VERSION 5.8 ;
BUSBITCHARS "[]" ;
DIVIDERCHAR "/" ;
UNITS
    DATABASE MICRONS 1000 ;
END UNITS

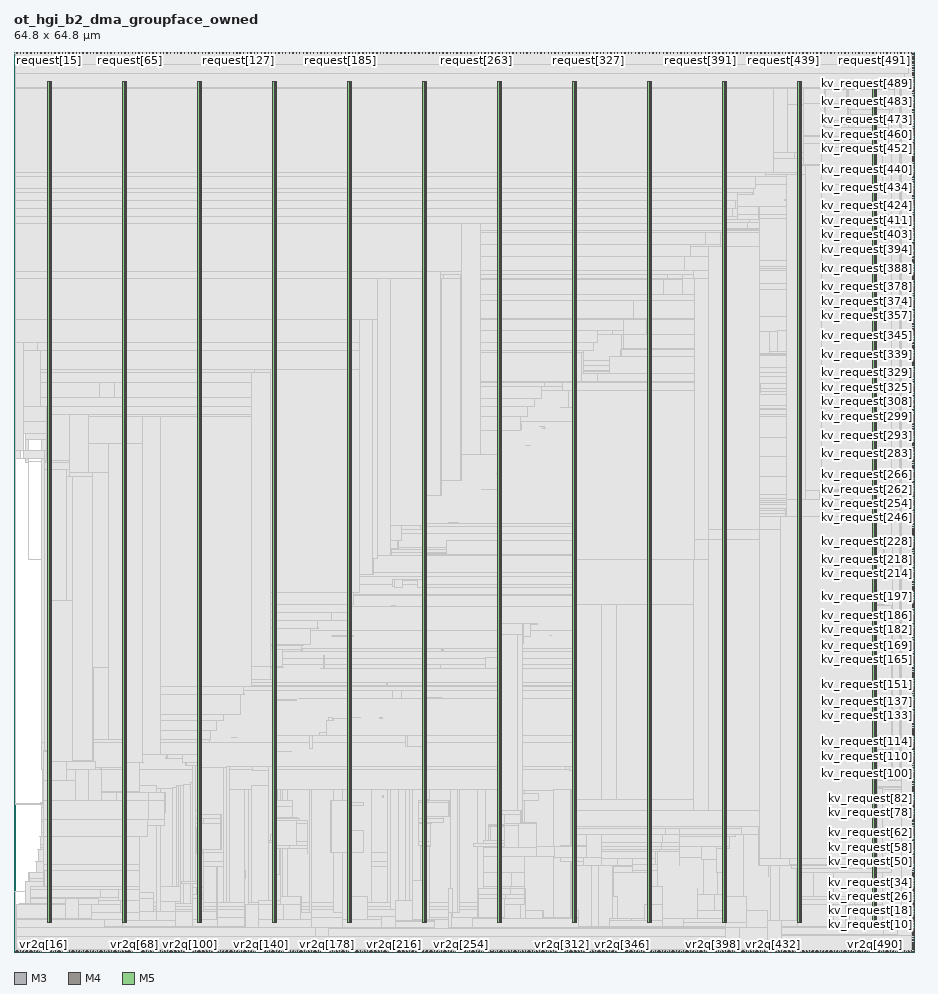
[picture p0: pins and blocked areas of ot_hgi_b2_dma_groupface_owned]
MACRO ot_hgi_b2_dma_groupface_owned
  FOREIGN ot_hgi_b2_dma_groupface_owned 0 0 ;
  CLASS BLOCK ;
  SIZE 64.8 BY 64.8 ;
  PIN clk
    DIRECTION INPUT ;
    USE SIGNAL ;
    PORT
      LAYER M3 ;
        RECT  0.072 64.762 0.09 64.8 ;
    END
  END clk
  PIN kv_owned
    DIRECTION INPUT ;
    USE SIGNAL ;
    PORT
      LAYER M4 ;
        RECT  64.716 0.048 64.8 0.072 ;
    END
  END kv_owned
  PIN kv_request[0]
    DIRECTION INPUT ;
    USE SIGNAL ;
    PORT
      LAYER M4 ;
        RECT  64.716 0.192 64.8 0.216 ;
    END
  END kv_request[0]
  PIN kv_request[100]
    DIRECTION INPUT ;
    USE SIGNAL ;
    PORT
      LAYER M4 ;
        RECT  64.716 12.816 64.8 12.84 ;
    END
  END kv_request[100]
  PIN kv_request[101]
    DIRECTION INPUT ;
    USE SIGNAL ;
    PORT
      LAYER M4 ;
        RECT  64.716 12.912 64.8 12.936 ;
    END
  END kv_request[101]
  PIN kv_request[102]
    DIRECTION INPUT ;
    USE SIGNAL ;
    PORT
      LAYER M4 ;
        RECT  64.716 13.056 64.8 13.08 ;
    END
  END kv_request[102]
  PIN kv_request[103]
    DIRECTION INPUT ;
    USE SIGNAL ;
    PORT
      LAYER M4 ;
        RECT  64.716 13.2 64.8 13.224 ;
    END
  END kv_request[103]
  PIN kv_request[104]
    DIRECTION INPUT ;
    USE SIGNAL ;
    PORT
      LAYER M4 ;
        RECT  64.716 13.296 64.8 13.32 ;
    END
  END kv_request[104]
  PIN kv_request[105]
    DIRECTION INPUT ;
    USE SIGNAL ;
    PORT
      LAYER M4 ;
        RECT  64.716 13.44 64.8 13.464 ;
    END
  END kv_request[105]
  PIN kv_request[106]
    DIRECTION INPUT ;
    USE SIGNAL ;
    PORT
      LAYER M4 ;
        RECT  64.716 13.584 64.8 13.608 ;
    END
  END kv_request[106]
  PIN kv_request[107]
    DIRECTION INPUT ;
    USE SIGNAL ;
    PORT
      LAYER M4 ;
        RECT  64.716 13.68 64.8 13.704 ;
    END
  END kv_request[107]
  PIN kv_request[108]
    DIRECTION INPUT ;
    USE SIGNAL ;
    PORT
      LAYER M4 ;
        RECT  64.716 13.824 64.8 13.848 ;
    END
  END kv_request[108]
  PIN kv_request[109]
    DIRECTION INPUT ;
    USE SIGNAL ;
    PORT
      LAYER M4 ;
        RECT  64.716 13.968 64.8 13.992 ;
    END
  END kv_request[109]
  PIN kv_request[10]
    DIRECTION INPUT ;
    USE SIGNAL ;
    PORT
      LAYER M4 ;
        RECT  64.716 1.44 64.8 1.464 ;
    END
  END kv_request[10]
  PIN kv_request[110]
    DIRECTION INPUT ;
    USE SIGNAL ;
    PORT
      LAYER M4 ;
        RECT  64.716 14.064 64.8 14.088 ;
    END
  END kv_request[110]
  PIN kv_request[111]
    DIRECTION INPUT ;
    USE SIGNAL ;
    PORT
      LAYER M4 ;
        RECT  64.716 14.208 64.8 14.232 ;
    END
  END kv_request[111]
  PIN kv_request[112]
    DIRECTION INPUT ;
    USE SIGNAL ;
    PORT
      LAYER M4 ;
        RECT  64.716 14.304 64.8 14.328 ;
    END
  END kv_request[112]
  PIN kv_request[113]
    DIRECTION INPUT ;
    USE SIGNAL ;
    PORT
      LAYER M4 ;
        RECT  64.716 14.448 64.8 14.472 ;
    END
  END kv_request[113]
  PIN kv_request[114]
    DIRECTION INPUT ;
    USE SIGNAL ;
    PORT
      LAYER M4 ;
        RECT  64.716 14.592 64.8 14.616 ;
    END
  END kv_request[114]
  PIN kv_request[115]
    DIRECTION INPUT ;
    USE SIGNAL ;
    PORT
      LAYER M4 ;
        RECT  64.716 14.688 64.8 14.712 ;
    END
  END kv_request[115]
  PIN kv_request[116]
    DIRECTION INPUT ;
    USE SIGNAL ;
    PORT
      LAYER M4 ;
        RECT  64.716 14.832 64.8 14.856 ;
    END
  END kv_request[116]
  PIN kv_request[117]
    DIRECTION INPUT ;
    USE SIGNAL ;
    PORT
      LAYER M4 ;
        RECT  64.716 14.976 64.8 15 ;
    END
  END kv_request[117]
  PIN kv_request[118]
    DIRECTION INPUT ;
    USE SIGNAL ;
    PORT
      LAYER M4 ;
        RECT  64.716 15.072 64.8 15.096 ;
    END
  END kv_request[118]
  PIN kv_request[119]
    DIRECTION INPUT ;
    USE SIGNAL ;
    PORT
      LAYER M4 ;
        RECT  64.716 15.216 64.8 15.24 ;
    END
  END kv_request[119]
  PIN kv_request[11]
    DIRECTION INPUT ;
    USE SIGNAL ;
    PORT
      LAYER M4 ;
        RECT  64.716 1.584 64.8 1.608 ;
    END
  END kv_request[11]
  PIN kv_request[120]
    DIRECTION INPUT ;
    USE SIGNAL ;
    PORT
      LAYER M4 ;
        RECT  64.716 15.312 64.8 15.336 ;
    END
  END kv_request[120]
  PIN kv_request[121]
    DIRECTION INPUT ;
    USE SIGNAL ;
    PORT
      LAYER M4 ;
        RECT  64.716 15.456 64.8 15.48 ;
    END
  END kv_request[121]
  PIN kv_request[122]
    DIRECTION INPUT ;
    USE SIGNAL ;
    PORT
      LAYER M4 ;
        RECT  64.716 15.6 64.8 15.624 ;
    END
  END kv_request[122]
  PIN kv_request[123]
    DIRECTION INPUT ;
    USE SIGNAL ;
    PORT
      LAYER M4 ;
        RECT  64.716 15.696 64.8 15.72 ;
    END
  END kv_request[123]
  PIN kv_request[124]
    DIRECTION INPUT ;
    USE SIGNAL ;
    PORT
      LAYER M4 ;
        RECT  64.716 15.84 64.8 15.864 ;
    END
  END kv_request[124]
  PIN kv_request[125]
    DIRECTION INPUT ;
    USE SIGNAL ;
    PORT
      LAYER M4 ;
        RECT  64.716 15.984 64.8 16.008 ;
    END
  END kv_request[125]
  PIN kv_request[126]
    DIRECTION INPUT ;
    USE SIGNAL ;
    PORT
      LAYER M4 ;
        RECT  64.716 16.08 64.8 16.104 ;
    END
  END kv_request[126]
  PIN kv_request[127]
    DIRECTION INPUT ;
    USE SIGNAL ;
    PORT
      LAYER M4 ;
        RECT  64.716 16.224 64.8 16.248 ;
    END
  END kv_request[127]
  PIN kv_request[128]
    DIRECTION INPUT ;
    USE SIGNAL ;
    PORT
      LAYER M4 ;
        RECT  64.716 16.368 64.8 16.392 ;
    END
  END kv_request[128]
  PIN kv_request[129]
    DIRECTION INPUT ;
    USE SIGNAL ;
    PORT
      LAYER M4 ;
        RECT  64.716 16.464 64.8 16.488 ;
    END
  END kv_request[129]
  PIN kv_request[12]
    DIRECTION INPUT ;
    USE SIGNAL ;
    PORT
      LAYER M4 ;
        RECT  64.716 1.68 64.8 1.704 ;
    END
  END kv_request[12]
  PIN kv_request[130]
    DIRECTION INPUT ;
    USE SIGNAL ;
    PORT
      LAYER M4 ;
        RECT  64.716 16.608 64.8 16.632 ;
    END
  END kv_request[130]
  PIN kv_request[131]
    DIRECTION INPUT ;
    USE SIGNAL ;
    PORT
      LAYER M4 ;
        RECT  64.716 16.704 64.8 16.728 ;
    END
  END kv_request[131]
  PIN kv_request[132]
    DIRECTION INPUT ;
    USE SIGNAL ;
    PORT
      LAYER M4 ;
        RECT  64.716 16.848 64.8 16.872 ;
    END
  END kv_request[132]
  PIN kv_request[133]
    DIRECTION INPUT ;
    USE SIGNAL ;
    PORT
      LAYER M4 ;
        RECT  64.716 16.992 64.8 17.016 ;
    END
  END kv_request[133]
  PIN kv_request[134]
    DIRECTION INPUT ;
    USE SIGNAL ;
    PORT
      LAYER M4 ;
        RECT  64.716 17.088 64.8 17.112 ;
    END
  END kv_request[134]
  PIN kv_request[135]
    DIRECTION INPUT ;
    USE SIGNAL ;
    PORT
      LAYER M4 ;
        RECT  64.716 17.232 64.8 17.256 ;
    END
  END kv_request[135]
  PIN kv_request[136]
    DIRECTION INPUT ;
    USE SIGNAL ;
    PORT
      LAYER M4 ;
        RECT  64.716 17.376 64.8 17.4 ;
    END
  END kv_request[136]
  PIN kv_request[137]
    DIRECTION INPUT ;
    USE SIGNAL ;
    PORT
      LAYER M4 ;
        RECT  64.716 17.472 64.8 17.496 ;
    END
  END kv_request[137]
  PIN kv_request[138]
    DIRECTION INPUT ;
    USE SIGNAL ;
    PORT
      LAYER M4 ;
        RECT  64.716 17.616 64.8 17.64 ;
    END
  END kv_request[138]
  PIN kv_request[139]
    DIRECTION INPUT ;
    USE SIGNAL ;
    PORT
      LAYER M4 ;
        RECT  64.716 17.712 64.8 17.736 ;
    END
  END kv_request[139]
  PIN kv_request[13]
    DIRECTION INPUT ;
    USE SIGNAL ;
    PORT
      LAYER M4 ;
        RECT  64.716 1.824 64.8 1.848 ;
    END
  END kv_request[13]
  PIN kv_request[140]
    DIRECTION INPUT ;
    USE SIGNAL ;
    PORT
      LAYER M4 ;
        RECT  64.716 17.856 64.8 17.88 ;
    END
  END kv_request[140]
  PIN kv_request[141]
    DIRECTION INPUT ;
    USE SIGNAL ;
    PORT
      LAYER M4 ;
        RECT  64.716 18 64.8 18.024 ;
    END
  END kv_request[141]
  PIN kv_request[142]
    DIRECTION INPUT ;
    USE SIGNAL ;
    PORT
      LAYER M4 ;
        RECT  64.716 18.096 64.8 18.12 ;
    END
  END kv_request[142]
  PIN kv_request[143]
    DIRECTION INPUT ;
    USE SIGNAL ;
    PORT
      LAYER M4 ;
        RECT  64.716 18.24 64.8 18.264 ;
    END
  END kv_request[143]
  PIN kv_request[144]
    DIRECTION INPUT ;
    USE SIGNAL ;
    PORT
      LAYER M4 ;
        RECT  64.716 18.384 64.8 18.408 ;
    END
  END kv_request[144]
  PIN kv_request[145]
    DIRECTION INPUT ;
    USE SIGNAL ;
    PORT
      LAYER M4 ;
        RECT  64.716 18.48 64.8 18.504 ;
    END
  END kv_request[145]
  PIN kv_request[146]
    DIRECTION INPUT ;
    USE SIGNAL ;
    PORT
      LAYER M4 ;
        RECT  64.716 18.624 64.8 18.648 ;
    END
  END kv_request[146]
  PIN kv_request[147]
    DIRECTION INPUT ;
    USE SIGNAL ;
    PORT
      LAYER M4 ;
        RECT  64.716 18.768 64.8 18.792 ;
    END
  END kv_request[147]
  PIN kv_request[148]
    DIRECTION INPUT ;
    USE SIGNAL ;
    PORT
      LAYER M4 ;
        RECT  64.716 18.864 64.8 18.888 ;
    END
  END kv_request[148]
  PIN kv_request[149]
    DIRECTION INPUT ;
    USE SIGNAL ;
    PORT
      LAYER M4 ;
        RECT  64.716 19.008 64.8 19.032 ;
    END
  END kv_request[149]
  PIN kv_request[14]
    DIRECTION INPUT ;
    USE SIGNAL ;
    PORT
      LAYER M4 ;
        RECT  64.716 1.968 64.8 1.992 ;
    END
  END kv_request[14]
  PIN kv_request[150]
    DIRECTION INPUT ;
    USE SIGNAL ;
    PORT
      LAYER M4 ;
        RECT  64.716 19.104 64.8 19.128 ;
    END
  END kv_request[150]
  PIN kv_request[151]
    DIRECTION INPUT ;
    USE SIGNAL ;
    PORT
      LAYER M4 ;
        RECT  64.716 19.248 64.8 19.272 ;
    END
  END kv_request[151]
  PIN kv_request[152]
    DIRECTION INPUT ;
    USE SIGNAL ;
    PORT
      LAYER M4 ;
        RECT  64.716 19.392 64.8 19.416 ;
    END
  END kv_request[152]
  PIN kv_request[153]
    DIRECTION INPUT ;
    USE SIGNAL ;
    PORT
      LAYER M4 ;
        RECT  64.716 19.488 64.8 19.512 ;
    END
  END kv_request[153]
  PIN kv_request[154]
    DIRECTION INPUT ;
    USE SIGNAL ;
    PORT
      LAYER M4 ;
        RECT  64.716 19.632 64.8 19.656 ;
    END
  END kv_request[154]
  PIN kv_request[155]
    DIRECTION INPUT ;
    USE SIGNAL ;
    PORT
      LAYER M4 ;
        RECT  64.716 19.776 64.8 19.8 ;
    END
  END kv_request[155]
  PIN kv_request[156]
    DIRECTION INPUT ;
    USE SIGNAL ;
    PORT
      LAYER M4 ;
        RECT  64.716 19.872 64.8 19.896 ;
    END
  END kv_request[156]
  PIN kv_request[157]
    DIRECTION INPUT ;
    USE SIGNAL ;
    PORT
      LAYER M4 ;
        RECT  64.716 20.016 64.8 20.04 ;
    END
  END kv_request[157]
  PIN kv_request[158]
    DIRECTION INPUT ;
    USE SIGNAL ;
    PORT
      LAYER M4 ;
        RECT  64.716 20.112 64.8 20.136 ;
    END
  END kv_request[158]
  PIN kv_request[159]
    DIRECTION INPUT ;
    USE SIGNAL ;
    PORT
      LAYER M4 ;
        RECT  64.716 20.256 64.8 20.28 ;
    END
  END kv_request[159]
  PIN kv_request[15]
    DIRECTION INPUT ;
    USE SIGNAL ;
    PORT
      LAYER M4 ;
        RECT  64.716 2.064 64.8 2.088 ;
    END
  END kv_request[15]
  PIN kv_request[160]
    DIRECTION INPUT ;
    USE SIGNAL ;
    PORT
      LAYER M4 ;
        RECT  64.716 20.4 64.8 20.424 ;
    END
  END kv_request[160]
  PIN kv_request[161]
    DIRECTION INPUT ;
    USE SIGNAL ;
    PORT
      LAYER M4 ;
        RECT  64.716 20.496 64.8 20.52 ;
    END
  END kv_request[161]
  PIN kv_request[162]
    DIRECTION INPUT ;
    USE SIGNAL ;
    PORT
      LAYER M4 ;
        RECT  64.716 20.64 64.8 20.664 ;
    END
  END kv_request[162]
  PIN kv_request[163]
    DIRECTION INPUT ;
    USE SIGNAL ;
    PORT
      LAYER M4 ;
        RECT  64.716 20.784 64.8 20.808 ;
    END
  END kv_request[163]
  PIN kv_request[164]
    DIRECTION INPUT ;
    USE SIGNAL ;
    PORT
      LAYER M4 ;
        RECT  64.716 20.88 64.8 20.904 ;
    END
  END kv_request[164]
  PIN kv_request[165]
    DIRECTION INPUT ;
    USE SIGNAL ;
    PORT
      LAYER M4 ;
        RECT  64.716 21.024 64.8 21.048 ;
    END
  END kv_request[165]
  PIN kv_request[166]
    DIRECTION INPUT ;
    USE SIGNAL ;
    PORT
      LAYER M4 ;
        RECT  64.716 21.168 64.8 21.192 ;
    END
  END kv_request[166]
  PIN kv_request[167]
    DIRECTION INPUT ;
    USE SIGNAL ;
    PORT
      LAYER M4 ;
        RECT  64.716 21.264 64.8 21.288 ;
    END
  END kv_request[167]
  PIN kv_request[168]
    DIRECTION INPUT ;
    USE SIGNAL ;
    PORT
      LAYER M4 ;
        RECT  64.716 21.408 64.8 21.432 ;
    END
  END kv_request[168]
  PIN kv_request[169]
    DIRECTION INPUT ;
    USE SIGNAL ;
    PORT
      LAYER M4 ;
        RECT  64.716 21.504 64.8 21.528 ;
    END
  END kv_request[169]
  PIN kv_request[16]
    DIRECTION INPUT ;
    USE SIGNAL ;
    PORT
      LAYER M4 ;
        RECT  64.716 2.208 64.8 2.232 ;
    END
  END kv_request[16]
  PIN kv_request[170]
    DIRECTION INPUT ;
    USE SIGNAL ;
    PORT
      LAYER M4 ;
        RECT  64.716 21.648 64.8 21.672 ;
    END
  END kv_request[170]
  PIN kv_request[171]
    DIRECTION INPUT ;
    USE SIGNAL ;
    PORT
      LAYER M4 ;
        RECT  64.716 21.792 64.8 21.816 ;
    END
  END kv_request[171]
  PIN kv_request[172]
    DIRECTION INPUT ;
    USE SIGNAL ;
    PORT
      LAYER M4 ;
        RECT  64.716 21.888 64.8 21.912 ;
    END
  END kv_request[172]
  PIN kv_request[173]
    DIRECTION INPUT ;
    USE SIGNAL ;
    PORT
      LAYER M4 ;
        RECT  64.716 22.032 64.8 22.056 ;
    END
  END kv_request[173]
  PIN kv_request[174]
    DIRECTION INPUT ;
    USE SIGNAL ;
    PORT
      LAYER M4 ;
        RECT  64.716 22.176 64.8 22.2 ;
    END
  END kv_request[174]
  PIN kv_request[175]
    DIRECTION INPUT ;
    USE SIGNAL ;
    PORT
      LAYER M4 ;
        RECT  64.716 22.272 64.8 22.296 ;
    END
  END kv_request[175]
  PIN kv_request[176]
    DIRECTION INPUT ;
    USE SIGNAL ;
    PORT
      LAYER M4 ;
        RECT  64.716 22.416 64.8 22.44 ;
    END
  END kv_request[176]
  PIN kv_request[177]
    DIRECTION INPUT ;
    USE SIGNAL ;
    PORT
      LAYER M4 ;
        RECT  64.716 22.512 64.8 22.536 ;
    END
  END kv_request[177]
  PIN kv_request[178]
    DIRECTION INPUT ;
    USE SIGNAL ;
    PORT
      LAYER M4 ;
        RECT  64.716 22.656 64.8 22.68 ;
    END
  END kv_request[178]
  PIN kv_request[179]
    DIRECTION INPUT ;
    USE SIGNAL ;
    PORT
      LAYER M4 ;
        RECT  64.716 22.8 64.8 22.824 ;
    END
  END kv_request[179]
  PIN kv_request[17]
    DIRECTION INPUT ;
    USE SIGNAL ;
    PORT
      LAYER M4 ;
        RECT  64.716 2.304 64.8 2.328 ;
    END
  END kv_request[17]
  PIN kv_request[180]
    DIRECTION INPUT ;
    USE SIGNAL ;
    PORT
      LAYER M4 ;
        RECT  64.716 22.896 64.8 22.92 ;
    END
  END kv_request[180]
  PIN kv_request[181]
    DIRECTION INPUT ;
    USE SIGNAL ;
    PORT
      LAYER M4 ;
        RECT  64.716 23.04 64.8 23.064 ;
    END
  END kv_request[181]
  PIN kv_request[182]
    DIRECTION INPUT ;
    USE SIGNAL ;
    PORT
      LAYER M4 ;
        RECT  64.716 23.184 64.8 23.208 ;
    END
  END kv_request[182]
  PIN kv_request[183]
    DIRECTION INPUT ;
    USE SIGNAL ;
    PORT
      LAYER M4 ;
        RECT  64.716 23.28 64.8 23.304 ;
    END
  END kv_request[183]
  PIN kv_request[184]
    DIRECTION INPUT ;
    USE SIGNAL ;
    PORT
      LAYER M4 ;
        RECT  64.716 23.424 64.8 23.448 ;
    END
  END kv_request[184]
  PIN kv_request[185]
    DIRECTION INPUT ;
    USE SIGNAL ;
    PORT
      LAYER M4 ;
        RECT  64.716 23.568 64.8 23.592 ;
    END
  END kv_request[185]
  PIN kv_request[186]
    DIRECTION INPUT ;
    USE SIGNAL ;
    PORT
      LAYER M4 ;
        RECT  64.716 23.664 64.8 23.688 ;
    END
  END kv_request[186]
  PIN kv_request[187]
    DIRECTION INPUT ;
    USE SIGNAL ;
    PORT
      LAYER M4 ;
        RECT  64.716 23.808 64.8 23.832 ;
    END
  END kv_request[187]
  PIN kv_request[188]
    DIRECTION INPUT ;
    USE SIGNAL ;
    PORT
      LAYER M4 ;
        RECT  64.716 23.904 64.8 23.928 ;
    END
  END kv_request[188]
  PIN kv_request[189]
    DIRECTION INPUT ;
    USE SIGNAL ;
    PORT
      LAYER M4 ;
        RECT  64.716 24.048 64.8 24.072 ;
    END
  END kv_request[189]
  PIN kv_request[18]
    DIRECTION INPUT ;
    USE SIGNAL ;
    PORT
      LAYER M4 ;
        RECT  64.716 2.448 64.8 2.472 ;
    END
  END kv_request[18]
  PIN kv_request[190]
    DIRECTION INPUT ;
    USE SIGNAL ;
    PORT
      LAYER M4 ;
        RECT  64.716 24.192 64.8 24.216 ;
    END
  END kv_request[190]
  PIN kv_request[191]
    DIRECTION INPUT ;
    USE SIGNAL ;
    PORT
      LAYER M4 ;
        RECT  64.716 24.288 64.8 24.312 ;
    END
  END kv_request[191]
  PIN kv_request[192]
    DIRECTION INPUT ;
    USE SIGNAL ;
    PORT
      LAYER M4 ;
        RECT  64.716 24.432 64.8 24.456 ;
    END
  END kv_request[192]
  PIN kv_request[193]
    DIRECTION INPUT ;
    USE SIGNAL ;
    PORT
      LAYER M4 ;
        RECT  64.716 24.576 64.8 24.6 ;
    END
  END kv_request[193]
  PIN kv_request[194]
    DIRECTION INPUT ;
    USE SIGNAL ;
    PORT
      LAYER M4 ;
        RECT  64.716 24.672 64.8 24.696 ;
    END
  END kv_request[194]
  PIN kv_request[195]
    DIRECTION INPUT ;
    USE SIGNAL ;
    PORT
      LAYER M4 ;
        RECT  64.716 24.816 64.8 24.84 ;
    END
  END kv_request[195]
  PIN kv_request[196]
    DIRECTION INPUT ;
    USE SIGNAL ;
    PORT
      LAYER M4 ;
        RECT  64.716 24.912 64.8 24.936 ;
    END
  END kv_request[196]
  PIN kv_request[197]
    DIRECTION INPUT ;
    USE SIGNAL ;
    PORT
      LAYER M4 ;
        RECT  64.716 25.056 64.8 25.08 ;
    END
  END kv_request[197]
  PIN kv_request[198]
    DIRECTION INPUT ;
    USE SIGNAL ;
    PORT
      LAYER M4 ;
        RECT  64.716 25.2 64.8 25.224 ;
    END
  END kv_request[198]
  PIN kv_request[199]
    DIRECTION INPUT ;
    USE SIGNAL ;
    PORT
      LAYER M4 ;
        RECT  64.716 25.296 64.8 25.32 ;
    END
  END kv_request[199]
  PIN kv_request[19]
    DIRECTION INPUT ;
    USE SIGNAL ;
    PORT
      LAYER M4 ;
        RECT  64.716 2.592 64.8 2.616 ;
    END
  END kv_request[19]
  PIN kv_request[1]
    DIRECTION INPUT ;
    USE SIGNAL ;
    PORT
      LAYER M4 ;
        RECT  64.716 0.288 64.8 0.312 ;
    END
  END kv_request[1]
  PIN kv_request[200]
    DIRECTION INPUT ;
    USE SIGNAL ;
    PORT
      LAYER M4 ;
        RECT  64.716 25.44 64.8 25.464 ;
    END
  END kv_request[200]
  PIN kv_request[201]
    DIRECTION INPUT ;
    USE SIGNAL ;
    PORT
      LAYER M4 ;
        RECT  64.716 25.584 64.8 25.608 ;
    END
  END kv_request[201]
  PIN kv_request[202]
    DIRECTION INPUT ;
    USE SIGNAL ;
    PORT
      LAYER M4 ;
        RECT  64.716 25.68 64.8 25.704 ;
    END
  END kv_request[202]
  PIN kv_request[203]
    DIRECTION INPUT ;
    USE SIGNAL ;
    PORT
      LAYER M4 ;
        RECT  64.716 25.824 64.8 25.848 ;
    END
  END kv_request[203]
  PIN kv_request[204]
    DIRECTION INPUT ;
    USE SIGNAL ;
    PORT
      LAYER M4 ;
        RECT  64.716 25.968 64.8 25.992 ;
    END
  END kv_request[204]
  PIN kv_request[205]
    DIRECTION INPUT ;
    USE SIGNAL ;
    PORT
      LAYER M4 ;
        RECT  64.716 26.064 64.8 26.088 ;
    END
  END kv_request[205]
  PIN kv_request[206]
    DIRECTION INPUT ;
    USE SIGNAL ;
    PORT
      LAYER M4 ;
        RECT  64.716 26.208 64.8 26.232 ;
    END
  END kv_request[206]
  PIN kv_request[207]
    DIRECTION INPUT ;
    USE SIGNAL ;
    PORT
      LAYER M4 ;
        RECT  64.716 26.304 64.8 26.328 ;
    END
  END kv_request[207]
  PIN kv_request[208]
    DIRECTION INPUT ;
    USE SIGNAL ;
    PORT
      LAYER M4 ;
        RECT  64.716 26.448 64.8 26.472 ;
    END
  END kv_request[208]
  PIN kv_request[209]
    DIRECTION INPUT ;
    USE SIGNAL ;
    PORT
      LAYER M4 ;
        RECT  64.716 26.592 64.8 26.616 ;
    END
  END kv_request[209]
  PIN kv_request[20]
    DIRECTION INPUT ;
    USE SIGNAL ;
    PORT
      LAYER M4 ;
        RECT  64.716 2.688 64.8 2.712 ;
    END
  END kv_request[20]
  PIN kv_request[210]
    DIRECTION INPUT ;
    USE SIGNAL ;
    PORT
      LAYER M4 ;
        RECT  64.716 26.688 64.8 26.712 ;
    END
  END kv_request[210]
  PIN kv_request[211]
    DIRECTION INPUT ;
    USE SIGNAL ;
    PORT
      LAYER M4 ;
        RECT  64.716 26.832 64.8 26.856 ;
    END
  END kv_request[211]
  PIN kv_request[212]
    DIRECTION INPUT ;
    USE SIGNAL ;
    PORT
      LAYER M4 ;
        RECT  64.716 26.976 64.8 27 ;
    END
  END kv_request[212]
  PIN kv_request[213]
    DIRECTION INPUT ;
    USE SIGNAL ;
    PORT
      LAYER M4 ;
        RECT  64.716 27.072 64.8 27.096 ;
    END
  END kv_request[213]
  PIN kv_request[214]
    DIRECTION INPUT ;
    USE SIGNAL ;
    PORT
      LAYER M4 ;
        RECT  64.716 27.216 64.8 27.24 ;
    END
  END kv_request[214]
  PIN kv_request[215]
    DIRECTION INPUT ;
    USE SIGNAL ;
    PORT
      LAYER M4 ;
        RECT  64.716 27.312 64.8 27.336 ;
    END
  END kv_request[215]
  PIN kv_request[216]
    DIRECTION INPUT ;
    USE SIGNAL ;
    PORT
      LAYER M4 ;
        RECT  64.716 27.456 64.8 27.48 ;
    END
  END kv_request[216]
  PIN kv_request[217]
    DIRECTION INPUT ;
    USE SIGNAL ;
    PORT
      LAYER M4 ;
        RECT  64.716 27.6 64.8 27.624 ;
    END
  END kv_request[217]
  PIN kv_request[218]
    DIRECTION INPUT ;
    USE SIGNAL ;
    PORT
      LAYER M4 ;
        RECT  64.716 27.696 64.8 27.72 ;
    END
  END kv_request[218]
  PIN kv_request[219]
    DIRECTION INPUT ;
    USE SIGNAL ;
    PORT
      LAYER M4 ;
        RECT  64.716 27.84 64.8 27.864 ;
    END
  END kv_request[219]
  PIN kv_request[21]
    DIRECTION INPUT ;
    USE SIGNAL ;
    PORT
      LAYER M4 ;
        RECT  64.716 2.832 64.8 2.856 ;
    END
  END kv_request[21]
  PIN kv_request[220]
    DIRECTION INPUT ;
    USE SIGNAL ;
    PORT
      LAYER M4 ;
        RECT  64.716 27.984 64.8 28.008 ;
    END
  END kv_request[220]
  PIN kv_request[221]
    DIRECTION INPUT ;
    USE SIGNAL ;
    PORT
      LAYER M4 ;
        RECT  64.716 28.08 64.8 28.104 ;
    END
  END kv_request[221]
  PIN kv_request[222]
    DIRECTION INPUT ;
    USE SIGNAL ;
    PORT
      LAYER M4 ;
        RECT  64.716 28.224 64.8 28.248 ;
    END
  END kv_request[222]
  PIN kv_request[223]
    DIRECTION INPUT ;
    USE SIGNAL ;
    PORT
      LAYER M4 ;
        RECT  64.716 28.368 64.8 28.392 ;
    END
  END kv_request[223]
  PIN kv_request[224]
    DIRECTION INPUT ;
    USE SIGNAL ;
    PORT
      LAYER M4 ;
        RECT  64.716 28.464 64.8 28.488 ;
    END
  END kv_request[224]
  PIN kv_request[225]
    DIRECTION INPUT ;
    USE SIGNAL ;
    PORT
      LAYER M4 ;
        RECT  64.716 28.608 64.8 28.632 ;
    END
  END kv_request[225]
  PIN kv_request[226]
    DIRECTION INPUT ;
    USE SIGNAL ;
    PORT
      LAYER M4 ;
        RECT  64.716 28.704 64.8 28.728 ;
    END
  END kv_request[226]
  PIN kv_request[227]
    DIRECTION INPUT ;
    USE SIGNAL ;
    PORT
      LAYER M4 ;
        RECT  64.716 28.848 64.8 28.872 ;
    END
  END kv_request[227]
  PIN kv_request[228]
    DIRECTION INPUT ;
    USE SIGNAL ;
    PORT
      LAYER M4 ;
        RECT  64.716 28.992 64.8 29.016 ;
    END
  END kv_request[228]
  PIN kv_request[229]
    DIRECTION INPUT ;
    USE SIGNAL ;
    PORT
      LAYER M4 ;
        RECT  64.716 29.088 64.8 29.112 ;
    END
  END kv_request[229]
  PIN kv_request[22]
    DIRECTION INPUT ;
    USE SIGNAL ;
    PORT
      LAYER M4 ;
        RECT  64.716 2.976 64.8 3 ;
    END
  END kv_request[22]
  PIN kv_request[230]
    DIRECTION INPUT ;
    USE SIGNAL ;
    PORT
      LAYER M4 ;
        RECT  64.716 29.232 64.8 29.256 ;
    END
  END kv_request[230]
  PIN kv_request[231]
    DIRECTION INPUT ;
    USE SIGNAL ;
    PORT
      LAYER M4 ;
        RECT  64.716 29.376 64.8 29.4 ;
    END
  END kv_request[231]
  PIN kv_request[232]
    DIRECTION INPUT ;
    USE SIGNAL ;
    PORT
      LAYER M4 ;
        RECT  64.716 29.472 64.8 29.496 ;
    END
  END kv_request[232]
  PIN kv_request[233]
    DIRECTION INPUT ;
    USE SIGNAL ;
    PORT
      LAYER M4 ;
        RECT  64.716 29.616 64.8 29.64 ;
    END
  END kv_request[233]
  PIN kv_request[234]
    DIRECTION INPUT ;
    USE SIGNAL ;
    PORT
      LAYER M4 ;
        RECT  64.716 29.712 64.8 29.736 ;
    END
  END kv_request[234]
  PIN kv_request[235]
    DIRECTION INPUT ;
    USE SIGNAL ;
    PORT
      LAYER M4 ;
        RECT  64.716 29.856 64.8 29.88 ;
    END
  END kv_request[235]
  PIN kv_request[236]
    DIRECTION INPUT ;
    USE SIGNAL ;
    PORT
      LAYER M4 ;
        RECT  64.716 30 64.8 30.024 ;
    END
  END kv_request[236]
  PIN kv_request[237]
    DIRECTION INPUT ;
    USE SIGNAL ;
    PORT
      LAYER M4 ;
        RECT  64.716 30.096 64.8 30.12 ;
    END
  END kv_request[237]
  PIN kv_request[238]
    DIRECTION INPUT ;
    USE SIGNAL ;
    PORT
      LAYER M4 ;
        RECT  64.716 30.24 64.8 30.264 ;
    END
  END kv_request[238]
  PIN kv_request[239]
    DIRECTION INPUT ;
    USE SIGNAL ;
    PORT
      LAYER M4 ;
        RECT  64.716 30.384 64.8 30.408 ;
    END
  END kv_request[239]
  PIN kv_request[23]
    DIRECTION INPUT ;
    USE SIGNAL ;
    PORT
      LAYER M4 ;
        RECT  64.716 3.072 64.8 3.096 ;
    END
  END kv_request[23]
  PIN kv_request[240]
    DIRECTION INPUT ;
    USE SIGNAL ;
    PORT
      LAYER M4 ;
        RECT  64.716 30.48 64.8 30.504 ;
    END
  END kv_request[240]
  PIN kv_request[241]
    DIRECTION INPUT ;
    USE SIGNAL ;
    PORT
      LAYER M4 ;
        RECT  64.716 30.624 64.8 30.648 ;
    END
  END kv_request[241]
  PIN kv_request[242]
    DIRECTION INPUT ;
    USE SIGNAL ;
    PORT
      LAYER M4 ;
        RECT  64.716 30.768 64.8 30.792 ;
    END
  END kv_request[242]
  PIN kv_request[243]
    DIRECTION INPUT ;
    USE SIGNAL ;
    PORT
      LAYER M4 ;
        RECT  64.716 30.864 64.8 30.888 ;
    END
  END kv_request[243]
  PIN kv_request[244]
    DIRECTION INPUT ;
    USE SIGNAL ;
    PORT
      LAYER M4 ;
        RECT  64.716 31.008 64.8 31.032 ;
    END
  END kv_request[244]
  PIN kv_request[245]
    DIRECTION INPUT ;
    USE SIGNAL ;
    PORT
      LAYER M4 ;
        RECT  64.716 31.104 64.8 31.128 ;
    END
  END kv_request[245]
  PIN kv_request[246]
    DIRECTION INPUT ;
    USE SIGNAL ;
    PORT
      LAYER M4 ;
        RECT  64.716 31.248 64.8 31.272 ;
    END
  END kv_request[246]
  PIN kv_request[247]
    DIRECTION INPUT ;
    USE SIGNAL ;
    PORT
      LAYER M4 ;
        RECT  64.716 31.392 64.8 31.416 ;
    END
  END kv_request[247]
  PIN kv_request[248]
    DIRECTION INPUT ;
    USE SIGNAL ;
    PORT
      LAYER M4 ;
        RECT  64.716 31.488 64.8 31.512 ;
    END
  END kv_request[248]
  PIN kv_request[249]
    DIRECTION INPUT ;
    USE SIGNAL ;
    PORT
      LAYER M4 ;
        RECT  64.716 31.632 64.8 31.656 ;
    END
  END kv_request[249]
  PIN kv_request[24]
    DIRECTION INPUT ;
    USE SIGNAL ;
    PORT
      LAYER M4 ;
        RECT  64.716 3.216 64.8 3.24 ;
    END
  END kv_request[24]
  PIN kv_request[250]
    DIRECTION INPUT ;
    USE SIGNAL ;
    PORT
      LAYER M4 ;
        RECT  64.716 31.776 64.8 31.8 ;
    END
  END kv_request[250]
  PIN kv_request[251]
    DIRECTION INPUT ;
    USE SIGNAL ;
    PORT
      LAYER M4 ;
        RECT  64.716 31.872 64.8 31.896 ;
    END
  END kv_request[251]
  PIN kv_request[252]
    DIRECTION INPUT ;
    USE SIGNAL ;
    PORT
      LAYER M4 ;
        RECT  64.716 32.016 64.8 32.04 ;
    END
  END kv_request[252]
  PIN kv_request[253]
    DIRECTION INPUT ;
    USE SIGNAL ;
    PORT
      LAYER M4 ;
        RECT  64.716 32.112 64.8 32.136 ;
    END
  END kv_request[253]
  PIN kv_request[254]
    DIRECTION INPUT ;
    USE SIGNAL ;
    PORT
      LAYER M4 ;
        RECT  64.716 32.256 64.8 32.28 ;
    END
  END kv_request[254]
  PIN kv_request[255]
    DIRECTION INPUT ;
    USE SIGNAL ;
    PORT
      LAYER M4 ;
        RECT  64.716 32.4 64.8 32.424 ;
    END
  END kv_request[255]
  PIN kv_request[256]
    DIRECTION INPUT ;
    USE SIGNAL ;
    PORT
      LAYER M4 ;
        RECT  64.716 32.496 64.8 32.52 ;
    END
  END kv_request[256]
  PIN kv_request[257]
    DIRECTION INPUT ;
    USE SIGNAL ;
    PORT
      LAYER M4 ;
        RECT  64.716 32.64 64.8 32.664 ;
    END
  END kv_request[257]
  PIN kv_request[258]
    DIRECTION INPUT ;
    USE SIGNAL ;
    PORT
      LAYER M4 ;
        RECT  64.716 32.784 64.8 32.808 ;
    END
  END kv_request[258]
  PIN kv_request[259]
    DIRECTION INPUT ;
    USE SIGNAL ;
    PORT
      LAYER M4 ;
        RECT  64.716 32.88 64.8 32.904 ;
    END
  END kv_request[259]
  PIN kv_request[25]
    DIRECTION INPUT ;
    USE SIGNAL ;
    PORT
      LAYER M4 ;
        RECT  64.716 3.312 64.8 3.336 ;
    END
  END kv_request[25]
  PIN kv_request[260]
    DIRECTION INPUT ;
    USE SIGNAL ;
    PORT
      LAYER M4 ;
        RECT  64.716 33.024 64.8 33.048 ;
    END
  END kv_request[260]
  PIN kv_request[261]
    DIRECTION INPUT ;
    USE SIGNAL ;
    PORT
      LAYER M4 ;
        RECT  64.716 33.168 64.8 33.192 ;
    END
  END kv_request[261]
  PIN kv_request[262]
    DIRECTION INPUT ;
    USE SIGNAL ;
    PORT
      LAYER M4 ;
        RECT  64.716 33.264 64.8 33.288 ;
    END
  END kv_request[262]
  PIN kv_request[263]
    DIRECTION INPUT ;
    USE SIGNAL ;
    PORT
      LAYER M4 ;
        RECT  64.716 33.408 64.8 33.432 ;
    END
  END kv_request[263]
  PIN kv_request[264]
    DIRECTION INPUT ;
    USE SIGNAL ;
    PORT
      LAYER M4 ;
        RECT  64.716 33.504 64.8 33.528 ;
    END
  END kv_request[264]
  PIN kv_request[265]
    DIRECTION INPUT ;
    USE SIGNAL ;
    PORT
      LAYER M4 ;
        RECT  64.716 33.648 64.8 33.672 ;
    END
  END kv_request[265]
  PIN kv_request[266]
    DIRECTION INPUT ;
    USE SIGNAL ;
    PORT
      LAYER M4 ;
        RECT  64.716 33.792 64.8 33.816 ;
    END
  END kv_request[266]
  PIN kv_request[267]
    DIRECTION INPUT ;
    USE SIGNAL ;
    PORT
      LAYER M4 ;
        RECT  64.716 33.888 64.8 33.912 ;
    END
  END kv_request[267]
  PIN kv_request[268]
    DIRECTION INPUT ;
    USE SIGNAL ;
    PORT
      LAYER M4 ;
        RECT  64.716 34.032 64.8 34.056 ;
    END
  END kv_request[268]
  PIN kv_request[269]
    DIRECTION INPUT ;
    USE SIGNAL ;
    PORT
      LAYER M4 ;
        RECT  64.716 34.176 64.8 34.2 ;
    END
  END kv_request[269]
  PIN kv_request[26]
    DIRECTION INPUT ;
    USE SIGNAL ;
    PORT
      LAYER M4 ;
        RECT  64.716 3.456 64.8 3.48 ;
    END
  END kv_request[26]
  PIN kv_request[270]
    DIRECTION INPUT ;
    USE SIGNAL ;
    PORT
      LAYER M4 ;
        RECT  64.716 34.272 64.8 34.296 ;
    END
  END kv_request[270]
  PIN kv_request[271]
    DIRECTION INPUT ;
    USE SIGNAL ;
    PORT
      LAYER M4 ;
        RECT  64.716 34.416 64.8 34.44 ;
    END
  END kv_request[271]
  PIN kv_request[272]
    DIRECTION INPUT ;
    USE SIGNAL ;
    PORT
      LAYER M4 ;
        RECT  64.716 34.512 64.8 34.536 ;
    END
  END kv_request[272]
  PIN kv_request[273]
    DIRECTION INPUT ;
    USE SIGNAL ;
    PORT
      LAYER M4 ;
        RECT  64.716 34.656 64.8 34.68 ;
    END
  END kv_request[273]
  PIN kv_request[274]
    DIRECTION INPUT ;
    USE SIGNAL ;
    PORT
      LAYER M4 ;
        RECT  64.716 34.8 64.8 34.824 ;
    END
  END kv_request[274]
  PIN kv_request[275]
    DIRECTION INPUT ;
    USE SIGNAL ;
    PORT
      LAYER M4 ;
        RECT  64.716 34.896 64.8 34.92 ;
    END
  END kv_request[275]
  PIN kv_request[276]
    DIRECTION INPUT ;
    USE SIGNAL ;
    PORT
      LAYER M4 ;
        RECT  64.716 35.04 64.8 35.064 ;
    END
  END kv_request[276]
  PIN kv_request[277]
    DIRECTION INPUT ;
    USE SIGNAL ;
    PORT
      LAYER M4 ;
        RECT  64.716 35.184 64.8 35.208 ;
    END
  END kv_request[277]
  PIN kv_request[278]
    DIRECTION INPUT ;
    USE SIGNAL ;
    PORT
      LAYER M4 ;
        RECT  64.716 35.28 64.8 35.304 ;
    END
  END kv_request[278]
  PIN kv_request[279]
    DIRECTION INPUT ;
    USE SIGNAL ;
    PORT
      LAYER M4 ;
        RECT  64.716 35.424 64.8 35.448 ;
    END
  END kv_request[279]
  PIN kv_request[27]
    DIRECTION INPUT ;
    USE SIGNAL ;
    PORT
      LAYER M4 ;
        RECT  64.716 3.6 64.8 3.624 ;
    END
  END kv_request[27]
  PIN kv_request[280]
    DIRECTION INPUT ;
    USE SIGNAL ;
    PORT
      LAYER M4 ;
        RECT  64.716 35.568 64.8 35.592 ;
    END
  END kv_request[280]
  PIN kv_request[281]
    DIRECTION INPUT ;
    USE SIGNAL ;
    PORT
      LAYER M4 ;
        RECT  64.716 35.664 64.8 35.688 ;
    END
  END kv_request[281]
  PIN kv_request[282]
    DIRECTION INPUT ;
    USE SIGNAL ;
    PORT
      LAYER M4 ;
        RECT  64.716 35.808 64.8 35.832 ;
    END
  END kv_request[282]
  PIN kv_request[283]
    DIRECTION INPUT ;
    USE SIGNAL ;
    PORT
      LAYER M4 ;
        RECT  64.716 35.904 64.8 35.928 ;
    END
  END kv_request[283]
  PIN kv_request[284]
    DIRECTION INPUT ;
    USE SIGNAL ;
    PORT
      LAYER M4 ;
        RECT  64.716 36.048 64.8 36.072 ;
    END
  END kv_request[284]
  PIN kv_request[285]
    DIRECTION INPUT ;
    USE SIGNAL ;
    PORT
      LAYER M4 ;
        RECT  64.716 36.192 64.8 36.216 ;
    END
  END kv_request[285]
  PIN kv_request[286]
    DIRECTION INPUT ;
    USE SIGNAL ;
    PORT
      LAYER M4 ;
        RECT  64.716 36.288 64.8 36.312 ;
    END
  END kv_request[286]
  PIN kv_request[287]
    DIRECTION INPUT ;
    USE SIGNAL ;
    PORT
      LAYER M4 ;
        RECT  64.716 36.432 64.8 36.456 ;
    END
  END kv_request[287]
  PIN kv_request[288]
    DIRECTION INPUT ;
    USE SIGNAL ;
    PORT
      LAYER M4 ;
        RECT  64.716 36.576 64.8 36.6 ;
    END
  END kv_request[288]
  PIN kv_request[289]
    DIRECTION INPUT ;
    USE SIGNAL ;
    PORT
      LAYER M4 ;
        RECT  64.716 36.672 64.8 36.696 ;
    END
  END kv_request[289]
  PIN kv_request[28]
    DIRECTION INPUT ;
    USE SIGNAL ;
    PORT
      LAYER M4 ;
        RECT  64.716 3.696 64.8 3.72 ;
    END
  END kv_request[28]
  PIN kv_request[290]
    DIRECTION INPUT ;
    USE SIGNAL ;
    PORT
      LAYER M4 ;
        RECT  64.716 36.816 64.8 36.84 ;
    END
  END kv_request[290]
  PIN kv_request[291]
    DIRECTION INPUT ;
    USE SIGNAL ;
    PORT
      LAYER M4 ;
        RECT  64.716 36.912 64.8 36.936 ;
    END
  END kv_request[291]
  PIN kv_request[292]
    DIRECTION INPUT ;
    USE SIGNAL ;
    PORT
      LAYER M4 ;
        RECT  64.716 37.056 64.8 37.08 ;
    END
  END kv_request[292]
  PIN kv_request[293]
    DIRECTION INPUT ;
    USE SIGNAL ;
    PORT
      LAYER M4 ;
        RECT  64.716 37.2 64.8 37.224 ;
    END
  END kv_request[293]
  PIN kv_request[294]
    DIRECTION INPUT ;
    USE SIGNAL ;
    PORT
      LAYER M4 ;
        RECT  64.716 37.296 64.8 37.32 ;
    END
  END kv_request[294]
  PIN kv_request[295]
    DIRECTION INPUT ;
    USE SIGNAL ;
    PORT
      LAYER M4 ;
        RECT  64.716 37.44 64.8 37.464 ;
    END
  END kv_request[295]
  PIN kv_request[296]
    DIRECTION INPUT ;
    USE SIGNAL ;
    PORT
      LAYER M4 ;
        RECT  64.716 37.584 64.8 37.608 ;
    END
  END kv_request[296]
  PIN kv_request[297]
    DIRECTION INPUT ;
    USE SIGNAL ;
    PORT
      LAYER M4 ;
        RECT  64.716 37.68 64.8 37.704 ;
    END
  END kv_request[297]
  PIN kv_request[298]
    DIRECTION INPUT ;
    USE SIGNAL ;
    PORT
      LAYER M4 ;
        RECT  64.716 37.824 64.8 37.848 ;
    END
  END kv_request[298]
  PIN kv_request[299]
    DIRECTION INPUT ;
    USE SIGNAL ;
    PORT
      LAYER M4 ;
        RECT  64.716 37.968 64.8 37.992 ;
    END
  END kv_request[299]
  PIN kv_request[29]
    DIRECTION INPUT ;
    USE SIGNAL ;
    PORT
      LAYER M4 ;
        RECT  64.716 3.84 64.8 3.864 ;
    END
  END kv_request[29]
  PIN kv_request[2]
    DIRECTION INPUT ;
    USE SIGNAL ;
    PORT
      LAYER M4 ;
        RECT  64.716 0.432 64.8 0.456 ;
    END
  END kv_request[2]
  PIN kv_request[300]
    DIRECTION INPUT ;
    USE SIGNAL ;
    PORT
      LAYER M4 ;
        RECT  64.716 38.064 64.8 38.088 ;
    END
  END kv_request[300]
  PIN kv_request[301]
    DIRECTION INPUT ;
    USE SIGNAL ;
    PORT
      LAYER M4 ;
        RECT  64.716 38.208 64.8 38.232 ;
    END
  END kv_request[301]
  PIN kv_request[302]
    DIRECTION INPUT ;
    USE SIGNAL ;
    PORT
      LAYER M4 ;
        RECT  64.716 38.304 64.8 38.328 ;
    END
  END kv_request[302]
  PIN kv_request[303]
    DIRECTION INPUT ;
    USE SIGNAL ;
    PORT
      LAYER M4 ;
        RECT  64.716 38.448 64.8 38.472 ;
    END
  END kv_request[303]
  PIN kv_request[304]
    DIRECTION INPUT ;
    USE SIGNAL ;
    PORT
      LAYER M4 ;
        RECT  64.716 38.592 64.8 38.616 ;
    END
  END kv_request[304]
  PIN kv_request[305]
    DIRECTION INPUT ;
    USE SIGNAL ;
    PORT
      LAYER M4 ;
        RECT  64.716 38.688 64.8 38.712 ;
    END
  END kv_request[305]
  PIN kv_request[306]
    DIRECTION INPUT ;
    USE SIGNAL ;
    PORT
      LAYER M4 ;
        RECT  64.716 38.832 64.8 38.856 ;
    END
  END kv_request[306]
  PIN kv_request[307]
    DIRECTION INPUT ;
    USE SIGNAL ;
    PORT
      LAYER M4 ;
        RECT  64.716 38.976 64.8 39 ;
    END
  END kv_request[307]
  PIN kv_request[308]
    DIRECTION INPUT ;
    USE SIGNAL ;
    PORT
      LAYER M4 ;
        RECT  64.716 39.072 64.8 39.096 ;
    END
  END kv_request[308]
  PIN kv_request[309]
    DIRECTION INPUT ;
    USE SIGNAL ;
    PORT
      LAYER M4 ;
        RECT  64.716 39.216 64.8 39.24 ;
    END
  END kv_request[309]
  PIN kv_request[30]
    DIRECTION INPUT ;
    USE SIGNAL ;
    PORT
      LAYER M4 ;
        RECT  64.716 3.984 64.8 4.008 ;
    END
  END kv_request[30]
  PIN kv_request[310]
    DIRECTION INPUT ;
    USE SIGNAL ;
    PORT
      LAYER M4 ;
        RECT  64.716 39.312 64.8 39.336 ;
    END
  END kv_request[310]
  PIN kv_request[311]
    DIRECTION INPUT ;
    USE SIGNAL ;
    PORT
      LAYER M4 ;
        RECT  64.716 39.456 64.8 39.48 ;
    END
  END kv_request[311]
  PIN kv_request[312]
    DIRECTION INPUT ;
    USE SIGNAL ;
    PORT
      LAYER M4 ;
        RECT  64.716 39.6 64.8 39.624 ;
    END
  END kv_request[312]
  PIN kv_request[313]
    DIRECTION INPUT ;
    USE SIGNAL ;
    PORT
      LAYER M4 ;
        RECT  64.716 39.696 64.8 39.72 ;
    END
  END kv_request[313]
  PIN kv_request[314]
    DIRECTION INPUT ;
    USE SIGNAL ;
    PORT
      LAYER M4 ;
        RECT  64.716 39.84 64.8 39.864 ;
    END
  END kv_request[314]
  PIN kv_request[315]
    DIRECTION INPUT ;
    USE SIGNAL ;
    PORT
      LAYER M4 ;
        RECT  64.716 39.984 64.8 40.008 ;
    END
  END kv_request[315]
  PIN kv_request[316]
    DIRECTION INPUT ;
    USE SIGNAL ;
    PORT
      LAYER M4 ;
        RECT  64.716 40.08 64.8 40.104 ;
    END
  END kv_request[316]
  PIN kv_request[317]
    DIRECTION INPUT ;
    USE SIGNAL ;
    PORT
      LAYER M4 ;
        RECT  64.716 40.224 64.8 40.248 ;
    END
  END kv_request[317]
  PIN kv_request[318]
    DIRECTION INPUT ;
    USE SIGNAL ;
    PORT
      LAYER M4 ;
        RECT  64.716 40.368 64.8 40.392 ;
    END
  END kv_request[318]
  PIN kv_request[319]
    DIRECTION INPUT ;
    USE SIGNAL ;
    PORT
      LAYER M4 ;
        RECT  64.716 40.464 64.8 40.488 ;
    END
  END kv_request[319]
  PIN kv_request[31]
    DIRECTION INPUT ;
    USE SIGNAL ;
    PORT
      LAYER M4 ;
        RECT  64.716 4.08 64.8 4.104 ;
    END
  END kv_request[31]
  PIN kv_request[320]
    DIRECTION INPUT ;
    USE SIGNAL ;
    PORT
      LAYER M4 ;
        RECT  64.716 40.608 64.8 40.632 ;
    END
  END kv_request[320]
  PIN kv_request[321]
    DIRECTION INPUT ;
    USE SIGNAL ;
    PORT
      LAYER M4 ;
        RECT  64.716 40.704 64.8 40.728 ;
    END
  END kv_request[321]
  PIN kv_request[322]
    DIRECTION INPUT ;
    USE SIGNAL ;
    PORT
      LAYER M4 ;
        RECT  64.716 40.848 64.8 40.872 ;
    END
  END kv_request[322]
  PIN kv_request[323]
    DIRECTION INPUT ;
    USE SIGNAL ;
    PORT
      LAYER M4 ;
        RECT  64.716 40.992 64.8 41.016 ;
    END
  END kv_request[323]
  PIN kv_request[324]
    DIRECTION INPUT ;
    USE SIGNAL ;
    PORT
      LAYER M4 ;
        RECT  64.716 41.088 64.8 41.112 ;
    END
  END kv_request[324]
  PIN kv_request[325]
    DIRECTION INPUT ;
    USE SIGNAL ;
    PORT
      LAYER M4 ;
        RECT  64.716 41.232 64.8 41.256 ;
    END
  END kv_request[325]
  PIN kv_request[326]
    DIRECTION INPUT ;
    USE SIGNAL ;
    PORT
      LAYER M4 ;
        RECT  64.716 41.376 64.8 41.4 ;
    END
  END kv_request[326]
  PIN kv_request[327]
    DIRECTION INPUT ;
    USE SIGNAL ;
    PORT
      LAYER M4 ;
        RECT  64.716 41.472 64.8 41.496 ;
    END
  END kv_request[327]
  PIN kv_request[328]
    DIRECTION INPUT ;
    USE SIGNAL ;
    PORT
      LAYER M4 ;
        RECT  64.716 41.616 64.8 41.64 ;
    END
  END kv_request[328]
  PIN kv_request[329]
    DIRECTION INPUT ;
    USE SIGNAL ;
    PORT
      LAYER M4 ;
        RECT  64.716 41.712 64.8 41.736 ;
    END
  END kv_request[329]
  PIN kv_request[32]
    DIRECTION INPUT ;
    USE SIGNAL ;
    PORT
      LAYER M4 ;
        RECT  64.716 4.224 64.8 4.248 ;
    END
  END kv_request[32]
  PIN kv_request[330]
    DIRECTION INPUT ;
    USE SIGNAL ;
    PORT
      LAYER M4 ;
        RECT  64.716 41.856 64.8 41.88 ;
    END
  END kv_request[330]
  PIN kv_request[331]
    DIRECTION INPUT ;
    USE SIGNAL ;
    PORT
      LAYER M4 ;
        RECT  64.716 42 64.8 42.024 ;
    END
  END kv_request[331]
  PIN kv_request[332]
    DIRECTION INPUT ;
    USE SIGNAL ;
    PORT
      LAYER M4 ;
        RECT  64.716 42.096 64.8 42.12 ;
    END
  END kv_request[332]
  PIN kv_request[333]
    DIRECTION INPUT ;
    USE SIGNAL ;
    PORT
      LAYER M4 ;
        RECT  64.716 42.24 64.8 42.264 ;
    END
  END kv_request[333]
  PIN kv_request[334]
    DIRECTION INPUT ;
    USE SIGNAL ;
    PORT
      LAYER M4 ;
        RECT  64.716 42.384 64.8 42.408 ;
    END
  END kv_request[334]
  PIN kv_request[335]
    DIRECTION INPUT ;
    USE SIGNAL ;
    PORT
      LAYER M4 ;
        RECT  64.716 42.48 64.8 42.504 ;
    END
  END kv_request[335]
  PIN kv_request[336]
    DIRECTION INPUT ;
    USE SIGNAL ;
    PORT
      LAYER M4 ;
        RECT  64.716 42.624 64.8 42.648 ;
    END
  END kv_request[336]
  PIN kv_request[337]
    DIRECTION INPUT ;
    USE SIGNAL ;
    PORT
      LAYER M4 ;
        RECT  64.716 42.768 64.8 42.792 ;
    END
  END kv_request[337]
  PIN kv_request[338]
    DIRECTION INPUT ;
    USE SIGNAL ;
    PORT
      LAYER M4 ;
        RECT  64.716 42.864 64.8 42.888 ;
    END
  END kv_request[338]
  PIN kv_request[339]
    DIRECTION INPUT ;
    USE SIGNAL ;
    PORT
      LAYER M4 ;
        RECT  64.716 43.008 64.8 43.032 ;
    END
  END kv_request[339]
  PIN kv_request[33]
    DIRECTION INPUT ;
    USE SIGNAL ;
    PORT
      LAYER M4 ;
        RECT  64.716 4.368 64.8 4.392 ;
    END
  END kv_request[33]
  PIN kv_request[340]
    DIRECTION INPUT ;
    USE SIGNAL ;
    PORT
      LAYER M4 ;
        RECT  64.716 43.104 64.8 43.128 ;
    END
  END kv_request[340]
  PIN kv_request[341]
    DIRECTION INPUT ;
    USE SIGNAL ;
    PORT
      LAYER M4 ;
        RECT  64.716 43.248 64.8 43.272 ;
    END
  END kv_request[341]
  PIN kv_request[342]
    DIRECTION INPUT ;
    USE SIGNAL ;
    PORT
      LAYER M4 ;
        RECT  64.716 43.392 64.8 43.416 ;
    END
  END kv_request[342]
  PIN kv_request[343]
    DIRECTION INPUT ;
    USE SIGNAL ;
    PORT
      LAYER M4 ;
        RECT  64.716 43.488 64.8 43.512 ;
    END
  END kv_request[343]
  PIN kv_request[344]
    DIRECTION INPUT ;
    USE SIGNAL ;
    PORT
      LAYER M4 ;
        RECT  64.716 43.632 64.8 43.656 ;
    END
  END kv_request[344]
  PIN kv_request[345]
    DIRECTION INPUT ;
    USE SIGNAL ;
    PORT
      LAYER M4 ;
        RECT  64.716 43.776 64.8 43.8 ;
    END
  END kv_request[345]
  PIN kv_request[346]
    DIRECTION INPUT ;
    USE SIGNAL ;
    PORT
      LAYER M4 ;
        RECT  64.716 43.872 64.8 43.896 ;
    END
  END kv_request[346]
  PIN kv_request[347]
    DIRECTION INPUT ;
    USE SIGNAL ;
    PORT
      LAYER M4 ;
        RECT  64.716 44.016 64.8 44.04 ;
    END
  END kv_request[347]
  PIN kv_request[348]
    DIRECTION INPUT ;
    USE SIGNAL ;
    PORT
      LAYER M4 ;
        RECT  64.716 44.112 64.8 44.136 ;
    END
  END kv_request[348]
  PIN kv_request[349]
    DIRECTION INPUT ;
    USE SIGNAL ;
    PORT
      LAYER M4 ;
        RECT  64.716 44.256 64.8 44.28 ;
    END
  END kv_request[349]
  PIN kv_request[34]
    DIRECTION INPUT ;
    USE SIGNAL ;
    PORT
      LAYER M4 ;
        RECT  64.716 4.464 64.8 4.488 ;
    END
  END kv_request[34]
  PIN kv_request[350]
    DIRECTION INPUT ;
    USE SIGNAL ;
    PORT
      LAYER M4 ;
        RECT  64.716 44.4 64.8 44.424 ;
    END
  END kv_request[350]
  PIN kv_request[351]
    DIRECTION INPUT ;
    USE SIGNAL ;
    PORT
      LAYER M4 ;
        RECT  64.716 44.496 64.8 44.52 ;
    END
  END kv_request[351]
  PIN kv_request[352]
    DIRECTION INPUT ;
    USE SIGNAL ;
    PORT
      LAYER M4 ;
        RECT  64.716 44.64 64.8 44.664 ;
    END
  END kv_request[352]
  PIN kv_request[353]
    DIRECTION INPUT ;
    USE SIGNAL ;
    PORT
      LAYER M4 ;
        RECT  64.716 44.784 64.8 44.808 ;
    END
  END kv_request[353]
  PIN kv_request[354]
    DIRECTION INPUT ;
    USE SIGNAL ;
    PORT
      LAYER M4 ;
        RECT  64.716 44.88 64.8 44.904 ;
    END
  END kv_request[354]
  PIN kv_request[355]
    DIRECTION INPUT ;
    USE SIGNAL ;
    PORT
      LAYER M4 ;
        RECT  64.716 45.024 64.8 45.048 ;
    END
  END kv_request[355]
  PIN kv_request[356]
    DIRECTION INPUT ;
    USE SIGNAL ;
    PORT
      LAYER M4 ;
        RECT  64.716 45.168 64.8 45.192 ;
    END
  END kv_request[356]
  PIN kv_request[357]
    DIRECTION INPUT ;
    USE SIGNAL ;
    PORT
      LAYER M4 ;
        RECT  64.716 45.264 64.8 45.288 ;
    END
  END kv_request[357]
  PIN kv_request[358]
    DIRECTION INPUT ;
    USE SIGNAL ;
    PORT
      LAYER M4 ;
        RECT  64.716 45.408 64.8 45.432 ;
    END
  END kv_request[358]
  PIN kv_request[359]
    DIRECTION INPUT ;
    USE SIGNAL ;
    PORT
      LAYER M4 ;
        RECT  64.716 45.504 64.8 45.528 ;
    END
  END kv_request[359]
  PIN kv_request[35]
    DIRECTION INPUT ;
    USE SIGNAL ;
    PORT
      LAYER M4 ;
        RECT  64.716 4.608 64.8 4.632 ;
    END
  END kv_request[35]
  PIN kv_request[360]
    DIRECTION INPUT ;
    USE SIGNAL ;
    PORT
      LAYER M4 ;
        RECT  64.716 45.648 64.8 45.672 ;
    END
  END kv_request[360]
  PIN kv_request[361]
    DIRECTION INPUT ;
    USE SIGNAL ;
    PORT
      LAYER M4 ;
        RECT  64.716 45.792 64.8 45.816 ;
    END
  END kv_request[361]
  PIN kv_request[362]
    DIRECTION INPUT ;
    USE SIGNAL ;
    PORT
      LAYER M4 ;
        RECT  64.716 45.888 64.8 45.912 ;
    END
  END kv_request[362]
  PIN kv_request[363]
    DIRECTION INPUT ;
    USE SIGNAL ;
    PORT
      LAYER M4 ;
        RECT  64.716 46.032 64.8 46.056 ;
    END
  END kv_request[363]
  PIN kv_request[364]
    DIRECTION INPUT ;
    USE SIGNAL ;
    PORT
      LAYER M4 ;
        RECT  64.716 46.176 64.8 46.2 ;
    END
  END kv_request[364]
  PIN kv_request[365]
    DIRECTION INPUT ;
    USE SIGNAL ;
    PORT
      LAYER M4 ;
        RECT  64.716 46.272 64.8 46.296 ;
    END
  END kv_request[365]
  PIN kv_request[366]
    DIRECTION INPUT ;
    USE SIGNAL ;
    PORT
      LAYER M4 ;
        RECT  64.716 46.416 64.8 46.44 ;
    END
  END kv_request[366]
  PIN kv_request[367]
    DIRECTION INPUT ;
    USE SIGNAL ;
    PORT
      LAYER M4 ;
        RECT  64.716 46.512 64.8 46.536 ;
    END
  END kv_request[367]
  PIN kv_request[368]
    DIRECTION INPUT ;
    USE SIGNAL ;
    PORT
      LAYER M4 ;
        RECT  64.716 46.656 64.8 46.68 ;
    END
  END kv_request[368]
  PIN kv_request[369]
    DIRECTION INPUT ;
    USE SIGNAL ;
    PORT
      LAYER M4 ;
        RECT  64.716 46.8 64.8 46.824 ;
    END
  END kv_request[369]
  PIN kv_request[36]
    DIRECTION INPUT ;
    USE SIGNAL ;
    PORT
      LAYER M4 ;
        RECT  64.716 4.704 64.8 4.728 ;
    END
  END kv_request[36]
  PIN kv_request[370]
    DIRECTION INPUT ;
    USE SIGNAL ;
    PORT
      LAYER M4 ;
        RECT  64.716 46.896 64.8 46.92 ;
    END
  END kv_request[370]
  PIN kv_request[371]
    DIRECTION INPUT ;
    USE SIGNAL ;
    PORT
      LAYER M4 ;
        RECT  64.716 47.04 64.8 47.064 ;
    END
  END kv_request[371]
  PIN kv_request[372]
    DIRECTION INPUT ;
    USE SIGNAL ;
    PORT
      LAYER M4 ;
        RECT  64.716 47.184 64.8 47.208 ;
    END
  END kv_request[372]
  PIN kv_request[373]
    DIRECTION INPUT ;
    USE SIGNAL ;
    PORT
      LAYER M4 ;
        RECT  64.716 47.28 64.8 47.304 ;
    END
  END kv_request[373]
  PIN kv_request[374]
    DIRECTION INPUT ;
    USE SIGNAL ;
    PORT
      LAYER M4 ;
        RECT  64.716 47.424 64.8 47.448 ;
    END
  END kv_request[374]
  PIN kv_request[375]
    DIRECTION INPUT ;
    USE SIGNAL ;
    PORT
      LAYER M4 ;
        RECT  64.716 47.568 64.8 47.592 ;
    END
  END kv_request[375]
  PIN kv_request[376]
    DIRECTION INPUT ;
    USE SIGNAL ;
    PORT
      LAYER M4 ;
        RECT  64.716 47.664 64.8 47.688 ;
    END
  END kv_request[376]
  PIN kv_request[377]
    DIRECTION INPUT ;
    USE SIGNAL ;
    PORT
      LAYER M4 ;
        RECT  64.716 47.808 64.8 47.832 ;
    END
  END kv_request[377]
  PIN kv_request[378]
    DIRECTION INPUT ;
    USE SIGNAL ;
    PORT
      LAYER M4 ;
        RECT  64.716 47.904 64.8 47.928 ;
    END
  END kv_request[378]
  PIN kv_request[379]
    DIRECTION INPUT ;
    USE SIGNAL ;
    PORT
      LAYER M4 ;
        RECT  64.716 48.048 64.8 48.072 ;
    END
  END kv_request[379]
  PIN kv_request[37]
    DIRECTION INPUT ;
    USE SIGNAL ;
    PORT
      LAYER M4 ;
        RECT  64.716 4.848 64.8 4.872 ;
    END
  END kv_request[37]
  PIN kv_request[380]
    DIRECTION INPUT ;
    USE SIGNAL ;
    PORT
      LAYER M4 ;
        RECT  64.716 48.192 64.8 48.216 ;
    END
  END kv_request[380]
  PIN kv_request[381]
    DIRECTION INPUT ;
    USE SIGNAL ;
    PORT
      LAYER M4 ;
        RECT  64.716 48.288 64.8 48.312 ;
    END
  END kv_request[381]
  PIN kv_request[382]
    DIRECTION INPUT ;
    USE SIGNAL ;
    PORT
      LAYER M4 ;
        RECT  64.716 48.432 64.8 48.456 ;
    END
  END kv_request[382]
  PIN kv_request[383]
    DIRECTION INPUT ;
    USE SIGNAL ;
    PORT
      LAYER M4 ;
        RECT  64.716 48.576 64.8 48.6 ;
    END
  END kv_request[383]
  PIN kv_request[384]
    DIRECTION INPUT ;
    USE SIGNAL ;
    PORT
      LAYER M4 ;
        RECT  64.716 48.672 64.8 48.696 ;
    END
  END kv_request[384]
  PIN kv_request[385]
    DIRECTION INPUT ;
    USE SIGNAL ;
    PORT
      LAYER M4 ;
        RECT  64.716 48.816 64.8 48.84 ;
    END
  END kv_request[385]
  PIN kv_request[386]
    DIRECTION INPUT ;
    USE SIGNAL ;
    PORT
      LAYER M4 ;
        RECT  64.716 48.912 64.8 48.936 ;
    END
  END kv_request[386]
  PIN kv_request[387]
    DIRECTION INPUT ;
    USE SIGNAL ;
    PORT
      LAYER M4 ;
        RECT  64.716 49.056 64.8 49.08 ;
    END
  END kv_request[387]
  PIN kv_request[388]
    DIRECTION INPUT ;
    USE SIGNAL ;
    PORT
      LAYER M4 ;
        RECT  64.716 49.2 64.8 49.224 ;
    END
  END kv_request[388]
  PIN kv_request[389]
    DIRECTION INPUT ;
    USE SIGNAL ;
    PORT
      LAYER M4 ;
        RECT  64.716 49.296 64.8 49.32 ;
    END
  END kv_request[389]
  PIN kv_request[38]
    DIRECTION INPUT ;
    USE SIGNAL ;
    PORT
      LAYER M4 ;
        RECT  64.716 4.992 64.8 5.016 ;
    END
  END kv_request[38]
  PIN kv_request[390]
    DIRECTION INPUT ;
    USE SIGNAL ;
    PORT
      LAYER M4 ;
        RECT  64.716 49.44 64.8 49.464 ;
    END
  END kv_request[390]
  PIN kv_request[391]
    DIRECTION INPUT ;
    USE SIGNAL ;
    PORT
      LAYER M4 ;
        RECT  64.716 49.584 64.8 49.608 ;
    END
  END kv_request[391]
  PIN kv_request[392]
    DIRECTION INPUT ;
    USE SIGNAL ;
    PORT
      LAYER M4 ;
        RECT  64.716 49.68 64.8 49.704 ;
    END
  END kv_request[392]
  PIN kv_request[393]
    DIRECTION INPUT ;
    USE SIGNAL ;
    PORT
      LAYER M4 ;
        RECT  64.716 49.824 64.8 49.848 ;
    END
  END kv_request[393]
  PIN kv_request[394]
    DIRECTION INPUT ;
    USE SIGNAL ;
    PORT
      LAYER M4 ;
        RECT  64.716 49.968 64.8 49.992 ;
    END
  END kv_request[394]
  PIN kv_request[395]
    DIRECTION INPUT ;
    USE SIGNAL ;
    PORT
      LAYER M4 ;
        RECT  64.716 50.064 64.8 50.088 ;
    END
  END kv_request[395]
  PIN kv_request[396]
    DIRECTION INPUT ;
    USE SIGNAL ;
    PORT
      LAYER M4 ;
        RECT  64.716 50.208 64.8 50.232 ;
    END
  END kv_request[396]
  PIN kv_request[397]
    DIRECTION INPUT ;
    USE SIGNAL ;
    PORT
      LAYER M4 ;
        RECT  64.716 50.304 64.8 50.328 ;
    END
  END kv_request[397]
  PIN kv_request[398]
    DIRECTION INPUT ;
    USE SIGNAL ;
    PORT
      LAYER M4 ;
        RECT  64.716 50.448 64.8 50.472 ;
    END
  END kv_request[398]
  PIN kv_request[399]
    DIRECTION INPUT ;
    USE SIGNAL ;
    PORT
      LAYER M4 ;
        RECT  64.716 50.592 64.8 50.616 ;
    END
  END kv_request[399]
  PIN kv_request[39]
    DIRECTION INPUT ;
    USE SIGNAL ;
    PORT
      LAYER M4 ;
        RECT  64.716 5.088 64.8 5.112 ;
    END
  END kv_request[39]
  PIN kv_request[3]
    DIRECTION INPUT ;
    USE SIGNAL ;
    PORT
      LAYER M4 ;
        RECT  64.716 0.576 64.8 0.6 ;
    END
  END kv_request[3]
  PIN kv_request[400]
    DIRECTION INPUT ;
    USE SIGNAL ;
    PORT
      LAYER M4 ;
        RECT  64.716 50.688 64.8 50.712 ;
    END
  END kv_request[400]
  PIN kv_request[401]
    DIRECTION INPUT ;
    USE SIGNAL ;
    PORT
      LAYER M4 ;
        RECT  64.716 50.832 64.8 50.856 ;
    END
  END kv_request[401]
  PIN kv_request[402]
    DIRECTION INPUT ;
    USE SIGNAL ;
    PORT
      LAYER M4 ;
        RECT  64.716 50.976 64.8 51 ;
    END
  END kv_request[402]
  PIN kv_request[403]
    DIRECTION INPUT ;
    USE SIGNAL ;
    PORT
      LAYER M4 ;
        RECT  64.716 51.072 64.8 51.096 ;
    END
  END kv_request[403]
  PIN kv_request[404]
    DIRECTION INPUT ;
    USE SIGNAL ;
    PORT
      LAYER M4 ;
        RECT  64.716 51.216 64.8 51.24 ;
    END
  END kv_request[404]
  PIN kv_request[405]
    DIRECTION INPUT ;
    USE SIGNAL ;
    PORT
      LAYER M4 ;
        RECT  64.716 51.312 64.8 51.336 ;
    END
  END kv_request[405]
  PIN kv_request[406]
    DIRECTION INPUT ;
    USE SIGNAL ;
    PORT
      LAYER M4 ;
        RECT  64.716 51.456 64.8 51.48 ;
    END
  END kv_request[406]
  PIN kv_request[407]
    DIRECTION INPUT ;
    USE SIGNAL ;
    PORT
      LAYER M4 ;
        RECT  64.716 51.6 64.8 51.624 ;
    END
  END kv_request[407]
  PIN kv_request[408]
    DIRECTION INPUT ;
    USE SIGNAL ;
    PORT
      LAYER M4 ;
        RECT  64.716 51.696 64.8 51.72 ;
    END
  END kv_request[408]
  PIN kv_request[409]
    DIRECTION INPUT ;
    USE SIGNAL ;
    PORT
      LAYER M4 ;
        RECT  64.716 51.84 64.8 51.864 ;
    END
  END kv_request[409]
  PIN kv_request[40]
    DIRECTION INPUT ;
    USE SIGNAL ;
    PORT
      LAYER M4 ;
        RECT  64.716 5.232 64.8 5.256 ;
    END
  END kv_request[40]
  PIN kv_request[410]
    DIRECTION INPUT ;
    USE SIGNAL ;
    PORT
      LAYER M4 ;
        RECT  64.716 51.984 64.8 52.008 ;
    END
  END kv_request[410]
  PIN kv_request[411]
    DIRECTION INPUT ;
    USE SIGNAL ;
    PORT
      LAYER M4 ;
        RECT  64.716 52.08 64.8 52.104 ;
    END
  END kv_request[411]
  PIN kv_request[412]
    DIRECTION INPUT ;
    USE SIGNAL ;
    PORT
      LAYER M4 ;
        RECT  64.716 52.224 64.8 52.248 ;
    END
  END kv_request[412]
  PIN kv_request[413]
    DIRECTION INPUT ;
    USE SIGNAL ;
    PORT
      LAYER M4 ;
        RECT  64.716 52.368 64.8 52.392 ;
    END
  END kv_request[413]
  PIN kv_request[414]
    DIRECTION INPUT ;
    USE SIGNAL ;
    PORT
      LAYER M4 ;
        RECT  64.716 52.464 64.8 52.488 ;
    END
  END kv_request[414]
  PIN kv_request[415]
    DIRECTION INPUT ;
    USE SIGNAL ;
    PORT
      LAYER M4 ;
        RECT  64.716 52.608 64.8 52.632 ;
    END
  END kv_request[415]
  PIN kv_request[416]
    DIRECTION INPUT ;
    USE SIGNAL ;
    PORT
      LAYER M4 ;
        RECT  64.716 52.704 64.8 52.728 ;
    END
  END kv_request[416]
  PIN kv_request[417]
    DIRECTION INPUT ;
    USE SIGNAL ;
    PORT
      LAYER M4 ;
        RECT  64.716 52.848 64.8 52.872 ;
    END
  END kv_request[417]
  PIN kv_request[418]
    DIRECTION INPUT ;
    USE SIGNAL ;
    PORT
      LAYER M4 ;
        RECT  64.716 52.992 64.8 53.016 ;
    END
  END kv_request[418]
  PIN kv_request[419]
    DIRECTION INPUT ;
    USE SIGNAL ;
    PORT
      LAYER M4 ;
        RECT  64.716 53.088 64.8 53.112 ;
    END
  END kv_request[419]
  PIN kv_request[41]
    DIRECTION INPUT ;
    USE SIGNAL ;
    PORT
      LAYER M4 ;
        RECT  64.716 5.376 64.8 5.4 ;
    END
  END kv_request[41]
  PIN kv_request[420]
    DIRECTION INPUT ;
    USE SIGNAL ;
    PORT
      LAYER M4 ;
        RECT  64.716 53.232 64.8 53.256 ;
    END
  END kv_request[420]
  PIN kv_request[421]
    DIRECTION INPUT ;
    USE SIGNAL ;
    PORT
      LAYER M4 ;
        RECT  64.716 53.376 64.8 53.4 ;
    END
  END kv_request[421]
  PIN kv_request[422]
    DIRECTION INPUT ;
    USE SIGNAL ;
    PORT
      LAYER M4 ;
        RECT  64.716 53.472 64.8 53.496 ;
    END
  END kv_request[422]
  PIN kv_request[423]
    DIRECTION INPUT ;
    USE SIGNAL ;
    PORT
      LAYER M4 ;
        RECT  64.716 53.616 64.8 53.64 ;
    END
  END kv_request[423]
  PIN kv_request[424]
    DIRECTION INPUT ;
    USE SIGNAL ;
    PORT
      LAYER M4 ;
        RECT  64.716 53.712 64.8 53.736 ;
    END
  END kv_request[424]
  PIN kv_request[425]
    DIRECTION INPUT ;
    USE SIGNAL ;
    PORT
      LAYER M4 ;
        RECT  64.716 53.856 64.8 53.88 ;
    END
  END kv_request[425]
  PIN kv_request[426]
    DIRECTION INPUT ;
    USE SIGNAL ;
    PORT
      LAYER M4 ;
        RECT  64.716 54 64.8 54.024 ;
    END
  END kv_request[426]
  PIN kv_request[427]
    DIRECTION INPUT ;
    USE SIGNAL ;
    PORT
      LAYER M4 ;
        RECT  64.716 54.096 64.8 54.12 ;
    END
  END kv_request[427]
  PIN kv_request[428]
    DIRECTION INPUT ;
    USE SIGNAL ;
    PORT
      LAYER M4 ;
        RECT  64.716 54.24 64.8 54.264 ;
    END
  END kv_request[428]
  PIN kv_request[429]
    DIRECTION INPUT ;
    USE SIGNAL ;
    PORT
      LAYER M4 ;
        RECT  64.716 54.384 64.8 54.408 ;
    END
  END kv_request[429]
  PIN kv_request[42]
    DIRECTION INPUT ;
    USE SIGNAL ;
    PORT
      LAYER M4 ;
        RECT  64.716 5.472 64.8 5.496 ;
    END
  END kv_request[42]
  PIN kv_request[430]
    DIRECTION INPUT ;
    USE SIGNAL ;
    PORT
      LAYER M4 ;
        RECT  64.716 54.48 64.8 54.504 ;
    END
  END kv_request[430]
  PIN kv_request[431]
    DIRECTION INPUT ;
    USE SIGNAL ;
    PORT
      LAYER M4 ;
        RECT  64.716 54.624 64.8 54.648 ;
    END
  END kv_request[431]
  PIN kv_request[432]
    DIRECTION INPUT ;
    USE SIGNAL ;
    PORT
      LAYER M4 ;
        RECT  64.716 54.768 64.8 54.792 ;
    END
  END kv_request[432]
  PIN kv_request[433]
    DIRECTION INPUT ;
    USE SIGNAL ;
    PORT
      LAYER M4 ;
        RECT  64.716 54.864 64.8 54.888 ;
    END
  END kv_request[433]
  PIN kv_request[434]
    DIRECTION INPUT ;
    USE SIGNAL ;
    PORT
      LAYER M4 ;
        RECT  64.716 55.008 64.8 55.032 ;
    END
  END kv_request[434]
  PIN kv_request[435]
    DIRECTION INPUT ;
    USE SIGNAL ;
    PORT
      LAYER M4 ;
        RECT  64.716 55.104 64.8 55.128 ;
    END
  END kv_request[435]
  PIN kv_request[436]
    DIRECTION INPUT ;
    USE SIGNAL ;
    PORT
      LAYER M4 ;
        RECT  64.716 55.248 64.8 55.272 ;
    END
  END kv_request[436]
  PIN kv_request[437]
    DIRECTION INPUT ;
    USE SIGNAL ;
    PORT
      LAYER M4 ;
        RECT  64.716 55.392 64.8 55.416 ;
    END
  END kv_request[437]
  PIN kv_request[438]
    DIRECTION INPUT ;
    USE SIGNAL ;
    PORT
      LAYER M4 ;
        RECT  64.716 55.488 64.8 55.512 ;
    END
  END kv_request[438]
  PIN kv_request[439]
    DIRECTION INPUT ;
    USE SIGNAL ;
    PORT
      LAYER M4 ;
        RECT  64.716 55.632 64.8 55.656 ;
    END
  END kv_request[439]
  PIN kv_request[43]
    DIRECTION INPUT ;
    USE SIGNAL ;
    PORT
      LAYER M4 ;
        RECT  64.716 5.616 64.8 5.64 ;
    END
  END kv_request[43]
  PIN kv_request[440]
    DIRECTION INPUT ;
    USE SIGNAL ;
    PORT
      LAYER M4 ;
        RECT  64.716 55.776 64.8 55.8 ;
    END
  END kv_request[440]
  PIN kv_request[441]
    DIRECTION INPUT ;
    USE SIGNAL ;
    PORT
      LAYER M4 ;
        RECT  64.716 55.872 64.8 55.896 ;
    END
  END kv_request[441]
  PIN kv_request[442]
    DIRECTION INPUT ;
    USE SIGNAL ;
    PORT
      LAYER M4 ;
        RECT  64.716 56.016 64.8 56.04 ;
    END
  END kv_request[442]
  PIN kv_request[443]
    DIRECTION INPUT ;
    USE SIGNAL ;
    PORT
      LAYER M4 ;
        RECT  64.716 56.112 64.8 56.136 ;
    END
  END kv_request[443]
  PIN kv_request[444]
    DIRECTION INPUT ;
    USE SIGNAL ;
    PORT
      LAYER M4 ;
        RECT  64.716 56.256 64.8 56.28 ;
    END
  END kv_request[444]
  PIN kv_request[445]
    DIRECTION INPUT ;
    USE SIGNAL ;
    PORT
      LAYER M4 ;
        RECT  64.716 56.4 64.8 56.424 ;
    END
  END kv_request[445]
  PIN kv_request[446]
    DIRECTION INPUT ;
    USE SIGNAL ;
    PORT
      LAYER M4 ;
        RECT  64.716 56.496 64.8 56.52 ;
    END
  END kv_request[446]
  PIN kv_request[447]
    DIRECTION INPUT ;
    USE SIGNAL ;
    PORT
      LAYER M4 ;
        RECT  64.716 56.64 64.8 56.664 ;
    END
  END kv_request[447]
  PIN kv_request[448]
    DIRECTION INPUT ;
    USE SIGNAL ;
    PORT
      LAYER M4 ;
        RECT  64.716 56.784 64.8 56.808 ;
    END
  END kv_request[448]
  PIN kv_request[449]
    DIRECTION INPUT ;
    USE SIGNAL ;
    PORT
      LAYER M4 ;
        RECT  64.716 56.88 64.8 56.904 ;
    END
  END kv_request[449]
  PIN kv_request[44]
    DIRECTION INPUT ;
    USE SIGNAL ;
    PORT
      LAYER M4 ;
        RECT  64.716 5.712 64.8 5.736 ;
    END
  END kv_request[44]
  PIN kv_request[450]
    DIRECTION INPUT ;
    USE SIGNAL ;
    PORT
      LAYER M4 ;
        RECT  64.716 57.024 64.8 57.048 ;
    END
  END kv_request[450]
  PIN kv_request[451]
    DIRECTION INPUT ;
    USE SIGNAL ;
    PORT
      LAYER M4 ;
        RECT  64.716 57.168 64.8 57.192 ;
    END
  END kv_request[451]
  PIN kv_request[452]
    DIRECTION INPUT ;
    USE SIGNAL ;
    PORT
      LAYER M4 ;
        RECT  64.716 57.264 64.8 57.288 ;
    END
  END kv_request[452]
  PIN kv_request[453]
    DIRECTION INPUT ;
    USE SIGNAL ;
    PORT
      LAYER M4 ;
        RECT  64.716 57.408 64.8 57.432 ;
    END
  END kv_request[453]
  PIN kv_request[454]
    DIRECTION INPUT ;
    USE SIGNAL ;
    PORT
      LAYER M4 ;
        RECT  64.716 57.504 64.8 57.528 ;
    END
  END kv_request[454]
  PIN kv_request[455]
    DIRECTION INPUT ;
    USE SIGNAL ;
    PORT
      LAYER M4 ;
        RECT  64.716 57.648 64.8 57.672 ;
    END
  END kv_request[455]
  PIN kv_request[456]
    DIRECTION INPUT ;
    USE SIGNAL ;
    PORT
      LAYER M4 ;
        RECT  64.716 57.792 64.8 57.816 ;
    END
  END kv_request[456]
  PIN kv_request[457]
    DIRECTION INPUT ;
    USE SIGNAL ;
    PORT
      LAYER M4 ;
        RECT  64.716 57.888 64.8 57.912 ;
    END
  END kv_request[457]
  PIN kv_request[458]
    DIRECTION INPUT ;
    USE SIGNAL ;
    PORT
      LAYER M4 ;
        RECT  64.716 58.032 64.8 58.056 ;
    END
  END kv_request[458]
  PIN kv_request[459]
    DIRECTION INPUT ;
    USE SIGNAL ;
    PORT
      LAYER M4 ;
        RECT  64.716 58.176 64.8 58.2 ;
    END
  END kv_request[459]
  PIN kv_request[45]
    DIRECTION INPUT ;
    USE SIGNAL ;
    PORT
      LAYER M4 ;
        RECT  64.716 5.856 64.8 5.88 ;
    END
  END kv_request[45]
  PIN kv_request[460]
    DIRECTION INPUT ;
    USE SIGNAL ;
    PORT
      LAYER M4 ;
        RECT  64.716 58.272 64.8 58.296 ;
    END
  END kv_request[460]
  PIN kv_request[461]
    DIRECTION INPUT ;
    USE SIGNAL ;
    PORT
      LAYER M4 ;
        RECT  64.716 58.416 64.8 58.44 ;
    END
  END kv_request[461]
  PIN kv_request[462]
    DIRECTION INPUT ;
    USE SIGNAL ;
    PORT
      LAYER M4 ;
        RECT  64.716 58.512 64.8 58.536 ;
    END
  END kv_request[462]
  PIN kv_request[463]
    DIRECTION INPUT ;
    USE SIGNAL ;
    PORT
      LAYER M4 ;
        RECT  64.716 58.656 64.8 58.68 ;
    END
  END kv_request[463]
  PIN kv_request[464]
    DIRECTION INPUT ;
    USE SIGNAL ;
    PORT
      LAYER M4 ;
        RECT  64.716 58.8 64.8 58.824 ;
    END
  END kv_request[464]
  PIN kv_request[465]
    DIRECTION INPUT ;
    USE SIGNAL ;
    PORT
      LAYER M4 ;
        RECT  64.716 58.896 64.8 58.92 ;
    END
  END kv_request[465]
  PIN kv_request[466]
    DIRECTION INPUT ;
    USE SIGNAL ;
    PORT
      LAYER M4 ;
        RECT  64.716 59.04 64.8 59.064 ;
    END
  END kv_request[466]
  PIN kv_request[467]
    DIRECTION INPUT ;
    USE SIGNAL ;
    PORT
      LAYER M4 ;
        RECT  64.716 59.184 64.8 59.208 ;
    END
  END kv_request[467]
  PIN kv_request[468]
    DIRECTION INPUT ;
    USE SIGNAL ;
    PORT
      LAYER M4 ;
        RECT  64.716 59.28 64.8 59.304 ;
    END
  END kv_request[468]
  PIN kv_request[469]
    DIRECTION INPUT ;
    USE SIGNAL ;
    PORT
      LAYER M4 ;
        RECT  64.716 59.424 64.8 59.448 ;
    END
  END kv_request[469]
  PIN kv_request[46]
    DIRECTION INPUT ;
    USE SIGNAL ;
    PORT
      LAYER M4 ;
        RECT  64.716 6 64.8 6.024 ;
    END
  END kv_request[46]
  PIN kv_request[470]
    DIRECTION INPUT ;
    USE SIGNAL ;
    PORT
      LAYER M4 ;
        RECT  64.716 59.568 64.8 59.592 ;
    END
  END kv_request[470]
  PIN kv_request[471]
    DIRECTION INPUT ;
    USE SIGNAL ;
    PORT
      LAYER M4 ;
        RECT  64.716 59.664 64.8 59.688 ;
    END
  END kv_request[471]
  PIN kv_request[472]
    DIRECTION INPUT ;
    USE SIGNAL ;
    PORT
      LAYER M4 ;
        RECT  64.716 59.808 64.8 59.832 ;
    END
  END kv_request[472]
  PIN kv_request[473]
    DIRECTION INPUT ;
    USE SIGNAL ;
    PORT
      LAYER M4 ;
        RECT  64.716 59.904 64.8 59.928 ;
    END
  END kv_request[473]
  PIN kv_request[474]
    DIRECTION INPUT ;
    USE SIGNAL ;
    PORT
      LAYER M4 ;
        RECT  64.716 60.048 64.8 60.072 ;
    END
  END kv_request[474]
  PIN kv_request[475]
    DIRECTION INPUT ;
    USE SIGNAL ;
    PORT
      LAYER M4 ;
        RECT  64.716 60.192 64.8 60.216 ;
    END
  END kv_request[475]
  PIN kv_request[476]
    DIRECTION INPUT ;
    USE SIGNAL ;
    PORT
      LAYER M4 ;
        RECT  64.716 60.288 64.8 60.312 ;
    END
  END kv_request[476]
  PIN kv_request[477]
    DIRECTION INPUT ;
    USE SIGNAL ;
    PORT
      LAYER M4 ;
        RECT  64.716 60.432 64.8 60.456 ;
    END
  END kv_request[477]
  PIN kv_request[478]
    DIRECTION INPUT ;
    USE SIGNAL ;
    PORT
      LAYER M4 ;
        RECT  64.716 60.576 64.8 60.6 ;
    END
  END kv_request[478]
  PIN kv_request[479]
    DIRECTION INPUT ;
    USE SIGNAL ;
    PORT
      LAYER M4 ;
        RECT  64.716 60.672 64.8 60.696 ;
    END
  END kv_request[479]
  PIN kv_request[47]
    DIRECTION INPUT ;
    USE SIGNAL ;
    PORT
      LAYER M4 ;
        RECT  64.716 6.096 64.8 6.12 ;
    END
  END kv_request[47]
  PIN kv_request[480]
    DIRECTION INPUT ;
    USE SIGNAL ;
    PORT
      LAYER M4 ;
        RECT  64.716 60.816 64.8 60.84 ;
    END
  END kv_request[480]
  PIN kv_request[481]
    DIRECTION INPUT ;
    USE SIGNAL ;
    PORT
      LAYER M4 ;
        RECT  64.716 60.912 64.8 60.936 ;
    END
  END kv_request[481]
  PIN kv_request[482]
    DIRECTION INPUT ;
    USE SIGNAL ;
    PORT
      LAYER M4 ;
        RECT  64.716 61.056 64.8 61.08 ;
    END
  END kv_request[482]
  PIN kv_request[483]
    DIRECTION INPUT ;
    USE SIGNAL ;
    PORT
      LAYER M4 ;
        RECT  64.716 61.2 64.8 61.224 ;
    END
  END kv_request[483]
  PIN kv_request[484]
    DIRECTION INPUT ;
    USE SIGNAL ;
    PORT
      LAYER M4 ;
        RECT  64.716 61.296 64.8 61.32 ;
    END
  END kv_request[484]
  PIN kv_request[485]
    DIRECTION INPUT ;
    USE SIGNAL ;
    PORT
      LAYER M4 ;
        RECT  64.716 61.44 64.8 61.464 ;
    END
  END kv_request[485]
  PIN kv_request[486]
    DIRECTION INPUT ;
    USE SIGNAL ;
    PORT
      LAYER M4 ;
        RECT  64.716 61.584 64.8 61.608 ;
    END
  END kv_request[486]
  PIN kv_request[487]
    DIRECTION INPUT ;
    USE SIGNAL ;
    PORT
      LAYER M4 ;
        RECT  64.716 61.68 64.8 61.704 ;
    END
  END kv_request[487]
  PIN kv_request[488]
    DIRECTION INPUT ;
    USE SIGNAL ;
    PORT
      LAYER M4 ;
        RECT  64.716 61.824 64.8 61.848 ;
    END
  END kv_request[488]
  PIN kv_request[489]
    DIRECTION INPUT ;
    USE SIGNAL ;
    PORT
      LAYER M4 ;
        RECT  64.716 61.968 64.8 61.992 ;
    END
  END kv_request[489]
  PIN kv_request[48]
    DIRECTION INPUT ;
    USE SIGNAL ;
    PORT
      LAYER M4 ;
        RECT  64.716 6.24 64.8 6.264 ;
    END
  END kv_request[48]
  PIN kv_request[490]
    DIRECTION INPUT ;
    USE SIGNAL ;
    PORT
      LAYER M4 ;
        RECT  64.716 62.064 64.8 62.088 ;
    END
  END kv_request[490]
  PIN kv_request[491]
    DIRECTION INPUT ;
    USE SIGNAL ;
    PORT
      LAYER M4 ;
        RECT  64.716 62.208 64.8 62.232 ;
    END
  END kv_request[491]
  PIN kv_request[492]
    DIRECTION INPUT ;
    USE SIGNAL ;
    PORT
      LAYER M4 ;
        RECT  64.716 62.304 64.8 62.328 ;
    END
  END kv_request[492]
  PIN kv_request[493]
    DIRECTION INPUT ;
    USE SIGNAL ;
    PORT
      LAYER M4 ;
        RECT  64.716 62.448 64.8 62.472 ;
    END
  END kv_request[493]
  PIN kv_request[494]
    DIRECTION INPUT ;
    USE SIGNAL ;
    PORT
      LAYER M4 ;
        RECT  64.716 62.592 64.8 62.616 ;
    END
  END kv_request[494]
  PIN kv_request[495]
    DIRECTION INPUT ;
    USE SIGNAL ;
    PORT
      LAYER M4 ;
        RECT  64.716 62.688 64.8 62.712 ;
    END
  END kv_request[495]
  PIN kv_request[496]
    DIRECTION INPUT ;
    USE SIGNAL ;
    PORT
      LAYER M4 ;
        RECT  64.716 62.832 64.8 62.856 ;
    END
  END kv_request[496]
  PIN kv_request[497]
    DIRECTION INPUT ;
    USE SIGNAL ;
    PORT
      LAYER M4 ;
        RECT  64.716 62.976 64.8 63 ;
    END
  END kv_request[497]
  PIN kv_request[498]
    DIRECTION INPUT ;
    USE SIGNAL ;
    PORT
      LAYER M4 ;
        RECT  64.716 63.072 64.8 63.096 ;
    END
  END kv_request[498]
  PIN kv_request[499]
    DIRECTION INPUT ;
    USE SIGNAL ;
    PORT
      LAYER M4 ;
        RECT  64.716 63.216 64.8 63.24 ;
    END
  END kv_request[499]
  PIN kv_request[49]
    DIRECTION INPUT ;
    USE SIGNAL ;
    PORT
      LAYER M4 ;
        RECT  64.716 6.384 64.8 6.408 ;
    END
  END kv_request[49]
  PIN kv_request[4]
    DIRECTION INPUT ;
    USE SIGNAL ;
    PORT
      LAYER M4 ;
        RECT  64.716 0.672 64.8 0.696 ;
    END
  END kv_request[4]
  PIN kv_request[500]
    DIRECTION INPUT ;
    USE SIGNAL ;
    PORT
      LAYER M4 ;
        RECT  64.716 63.312 64.8 63.336 ;
    END
  END kv_request[500]
  PIN kv_request[501]
    DIRECTION INPUT ;
    USE SIGNAL ;
    PORT
      LAYER M4 ;
        RECT  64.716 63.456 64.8 63.48 ;
    END
  END kv_request[501]
  PIN kv_request[502]
    DIRECTION INPUT ;
    USE SIGNAL ;
    PORT
      LAYER M4 ;
        RECT  64.716 63.6 64.8 63.624 ;
    END
  END kv_request[502]
  PIN kv_request[503]
    DIRECTION INPUT ;
    USE SIGNAL ;
    PORT
      LAYER M4 ;
        RECT  64.716 63.696 64.8 63.72 ;
    END
  END kv_request[503]
  PIN kv_request[504]
    DIRECTION INPUT ;
    USE SIGNAL ;
    PORT
      LAYER M4 ;
        RECT  64.716 63.84 64.8 63.864 ;
    END
  END kv_request[504]
  PIN kv_request[505]
    DIRECTION INPUT ;
    USE SIGNAL ;
    PORT
      LAYER M4 ;
        RECT  64.716 63.984 64.8 64.008 ;
    END
  END kv_request[505]
  PIN kv_request[506]
    DIRECTION INPUT ;
    USE SIGNAL ;
    PORT
      LAYER M4 ;
        RECT  64.716 64.08 64.8 64.104 ;
    END
  END kv_request[506]
  PIN kv_request[507]
    DIRECTION INPUT ;
    USE SIGNAL ;
    PORT
      LAYER M4 ;
        RECT  64.716 64.224 64.8 64.248 ;
    END
  END kv_request[507]
  PIN kv_request[508]
    DIRECTION INPUT ;
    USE SIGNAL ;
    PORT
      LAYER M4 ;
        RECT  64.716 64.368 64.8 64.392 ;
    END
  END kv_request[508]
  PIN kv_request[509]
    DIRECTION INPUT ;
    USE SIGNAL ;
    PORT
      LAYER M4 ;
        RECT  64.716 64.464 64.8 64.488 ;
    END
  END kv_request[509]
  PIN kv_request[50]
    DIRECTION INPUT ;
    USE SIGNAL ;
    PORT
      LAYER M4 ;
        RECT  64.716 6.48 64.8 6.504 ;
    END
  END kv_request[50]
  PIN kv_request[510]
    DIRECTION INPUT ;
    USE SIGNAL ;
    PORT
      LAYER M4 ;
        RECT  64.716 64.608 64.8 64.632 ;
    END
  END kv_request[510]
  PIN kv_request[511]
    DIRECTION INPUT ;
    USE SIGNAL ;
    PORT
      LAYER M4 ;
        RECT  64.716 64.704 64.8 64.728 ;
    END
  END kv_request[511]
  PIN kv_request[51]
    DIRECTION INPUT ;
    USE SIGNAL ;
    PORT
      LAYER M4 ;
        RECT  64.716 6.624 64.8 6.648 ;
    END
  END kv_request[51]
  PIN kv_request[52]
    DIRECTION INPUT ;
    USE SIGNAL ;
    PORT
      LAYER M4 ;
        RECT  64.716 6.768 64.8 6.792 ;
    END
  END kv_request[52]
  PIN kv_request[53]
    DIRECTION INPUT ;
    USE SIGNAL ;
    PORT
      LAYER M4 ;
        RECT  64.716 6.864 64.8 6.888 ;
    END
  END kv_request[53]
  PIN kv_request[54]
    DIRECTION INPUT ;
    USE SIGNAL ;
    PORT
      LAYER M4 ;
        RECT  64.716 7.008 64.8 7.032 ;
    END
  END kv_request[54]
  PIN kv_request[55]
    DIRECTION INPUT ;
    USE SIGNAL ;
    PORT
      LAYER M4 ;
        RECT  64.716 7.104 64.8 7.128 ;
    END
  END kv_request[55]
  PIN kv_request[56]
    DIRECTION INPUT ;
    USE SIGNAL ;
    PORT
      LAYER M4 ;
        RECT  64.716 7.248 64.8 7.272 ;
    END
  END kv_request[56]
  PIN kv_request[57]
    DIRECTION INPUT ;
    USE SIGNAL ;
    PORT
      LAYER M4 ;
        RECT  64.716 7.392 64.8 7.416 ;
    END
  END kv_request[57]
  PIN kv_request[58]
    DIRECTION INPUT ;
    USE SIGNAL ;
    PORT
      LAYER M4 ;
        RECT  64.716 7.488 64.8 7.512 ;
    END
  END kv_request[58]
  PIN kv_request[59]
    DIRECTION INPUT ;
    USE SIGNAL ;
    PORT
      LAYER M4 ;
        RECT  64.716 7.632 64.8 7.656 ;
    END
  END kv_request[59]
  PIN kv_request[5]
    DIRECTION INPUT ;
    USE SIGNAL ;
    PORT
      LAYER M4 ;
        RECT  64.716 0.816 64.8 0.84 ;
    END
  END kv_request[5]
  PIN kv_request[60]
    DIRECTION INPUT ;
    USE SIGNAL ;
    PORT
      LAYER M4 ;
        RECT  64.716 7.776 64.8 7.8 ;
    END
  END kv_request[60]
  PIN kv_request[61]
    DIRECTION INPUT ;
    USE SIGNAL ;
    PORT
      LAYER M4 ;
        RECT  64.716 7.872 64.8 7.896 ;
    END
  END kv_request[61]
  PIN kv_request[62]
    DIRECTION INPUT ;
    USE SIGNAL ;
    PORT
      LAYER M4 ;
        RECT  64.716 8.016 64.8 8.04 ;
    END
  END kv_request[62]
  PIN kv_request[63]
    DIRECTION INPUT ;
    USE SIGNAL ;
    PORT
      LAYER M4 ;
        RECT  64.716 8.112 64.8 8.136 ;
    END
  END kv_request[63]
  PIN kv_request[64]
    DIRECTION INPUT ;
    USE SIGNAL ;
    PORT
      LAYER M4 ;
        RECT  64.716 8.256 64.8 8.28 ;
    END
  END kv_request[64]
  PIN kv_request[65]
    DIRECTION INPUT ;
    USE SIGNAL ;
    PORT
      LAYER M4 ;
        RECT  64.716 8.4 64.8 8.424 ;
    END
  END kv_request[65]
  PIN kv_request[66]
    DIRECTION INPUT ;
    USE SIGNAL ;
    PORT
      LAYER M4 ;
        RECT  64.716 8.496 64.8 8.52 ;
    END
  END kv_request[66]
  PIN kv_request[67]
    DIRECTION INPUT ;
    USE SIGNAL ;
    PORT
      LAYER M4 ;
        RECT  64.716 8.64 64.8 8.664 ;
    END
  END kv_request[67]
  PIN kv_request[68]
    DIRECTION INPUT ;
    USE SIGNAL ;
    PORT
      LAYER M4 ;
        RECT  64.716 8.784 64.8 8.808 ;
    END
  END kv_request[68]
  PIN kv_request[69]
    DIRECTION INPUT ;
    USE SIGNAL ;
    PORT
      LAYER M4 ;
        RECT  64.716 8.88 64.8 8.904 ;
    END
  END kv_request[69]
  PIN kv_request[6]
    DIRECTION INPUT ;
    USE SIGNAL ;
    PORT
      LAYER M4 ;
        RECT  64.716 0.912 64.8 0.936 ;
    END
  END kv_request[6]
  PIN kv_request[70]
    DIRECTION INPUT ;
    USE SIGNAL ;
    PORT
      LAYER M4 ;
        RECT  64.716 9.024 64.8 9.048 ;
    END
  END kv_request[70]
  PIN kv_request[71]
    DIRECTION INPUT ;
    USE SIGNAL ;
    PORT
      LAYER M4 ;
        RECT  64.716 9.168 64.8 9.192 ;
    END
  END kv_request[71]
  PIN kv_request[72]
    DIRECTION INPUT ;
    USE SIGNAL ;
    PORT
      LAYER M4 ;
        RECT  64.716 9.264 64.8 9.288 ;
    END
  END kv_request[72]
  PIN kv_request[73]
    DIRECTION INPUT ;
    USE SIGNAL ;
    PORT
      LAYER M4 ;
        RECT  64.716 9.408 64.8 9.432 ;
    END
  END kv_request[73]
  PIN kv_request[74]
    DIRECTION INPUT ;
    USE SIGNAL ;
    PORT
      LAYER M4 ;
        RECT  64.716 9.504 64.8 9.528 ;
    END
  END kv_request[74]
  PIN kv_request[75]
    DIRECTION INPUT ;
    USE SIGNAL ;
    PORT
      LAYER M4 ;
        RECT  64.716 9.648 64.8 9.672 ;
    END
  END kv_request[75]
  PIN kv_request[76]
    DIRECTION INPUT ;
    USE SIGNAL ;
    PORT
      LAYER M4 ;
        RECT  64.716 9.792 64.8 9.816 ;
    END
  END kv_request[76]
  PIN kv_request[77]
    DIRECTION INPUT ;
    USE SIGNAL ;
    PORT
      LAYER M4 ;
        RECT  64.716 9.888 64.8 9.912 ;
    END
  END kv_request[77]
  PIN kv_request[78]
    DIRECTION INPUT ;
    USE SIGNAL ;
    PORT
      LAYER M4 ;
        RECT  64.716 10.032 64.8 10.056 ;
    END
  END kv_request[78]
  PIN kv_request[79]
    DIRECTION INPUT ;
    USE SIGNAL ;
    PORT
      LAYER M4 ;
        RECT  64.716 10.176 64.8 10.2 ;
    END
  END kv_request[79]
  PIN kv_request[7]
    DIRECTION INPUT ;
    USE SIGNAL ;
    PORT
      LAYER M4 ;
        RECT  64.716 1.056 64.8 1.08 ;
    END
  END kv_request[7]
  PIN kv_request[80]
    DIRECTION INPUT ;
    USE SIGNAL ;
    PORT
      LAYER M4 ;
        RECT  64.716 10.272 64.8 10.296 ;
    END
  END kv_request[80]
  PIN kv_request[81]
    DIRECTION INPUT ;
    USE SIGNAL ;
    PORT
      LAYER M4 ;
        RECT  64.716 10.416 64.8 10.44 ;
    END
  END kv_request[81]
  PIN kv_request[82]
    DIRECTION INPUT ;
    USE SIGNAL ;
    PORT
      LAYER M4 ;
        RECT  64.716 10.512 64.8 10.536 ;
    END
  END kv_request[82]
  PIN kv_request[83]
    DIRECTION INPUT ;
    USE SIGNAL ;
    PORT
      LAYER M4 ;
        RECT  64.716 10.656 64.8 10.68 ;
    END
  END kv_request[83]
  PIN kv_request[84]
    DIRECTION INPUT ;
    USE SIGNAL ;
    PORT
      LAYER M4 ;
        RECT  64.716 10.8 64.8 10.824 ;
    END
  END kv_request[84]
  PIN kv_request[85]
    DIRECTION INPUT ;
    USE SIGNAL ;
    PORT
      LAYER M4 ;
        RECT  64.716 10.896 64.8 10.92 ;
    END
  END kv_request[85]
  PIN kv_request[86]
    DIRECTION INPUT ;
    USE SIGNAL ;
    PORT
      LAYER M4 ;
        RECT  64.716 11.04 64.8 11.064 ;
    END
  END kv_request[86]
  PIN kv_request[87]
    DIRECTION INPUT ;
    USE SIGNAL ;
    PORT
      LAYER M4 ;
        RECT  64.716 11.184 64.8 11.208 ;
    END
  END kv_request[87]
  PIN kv_request[88]
    DIRECTION INPUT ;
    USE SIGNAL ;
    PORT
      LAYER M4 ;
        RECT  64.716 11.28 64.8 11.304 ;
    END
  END kv_request[88]
  PIN kv_request[89]
    DIRECTION INPUT ;
    USE SIGNAL ;
    PORT
      LAYER M4 ;
        RECT  64.716 11.424 64.8 11.448 ;
    END
  END kv_request[89]
  PIN kv_request[8]
    DIRECTION INPUT ;
    USE SIGNAL ;
    PORT
      LAYER M4 ;
        RECT  64.716 1.2 64.8 1.224 ;
    END
  END kv_request[8]
  PIN kv_request[90]
    DIRECTION INPUT ;
    USE SIGNAL ;
    PORT
      LAYER M4 ;
        RECT  64.716 11.568 64.8 11.592 ;
    END
  END kv_request[90]
  PIN kv_request[91]
    DIRECTION INPUT ;
    USE SIGNAL ;
    PORT
      LAYER M4 ;
        RECT  64.716 11.664 64.8 11.688 ;
    END
  END kv_request[91]
  PIN kv_request[92]
    DIRECTION INPUT ;
    USE SIGNAL ;
    PORT
      LAYER M4 ;
        RECT  64.716 11.808 64.8 11.832 ;
    END
  END kv_request[92]
  PIN kv_request[93]
    DIRECTION INPUT ;
    USE SIGNAL ;
    PORT
      LAYER M4 ;
        RECT  64.716 11.904 64.8 11.928 ;
    END
  END kv_request[93]
  PIN kv_request[94]
    DIRECTION INPUT ;
    USE SIGNAL ;
    PORT
      LAYER M4 ;
        RECT  64.716 12.048 64.8 12.072 ;
    END
  END kv_request[94]
  PIN kv_request[95]
    DIRECTION INPUT ;
    USE SIGNAL ;
    PORT
      LAYER M4 ;
        RECT  64.716 12.192 64.8 12.216 ;
    END
  END kv_request[95]
  PIN kv_request[96]
    DIRECTION INPUT ;
    USE SIGNAL ;
    PORT
      LAYER M4 ;
        RECT  64.716 12.288 64.8 12.312 ;
    END
  END kv_request[96]
  PIN kv_request[97]
    DIRECTION INPUT ;
    USE SIGNAL ;
    PORT
      LAYER M4 ;
        RECT  64.716 12.432 64.8 12.456 ;
    END
  END kv_request[97]
  PIN kv_request[98]
    DIRECTION INPUT ;
    USE SIGNAL ;
    PORT
      LAYER M4 ;
        RECT  64.716 12.576 64.8 12.6 ;
    END
  END kv_request[98]
  PIN kv_request[99]
    DIRECTION INPUT ;
    USE SIGNAL ;
    PORT
      LAYER M4 ;
        RECT  64.716 12.672 64.8 12.696 ;
    END
  END kv_request[99]
  PIN kv_request[9]
    DIRECTION INPUT ;
    USE SIGNAL ;
    PORT
      LAYER M4 ;
        RECT  64.716 1.296 64.8 1.32 ;
    END
  END kv_request[9]
  PIN request[0]
    DIRECTION INPUT ;
    USE SIGNAL ;
    PORT
      LAYER M5 ;
        RECT  0.192 64.716 0.216 64.8 ;
    END
  END request[0]
  PIN request[100]
    DIRECTION INPUT ;
    USE SIGNAL ;
    PORT
      LAYER M5 ;
        RECT  12.768 64.716 12.792 64.8 ;
    END
  END request[100]
  PIN request[101]
    DIRECTION INPUT ;
    USE SIGNAL ;
    PORT
      LAYER M3 ;
        RECT  12.888 64.762 12.906 64.8 ;
    END
  END request[101]
  PIN request[102]
    DIRECTION INPUT ;
    USE SIGNAL ;
    PORT
      LAYER M5 ;
        RECT  13.008 64.716 13.032 64.8 ;
    END
  END request[102]
  PIN request[103]
    DIRECTION INPUT ;
    USE SIGNAL ;
    PORT
      LAYER M3 ;
        RECT  13.14 64.762 13.158 64.8 ;
    END
  END request[103]
  PIN request[104]
    DIRECTION INPUT ;
    USE SIGNAL ;
    PORT
      LAYER M5 ;
        RECT  13.248 64.716 13.272 64.8 ;
    END
  END request[104]
  PIN request[105]
    DIRECTION INPUT ;
    USE SIGNAL ;
    PORT
      LAYER M3 ;
        RECT  13.392 64.762 13.41 64.8 ;
    END
  END request[105]
  PIN request[106]
    DIRECTION INPUT ;
    USE SIGNAL ;
    PORT
      LAYER M5 ;
        RECT  13.536 64.716 13.56 64.8 ;
    END
  END request[106]
  PIN request[107]
    DIRECTION INPUT ;
    USE SIGNAL ;
    PORT
      LAYER M3 ;
        RECT  13.644 64.762 13.662 64.8 ;
    END
  END request[107]
  PIN request[108]
    DIRECTION INPUT ;
    USE SIGNAL ;
    PORT
      LAYER M5 ;
        RECT  13.776 64.716 13.8 64.8 ;
    END
  END request[108]
  PIN request[109]
    DIRECTION INPUT ;
    USE SIGNAL ;
    PORT
      LAYER M3 ;
        RECT  13.896 64.762 13.914 64.8 ;
    END
  END request[109]
  PIN request[10]
    DIRECTION INPUT ;
    USE SIGNAL ;
    PORT
      LAYER M5 ;
        RECT  1.44 64.716 1.464 64.8 ;
    END
  END request[10]
  PIN request[110]
    DIRECTION INPUT ;
    USE SIGNAL ;
    PORT
      LAYER M5 ;
        RECT  14.016 64.716 14.04 64.8 ;
    END
  END request[110]
  PIN request[111]
    DIRECTION INPUT ;
    USE SIGNAL ;
    PORT
      LAYER M3 ;
        RECT  14.148 64.762 14.166 64.8 ;
    END
  END request[111]
  PIN request[112]
    DIRECTION INPUT ;
    USE SIGNAL ;
    PORT
      LAYER M5 ;
        RECT  14.256 64.716 14.28 64.8 ;
    END
  END request[112]
  PIN request[113]
    DIRECTION INPUT ;
    USE SIGNAL ;
    PORT
      LAYER M3 ;
        RECT  14.4 64.762 14.418 64.8 ;
    END
  END request[113]
  PIN request[114]
    DIRECTION INPUT ;
    USE SIGNAL ;
    PORT
      LAYER M5 ;
        RECT  14.544 64.716 14.568 64.8 ;
    END
  END request[114]
  PIN request[115]
    DIRECTION INPUT ;
    USE SIGNAL ;
    PORT
      LAYER M3 ;
        RECT  14.652 64.762 14.67 64.8 ;
    END
  END request[115]
  PIN request[116]
    DIRECTION INPUT ;
    USE SIGNAL ;
    PORT
      LAYER M5 ;
        RECT  14.784 64.716 14.808 64.8 ;
    END
  END request[116]
  PIN request[117]
    DIRECTION INPUT ;
    USE SIGNAL ;
    PORT
      LAYER M3 ;
        RECT  14.904 64.762 14.922 64.8 ;
    END
  END request[117]
  PIN request[118]
    DIRECTION INPUT ;
    USE SIGNAL ;
    PORT
      LAYER M5 ;
        RECT  15.024 64.716 15.048 64.8 ;
    END
  END request[118]
  PIN request[119]
    DIRECTION INPUT ;
    USE SIGNAL ;
    PORT
      LAYER M3 ;
        RECT  15.156 64.762 15.174 64.8 ;
    END
  END request[119]
  PIN request[11]
    DIRECTION INPUT ;
    USE SIGNAL ;
    PORT
      LAYER M3 ;
        RECT  1.548 64.762 1.566 64.8 ;
    END
  END request[11]
  PIN request[120]
    DIRECTION INPUT ;
    USE SIGNAL ;
    PORT
      LAYER M5 ;
        RECT  15.264 64.716 15.288 64.8 ;
    END
  END request[120]
  PIN request[121]
    DIRECTION INPUT ;
    USE SIGNAL ;
    PORT
      LAYER M3 ;
        RECT  15.408 64.762 15.426 64.8 ;
    END
  END request[121]
  PIN request[122]
    DIRECTION INPUT ;
    USE SIGNAL ;
    PORT
      LAYER M5 ;
        RECT  15.504 64.716 15.528 64.8 ;
    END
  END request[122]
  PIN request[123]
    DIRECTION INPUT ;
    USE SIGNAL ;
    PORT
      LAYER M3 ;
        RECT  15.66 64.762 15.678 64.8 ;
    END
  END request[123]
  PIN request[124]
    DIRECTION INPUT ;
    USE SIGNAL ;
    PORT
      LAYER M5 ;
        RECT  15.792 64.716 15.816 64.8 ;
    END
  END request[124]
  PIN request[125]
    DIRECTION INPUT ;
    USE SIGNAL ;
    PORT
      LAYER M3 ;
        RECT  15.912 64.762 15.93 64.8 ;
    END
  END request[125]
  PIN request[126]
    DIRECTION INPUT ;
    USE SIGNAL ;
    PORT
      LAYER M5 ;
        RECT  16.032 64.716 16.056 64.8 ;
    END
  END request[126]
  PIN request[127]
    DIRECTION INPUT ;
    USE SIGNAL ;
    PORT
      LAYER M3 ;
        RECT  16.164 64.762 16.182 64.8 ;
    END
  END request[127]
  PIN request[128]
    DIRECTION INPUT ;
    USE SIGNAL ;
    PORT
      LAYER M5 ;
        RECT  16.272 64.716 16.296 64.8 ;
    END
  END request[128]
  PIN request[129]
    DIRECTION INPUT ;
    USE SIGNAL ;
    PORT
      LAYER M3 ;
        RECT  16.416 64.762 16.434 64.8 ;
    END
  END request[129]
  PIN request[12]
    DIRECTION INPUT ;
    USE SIGNAL ;
    PORT
      LAYER M5 ;
        RECT  1.68 64.716 1.704 64.8 ;
    END
  END request[12]
  PIN request[130]
    DIRECTION INPUT ;
    USE SIGNAL ;
    PORT
      LAYER M5 ;
        RECT  16.512 64.716 16.536 64.8 ;
    END
  END request[130]
  PIN request[131]
    DIRECTION INPUT ;
    USE SIGNAL ;
    PORT
      LAYER M3 ;
        RECT  16.668 64.762 16.686 64.8 ;
    END
  END request[131]
  PIN request[132]
    DIRECTION INPUT ;
    USE SIGNAL ;
    PORT
      LAYER M5 ;
        RECT  16.8 64.716 16.824 64.8 ;
    END
  END request[132]
  PIN request[133]
    DIRECTION INPUT ;
    USE SIGNAL ;
    PORT
      LAYER M3 ;
        RECT  16.92 64.762 16.938 64.8 ;
    END
  END request[133]
  PIN request[134]
    DIRECTION INPUT ;
    USE SIGNAL ;
    PORT
      LAYER M5 ;
        RECT  17.04 64.716 17.064 64.8 ;
    END
  END request[134]
  PIN request[135]
    DIRECTION INPUT ;
    USE SIGNAL ;
    PORT
      LAYER M3 ;
        RECT  17.172 64.762 17.19 64.8 ;
    END
  END request[135]
  PIN request[136]
    DIRECTION INPUT ;
    USE SIGNAL ;
    PORT
      LAYER M5 ;
        RECT  17.28 64.716 17.304 64.8 ;
    END
  END request[136]
  PIN request[137]
    DIRECTION INPUT ;
    USE SIGNAL ;
    PORT
      LAYER M3 ;
        RECT  17.424 64.762 17.442 64.8 ;
    END
  END request[137]
  PIN request[138]
    DIRECTION INPUT ;
    USE SIGNAL ;
    PORT
      LAYER M5 ;
        RECT  17.52 64.716 17.544 64.8 ;
    END
  END request[138]
  PIN request[139]
    DIRECTION INPUT ;
    USE SIGNAL ;
    PORT
      LAYER M3 ;
        RECT  17.676 64.762 17.694 64.8 ;
    END
  END request[139]
  PIN request[13]
    DIRECTION INPUT ;
    USE SIGNAL ;
    PORT
      LAYER M3 ;
        RECT  1.8 64.762 1.818 64.8 ;
    END
  END request[13]
  PIN request[140]
    DIRECTION INPUT ;
    USE SIGNAL ;
    PORT
      LAYER M5 ;
        RECT  17.808 64.716 17.832 64.8 ;
    END
  END request[140]
  PIN request[141]
    DIRECTION INPUT ;
    USE SIGNAL ;
    PORT
      LAYER M3 ;
        RECT  17.928 64.762 17.946 64.8 ;
    END
  END request[141]
  PIN request[142]
    DIRECTION INPUT ;
    USE SIGNAL ;
    PORT
      LAYER M5 ;
        RECT  18.048 64.716 18.072 64.8 ;
    END
  END request[142]
  PIN request[143]
    DIRECTION INPUT ;
    USE SIGNAL ;
    PORT
      LAYER M3 ;
        RECT  18.18 64.762 18.198 64.8 ;
    END
  END request[143]
  PIN request[144]
    DIRECTION INPUT ;
    USE SIGNAL ;
    PORT
      LAYER M5 ;
        RECT  18.288 64.716 18.312 64.8 ;
    END
  END request[144]
  PIN request[145]
    DIRECTION INPUT ;
    USE SIGNAL ;
    PORT
      LAYER M3 ;
        RECT  18.432 64.762 18.45 64.8 ;
    END
  END request[145]
  PIN request[146]
    DIRECTION INPUT ;
    USE SIGNAL ;
    PORT
      LAYER M5 ;
        RECT  18.528 64.716 18.552 64.8 ;
    END
  END request[146]
  PIN request[147]
    DIRECTION INPUT ;
    USE SIGNAL ;
    PORT
      LAYER M3 ;
        RECT  18.684 64.762 18.702 64.8 ;
    END
  END request[147]
  PIN request[148]
    DIRECTION INPUT ;
    USE SIGNAL ;
    PORT
      LAYER M5 ;
        RECT  18.816 64.716 18.84 64.8 ;
    END
  END request[148]
  PIN request[149]
    DIRECTION INPUT ;
    USE SIGNAL ;
    PORT
      LAYER M3 ;
        RECT  18.936 64.762 18.954 64.8 ;
    END
  END request[149]
  PIN request[14]
    DIRECTION INPUT ;
    USE SIGNAL ;
    PORT
      LAYER M5 ;
        RECT  1.92 64.716 1.944 64.8 ;
    END
  END request[14]
  PIN request[150]
    DIRECTION INPUT ;
    USE SIGNAL ;
    PORT
      LAYER M5 ;
        RECT  19.056 64.716 19.08 64.8 ;
    END
  END request[150]
  PIN request[151]
    DIRECTION INPUT ;
    USE SIGNAL ;
    PORT
      LAYER M3 ;
        RECT  19.188 64.762 19.206 64.8 ;
    END
  END request[151]
  PIN request[152]
    DIRECTION INPUT ;
    USE SIGNAL ;
    PORT
      LAYER M5 ;
        RECT  19.296 64.716 19.32 64.8 ;
    END
  END request[152]
  PIN request[153]
    DIRECTION INPUT ;
    USE SIGNAL ;
    PORT
      LAYER M3 ;
        RECT  19.44 64.762 19.458 64.8 ;
    END
  END request[153]
  PIN request[154]
    DIRECTION INPUT ;
    USE SIGNAL ;
    PORT
      LAYER M5 ;
        RECT  19.536 64.716 19.56 64.8 ;
    END
  END request[154]
  PIN request[155]
    DIRECTION INPUT ;
    USE SIGNAL ;
    PORT
      LAYER M3 ;
        RECT  19.692 64.762 19.71 64.8 ;
    END
  END request[155]
  PIN request[156]
    DIRECTION INPUT ;
    USE SIGNAL ;
    PORT
      LAYER M5 ;
        RECT  19.824 64.716 19.848 64.8 ;
    END
  END request[156]
  PIN request[157]
    DIRECTION INPUT ;
    USE SIGNAL ;
    PORT
      LAYER M3 ;
        RECT  19.944 64.762 19.962 64.8 ;
    END
  END request[157]
  PIN request[158]
    DIRECTION INPUT ;
    USE SIGNAL ;
    PORT
      LAYER M5 ;
        RECT  20.064 64.716 20.088 64.8 ;
    END
  END request[158]
  PIN request[159]
    DIRECTION INPUT ;
    USE SIGNAL ;
    PORT
      LAYER M3 ;
        RECT  20.196 64.762 20.214 64.8 ;
    END
  END request[159]
  PIN request[15]
    DIRECTION INPUT ;
    USE SIGNAL ;
    PORT
      LAYER M3 ;
        RECT  2.052 64.762 2.07 64.8 ;
    END
  END request[15]
  PIN request[160]
    DIRECTION INPUT ;
    USE SIGNAL ;
    PORT
      LAYER M5 ;
        RECT  20.304 64.716 20.328 64.8 ;
    END
  END request[160]
  PIN request[161]
    DIRECTION INPUT ;
    USE SIGNAL ;
    PORT
      LAYER M3 ;
        RECT  20.448 64.762 20.466 64.8 ;
    END
  END request[161]
  PIN request[162]
    DIRECTION INPUT ;
    USE SIGNAL ;
    PORT
      LAYER M5 ;
        RECT  20.544 64.716 20.568 64.8 ;
    END
  END request[162]
  PIN request[163]
    DIRECTION INPUT ;
    USE SIGNAL ;
    PORT
      LAYER M3 ;
        RECT  20.7 64.762 20.718 64.8 ;
    END
  END request[163]
  PIN request[164]
    DIRECTION INPUT ;
    USE SIGNAL ;
    PORT
      LAYER M5 ;
        RECT  20.832 64.716 20.856 64.8 ;
    END
  END request[164]
  PIN request[165]
    DIRECTION INPUT ;
    USE SIGNAL ;
    PORT
      LAYER M3 ;
        RECT  20.952 64.762 20.97 64.8 ;
    END
  END request[165]
  PIN request[166]
    DIRECTION INPUT ;
    USE SIGNAL ;
    PORT
      LAYER M5 ;
        RECT  21.072 64.716 21.096 64.8 ;
    END
  END request[166]
  PIN request[167]
    DIRECTION INPUT ;
    USE SIGNAL ;
    PORT
      LAYER M3 ;
        RECT  21.204 64.762 21.222 64.8 ;
    END
  END request[167]
  PIN request[168]
    DIRECTION INPUT ;
    USE SIGNAL ;
    PORT
      LAYER M5 ;
        RECT  21.312 64.716 21.336 64.8 ;
    END
  END request[168]
  PIN request[169]
    DIRECTION INPUT ;
    USE SIGNAL ;
    PORT
      LAYER M3 ;
        RECT  21.456 64.762 21.474 64.8 ;
    END
  END request[169]
  PIN request[16]
    DIRECTION INPUT ;
    USE SIGNAL ;
    PORT
      LAYER M5 ;
        RECT  2.208 64.716 2.232 64.8 ;
    END
  END request[16]
  PIN request[170]
    DIRECTION INPUT ;
    USE SIGNAL ;
    PORT
      LAYER M5 ;
        RECT  21.552 64.716 21.576 64.8 ;
    END
  END request[170]
  PIN request[171]
    DIRECTION INPUT ;
    USE SIGNAL ;
    PORT
      LAYER M3 ;
        RECT  21.708 64.762 21.726 64.8 ;
    END
  END request[171]
  PIN request[172]
    DIRECTION INPUT ;
    USE SIGNAL ;
    PORT
      LAYER M5 ;
        RECT  21.84 64.716 21.864 64.8 ;
    END
  END request[172]
  PIN request[173]
    DIRECTION INPUT ;
    USE SIGNAL ;
    PORT
      LAYER M3 ;
        RECT  21.96 64.762 21.978 64.8 ;
    END
  END request[173]
  PIN request[174]
    DIRECTION INPUT ;
    USE SIGNAL ;
    PORT
      LAYER M5 ;
        RECT  22.08 64.716 22.104 64.8 ;
    END
  END request[174]
  PIN request[175]
    DIRECTION INPUT ;
    USE SIGNAL ;
    PORT
      LAYER M3 ;
        RECT  22.212 64.762 22.23 64.8 ;
    END
  END request[175]
  PIN request[176]
    DIRECTION INPUT ;
    USE SIGNAL ;
    PORT
      LAYER M5 ;
        RECT  22.32 64.716 22.344 64.8 ;
    END
  END request[176]
  PIN request[177]
    DIRECTION INPUT ;
    USE SIGNAL ;
    PORT
      LAYER M3 ;
        RECT  22.464 64.762 22.482 64.8 ;
    END
  END request[177]
  PIN request[178]
    DIRECTION INPUT ;
    USE SIGNAL ;
    PORT
      LAYER M5 ;
        RECT  22.56 64.716 22.584 64.8 ;
    END
  END request[178]
  PIN request[179]
    DIRECTION INPUT ;
    USE SIGNAL ;
    PORT
      LAYER M3 ;
        RECT  22.716 64.762 22.734 64.8 ;
    END
  END request[179]
  PIN request[17]
    DIRECTION INPUT ;
    USE SIGNAL ;
    PORT
      LAYER M3 ;
        RECT  2.304 64.762 2.322 64.8 ;
    END
  END request[17]
  PIN request[180]
    DIRECTION INPUT ;
    USE SIGNAL ;
    PORT
      LAYER M5 ;
        RECT  22.848 64.716 22.872 64.8 ;
    END
  END request[180]
  PIN request[181]
    DIRECTION INPUT ;
    USE SIGNAL ;
    PORT
      LAYER M3 ;
        RECT  22.968 64.762 22.986 64.8 ;
    END
  END request[181]
  PIN request[182]
    DIRECTION INPUT ;
    USE SIGNAL ;
    PORT
      LAYER M5 ;
        RECT  23.088 64.716 23.112 64.8 ;
    END
  END request[182]
  PIN request[183]
    DIRECTION INPUT ;
    USE SIGNAL ;
    PORT
      LAYER M3 ;
        RECT  23.22 64.762 23.238 64.8 ;
    END
  END request[183]
  PIN request[184]
    DIRECTION INPUT ;
    USE SIGNAL ;
    PORT
      LAYER M5 ;
        RECT  23.328 64.716 23.352 64.8 ;
    END
  END request[184]
  PIN request[185]
    DIRECTION INPUT ;
    USE SIGNAL ;
    PORT
      LAYER M3 ;
        RECT  23.472 64.762 23.49 64.8 ;
    END
  END request[185]
  PIN request[186]
    DIRECTION INPUT ;
    USE SIGNAL ;
    PORT
      LAYER M5 ;
        RECT  23.568 64.716 23.592 64.8 ;
    END
  END request[186]
  PIN request[187]
    DIRECTION INPUT ;
    USE SIGNAL ;
    PORT
      LAYER M3 ;
        RECT  23.724 64.762 23.742 64.8 ;
    END
  END request[187]
  PIN request[188]
    DIRECTION INPUT ;
    USE SIGNAL ;
    PORT
      LAYER M5 ;
        RECT  23.856 64.716 23.88 64.8 ;
    END
  END request[188]
  PIN request[189]
    DIRECTION INPUT ;
    USE SIGNAL ;
    PORT
      LAYER M3 ;
        RECT  23.976 64.762 23.994 64.8 ;
    END
  END request[189]
  PIN request[18]
    DIRECTION INPUT ;
    USE SIGNAL ;
    PORT
      LAYER M5 ;
        RECT  2.448 64.716 2.472 64.8 ;
    END
  END request[18]
  PIN request[190]
    DIRECTION INPUT ;
    USE SIGNAL ;
    PORT
      LAYER M5 ;
        RECT  24.096 64.716 24.12 64.8 ;
    END
  END request[190]
  PIN request[191]
    DIRECTION INPUT ;
    USE SIGNAL ;
    PORT
      LAYER M3 ;
        RECT  24.228 64.762 24.246 64.8 ;
    END
  END request[191]
  PIN request[192]
    DIRECTION INPUT ;
    USE SIGNAL ;
    PORT
      LAYER M5 ;
        RECT  24.336 64.716 24.36 64.8 ;
    END
  END request[192]
  PIN request[193]
    DIRECTION INPUT ;
    USE SIGNAL ;
    PORT
      LAYER M3 ;
        RECT  24.48 64.762 24.498 64.8 ;
    END
  END request[193]
  PIN request[194]
    DIRECTION INPUT ;
    USE SIGNAL ;
    PORT
      LAYER M5 ;
        RECT  24.576 64.716 24.6 64.8 ;
    END
  END request[194]
  PIN request[195]
    DIRECTION INPUT ;
    USE SIGNAL ;
    PORT
      LAYER M3 ;
        RECT  24.732 64.762 24.75 64.8 ;
    END
  END request[195]
  PIN request[196]
    DIRECTION INPUT ;
    USE SIGNAL ;
    PORT
      LAYER M5 ;
        RECT  24.816 64.716 24.84 64.8 ;
    END
  END request[196]
  PIN request[197]
    DIRECTION INPUT ;
    USE SIGNAL ;
    PORT
      LAYER M3 ;
        RECT  24.984 64.762 25.002 64.8 ;
    END
  END request[197]
  PIN request[198]
    DIRECTION INPUT ;
    USE SIGNAL ;
    PORT
      LAYER M5 ;
        RECT  25.104 64.716 25.128 64.8 ;
    END
  END request[198]
  PIN request[199]
    DIRECTION INPUT ;
    USE SIGNAL ;
    PORT
      LAYER M3 ;
        RECT  25.236 64.762 25.254 64.8 ;
    END
  END request[199]
  PIN request[19]
    DIRECTION INPUT ;
    USE SIGNAL ;
    PORT
      LAYER M3 ;
        RECT  2.556 64.762 2.574 64.8 ;
    END
  END request[19]
  PIN request[1]
    DIRECTION INPUT ;
    USE SIGNAL ;
    PORT
      LAYER M3 ;
        RECT  0.324 64.762 0.342 64.8 ;
    END
  END request[1]
  PIN request[200]
    DIRECTION INPUT ;
    USE SIGNAL ;
    PORT
      LAYER M5 ;
        RECT  25.344 64.716 25.368 64.8 ;
    END
  END request[200]
  PIN request[201]
    DIRECTION INPUT ;
    USE SIGNAL ;
    PORT
      LAYER M3 ;
        RECT  25.488 64.762 25.506 64.8 ;
    END
  END request[201]
  PIN request[202]
    DIRECTION INPUT ;
    USE SIGNAL ;
    PORT
      LAYER M5 ;
        RECT  25.584 64.716 25.608 64.8 ;
    END
  END request[202]
  PIN request[203]
    DIRECTION INPUT ;
    USE SIGNAL ;
    PORT
      LAYER M3 ;
        RECT  25.74 64.762 25.758 64.8 ;
    END
  END request[203]
  PIN request[204]
    DIRECTION INPUT ;
    USE SIGNAL ;
    PORT
      LAYER M5 ;
        RECT  25.824 64.716 25.848 64.8 ;
    END
  END request[204]
  PIN request[205]
    DIRECTION INPUT ;
    USE SIGNAL ;
    PORT
      LAYER M3 ;
        RECT  25.992 64.762 26.01 64.8 ;
    END
  END request[205]
  PIN request[206]
    DIRECTION INPUT ;
    USE SIGNAL ;
    PORT
      LAYER M5 ;
        RECT  26.112 64.716 26.136 64.8 ;
    END
  END request[206]
  PIN request[207]
    DIRECTION INPUT ;
    USE SIGNAL ;
    PORT
      LAYER M3 ;
        RECT  26.244 64.762 26.262 64.8 ;
    END
  END request[207]
  PIN request[208]
    DIRECTION INPUT ;
    USE SIGNAL ;
    PORT
      LAYER M5 ;
        RECT  26.352 64.716 26.376 64.8 ;
    END
  END request[208]
  PIN request[209]
    DIRECTION INPUT ;
    USE SIGNAL ;
    PORT
      LAYER M3 ;
        RECT  26.46 64.762 26.478 64.8 ;
    END
  END request[209]
  PIN request[20]
    DIRECTION INPUT ;
    USE SIGNAL ;
    PORT
      LAYER M5 ;
        RECT  2.688 64.716 2.712 64.8 ;
    END
  END request[20]
  PIN request[210]
    DIRECTION INPUT ;
    USE SIGNAL ;
    PORT
      LAYER M5 ;
        RECT  26.592 64.716 26.616 64.8 ;
    END
  END request[210]
  PIN request[211]
    DIRECTION INPUT ;
    USE SIGNAL ;
    PORT
      LAYER M3 ;
        RECT  26.712 64.762 26.73 64.8 ;
    END
  END request[211]
  PIN request[212]
    DIRECTION INPUT ;
    USE SIGNAL ;
    PORT
      LAYER M5 ;
        RECT  26.832 64.716 26.856 64.8 ;
    END
  END request[212]
  PIN request[213]
    DIRECTION INPUT ;
    USE SIGNAL ;
    PORT
      LAYER M3 ;
        RECT  26.964 64.762 26.982 64.8 ;
    END
  END request[213]
  PIN request[214]
    DIRECTION INPUT ;
    USE SIGNAL ;
    PORT
      LAYER M5 ;
        RECT  27.12 64.716 27.144 64.8 ;
    END
  END request[214]
  PIN request[215]
    DIRECTION INPUT ;
    USE SIGNAL ;
    PORT
      LAYER M3 ;
        RECT  27.216 64.762 27.234 64.8 ;
    END
  END request[215]
  PIN request[216]
    DIRECTION INPUT ;
    USE SIGNAL ;
    PORT
      LAYER M5 ;
        RECT  27.36 64.716 27.384 64.8 ;
    END
  END request[216]
  PIN request[217]
    DIRECTION INPUT ;
    USE SIGNAL ;
    PORT
      LAYER M3 ;
        RECT  27.468 64.762 27.486 64.8 ;
    END
  END request[217]
  PIN request[218]
    DIRECTION INPUT ;
    USE SIGNAL ;
    PORT
      LAYER M5 ;
        RECT  27.6 64.716 27.624 64.8 ;
    END
  END request[218]
  PIN request[219]
    DIRECTION INPUT ;
    USE SIGNAL ;
    PORT
      LAYER M3 ;
        RECT  27.72 64.762 27.738 64.8 ;
    END
  END request[219]
  PIN request[21]
    DIRECTION INPUT ;
    USE SIGNAL ;
    PORT
      LAYER M3 ;
        RECT  2.808 64.762 2.826 64.8 ;
    END
  END request[21]
  PIN request[220]
    DIRECTION INPUT ;
    USE SIGNAL ;
    PORT
      LAYER M5 ;
        RECT  27.84 64.716 27.864 64.8 ;
    END
  END request[220]
  PIN request[221]
    DIRECTION INPUT ;
    USE SIGNAL ;
    PORT
      LAYER M3 ;
        RECT  27.972 64.762 27.99 64.8 ;
    END
  END request[221]
  PIN request[222]
    DIRECTION INPUT ;
    USE SIGNAL ;
    PORT
      LAYER M5 ;
        RECT  28.128 64.716 28.152 64.8 ;
    END
  END request[222]
  PIN request[223]
    DIRECTION INPUT ;
    USE SIGNAL ;
    PORT
      LAYER M3 ;
        RECT  28.224 64.762 28.242 64.8 ;
    END
  END request[223]
  PIN request[224]
    DIRECTION INPUT ;
    USE SIGNAL ;
    PORT
      LAYER M5 ;
        RECT  28.368 64.716 28.392 64.8 ;
    END
  END request[224]
  PIN request[225]
    DIRECTION INPUT ;
    USE SIGNAL ;
    PORT
      LAYER M3 ;
        RECT  28.476 64.762 28.494 64.8 ;
    END
  END request[225]
  PIN request[226]
    DIRECTION INPUT ;
    USE SIGNAL ;
    PORT
      LAYER M5 ;
        RECT  28.608 64.716 28.632 64.8 ;
    END
  END request[226]
  PIN request[227]
    DIRECTION INPUT ;
    USE SIGNAL ;
    PORT
      LAYER M3 ;
        RECT  28.728 64.762 28.746 64.8 ;
    END
  END request[227]
  PIN request[228]
    DIRECTION INPUT ;
    USE SIGNAL ;
    PORT
      LAYER M5 ;
        RECT  28.848 64.716 28.872 64.8 ;
    END
  END request[228]
  PIN request[229]
    DIRECTION INPUT ;
    USE SIGNAL ;
    PORT
      LAYER M3 ;
        RECT  28.98 64.762 28.998 64.8 ;
    END
  END request[229]
  PIN request[22]
    DIRECTION INPUT ;
    USE SIGNAL ;
    PORT
      LAYER M5 ;
        RECT  2.928 64.716 2.952 64.8 ;
    END
  END request[22]
  PIN request[230]
    DIRECTION INPUT ;
    USE SIGNAL ;
    PORT
      LAYER M5 ;
        RECT  29.136 64.716 29.16 64.8 ;
    END
  END request[230]
  PIN request[231]
    DIRECTION INPUT ;
    USE SIGNAL ;
    PORT
      LAYER M3 ;
        RECT  29.232 64.762 29.25 64.8 ;
    END
  END request[231]
  PIN request[232]
    DIRECTION INPUT ;
    USE SIGNAL ;
    PORT
      LAYER M5 ;
        RECT  29.376 64.716 29.4 64.8 ;
    END
  END request[232]
  PIN request[233]
    DIRECTION INPUT ;
    USE SIGNAL ;
    PORT
      LAYER M3 ;
        RECT  29.484 64.762 29.502 64.8 ;
    END
  END request[233]
  PIN request[234]
    DIRECTION INPUT ;
    USE SIGNAL ;
    PORT
      LAYER M5 ;
        RECT  29.616 64.716 29.64 64.8 ;
    END
  END request[234]
  PIN request[235]
    DIRECTION INPUT ;
    USE SIGNAL ;
    PORT
      LAYER M3 ;
        RECT  29.736 64.762 29.754 64.8 ;
    END
  END request[235]
  PIN request[236]
    DIRECTION INPUT ;
    USE SIGNAL ;
    PORT
      LAYER M5 ;
        RECT  29.856 64.716 29.88 64.8 ;
    END
  END request[236]
  PIN request[237]
    DIRECTION INPUT ;
    USE SIGNAL ;
    PORT
      LAYER M3 ;
        RECT  29.988 64.762 30.006 64.8 ;
    END
  END request[237]
  PIN request[238]
    DIRECTION INPUT ;
    USE SIGNAL ;
    PORT
      LAYER M5 ;
        RECT  30.144 64.716 30.168 64.8 ;
    END
  END request[238]
  PIN request[239]
    DIRECTION INPUT ;
    USE SIGNAL ;
    PORT
      LAYER M3 ;
        RECT  30.24 64.762 30.258 64.8 ;
    END
  END request[239]
  PIN request[23]
    DIRECTION INPUT ;
    USE SIGNAL ;
    PORT
      LAYER M3 ;
        RECT  3.06 64.762 3.078 64.8 ;
    END
  END request[23]
  PIN request[240]
    DIRECTION INPUT ;
    USE SIGNAL ;
    PORT
      LAYER M5 ;
        RECT  30.384 64.716 30.408 64.8 ;
    END
  END request[240]
  PIN request[241]
    DIRECTION INPUT ;
    USE SIGNAL ;
    PORT
      LAYER M3 ;
        RECT  30.492 64.762 30.51 64.8 ;
    END
  END request[241]
  PIN request[242]
    DIRECTION INPUT ;
    USE SIGNAL ;
    PORT
      LAYER M5 ;
        RECT  30.624 64.716 30.648 64.8 ;
    END
  END request[242]
  PIN request[243]
    DIRECTION INPUT ;
    USE SIGNAL ;
    PORT
      LAYER M3 ;
        RECT  30.744 64.762 30.762 64.8 ;
    END
  END request[243]
  PIN request[244]
    DIRECTION INPUT ;
    USE SIGNAL ;
    PORT
      LAYER M5 ;
        RECT  30.864 64.716 30.888 64.8 ;
    END
  END request[244]
  PIN request[245]
    DIRECTION INPUT ;
    USE SIGNAL ;
    PORT
      LAYER M3 ;
        RECT  30.996 64.762 31.014 64.8 ;
    END
  END request[245]
  PIN request[246]
    DIRECTION INPUT ;
    USE SIGNAL ;
    PORT
      LAYER M5 ;
        RECT  31.152 64.716 31.176 64.8 ;
    END
  END request[246]
  PIN request[247]
    DIRECTION INPUT ;
    USE SIGNAL ;
    PORT
      LAYER M3 ;
        RECT  31.248 64.762 31.266 64.8 ;
    END
  END request[247]
  PIN request[248]
    DIRECTION INPUT ;
    USE SIGNAL ;
    PORT
      LAYER M5 ;
        RECT  31.392 64.716 31.416 64.8 ;
    END
  END request[248]
  PIN request[249]
    DIRECTION INPUT ;
    USE SIGNAL ;
    PORT
      LAYER M3 ;
        RECT  31.5 64.762 31.518 64.8 ;
    END
  END request[249]
  PIN request[24]
    DIRECTION INPUT ;
    USE SIGNAL ;
    PORT
      LAYER M5 ;
        RECT  3.216 64.716 3.24 64.8 ;
    END
  END request[24]
  PIN request[250]
    DIRECTION INPUT ;
    USE SIGNAL ;
    PORT
      LAYER M5 ;
        RECT  31.632 64.716 31.656 64.8 ;
    END
  END request[250]
  PIN request[251]
    DIRECTION INPUT ;
    USE SIGNAL ;
    PORT
      LAYER M3 ;
        RECT  31.752 64.762 31.77 64.8 ;
    END
  END request[251]
  PIN request[252]
    DIRECTION INPUT ;
    USE SIGNAL ;
    PORT
      LAYER M5 ;
        RECT  31.872 64.716 31.896 64.8 ;
    END
  END request[252]
  PIN request[253]
    DIRECTION INPUT ;
    USE SIGNAL ;
    PORT
      LAYER M3 ;
        RECT  32.004 64.762 32.022 64.8 ;
    END
  END request[253]
  PIN request[254]
    DIRECTION INPUT ;
    USE SIGNAL ;
    PORT
      LAYER M5 ;
        RECT  32.16 64.716 32.184 64.8 ;
    END
  END request[254]
  PIN request[255]
    DIRECTION INPUT ;
    USE SIGNAL ;
    PORT
      LAYER M3 ;
        RECT  32.256 64.762 32.274 64.8 ;
    END
  END request[255]
  PIN request[256]
    DIRECTION INPUT ;
    USE SIGNAL ;
    PORT
      LAYER M5 ;
        RECT  32.4 64.716 32.424 64.8 ;
    END
  END request[256]
  PIN request[257]
    DIRECTION INPUT ;
    USE SIGNAL ;
    PORT
      LAYER M3 ;
        RECT  32.508 64.762 32.526 64.8 ;
    END
  END request[257]
  PIN request[258]
    DIRECTION INPUT ;
    USE SIGNAL ;
    PORT
      LAYER M5 ;
        RECT  32.64 64.716 32.664 64.8 ;
    END
  END request[258]
  PIN request[259]
    DIRECTION INPUT ;
    USE SIGNAL ;
    PORT
      LAYER M3 ;
        RECT  32.76 64.762 32.778 64.8 ;
    END
  END request[259]
  PIN request[25]
    DIRECTION INPUT ;
    USE SIGNAL ;
    PORT
      LAYER M3 ;
        RECT  3.312 64.762 3.33 64.8 ;
    END
  END request[25]
  PIN request[260]
    DIRECTION INPUT ;
    USE SIGNAL ;
    PORT
      LAYER M5 ;
        RECT  32.88 64.716 32.904 64.8 ;
    END
  END request[260]
  PIN request[261]
    DIRECTION INPUT ;
    USE SIGNAL ;
    PORT
      LAYER M3 ;
        RECT  33.012 64.762 33.03 64.8 ;
    END
  END request[261]
  PIN request[262]
    DIRECTION INPUT ;
    USE SIGNAL ;
    PORT
      LAYER M5 ;
        RECT  33.12 64.716 33.144 64.8 ;
    END
  END request[262]
  PIN request[263]
    DIRECTION INPUT ;
    USE SIGNAL ;
    PORT
      LAYER M3 ;
        RECT  33.264 64.762 33.282 64.8 ;
    END
  END request[263]
  PIN request[264]
    DIRECTION INPUT ;
    USE SIGNAL ;
    PORT
      LAYER M5 ;
        RECT  33.408 64.716 33.432 64.8 ;
    END
  END request[264]
  PIN request[265]
    DIRECTION INPUT ;
    USE SIGNAL ;
    PORT
      LAYER M3 ;
        RECT  33.516 64.762 33.534 64.8 ;
    END
  END request[265]
  PIN request[266]
    DIRECTION INPUT ;
    USE SIGNAL ;
    PORT
      LAYER M5 ;
        RECT  33.648 64.716 33.672 64.8 ;
    END
  END request[266]
  PIN request[267]
    DIRECTION INPUT ;
    USE SIGNAL ;
    PORT
      LAYER M3 ;
        RECT  33.768 64.762 33.786 64.8 ;
    END
  END request[267]
  PIN request[268]
    DIRECTION INPUT ;
    USE SIGNAL ;
    PORT
      LAYER M5 ;
        RECT  33.888 64.716 33.912 64.8 ;
    END
  END request[268]
  PIN request[269]
    DIRECTION INPUT ;
    USE SIGNAL ;
    PORT
      LAYER M3 ;
        RECT  34.02 64.762 34.038 64.8 ;
    END
  END request[269]
  PIN request[26]
    DIRECTION INPUT ;
    USE SIGNAL ;
    PORT
      LAYER M5 ;
        RECT  3.456 64.716 3.48 64.8 ;
    END
  END request[26]
  PIN request[270]
    DIRECTION INPUT ;
    USE SIGNAL ;
    PORT
      LAYER M5 ;
        RECT  34.128 64.716 34.152 64.8 ;
    END
  END request[270]
  PIN request[271]
    DIRECTION INPUT ;
    USE SIGNAL ;
    PORT
      LAYER M3 ;
        RECT  34.272 64.762 34.29 64.8 ;
    END
  END request[271]
  PIN request[272]
    DIRECTION INPUT ;
    USE SIGNAL ;
    PORT
      LAYER M5 ;
        RECT  34.416 64.716 34.44 64.8 ;
    END
  END request[272]
  PIN request[273]
    DIRECTION INPUT ;
    USE SIGNAL ;
    PORT
      LAYER M3 ;
        RECT  34.524 64.762 34.542 64.8 ;
    END
  END request[273]
  PIN request[274]
    DIRECTION INPUT ;
    USE SIGNAL ;
    PORT
      LAYER M5 ;
        RECT  34.656 64.716 34.68 64.8 ;
    END
  END request[274]
  PIN request[275]
    DIRECTION INPUT ;
    USE SIGNAL ;
    PORT
      LAYER M3 ;
        RECT  34.776 64.762 34.794 64.8 ;
    END
  END request[275]
  PIN request[276]
    DIRECTION INPUT ;
    USE SIGNAL ;
    PORT
      LAYER M5 ;
        RECT  34.896 64.716 34.92 64.8 ;
    END
  END request[276]
  PIN request[277]
    DIRECTION INPUT ;
    USE SIGNAL ;
    PORT
      LAYER M3 ;
        RECT  35.028 64.762 35.046 64.8 ;
    END
  END request[277]
  PIN request[278]
    DIRECTION INPUT ;
    USE SIGNAL ;
    PORT
      LAYER M5 ;
        RECT  35.136 64.716 35.16 64.8 ;
    END
  END request[278]
  PIN request[279]
    DIRECTION INPUT ;
    USE SIGNAL ;
    PORT
      LAYER M3 ;
        RECT  35.28 64.762 35.298 64.8 ;
    END
  END request[279]
  PIN request[27]
    DIRECTION INPUT ;
    USE SIGNAL ;
    PORT
      LAYER M3 ;
        RECT  3.564 64.762 3.582 64.8 ;
    END
  END request[27]
  PIN request[280]
    DIRECTION INPUT ;
    USE SIGNAL ;
    PORT
      LAYER M5 ;
        RECT  35.424 64.716 35.448 64.8 ;
    END
  END request[280]
  PIN request[281]
    DIRECTION INPUT ;
    USE SIGNAL ;
    PORT
      LAYER M3 ;
        RECT  35.532 64.762 35.55 64.8 ;
    END
  END request[281]
  PIN request[282]
    DIRECTION INPUT ;
    USE SIGNAL ;
    PORT
      LAYER M5 ;
        RECT  35.664 64.716 35.688 64.8 ;
    END
  END request[282]
  PIN request[283]
    DIRECTION INPUT ;
    USE SIGNAL ;
    PORT
      LAYER M3 ;
        RECT  35.784 64.762 35.802 64.8 ;
    END
  END request[283]
  PIN request[284]
    DIRECTION INPUT ;
    USE SIGNAL ;
    PORT
      LAYER M5 ;
        RECT  35.904 64.716 35.928 64.8 ;
    END
  END request[284]
  PIN request[285]
    DIRECTION INPUT ;
    USE SIGNAL ;
    PORT
      LAYER M3 ;
        RECT  36.036 64.762 36.054 64.8 ;
    END
  END request[285]
  PIN request[286]
    DIRECTION INPUT ;
    USE SIGNAL ;
    PORT
      LAYER M5 ;
        RECT  36.144 64.716 36.168 64.8 ;
    END
  END request[286]
  PIN request[287]
    DIRECTION INPUT ;
    USE SIGNAL ;
    PORT
      LAYER M3 ;
        RECT  36.288 64.762 36.306 64.8 ;
    END
  END request[287]
  PIN request[288]
    DIRECTION INPUT ;
    USE SIGNAL ;
    PORT
      LAYER M5 ;
        RECT  36.432 64.716 36.456 64.8 ;
    END
  END request[288]
  PIN request[289]
    DIRECTION INPUT ;
    USE SIGNAL ;
    PORT
      LAYER M3 ;
        RECT  36.54 64.762 36.558 64.8 ;
    END
  END request[289]
  PIN request[28]
    DIRECTION INPUT ;
    USE SIGNAL ;
    PORT
      LAYER M5 ;
        RECT  3.696 64.716 3.72 64.8 ;
    END
  END request[28]
  PIN request[290]
    DIRECTION INPUT ;
    USE SIGNAL ;
    PORT
      LAYER M5 ;
        RECT  36.672 64.716 36.696 64.8 ;
    END
  END request[290]
  PIN request[291]
    DIRECTION INPUT ;
    USE SIGNAL ;
    PORT
      LAYER M3 ;
        RECT  36.792 64.762 36.81 64.8 ;
    END
  END request[291]
  PIN request[292]
    DIRECTION INPUT ;
    USE SIGNAL ;
    PORT
      LAYER M5 ;
        RECT  36.912 64.716 36.936 64.8 ;
    END
  END request[292]
  PIN request[293]
    DIRECTION INPUT ;
    USE SIGNAL ;
    PORT
      LAYER M3 ;
        RECT  37.044 64.762 37.062 64.8 ;
    END
  END request[293]
  PIN request[294]
    DIRECTION INPUT ;
    USE SIGNAL ;
    PORT
      LAYER M5 ;
        RECT  37.152 64.716 37.176 64.8 ;
    END
  END request[294]
  PIN request[295]
    DIRECTION INPUT ;
    USE SIGNAL ;
    PORT
      LAYER M3 ;
        RECT  37.296 64.762 37.314 64.8 ;
    END
  END request[295]
  PIN request[296]
    DIRECTION INPUT ;
    USE SIGNAL ;
    PORT
      LAYER M5 ;
        RECT  37.44 64.716 37.464 64.8 ;
    END
  END request[296]
  PIN request[297]
    DIRECTION INPUT ;
    USE SIGNAL ;
    PORT
      LAYER M3 ;
        RECT  37.548 64.762 37.566 64.8 ;
    END
  END request[297]
  PIN request[298]
    DIRECTION INPUT ;
    USE SIGNAL ;
    PORT
      LAYER M5 ;
        RECT  37.68 64.716 37.704 64.8 ;
    END
  END request[298]
  PIN request[299]
    DIRECTION INPUT ;
    USE SIGNAL ;
    PORT
      LAYER M3 ;
        RECT  37.8 64.762 37.818 64.8 ;
    END
  END request[299]
  PIN request[29]
    DIRECTION INPUT ;
    USE SIGNAL ;
    PORT
      LAYER M3 ;
        RECT  3.816 64.762 3.834 64.8 ;
    END
  END request[29]
  PIN request[2]
    DIRECTION INPUT ;
    USE SIGNAL ;
    PORT
      LAYER M5 ;
        RECT  0.432 64.716 0.456 64.8 ;
    END
  END request[2]
  PIN request[300]
    DIRECTION INPUT ;
    USE SIGNAL ;
    PORT
      LAYER M5 ;
        RECT  37.92 64.716 37.944 64.8 ;
    END
  END request[300]
  PIN request[301]
    DIRECTION INPUT ;
    USE SIGNAL ;
    PORT
      LAYER M3 ;
        RECT  38.052 64.762 38.07 64.8 ;
    END
  END request[301]
  PIN request[302]
    DIRECTION INPUT ;
    USE SIGNAL ;
    PORT
      LAYER M5 ;
        RECT  38.16 64.716 38.184 64.8 ;
    END
  END request[302]
  PIN request[303]
    DIRECTION INPUT ;
    USE SIGNAL ;
    PORT
      LAYER M3 ;
        RECT  38.304 64.762 38.322 64.8 ;
    END
  END request[303]
  PIN request[304]
    DIRECTION INPUT ;
    USE SIGNAL ;
    PORT
      LAYER M5 ;
        RECT  38.448 64.716 38.472 64.8 ;
    END
  END request[304]
  PIN request[305]
    DIRECTION INPUT ;
    USE SIGNAL ;
    PORT
      LAYER M3 ;
        RECT  38.556 64.762 38.574 64.8 ;
    END
  END request[305]
  PIN request[306]
    DIRECTION INPUT ;
    USE SIGNAL ;
    PORT
      LAYER M5 ;
        RECT  38.688 64.716 38.712 64.8 ;
    END
  END request[306]
  PIN request[307]
    DIRECTION INPUT ;
    USE SIGNAL ;
    PORT
      LAYER M3 ;
        RECT  38.808 64.762 38.826 64.8 ;
    END
  END request[307]
  PIN request[308]
    DIRECTION INPUT ;
    USE SIGNAL ;
    PORT
      LAYER M5 ;
        RECT  38.928 64.716 38.952 64.8 ;
    END
  END request[308]
  PIN request[309]
    DIRECTION INPUT ;
    USE SIGNAL ;
    PORT
      LAYER M3 ;
        RECT  39.06 64.762 39.078 64.8 ;
    END
  END request[309]
  PIN request[30]
    DIRECTION INPUT ;
    USE SIGNAL ;
    PORT
      LAYER M5 ;
        RECT  3.936 64.716 3.96 64.8 ;
    END
  END request[30]
  PIN request[310]
    DIRECTION INPUT ;
    USE SIGNAL ;
    PORT
      LAYER M5 ;
        RECT  39.168 64.716 39.192 64.8 ;
    END
  END request[310]
  PIN request[311]
    DIRECTION INPUT ;
    USE SIGNAL ;
    PORT
      LAYER M3 ;
        RECT  39.312 64.762 39.33 64.8 ;
    END
  END request[311]
  PIN request[312]
    DIRECTION INPUT ;
    USE SIGNAL ;
    PORT
      LAYER M5 ;
        RECT  39.456 64.716 39.48 64.8 ;
    END
  END request[312]
  PIN request[313]
    DIRECTION INPUT ;
    USE SIGNAL ;
    PORT
      LAYER M3 ;
        RECT  39.564 64.762 39.582 64.8 ;
    END
  END request[313]
  PIN request[314]
    DIRECTION INPUT ;
    USE SIGNAL ;
    PORT
      LAYER M5 ;
        RECT  39.696 64.716 39.72 64.8 ;
    END
  END request[314]
  PIN request[315]
    DIRECTION INPUT ;
    USE SIGNAL ;
    PORT
      LAYER M3 ;
        RECT  39.816 64.762 39.834 64.8 ;
    END
  END request[315]
  PIN request[316]
    DIRECTION INPUT ;
    USE SIGNAL ;
    PORT
      LAYER M5 ;
        RECT  39.936 64.716 39.96 64.8 ;
    END
  END request[316]
  PIN request[317]
    DIRECTION INPUT ;
    USE SIGNAL ;
    PORT
      LAYER M3 ;
        RECT  40.068 64.762 40.086 64.8 ;
    END
  END request[317]
  PIN request[318]
    DIRECTION INPUT ;
    USE SIGNAL ;
    PORT
      LAYER M5 ;
        RECT  40.176 64.716 40.2 64.8 ;
    END
  END request[318]
  PIN request[319]
    DIRECTION INPUT ;
    USE SIGNAL ;
    PORT
      LAYER M3 ;
        RECT  40.32 64.762 40.338 64.8 ;
    END
  END request[319]
  PIN request[31]
    DIRECTION INPUT ;
    USE SIGNAL ;
    PORT
      LAYER M3 ;
        RECT  4.068 64.762 4.086 64.8 ;
    END
  END request[31]
  PIN request[320]
    DIRECTION INPUT ;
    USE SIGNAL ;
    PORT
      LAYER M5 ;
        RECT  40.464 64.716 40.488 64.8 ;
    END
  END request[320]
  PIN request[321]
    DIRECTION INPUT ;
    USE SIGNAL ;
    PORT
      LAYER M3 ;
        RECT  40.572 64.762 40.59 64.8 ;
    END
  END request[321]
  PIN request[322]
    DIRECTION INPUT ;
    USE SIGNAL ;
    PORT
      LAYER M5 ;
        RECT  40.704 64.716 40.728 64.8 ;
    END
  END request[322]
  PIN request[323]
    DIRECTION INPUT ;
    USE SIGNAL ;
    PORT
      LAYER M3 ;
        RECT  40.824 64.762 40.842 64.8 ;
    END
  END request[323]
  PIN request[324]
    DIRECTION INPUT ;
    USE SIGNAL ;
    PORT
      LAYER M5 ;
        RECT  40.944 64.716 40.968 64.8 ;
    END
  END request[324]
  PIN request[325]
    DIRECTION INPUT ;
    USE SIGNAL ;
    PORT
      LAYER M3 ;
        RECT  41.076 64.762 41.094 64.8 ;
    END
  END request[325]
  PIN request[326]
    DIRECTION INPUT ;
    USE SIGNAL ;
    PORT
      LAYER M5 ;
        RECT  41.184 64.716 41.208 64.8 ;
    END
  END request[326]
  PIN request[327]
    DIRECTION INPUT ;
    USE SIGNAL ;
    PORT
      LAYER M3 ;
        RECT  41.328 64.762 41.346 64.8 ;
    END
  END request[327]
  PIN request[328]
    DIRECTION INPUT ;
    USE SIGNAL ;
    PORT
      LAYER M5 ;
        RECT  41.424 64.716 41.448 64.8 ;
    END
  END request[328]
  PIN request[329]
    DIRECTION INPUT ;
    USE SIGNAL ;
    PORT
      LAYER M3 ;
        RECT  41.58 64.762 41.598 64.8 ;
    END
  END request[329]
  PIN request[32]
    DIRECTION INPUT ;
    USE SIGNAL ;
    PORT
      LAYER M5 ;
        RECT  4.224 64.716 4.248 64.8 ;
    END
  END request[32]
  PIN request[330]
    DIRECTION INPUT ;
    USE SIGNAL ;
    PORT
      LAYER M5 ;
        RECT  41.712 64.716 41.736 64.8 ;
    END
  END request[330]
  PIN request[331]
    DIRECTION INPUT ;
    USE SIGNAL ;
    PORT
      LAYER M3 ;
        RECT  41.832 64.762 41.85 64.8 ;
    END
  END request[331]
  PIN request[332]
    DIRECTION INPUT ;
    USE SIGNAL ;
    PORT
      LAYER M5 ;
        RECT  41.952 64.716 41.976 64.8 ;
    END
  END request[332]
  PIN request[333]
    DIRECTION INPUT ;
    USE SIGNAL ;
    PORT
      LAYER M3 ;
        RECT  42.084 64.762 42.102 64.8 ;
    END
  END request[333]
  PIN request[334]
    DIRECTION INPUT ;
    USE SIGNAL ;
    PORT
      LAYER M5 ;
        RECT  42.192 64.716 42.216 64.8 ;
    END
  END request[334]
  PIN request[335]
    DIRECTION INPUT ;
    USE SIGNAL ;
    PORT
      LAYER M3 ;
        RECT  42.336 64.762 42.354 64.8 ;
    END
  END request[335]
  PIN request[336]
    DIRECTION INPUT ;
    USE SIGNAL ;
    PORT
      LAYER M5 ;
        RECT  42.432 64.716 42.456 64.8 ;
    END
  END request[336]
  PIN request[337]
    DIRECTION INPUT ;
    USE SIGNAL ;
    PORT
      LAYER M3 ;
        RECT  42.588 64.762 42.606 64.8 ;
    END
  END request[337]
  PIN request[338]
    DIRECTION INPUT ;
    USE SIGNAL ;
    PORT
      LAYER M5 ;
        RECT  42.72 64.716 42.744 64.8 ;
    END
  END request[338]
  PIN request[339]
    DIRECTION INPUT ;
    USE SIGNAL ;
    PORT
      LAYER M3 ;
        RECT  42.84 64.762 42.858 64.8 ;
    END
  END request[339]
  PIN request[33]
    DIRECTION INPUT ;
    USE SIGNAL ;
    PORT
      LAYER M3 ;
        RECT  4.32 64.762 4.338 64.8 ;
    END
  END request[33]
  PIN request[340]
    DIRECTION INPUT ;
    USE SIGNAL ;
    PORT
      LAYER M5 ;
        RECT  42.96 64.716 42.984 64.8 ;
    END
  END request[340]
  PIN request[341]
    DIRECTION INPUT ;
    USE SIGNAL ;
    PORT
      LAYER M3 ;
        RECT  43.092 64.762 43.11 64.8 ;
    END
  END request[341]
  PIN request[342]
    DIRECTION INPUT ;
    USE SIGNAL ;
    PORT
      LAYER M5 ;
        RECT  43.2 64.716 43.224 64.8 ;
    END
  END request[342]
  PIN request[343]
    DIRECTION INPUT ;
    USE SIGNAL ;
    PORT
      LAYER M3 ;
        RECT  43.344 64.762 43.362 64.8 ;
    END
  END request[343]
  PIN request[344]
    DIRECTION INPUT ;
    USE SIGNAL ;
    PORT
      LAYER M5 ;
        RECT  43.44 64.716 43.464 64.8 ;
    END
  END request[344]
  PIN request[345]
    DIRECTION INPUT ;
    USE SIGNAL ;
    PORT
      LAYER M3 ;
        RECT  43.596 64.762 43.614 64.8 ;
    END
  END request[345]
  PIN request[346]
    DIRECTION INPUT ;
    USE SIGNAL ;
    PORT
      LAYER M5 ;
        RECT  43.728 64.716 43.752 64.8 ;
    END
  END request[346]
  PIN request[347]
    DIRECTION INPUT ;
    USE SIGNAL ;
    PORT
      LAYER M3 ;
        RECT  43.848 64.762 43.866 64.8 ;
    END
  END request[347]
  PIN request[348]
    DIRECTION INPUT ;
    USE SIGNAL ;
    PORT
      LAYER M5 ;
        RECT  43.968 64.716 43.992 64.8 ;
    END
  END request[348]
  PIN request[349]
    DIRECTION INPUT ;
    USE SIGNAL ;
    PORT
      LAYER M3 ;
        RECT  44.1 64.762 44.118 64.8 ;
    END
  END request[349]
  PIN request[34]
    DIRECTION INPUT ;
    USE SIGNAL ;
    PORT
      LAYER M5 ;
        RECT  4.464 64.716 4.488 64.8 ;
    END
  END request[34]
  PIN request[350]
    DIRECTION INPUT ;
    USE SIGNAL ;
    PORT
      LAYER M5 ;
        RECT  44.208 64.716 44.232 64.8 ;
    END
  END request[350]
  PIN request[351]
    DIRECTION INPUT ;
    USE SIGNAL ;
    PORT
      LAYER M3 ;
        RECT  44.352 64.762 44.37 64.8 ;
    END
  END request[351]
  PIN request[352]
    DIRECTION INPUT ;
    USE SIGNAL ;
    PORT
      LAYER M5 ;
        RECT  44.448 64.716 44.472 64.8 ;
    END
  END request[352]
  PIN request[353]
    DIRECTION INPUT ;
    USE SIGNAL ;
    PORT
      LAYER M3 ;
        RECT  44.604 64.762 44.622 64.8 ;
    END
  END request[353]
  PIN request[354]
    DIRECTION INPUT ;
    USE SIGNAL ;
    PORT
      LAYER M5 ;
        RECT  44.736 64.716 44.76 64.8 ;
    END
  END request[354]
  PIN request[355]
    DIRECTION INPUT ;
    USE SIGNAL ;
    PORT
      LAYER M3 ;
        RECT  44.856 64.762 44.874 64.8 ;
    END
  END request[355]
  PIN request[356]
    DIRECTION INPUT ;
    USE SIGNAL ;
    PORT
      LAYER M5 ;
        RECT  44.976 64.716 45 64.8 ;
    END
  END request[356]
  PIN request[357]
    DIRECTION INPUT ;
    USE SIGNAL ;
    PORT
      LAYER M3 ;
        RECT  45.108 64.762 45.126 64.8 ;
    END
  END request[357]
  PIN request[358]
    DIRECTION INPUT ;
    USE SIGNAL ;
    PORT
      LAYER M5 ;
        RECT  45.216 64.716 45.24 64.8 ;
    END
  END request[358]
  PIN request[359]
    DIRECTION INPUT ;
    USE SIGNAL ;
    PORT
      LAYER M3 ;
        RECT  45.36 64.762 45.378 64.8 ;
    END
  END request[359]
  PIN request[35]
    DIRECTION INPUT ;
    USE SIGNAL ;
    PORT
      LAYER M3 ;
        RECT  4.572 64.762 4.59 64.8 ;
    END
  END request[35]
  PIN request[360]
    DIRECTION INPUT ;
    USE SIGNAL ;
    PORT
      LAYER M5 ;
        RECT  45.456 64.716 45.48 64.8 ;
    END
  END request[360]
  PIN request[361]
    DIRECTION INPUT ;
    USE SIGNAL ;
    PORT
      LAYER M3 ;
        RECT  45.612 64.762 45.63 64.8 ;
    END
  END request[361]
  PIN request[362]
    DIRECTION INPUT ;
    USE SIGNAL ;
    PORT
      LAYER M5 ;
        RECT  45.744 64.716 45.768 64.8 ;
    END
  END request[362]
  PIN request[363]
    DIRECTION INPUT ;
    USE SIGNAL ;
    PORT
      LAYER M3 ;
        RECT  45.864 64.762 45.882 64.8 ;
    END
  END request[363]
  PIN request[364]
    DIRECTION INPUT ;
    USE SIGNAL ;
    PORT
      LAYER M5 ;
        RECT  45.984 64.716 46.008 64.8 ;
    END
  END request[364]
  PIN request[365]
    DIRECTION INPUT ;
    USE SIGNAL ;
    PORT
      LAYER M3 ;
        RECT  46.116 64.762 46.134 64.8 ;
    END
  END request[365]
  PIN request[366]
    DIRECTION INPUT ;
    USE SIGNAL ;
    PORT
      LAYER M5 ;
        RECT  46.224 64.716 46.248 64.8 ;
    END
  END request[366]
  PIN request[367]
    DIRECTION INPUT ;
    USE SIGNAL ;
    PORT
      LAYER M3 ;
        RECT  46.368 64.762 46.386 64.8 ;
    END
  END request[367]
  PIN request[368]
    DIRECTION INPUT ;
    USE SIGNAL ;
    PORT
      LAYER M5 ;
        RECT  46.464 64.716 46.488 64.8 ;
    END
  END request[368]
  PIN request[369]
    DIRECTION INPUT ;
    USE SIGNAL ;
    PORT
      LAYER M3 ;
        RECT  46.62 64.762 46.638 64.8 ;
    END
  END request[369]
  PIN request[36]
    DIRECTION INPUT ;
    USE SIGNAL ;
    PORT
      LAYER M5 ;
        RECT  4.704 64.716 4.728 64.8 ;
    END
  END request[36]
  PIN request[370]
    DIRECTION INPUT ;
    USE SIGNAL ;
    PORT
      LAYER M5 ;
        RECT  46.752 64.716 46.776 64.8 ;
    END
  END request[370]
  PIN request[371]
    DIRECTION INPUT ;
    USE SIGNAL ;
    PORT
      LAYER M3 ;
        RECT  46.872 64.762 46.89 64.8 ;
    END
  END request[371]
  PIN request[372]
    DIRECTION INPUT ;
    USE SIGNAL ;
    PORT
      LAYER M5 ;
        RECT  46.992 64.716 47.016 64.8 ;
    END
  END request[372]
  PIN request[373]
    DIRECTION INPUT ;
    USE SIGNAL ;
    PORT
      LAYER M3 ;
        RECT  47.124 64.762 47.142 64.8 ;
    END
  END request[373]
  PIN request[374]
    DIRECTION INPUT ;
    USE SIGNAL ;
    PORT
      LAYER M5 ;
        RECT  47.232 64.716 47.256 64.8 ;
    END
  END request[374]
  PIN request[375]
    DIRECTION INPUT ;
    USE SIGNAL ;
    PORT
      LAYER M3 ;
        RECT  47.376 64.762 47.394 64.8 ;
    END
  END request[375]
  PIN request[376]
    DIRECTION INPUT ;
    USE SIGNAL ;
    PORT
      LAYER M5 ;
        RECT  47.472 64.716 47.496 64.8 ;
    END
  END request[376]
  PIN request[377]
    DIRECTION INPUT ;
    USE SIGNAL ;
    PORT
      LAYER M3 ;
        RECT  47.628 64.762 47.646 64.8 ;
    END
  END request[377]
  PIN request[378]
    DIRECTION INPUT ;
    USE SIGNAL ;
    PORT
      LAYER M5 ;
        RECT  47.76 64.716 47.784 64.8 ;
    END
  END request[378]
  PIN request[379]
    DIRECTION INPUT ;
    USE SIGNAL ;
    PORT
      LAYER M3 ;
        RECT  47.88 64.762 47.898 64.8 ;
    END
  END request[379]
  PIN request[37]
    DIRECTION INPUT ;
    USE SIGNAL ;
    PORT
      LAYER M3 ;
        RECT  4.824 64.762 4.842 64.8 ;
    END
  END request[37]
  PIN request[380]
    DIRECTION INPUT ;
    USE SIGNAL ;
    PORT
      LAYER M5 ;
        RECT  48 64.716 48.024 64.8 ;
    END
  END request[380]
  PIN request[381]
    DIRECTION INPUT ;
    USE SIGNAL ;
    PORT
      LAYER M3 ;
        RECT  48.132 64.762 48.15 64.8 ;
    END
  END request[381]
  PIN request[382]
    DIRECTION INPUT ;
    USE SIGNAL ;
    PORT
      LAYER M5 ;
        RECT  48.24 64.716 48.264 64.8 ;
    END
  END request[382]
  PIN request[383]
    DIRECTION INPUT ;
    USE SIGNAL ;
    PORT
      LAYER M3 ;
        RECT  48.384 64.762 48.402 64.8 ;
    END
  END request[383]
  PIN request[384]
    DIRECTION INPUT ;
    USE SIGNAL ;
    PORT
      LAYER M5 ;
        RECT  48.48 64.716 48.504 64.8 ;
    END
  END request[384]
  PIN request[385]
    DIRECTION INPUT ;
    USE SIGNAL ;
    PORT
      LAYER M3 ;
        RECT  48.636 64.762 48.654 64.8 ;
    END
  END request[385]
  PIN request[386]
    DIRECTION INPUT ;
    USE SIGNAL ;
    PORT
      LAYER M5 ;
        RECT  48.768 64.716 48.792 64.8 ;
    END
  END request[386]
  PIN request[387]
    DIRECTION INPUT ;
    USE SIGNAL ;
    PORT
      LAYER M3 ;
        RECT  48.888 64.762 48.906 64.8 ;
    END
  END request[387]
  PIN request[388]
    DIRECTION INPUT ;
    USE SIGNAL ;
    PORT
      LAYER M5 ;
        RECT  49.008 64.716 49.032 64.8 ;
    END
  END request[388]
  PIN request[389]
    DIRECTION INPUT ;
    USE SIGNAL ;
    PORT
      LAYER M3 ;
        RECT  49.14 64.762 49.158 64.8 ;
    END
  END request[389]
  PIN request[38]
    DIRECTION INPUT ;
    USE SIGNAL ;
    PORT
      LAYER M5 ;
        RECT  4.944 64.716 4.968 64.8 ;
    END
  END request[38]
  PIN request[390]
    DIRECTION INPUT ;
    USE SIGNAL ;
    PORT
      LAYER M5 ;
        RECT  49.248 64.716 49.272 64.8 ;
    END
  END request[390]
  PIN request[391]
    DIRECTION INPUT ;
    USE SIGNAL ;
    PORT
      LAYER M3 ;
        RECT  49.392 64.762 49.41 64.8 ;
    END
  END request[391]
  PIN request[392]
    DIRECTION INPUT ;
    USE SIGNAL ;
    PORT
      LAYER M5 ;
        RECT  49.488 64.716 49.512 64.8 ;
    END
  END request[392]
  PIN request[393]
    DIRECTION INPUT ;
    USE SIGNAL ;
    PORT
      LAYER M3 ;
        RECT  49.644 64.762 49.662 64.8 ;
    END
  END request[393]
  PIN request[394]
    DIRECTION INPUT ;
    USE SIGNAL ;
    PORT
      LAYER M5 ;
        RECT  49.776 64.716 49.8 64.8 ;
    END
  END request[394]
  PIN request[395]
    DIRECTION INPUT ;
    USE SIGNAL ;
    PORT
      LAYER M3 ;
        RECT  49.896 64.762 49.914 64.8 ;
    END
  END request[395]
  PIN request[396]
    DIRECTION INPUT ;
    USE SIGNAL ;
    PORT
      LAYER M5 ;
        RECT  50.016 64.716 50.04 64.8 ;
    END
  END request[396]
  PIN request[397]
    DIRECTION INPUT ;
    USE SIGNAL ;
    PORT
      LAYER M3 ;
        RECT  50.148 64.762 50.166 64.8 ;
    END
  END request[397]
  PIN request[398]
    DIRECTION INPUT ;
    USE SIGNAL ;
    PORT
      LAYER M5 ;
        RECT  50.256 64.716 50.28 64.8 ;
    END
  END request[398]
  PIN request[399]
    DIRECTION INPUT ;
    USE SIGNAL ;
    PORT
      LAYER M3 ;
        RECT  50.4 64.762 50.418 64.8 ;
    END
  END request[399]
  PIN request[39]
    DIRECTION INPUT ;
    USE SIGNAL ;
    PORT
      LAYER M3 ;
        RECT  5.076 64.762 5.094 64.8 ;
    END
  END request[39]
  PIN request[3]
    DIRECTION INPUT ;
    USE SIGNAL ;
    PORT
      LAYER M3 ;
        RECT  0.54 64.762 0.558 64.8 ;
    END
  END request[3]
  PIN request[400]
    DIRECTION INPUT ;
    USE SIGNAL ;
    PORT
      LAYER M5 ;
        RECT  50.496 64.716 50.52 64.8 ;
    END
  END request[400]
  PIN request[401]
    DIRECTION INPUT ;
    USE SIGNAL ;
    PORT
      LAYER M3 ;
        RECT  50.652 64.762 50.67 64.8 ;
    END
  END request[401]
  PIN request[402]
    DIRECTION INPUT ;
    USE SIGNAL ;
    PORT
      LAYER M5 ;
        RECT  50.736 64.716 50.76 64.8 ;
    END
  END request[402]
  PIN request[403]
    DIRECTION INPUT ;
    USE SIGNAL ;
    PORT
      LAYER M3 ;
        RECT  50.904 64.762 50.922 64.8 ;
    END
  END request[403]
  PIN request[404]
    DIRECTION INPUT ;
    USE SIGNAL ;
    PORT
      LAYER M5 ;
        RECT  51.024 64.716 51.048 64.8 ;
    END
  END request[404]
  PIN request[405]
    DIRECTION INPUT ;
    USE SIGNAL ;
    PORT
      LAYER M3 ;
        RECT  51.156 64.762 51.174 64.8 ;
    END
  END request[405]
  PIN request[406]
    DIRECTION INPUT ;
    USE SIGNAL ;
    PORT
      LAYER M5 ;
        RECT  51.264 64.716 51.288 64.8 ;
    END
  END request[406]
  PIN request[407]
    DIRECTION INPUT ;
    USE SIGNAL ;
    PORT
      LAYER M3 ;
        RECT  51.408 64.762 51.426 64.8 ;
    END
  END request[407]
  PIN request[408]
    DIRECTION INPUT ;
    USE SIGNAL ;
    PORT
      LAYER M5 ;
        RECT  51.504 64.716 51.528 64.8 ;
    END
  END request[408]
  PIN request[409]
    DIRECTION INPUT ;
    USE SIGNAL ;
    PORT
      LAYER M3 ;
        RECT  51.66 64.762 51.678 64.8 ;
    END
  END request[409]
  PIN request[40]
    DIRECTION INPUT ;
    USE SIGNAL ;
    PORT
      LAYER M5 ;
        RECT  5.232 64.716 5.256 64.8 ;
    END
  END request[40]
  PIN request[410]
    DIRECTION INPUT ;
    USE SIGNAL ;
    PORT
      LAYER M5 ;
        RECT  51.744 64.716 51.768 64.8 ;
    END
  END request[410]
  PIN request[411]
    DIRECTION INPUT ;
    USE SIGNAL ;
    PORT
      LAYER M3 ;
        RECT  51.912 64.762 51.93 64.8 ;
    END
  END request[411]
  PIN request[412]
    DIRECTION INPUT ;
    USE SIGNAL ;
    PORT
      LAYER M5 ;
        RECT  52.032 64.716 52.056 64.8 ;
    END
  END request[412]
  PIN request[413]
    DIRECTION INPUT ;
    USE SIGNAL ;
    PORT
      LAYER M3 ;
        RECT  52.164 64.762 52.182 64.8 ;
    END
  END request[413]
  PIN request[414]
    DIRECTION INPUT ;
    USE SIGNAL ;
    PORT
      LAYER M5 ;
        RECT  52.272 64.716 52.296 64.8 ;
    END
  END request[414]
  PIN request[415]
    DIRECTION INPUT ;
    USE SIGNAL ;
    PORT
      LAYER M3 ;
        RECT  52.38 64.762 52.398 64.8 ;
    END
  END request[415]
  PIN request[416]
    DIRECTION INPUT ;
    USE SIGNAL ;
    PORT
      LAYER M5 ;
        RECT  52.512 64.716 52.536 64.8 ;
    END
  END request[416]
  PIN request[417]
    DIRECTION INPUT ;
    USE SIGNAL ;
    PORT
      LAYER M3 ;
        RECT  52.632 64.762 52.65 64.8 ;
    END
  END request[417]
  PIN request[418]
    DIRECTION INPUT ;
    USE SIGNAL ;
    PORT
      LAYER M5 ;
        RECT  52.752 64.716 52.776 64.8 ;
    END
  END request[418]
  PIN request[419]
    DIRECTION INPUT ;
    USE SIGNAL ;
    PORT
      LAYER M3 ;
        RECT  52.884 64.762 52.902 64.8 ;
    END
  END request[419]
  PIN request[41]
    DIRECTION INPUT ;
    USE SIGNAL ;
    PORT
      LAYER M3 ;
        RECT  5.328 64.762 5.346 64.8 ;
    END
  END request[41]
  PIN request[420]
    DIRECTION INPUT ;
    USE SIGNAL ;
    PORT
      LAYER M5 ;
        RECT  53.04 64.716 53.064 64.8 ;
    END
  END request[420]
  PIN request[421]
    DIRECTION INPUT ;
    USE SIGNAL ;
    PORT
      LAYER M3 ;
        RECT  53.136 64.762 53.154 64.8 ;
    END
  END request[421]
  PIN request[422]
    DIRECTION INPUT ;
    USE SIGNAL ;
    PORT
      LAYER M5 ;
        RECT  53.28 64.716 53.304 64.8 ;
    END
  END request[422]
  PIN request[423]
    DIRECTION INPUT ;
    USE SIGNAL ;
    PORT
      LAYER M3 ;
        RECT  53.388 64.762 53.406 64.8 ;
    END
  END request[423]
  PIN request[424]
    DIRECTION INPUT ;
    USE SIGNAL ;
    PORT
      LAYER M5 ;
        RECT  53.52 64.716 53.544 64.8 ;
    END
  END request[424]
  PIN request[425]
    DIRECTION INPUT ;
    USE SIGNAL ;
    PORT
      LAYER M3 ;
        RECT  53.64 64.762 53.658 64.8 ;
    END
  END request[425]
  PIN request[426]
    DIRECTION INPUT ;
    USE SIGNAL ;
    PORT
      LAYER M5 ;
        RECT  53.76 64.716 53.784 64.8 ;
    END
  END request[426]
  PIN request[427]
    DIRECTION INPUT ;
    USE SIGNAL ;
    PORT
      LAYER M3 ;
        RECT  53.892 64.762 53.91 64.8 ;
    END
  END request[427]
  PIN request[428]
    DIRECTION INPUT ;
    USE SIGNAL ;
    PORT
      LAYER M5 ;
        RECT  54.048 64.716 54.072 64.8 ;
    END
  END request[428]
  PIN request[429]
    DIRECTION INPUT ;
    USE SIGNAL ;
    PORT
      LAYER M3 ;
        RECT  54.144 64.762 54.162 64.8 ;
    END
  END request[429]
  PIN request[42]
    DIRECTION INPUT ;
    USE SIGNAL ;
    PORT
      LAYER M5 ;
        RECT  5.472 64.716 5.496 64.8 ;
    END
  END request[42]
  PIN request[430]
    DIRECTION INPUT ;
    USE SIGNAL ;
    PORT
      LAYER M5 ;
        RECT  54.288 64.716 54.312 64.8 ;
    END
  END request[430]
  PIN request[431]
    DIRECTION INPUT ;
    USE SIGNAL ;
    PORT
      LAYER M3 ;
        RECT  54.396 64.762 54.414 64.8 ;
    END
  END request[431]
  PIN request[432]
    DIRECTION INPUT ;
    USE SIGNAL ;
    PORT
      LAYER M5 ;
        RECT  54.528 64.716 54.552 64.8 ;
    END
  END request[432]
  PIN request[433]
    DIRECTION INPUT ;
    USE SIGNAL ;
    PORT
      LAYER M3 ;
        RECT  54.648 64.762 54.666 64.8 ;
    END
  END request[433]
  PIN request[434]
    DIRECTION INPUT ;
    USE SIGNAL ;
    PORT
      LAYER M5 ;
        RECT  54.768 64.716 54.792 64.8 ;
    END
  END request[434]
  PIN request[435]
    DIRECTION INPUT ;
    USE SIGNAL ;
    PORT
      LAYER M3 ;
        RECT  54.9 64.762 54.918 64.8 ;
    END
  END request[435]
  PIN request[436]
    DIRECTION INPUT ;
    USE SIGNAL ;
    PORT
      LAYER M5 ;
        RECT  55.056 64.716 55.08 64.8 ;
    END
  END request[436]
  PIN request[437]
    DIRECTION INPUT ;
    USE SIGNAL ;
    PORT
      LAYER M3 ;
        RECT  55.152 64.762 55.17 64.8 ;
    END
  END request[437]
  PIN request[438]
    DIRECTION INPUT ;
    USE SIGNAL ;
    PORT
      LAYER M5 ;
        RECT  55.296 64.716 55.32 64.8 ;
    END
  END request[438]
  PIN request[439]
    DIRECTION INPUT ;
    USE SIGNAL ;
    PORT
      LAYER M3 ;
        RECT  55.404 64.762 55.422 64.8 ;
    END
  END request[439]
  PIN request[43]
    DIRECTION INPUT ;
    USE SIGNAL ;
    PORT
      LAYER M3 ;
        RECT  5.58 64.762 5.598 64.8 ;
    END
  END request[43]
  PIN request[440]
    DIRECTION INPUT ;
    USE SIGNAL ;
    PORT
      LAYER M5 ;
        RECT  55.536 64.716 55.56 64.8 ;
    END
  END request[440]
  PIN request[441]
    DIRECTION INPUT ;
    USE SIGNAL ;
    PORT
      LAYER M3 ;
        RECT  55.656 64.762 55.674 64.8 ;
    END
  END request[441]
  PIN request[442]
    DIRECTION INPUT ;
    USE SIGNAL ;
    PORT
      LAYER M5 ;
        RECT  55.776 64.716 55.8 64.8 ;
    END
  END request[442]
  PIN request[443]
    DIRECTION INPUT ;
    USE SIGNAL ;
    PORT
      LAYER M3 ;
        RECT  55.908 64.762 55.926 64.8 ;
    END
  END request[443]
  PIN request[444]
    DIRECTION INPUT ;
    USE SIGNAL ;
    PORT
      LAYER M5 ;
        RECT  56.064 64.716 56.088 64.8 ;
    END
  END request[444]
  PIN request[445]
    DIRECTION INPUT ;
    USE SIGNAL ;
    PORT
      LAYER M3 ;
        RECT  56.16 64.762 56.178 64.8 ;
    END
  END request[445]
  PIN request[446]
    DIRECTION INPUT ;
    USE SIGNAL ;
    PORT
      LAYER M5 ;
        RECT  56.304 64.716 56.328 64.8 ;
    END
  END request[446]
  PIN request[447]
    DIRECTION INPUT ;
    USE SIGNAL ;
    PORT
      LAYER M3 ;
        RECT  56.412 64.762 56.43 64.8 ;
    END
  END request[447]
  PIN request[448]
    DIRECTION INPUT ;
    USE SIGNAL ;
    PORT
      LAYER M5 ;
        RECT  56.544 64.716 56.568 64.8 ;
    END
  END request[448]
  PIN request[449]
    DIRECTION INPUT ;
    USE SIGNAL ;
    PORT
      LAYER M3 ;
        RECT  56.664 64.762 56.682 64.8 ;
    END
  END request[449]
  PIN request[44]
    DIRECTION INPUT ;
    USE SIGNAL ;
    PORT
      LAYER M5 ;
        RECT  5.712 64.716 5.736 64.8 ;
    END
  END request[44]
  PIN request[450]
    DIRECTION INPUT ;
    USE SIGNAL ;
    PORT
      LAYER M5 ;
        RECT  56.784 64.716 56.808 64.8 ;
    END
  END request[450]
  PIN request[451]
    DIRECTION INPUT ;
    USE SIGNAL ;
    PORT
      LAYER M3 ;
        RECT  56.916 64.762 56.934 64.8 ;
    END
  END request[451]
  PIN request[452]
    DIRECTION INPUT ;
    USE SIGNAL ;
    PORT
      LAYER M5 ;
        RECT  57.072 64.716 57.096 64.8 ;
    END
  END request[452]
  PIN request[453]
    DIRECTION INPUT ;
    USE SIGNAL ;
    PORT
      LAYER M3 ;
        RECT  57.168 64.762 57.186 64.8 ;
    END
  END request[453]
  PIN request[454]
    DIRECTION INPUT ;
    USE SIGNAL ;
    PORT
      LAYER M5 ;
        RECT  57.312 64.716 57.336 64.8 ;
    END
  END request[454]
  PIN request[455]
    DIRECTION INPUT ;
    USE SIGNAL ;
    PORT
      LAYER M3 ;
        RECT  57.42 64.762 57.438 64.8 ;
    END
  END request[455]
  PIN request[456]
    DIRECTION INPUT ;
    USE SIGNAL ;
    PORT
      LAYER M5 ;
        RECT  57.552 64.716 57.576 64.8 ;
    END
  END request[456]
  PIN request[457]
    DIRECTION INPUT ;
    USE SIGNAL ;
    PORT
      LAYER M3 ;
        RECT  57.672 64.762 57.69 64.8 ;
    END
  END request[457]
  PIN request[458]
    DIRECTION INPUT ;
    USE SIGNAL ;
    PORT
      LAYER M5 ;
        RECT  57.792 64.716 57.816 64.8 ;
    END
  END request[458]
  PIN request[459]
    DIRECTION INPUT ;
    USE SIGNAL ;
    PORT
      LAYER M3 ;
        RECT  57.924 64.762 57.942 64.8 ;
    END
  END request[459]
  PIN request[45]
    DIRECTION INPUT ;
    USE SIGNAL ;
    PORT
      LAYER M3 ;
        RECT  5.832 64.762 5.85 64.8 ;
    END
  END request[45]
  PIN request[460]
    DIRECTION INPUT ;
    USE SIGNAL ;
    PORT
      LAYER M5 ;
        RECT  58.08 64.716 58.104 64.8 ;
    END
  END request[460]
  PIN request[461]
    DIRECTION INPUT ;
    USE SIGNAL ;
    PORT
      LAYER M3 ;
        RECT  58.176 64.762 58.194 64.8 ;
    END
  END request[461]
  PIN request[462]
    DIRECTION INPUT ;
    USE SIGNAL ;
    PORT
      LAYER M5 ;
        RECT  58.32 64.716 58.344 64.8 ;
    END
  END request[462]
  PIN request[463]
    DIRECTION INPUT ;
    USE SIGNAL ;
    PORT
      LAYER M3 ;
        RECT  58.428 64.762 58.446 64.8 ;
    END
  END request[463]
  PIN request[464]
    DIRECTION INPUT ;
    USE SIGNAL ;
    PORT
      LAYER M5 ;
        RECT  58.56 64.716 58.584 64.8 ;
    END
  END request[464]
  PIN request[465]
    DIRECTION INPUT ;
    USE SIGNAL ;
    PORT
      LAYER M3 ;
        RECT  58.68 64.762 58.698 64.8 ;
    END
  END request[465]
  PIN request[466]
    DIRECTION INPUT ;
    USE SIGNAL ;
    PORT
      LAYER M5 ;
        RECT  58.8 64.716 58.824 64.8 ;
    END
  END request[466]
  PIN request[467]
    DIRECTION INPUT ;
    USE SIGNAL ;
    PORT
      LAYER M3 ;
        RECT  58.932 64.762 58.95 64.8 ;
    END
  END request[467]
  PIN request[468]
    DIRECTION INPUT ;
    USE SIGNAL ;
    PORT
      LAYER M5 ;
        RECT  59.04 64.716 59.064 64.8 ;
    END
  END request[468]
  PIN request[469]
    DIRECTION INPUT ;
    USE SIGNAL ;
    PORT
      LAYER M3 ;
        RECT  59.184 64.762 59.202 64.8 ;
    END
  END request[469]
  PIN request[46]
    DIRECTION INPUT ;
    USE SIGNAL ;
    PORT
      LAYER M5 ;
        RECT  5.952 64.716 5.976 64.8 ;
    END
  END request[46]
  PIN request[470]
    DIRECTION INPUT ;
    USE SIGNAL ;
    PORT
      LAYER M5 ;
        RECT  59.328 64.716 59.352 64.8 ;
    END
  END request[470]
  PIN request[471]
    DIRECTION INPUT ;
    USE SIGNAL ;
    PORT
      LAYER M3 ;
        RECT  59.436 64.762 59.454 64.8 ;
    END
  END request[471]
  PIN request[472]
    DIRECTION INPUT ;
    USE SIGNAL ;
    PORT
      LAYER M5 ;
        RECT  59.568 64.716 59.592 64.8 ;
    END
  END request[472]
  PIN request[473]
    DIRECTION INPUT ;
    USE SIGNAL ;
    PORT
      LAYER M3 ;
        RECT  59.688 64.762 59.706 64.8 ;
    END
  END request[473]
  PIN request[474]
    DIRECTION INPUT ;
    USE SIGNAL ;
    PORT
      LAYER M5 ;
        RECT  59.808 64.716 59.832 64.8 ;
    END
  END request[474]
  PIN request[475]
    DIRECTION INPUT ;
    USE SIGNAL ;
    PORT
      LAYER M3 ;
        RECT  59.94 64.762 59.958 64.8 ;
    END
  END request[475]
  PIN request[476]
    DIRECTION INPUT ;
    USE SIGNAL ;
    PORT
      LAYER M5 ;
        RECT  60.048 64.716 60.072 64.8 ;
    END
  END request[476]
  PIN request[477]
    DIRECTION INPUT ;
    USE SIGNAL ;
    PORT
      LAYER M3 ;
        RECT  60.192 64.762 60.21 64.8 ;
    END
  END request[477]
  PIN request[478]
    DIRECTION INPUT ;
    USE SIGNAL ;
    PORT
      LAYER M5 ;
        RECT  60.336 64.716 60.36 64.8 ;
    END
  END request[478]
  PIN request[479]
    DIRECTION INPUT ;
    USE SIGNAL ;
    PORT
      LAYER M3 ;
        RECT  60.444 64.762 60.462 64.8 ;
    END
  END request[479]
  PIN request[47]
    DIRECTION INPUT ;
    USE SIGNAL ;
    PORT
      LAYER M3 ;
        RECT  6.084 64.762 6.102 64.8 ;
    END
  END request[47]
  PIN request[480]
    DIRECTION INPUT ;
    USE SIGNAL ;
    PORT
      LAYER M5 ;
        RECT  60.576 64.716 60.6 64.8 ;
    END
  END request[480]
  PIN request[481]
    DIRECTION INPUT ;
    USE SIGNAL ;
    PORT
      LAYER M3 ;
        RECT  60.696 64.762 60.714 64.8 ;
    END
  END request[481]
  PIN request[482]
    DIRECTION INPUT ;
    USE SIGNAL ;
    PORT
      LAYER M5 ;
        RECT  60.816 64.716 60.84 64.8 ;
    END
  END request[482]
  PIN request[483]
    DIRECTION INPUT ;
    USE SIGNAL ;
    PORT
      LAYER M3 ;
        RECT  60.948 64.762 60.966 64.8 ;
    END
  END request[483]
  PIN request[484]
    DIRECTION INPUT ;
    USE SIGNAL ;
    PORT
      LAYER M5 ;
        RECT  61.056 64.716 61.08 64.8 ;
    END
  END request[484]
  PIN request[485]
    DIRECTION INPUT ;
    USE SIGNAL ;
    PORT
      LAYER M3 ;
        RECT  61.2 64.762 61.218 64.8 ;
    END
  END request[485]
  PIN request[486]
    DIRECTION INPUT ;
    USE SIGNAL ;
    PORT
      LAYER M5 ;
        RECT  61.344 64.716 61.368 64.8 ;
    END
  END request[486]
  PIN request[487]
    DIRECTION INPUT ;
    USE SIGNAL ;
    PORT
      LAYER M3 ;
        RECT  61.452 64.762 61.47 64.8 ;
    END
  END request[487]
  PIN request[488]
    DIRECTION INPUT ;
    USE SIGNAL ;
    PORT
      LAYER M5 ;
        RECT  61.584 64.716 61.608 64.8 ;
    END
  END request[488]
  PIN request[489]
    DIRECTION INPUT ;
    USE SIGNAL ;
    PORT
      LAYER M3 ;
        RECT  61.704 64.762 61.722 64.8 ;
    END
  END request[489]
  PIN request[48]
    DIRECTION INPUT ;
    USE SIGNAL ;
    PORT
      LAYER M5 ;
        RECT  6.24 64.716 6.264 64.8 ;
    END
  END request[48]
  PIN request[490]
    DIRECTION INPUT ;
    USE SIGNAL ;
    PORT
      LAYER M5 ;
        RECT  61.824 64.716 61.848 64.8 ;
    END
  END request[490]
  PIN request[491]
    DIRECTION INPUT ;
    USE SIGNAL ;
    PORT
      LAYER M3 ;
        RECT  61.956 64.762 61.974 64.8 ;
    END
  END request[491]
  PIN request[492]
    DIRECTION INPUT ;
    USE SIGNAL ;
    PORT
      LAYER M5 ;
        RECT  62.064 64.716 62.088 64.8 ;
    END
  END request[492]
  PIN request[493]
    DIRECTION INPUT ;
    USE SIGNAL ;
    PORT
      LAYER M3 ;
        RECT  62.208 64.762 62.226 64.8 ;
    END
  END request[493]
  PIN request[494]
    DIRECTION INPUT ;
    USE SIGNAL ;
    PORT
      LAYER M5 ;
        RECT  62.352 64.716 62.376 64.8 ;
    END
  END request[494]
  PIN request[495]
    DIRECTION INPUT ;
    USE SIGNAL ;
    PORT
      LAYER M3 ;
        RECT  62.46 64.762 62.478 64.8 ;
    END
  END request[495]
  PIN request[496]
    DIRECTION INPUT ;
    USE SIGNAL ;
    PORT
      LAYER M5 ;
        RECT  62.592 64.716 62.616 64.8 ;
    END
  END request[496]
  PIN request[497]
    DIRECTION INPUT ;
    USE SIGNAL ;
    PORT
      LAYER M3 ;
        RECT  62.712 64.762 62.73 64.8 ;
    END
  END request[497]
  PIN request[498]
    DIRECTION INPUT ;
    USE SIGNAL ;
    PORT
      LAYER M5 ;
        RECT  62.832 64.716 62.856 64.8 ;
    END
  END request[498]
  PIN request[499]
    DIRECTION INPUT ;
    USE SIGNAL ;
    PORT
      LAYER M3 ;
        RECT  62.964 64.762 62.982 64.8 ;
    END
  END request[499]
  PIN request[49]
    DIRECTION INPUT ;
    USE SIGNAL ;
    PORT
      LAYER M3 ;
        RECT  6.336 64.762 6.354 64.8 ;
    END
  END request[49]
  PIN request[4]
    DIRECTION INPUT ;
    USE SIGNAL ;
    PORT
      LAYER M5 ;
        RECT  0.672 64.716 0.696 64.8 ;
    END
  END request[4]
  PIN request[500]
    DIRECTION INPUT ;
    USE SIGNAL ;
    PORT
      LAYER M5 ;
        RECT  63.072 64.716 63.096 64.8 ;
    END
  END request[500]
  PIN request[501]
    DIRECTION INPUT ;
    USE SIGNAL ;
    PORT
      LAYER M3 ;
        RECT  63.216 64.762 63.234 64.8 ;
    END
  END request[501]
  PIN request[502]
    DIRECTION INPUT ;
    USE SIGNAL ;
    PORT
      LAYER M5 ;
        RECT  63.36 64.716 63.384 64.8 ;
    END
  END request[502]
  PIN request[503]
    DIRECTION INPUT ;
    USE SIGNAL ;
    PORT
      LAYER M3 ;
        RECT  63.468 64.762 63.486 64.8 ;
    END
  END request[503]
  PIN request[504]
    DIRECTION INPUT ;
    USE SIGNAL ;
    PORT
      LAYER M5 ;
        RECT  63.6 64.716 63.624 64.8 ;
    END
  END request[504]
  PIN request[505]
    DIRECTION INPUT ;
    USE SIGNAL ;
    PORT
      LAYER M3 ;
        RECT  63.72 64.762 63.738 64.8 ;
    END
  END request[505]
  PIN request[506]
    DIRECTION INPUT ;
    USE SIGNAL ;
    PORT
      LAYER M5 ;
        RECT  63.84 64.716 63.864 64.8 ;
    END
  END request[506]
  PIN request[507]
    DIRECTION INPUT ;
    USE SIGNAL ;
    PORT
      LAYER M3 ;
        RECT  63.972 64.762 63.99 64.8 ;
    END
  END request[507]
  PIN request[508]
    DIRECTION INPUT ;
    USE SIGNAL ;
    PORT
      LAYER M5 ;
        RECT  64.08 64.716 64.104 64.8 ;
    END
  END request[508]
  PIN request[509]
    DIRECTION INPUT ;
    USE SIGNAL ;
    PORT
      LAYER M3 ;
        RECT  64.224 64.762 64.242 64.8 ;
    END
  END request[509]
  PIN request[50]
    DIRECTION INPUT ;
    USE SIGNAL ;
    PORT
      LAYER M5 ;
        RECT  6.48 64.716 6.504 64.8 ;
    END
  END request[50]
  PIN request[510]
    DIRECTION INPUT ;
    USE SIGNAL ;
    PORT
      LAYER M5 ;
        RECT  64.368 64.716 64.392 64.8 ;
    END
  END request[510]
  PIN request[511]
    DIRECTION INPUT ;
    USE SIGNAL ;
    PORT
      LAYER M3 ;
        RECT  64.476 64.762 64.494 64.8 ;
    END
  END request[511]
  PIN request[512]
    DIRECTION INPUT ;
    USE SIGNAL ;
    PORT
      LAYER M5 ;
        RECT  64.608 64.716 64.632 64.8 ;
    END
  END request[512]
  PIN request[51]
    DIRECTION INPUT ;
    USE SIGNAL ;
    PORT
      LAYER M3 ;
        RECT  6.588 64.762 6.606 64.8 ;
    END
  END request[51]
  PIN request[52]
    DIRECTION INPUT ;
    USE SIGNAL ;
    PORT
      LAYER M5 ;
        RECT  6.72 64.716 6.744 64.8 ;
    END
  END request[52]
  PIN request[53]
    DIRECTION INPUT ;
    USE SIGNAL ;
    PORT
      LAYER M3 ;
        RECT  6.84 64.762 6.858 64.8 ;
    END
  END request[53]
  PIN request[54]
    DIRECTION INPUT ;
    USE SIGNAL ;
    PORT
      LAYER M5 ;
        RECT  6.96 64.716 6.984 64.8 ;
    END
  END request[54]
  PIN request[55]
    DIRECTION INPUT ;
    USE SIGNAL ;
    PORT
      LAYER M3 ;
        RECT  7.092 64.762 7.11 64.8 ;
    END
  END request[55]
  PIN request[56]
    DIRECTION INPUT ;
    USE SIGNAL ;
    PORT
      LAYER M5 ;
        RECT  7.2 64.716 7.224 64.8 ;
    END
  END request[56]
  PIN request[57]
    DIRECTION INPUT ;
    USE SIGNAL ;
    PORT
      LAYER M3 ;
        RECT  7.344 64.762 7.362 64.8 ;
    END
  END request[57]
  PIN request[58]
    DIRECTION INPUT ;
    USE SIGNAL ;
    PORT
      LAYER M5 ;
        RECT  7.488 64.716 7.512 64.8 ;
    END
  END request[58]
  PIN request[59]
    DIRECTION INPUT ;
    USE SIGNAL ;
    PORT
      LAYER M3 ;
        RECT  7.596 64.762 7.614 64.8 ;
    END
  END request[59]
  PIN request[5]
    DIRECTION INPUT ;
    USE SIGNAL ;
    PORT
      LAYER M3 ;
        RECT  0.792 64.762 0.81 64.8 ;
    END
  END request[5]
  PIN request[60]
    DIRECTION INPUT ;
    USE SIGNAL ;
    PORT
      LAYER M5 ;
        RECT  7.728 64.716 7.752 64.8 ;
    END
  END request[60]
  PIN request[61]
    DIRECTION INPUT ;
    USE SIGNAL ;
    PORT
      LAYER M3 ;
        RECT  7.848 64.762 7.866 64.8 ;
    END
  END request[61]
  PIN request[62]
    DIRECTION INPUT ;
    USE SIGNAL ;
    PORT
      LAYER M5 ;
        RECT  7.968 64.716 7.992 64.8 ;
    END
  END request[62]
  PIN request[63]
    DIRECTION INPUT ;
    USE SIGNAL ;
    PORT
      LAYER M3 ;
        RECT  8.1 64.762 8.118 64.8 ;
    END
  END request[63]
  PIN request[64]
    DIRECTION INPUT ;
    USE SIGNAL ;
    PORT
      LAYER M5 ;
        RECT  8.208 64.716 8.232 64.8 ;
    END
  END request[64]
  PIN request[65]
    DIRECTION INPUT ;
    USE SIGNAL ;
    PORT
      LAYER M3 ;
        RECT  8.352 64.762 8.37 64.8 ;
    END
  END request[65]
  PIN request[66]
    DIRECTION INPUT ;
    USE SIGNAL ;
    PORT
      LAYER M5 ;
        RECT  8.496 64.716 8.52 64.8 ;
    END
  END request[66]
  PIN request[67]
    DIRECTION INPUT ;
    USE SIGNAL ;
    PORT
      LAYER M3 ;
        RECT  8.604 64.762 8.622 64.8 ;
    END
  END request[67]
  PIN request[68]
    DIRECTION INPUT ;
    USE SIGNAL ;
    PORT
      LAYER M5 ;
        RECT  8.736 64.716 8.76 64.8 ;
    END
  END request[68]
  PIN request[69]
    DIRECTION INPUT ;
    USE SIGNAL ;
    PORT
      LAYER M3 ;
        RECT  8.856 64.762 8.874 64.8 ;
    END
  END request[69]
  PIN request[6]
    DIRECTION INPUT ;
    USE SIGNAL ;
    PORT
      LAYER M5 ;
        RECT  0.912 64.716 0.936 64.8 ;
    END
  END request[6]
  PIN request[70]
    DIRECTION INPUT ;
    USE SIGNAL ;
    PORT
      LAYER M5 ;
        RECT  8.976 64.716 9 64.8 ;
    END
  END request[70]
  PIN request[71]
    DIRECTION INPUT ;
    USE SIGNAL ;
    PORT
      LAYER M3 ;
        RECT  9.108 64.762 9.126 64.8 ;
    END
  END request[71]
  PIN request[72]
    DIRECTION INPUT ;
    USE SIGNAL ;
    PORT
      LAYER M5 ;
        RECT  9.216 64.716 9.24 64.8 ;
    END
  END request[72]
  PIN request[73]
    DIRECTION INPUT ;
    USE SIGNAL ;
    PORT
      LAYER M3 ;
        RECT  9.36 64.762 9.378 64.8 ;
    END
  END request[73]
  PIN request[74]
    DIRECTION INPUT ;
    USE SIGNAL ;
    PORT
      LAYER M5 ;
        RECT  9.504 64.716 9.528 64.8 ;
    END
  END request[74]
  PIN request[75]
    DIRECTION INPUT ;
    USE SIGNAL ;
    PORT
      LAYER M3 ;
        RECT  9.612 64.762 9.63 64.8 ;
    END
  END request[75]
  PIN request[76]
    DIRECTION INPUT ;
    USE SIGNAL ;
    PORT
      LAYER M5 ;
        RECT  9.744 64.716 9.768 64.8 ;
    END
  END request[76]
  PIN request[77]
    DIRECTION INPUT ;
    USE SIGNAL ;
    PORT
      LAYER M3 ;
        RECT  9.864 64.762 9.882 64.8 ;
    END
  END request[77]
  PIN request[78]
    DIRECTION INPUT ;
    USE SIGNAL ;
    PORT
      LAYER M5 ;
        RECT  9.984 64.716 10.008 64.8 ;
    END
  END request[78]
  PIN request[79]
    DIRECTION INPUT ;
    USE SIGNAL ;
    PORT
      LAYER M3 ;
        RECT  10.116 64.762 10.134 64.8 ;
    END
  END request[79]
  PIN request[7]
    DIRECTION INPUT ;
    USE SIGNAL ;
    PORT
      LAYER M3 ;
        RECT  1.044 64.762 1.062 64.8 ;
    END
  END request[7]
  PIN request[80]
    DIRECTION INPUT ;
    USE SIGNAL ;
    PORT
      LAYER M5 ;
        RECT  10.224 64.716 10.248 64.8 ;
    END
  END request[80]
  PIN request[81]
    DIRECTION INPUT ;
    USE SIGNAL ;
    PORT
      LAYER M3 ;
        RECT  10.368 64.762 10.386 64.8 ;
    END
  END request[81]
  PIN request[82]
    DIRECTION INPUT ;
    USE SIGNAL ;
    PORT
      LAYER M5 ;
        RECT  10.512 64.716 10.536 64.8 ;
    END
  END request[82]
  PIN request[83]
    DIRECTION INPUT ;
    USE SIGNAL ;
    PORT
      LAYER M3 ;
        RECT  10.62 64.762 10.638 64.8 ;
    END
  END request[83]
  PIN request[84]
    DIRECTION INPUT ;
    USE SIGNAL ;
    PORT
      LAYER M5 ;
        RECT  10.752 64.716 10.776 64.8 ;
    END
  END request[84]
  PIN request[85]
    DIRECTION INPUT ;
    USE SIGNAL ;
    PORT
      LAYER M3 ;
        RECT  10.872 64.762 10.89 64.8 ;
    END
  END request[85]
  PIN request[86]
    DIRECTION INPUT ;
    USE SIGNAL ;
    PORT
      LAYER M5 ;
        RECT  10.992 64.716 11.016 64.8 ;
    END
  END request[86]
  PIN request[87]
    DIRECTION INPUT ;
    USE SIGNAL ;
    PORT
      LAYER M3 ;
        RECT  11.124 64.762 11.142 64.8 ;
    END
  END request[87]
  PIN request[88]
    DIRECTION INPUT ;
    USE SIGNAL ;
    PORT
      LAYER M5 ;
        RECT  11.232 64.716 11.256 64.8 ;
    END
  END request[88]
  PIN request[89]
    DIRECTION INPUT ;
    USE SIGNAL ;
    PORT
      LAYER M3 ;
        RECT  11.376 64.762 11.394 64.8 ;
    END
  END request[89]
  PIN request[8]
    DIRECTION INPUT ;
    USE SIGNAL ;
    PORT
      LAYER M5 ;
        RECT  1.2 64.716 1.224 64.8 ;
    END
  END request[8]
  PIN request[90]
    DIRECTION INPUT ;
    USE SIGNAL ;
    PORT
      LAYER M5 ;
        RECT  11.52 64.716 11.544 64.8 ;
    END
  END request[90]
  PIN request[91]
    DIRECTION INPUT ;
    USE SIGNAL ;
    PORT
      LAYER M3 ;
        RECT  11.628 64.762 11.646 64.8 ;
    END
  END request[91]
  PIN request[92]
    DIRECTION INPUT ;
    USE SIGNAL ;
    PORT
      LAYER M5 ;
        RECT  11.76 64.716 11.784 64.8 ;
    END
  END request[92]
  PIN request[93]
    DIRECTION INPUT ;
    USE SIGNAL ;
    PORT
      LAYER M3 ;
        RECT  11.88 64.762 11.898 64.8 ;
    END
  END request[93]
  PIN request[94]
    DIRECTION INPUT ;
    USE SIGNAL ;
    PORT
      LAYER M5 ;
        RECT  12 64.716 12.024 64.8 ;
    END
  END request[94]
  PIN request[95]
    DIRECTION INPUT ;
    USE SIGNAL ;
    PORT
      LAYER M3 ;
        RECT  12.132 64.762 12.15 64.8 ;
    END
  END request[95]
  PIN request[96]
    DIRECTION INPUT ;
    USE SIGNAL ;
    PORT
      LAYER M5 ;
        RECT  12.24 64.716 12.264 64.8 ;
    END
  END request[96]
  PIN request[97]
    DIRECTION INPUT ;
    USE SIGNAL ;
    PORT
      LAYER M3 ;
        RECT  12.384 64.762 12.402 64.8 ;
    END
  END request[97]
  PIN request[98]
    DIRECTION INPUT ;
    USE SIGNAL ;
    PORT
      LAYER M5 ;
        RECT  12.528 64.716 12.552 64.8 ;
    END
  END request[98]
  PIN request[99]
    DIRECTION INPUT ;
    USE SIGNAL ;
    PORT
      LAYER M3 ;
        RECT  12.636 64.762 12.654 64.8 ;
    END
  END request[99]
  PIN request[9]
    DIRECTION INPUT ;
    USE SIGNAL ;
    PORT
      LAYER M3 ;
        RECT  1.296 64.762 1.314 64.8 ;
    END
  END request[9]
  PIN rst_n
    DIRECTION INPUT ;
    USE SIGNAL ;
    PORT
      LAYER M3 ;
        RECT  64.728 64.762 64.746 64.8 ;
    END
  END rst_n
  PIN vr2q[0]
    DIRECTION OUTPUT ;
    USE SIGNAL ;
    PORT
      LAYER M3 ;
        RECT  0.072 0 0.09 0.038 ;
    END
  END vr2q[0]
  PIN vr2q[100]
    DIRECTION OUTPUT ;
    USE SIGNAL ;
    PORT
      LAYER M3 ;
        RECT  12.672 0 12.69 0.038 ;
    END
  END vr2q[100]
  PIN vr2q[101]
    DIRECTION OUTPUT ;
    USE SIGNAL ;
    PORT
      LAYER M5 ;
        RECT  12.816 0 12.84 0.084 ;
    END
  END vr2q[101]
  PIN vr2q[102]
    DIRECTION OUTPUT ;
    USE SIGNAL ;
    PORT
      LAYER M3 ;
        RECT  12.924 0 12.942 0.038 ;
    END
  END vr2q[102]
  PIN vr2q[103]
    DIRECTION OUTPUT ;
    USE SIGNAL ;
    PORT
      LAYER M5 ;
        RECT  13.056 0 13.08 0.084 ;
    END
  END vr2q[103]
  PIN vr2q[104]
    DIRECTION OUTPUT ;
    USE SIGNAL ;
    PORT
      LAYER M3 ;
        RECT  13.176 0 13.194 0.038 ;
    END
  END vr2q[104]
  PIN vr2q[105]
    DIRECTION OUTPUT ;
    USE SIGNAL ;
    PORT
      LAYER M5 ;
        RECT  13.296 0 13.32 0.084 ;
    END
  END vr2q[105]
  PIN vr2q[106]
    DIRECTION OUTPUT ;
    USE SIGNAL ;
    PORT
      LAYER M3 ;
        RECT  13.428 0 13.446 0.038 ;
    END
  END vr2q[106]
  PIN vr2q[107]
    DIRECTION OUTPUT ;
    USE SIGNAL ;
    PORT
      LAYER M5 ;
        RECT  13.584 0 13.608 0.084 ;
    END
  END vr2q[107]
  PIN vr2q[108]
    DIRECTION OUTPUT ;
    USE SIGNAL ;
    PORT
      LAYER M3 ;
        RECT  13.68 0 13.698 0.038 ;
    END
  END vr2q[108]
  PIN vr2q[109]
    DIRECTION OUTPUT ;
    USE SIGNAL ;
    PORT
      LAYER M5 ;
        RECT  13.824 0 13.848 0.084 ;
    END
  END vr2q[109]
  PIN vr2q[10]
    DIRECTION OUTPUT ;
    USE SIGNAL ;
    PORT
      LAYER M3 ;
        RECT  1.332 0 1.35 0.038 ;
    END
  END vr2q[10]
  PIN vr2q[110]
    DIRECTION OUTPUT ;
    USE SIGNAL ;
    PORT
      LAYER M3 ;
        RECT  13.932 0 13.95 0.038 ;
    END
  END vr2q[110]
  PIN vr2q[111]
    DIRECTION OUTPUT ;
    USE SIGNAL ;
    PORT
      LAYER M5 ;
        RECT  14.064 0 14.088 0.084 ;
    END
  END vr2q[111]
  PIN vr2q[112]
    DIRECTION OUTPUT ;
    USE SIGNAL ;
    PORT
      LAYER M3 ;
        RECT  14.22 0 14.238 0.038 ;
    END
  END vr2q[112]
  PIN vr2q[113]
    DIRECTION OUTPUT ;
    USE SIGNAL ;
    PORT
      LAYER M5 ;
        RECT  14.304 0 14.328 0.084 ;
    END
  END vr2q[113]
  PIN vr2q[114]
    DIRECTION OUTPUT ;
    USE SIGNAL ;
    PORT
      LAYER M3 ;
        RECT  14.472 0 14.49 0.038 ;
    END
  END vr2q[114]
  PIN vr2q[115]
    DIRECTION OUTPUT ;
    USE SIGNAL ;
    PORT
      LAYER M5 ;
        RECT  14.592 0 14.616 0.084 ;
    END
  END vr2q[115]
  PIN vr2q[116]
    DIRECTION OUTPUT ;
    USE SIGNAL ;
    PORT
      LAYER M3 ;
        RECT  14.724 0 14.742 0.038 ;
    END
  END vr2q[116]
  PIN vr2q[117]
    DIRECTION OUTPUT ;
    USE SIGNAL ;
    PORT
      LAYER M5 ;
        RECT  14.832 0 14.856 0.084 ;
    END
  END vr2q[117]
  PIN vr2q[118]
    DIRECTION OUTPUT ;
    USE SIGNAL ;
    PORT
      LAYER M3 ;
        RECT  14.976 0 14.994 0.038 ;
    END
  END vr2q[118]
  PIN vr2q[119]
    DIRECTION OUTPUT ;
    USE SIGNAL ;
    PORT
      LAYER M5 ;
        RECT  15.072 0 15.096 0.084 ;
    END
  END vr2q[119]
  PIN vr2q[11]
    DIRECTION OUTPUT ;
    USE SIGNAL ;
    PORT
      LAYER M5 ;
        RECT  1.44 0 1.464 0.084 ;
    END
  END vr2q[11]
  PIN vr2q[120]
    DIRECTION OUTPUT ;
    USE SIGNAL ;
    PORT
      LAYER M3 ;
        RECT  15.228 0 15.246 0.038 ;
    END
  END vr2q[120]
  PIN vr2q[121]
    DIRECTION OUTPUT ;
    USE SIGNAL ;
    PORT
      LAYER M5 ;
        RECT  15.312 0 15.336 0.084 ;
    END
  END vr2q[121]
  PIN vr2q[122]
    DIRECTION OUTPUT ;
    USE SIGNAL ;
    PORT
      LAYER M3 ;
        RECT  15.48 0 15.498 0.038 ;
    END
  END vr2q[122]
  PIN vr2q[123]
    DIRECTION OUTPUT ;
    USE SIGNAL ;
    PORT
      LAYER M5 ;
        RECT  15.6 0 15.624 0.084 ;
    END
  END vr2q[123]
  PIN vr2q[124]
    DIRECTION OUTPUT ;
    USE SIGNAL ;
    PORT
      LAYER M3 ;
        RECT  15.732 0 15.75 0.038 ;
    END
  END vr2q[124]
  PIN vr2q[125]
    DIRECTION OUTPUT ;
    USE SIGNAL ;
    PORT
      LAYER M5 ;
        RECT  15.84 0 15.864 0.084 ;
    END
  END vr2q[125]
  PIN vr2q[126]
    DIRECTION OUTPUT ;
    USE SIGNAL ;
    PORT
      LAYER M3 ;
        RECT  15.984 0 16.002 0.038 ;
    END
  END vr2q[126]
  PIN vr2q[127]
    DIRECTION OUTPUT ;
    USE SIGNAL ;
    PORT
      LAYER M5 ;
        RECT  16.08 0 16.104 0.084 ;
    END
  END vr2q[127]
  PIN vr2q[128]
    DIRECTION OUTPUT ;
    USE SIGNAL ;
    PORT
      LAYER M3 ;
        RECT  16.236 0 16.254 0.038 ;
    END
  END vr2q[128]
  PIN vr2q[129]
    DIRECTION OUTPUT ;
    USE SIGNAL ;
    PORT
      LAYER M5 ;
        RECT  16.368 0 16.392 0.084 ;
    END
  END vr2q[129]
  PIN vr2q[12]
    DIRECTION OUTPUT ;
    USE SIGNAL ;
    PORT
      LAYER M3 ;
        RECT  1.584 0 1.602 0.038 ;
    END
  END vr2q[12]
  PIN vr2q[130]
    DIRECTION OUTPUT ;
    USE SIGNAL ;
    PORT
      LAYER M3 ;
        RECT  16.488 0 16.506 0.038 ;
    END
  END vr2q[130]
  PIN vr2q[131]
    DIRECTION OUTPUT ;
    USE SIGNAL ;
    PORT
      LAYER M5 ;
        RECT  16.608 0 16.632 0.084 ;
    END
  END vr2q[131]
  PIN vr2q[132]
    DIRECTION OUTPUT ;
    USE SIGNAL ;
    PORT
      LAYER M3 ;
        RECT  16.74 0 16.758 0.038 ;
    END
  END vr2q[132]
  PIN vr2q[133]
    DIRECTION OUTPUT ;
    USE SIGNAL ;
    PORT
      LAYER M5 ;
        RECT  16.848 0 16.872 0.084 ;
    END
  END vr2q[133]
  PIN vr2q[134]
    DIRECTION OUTPUT ;
    USE SIGNAL ;
    PORT
      LAYER M3 ;
        RECT  16.992 0 17.01 0.038 ;
    END
  END vr2q[134]
  PIN vr2q[135]
    DIRECTION OUTPUT ;
    USE SIGNAL ;
    PORT
      LAYER M5 ;
        RECT  17.088 0 17.112 0.084 ;
    END
  END vr2q[135]
  PIN vr2q[136]
    DIRECTION OUTPUT ;
    USE SIGNAL ;
    PORT
      LAYER M3 ;
        RECT  17.244 0 17.262 0.038 ;
    END
  END vr2q[136]
  PIN vr2q[137]
    DIRECTION OUTPUT ;
    USE SIGNAL ;
    PORT
      LAYER M5 ;
        RECT  17.376 0 17.4 0.084 ;
    END
  END vr2q[137]
  PIN vr2q[138]
    DIRECTION OUTPUT ;
    USE SIGNAL ;
    PORT
      LAYER M3 ;
        RECT  17.496 0 17.514 0.038 ;
    END
  END vr2q[138]
  PIN vr2q[139]
    DIRECTION OUTPUT ;
    USE SIGNAL ;
    PORT
      LAYER M5 ;
        RECT  17.616 0 17.64 0.084 ;
    END
  END vr2q[139]
  PIN vr2q[13]
    DIRECTION OUTPUT ;
    USE SIGNAL ;
    PORT
      LAYER M5 ;
        RECT  1.68 0 1.704 0.084 ;
    END
  END vr2q[13]
  PIN vr2q[140]
    DIRECTION OUTPUT ;
    USE SIGNAL ;
    PORT
      LAYER M3 ;
        RECT  17.748 0 17.766 0.038 ;
    END
  END vr2q[140]
  PIN vr2q[141]
    DIRECTION OUTPUT ;
    USE SIGNAL ;
    PORT
      LAYER M5 ;
        RECT  17.856 0 17.88 0.084 ;
    END
  END vr2q[141]
  PIN vr2q[142]
    DIRECTION OUTPUT ;
    USE SIGNAL ;
    PORT
      LAYER M3 ;
        RECT  18 0 18.018 0.038 ;
    END
  END vr2q[142]
  PIN vr2q[143]
    DIRECTION OUTPUT ;
    USE SIGNAL ;
    PORT
      LAYER M5 ;
        RECT  18.096 0 18.12 0.084 ;
    END
  END vr2q[143]
  PIN vr2q[144]
    DIRECTION OUTPUT ;
    USE SIGNAL ;
    PORT
      LAYER M3 ;
        RECT  18.252 0 18.27 0.038 ;
    END
  END vr2q[144]
  PIN vr2q[145]
    DIRECTION OUTPUT ;
    USE SIGNAL ;
    PORT
      LAYER M5 ;
        RECT  18.384 0 18.408 0.084 ;
    END
  END vr2q[145]
  PIN vr2q[146]
    DIRECTION OUTPUT ;
    USE SIGNAL ;
    PORT
      LAYER M3 ;
        RECT  18.504 0 18.522 0.038 ;
    END
  END vr2q[146]
  PIN vr2q[147]
    DIRECTION OUTPUT ;
    USE SIGNAL ;
    PORT
      LAYER M5 ;
        RECT  18.624 0 18.648 0.084 ;
    END
  END vr2q[147]
  PIN vr2q[148]
    DIRECTION OUTPUT ;
    USE SIGNAL ;
    PORT
      LAYER M3 ;
        RECT  18.756 0 18.774 0.038 ;
    END
  END vr2q[148]
  PIN vr2q[149]
    DIRECTION OUTPUT ;
    USE SIGNAL ;
    PORT
      LAYER M5 ;
        RECT  18.864 0 18.888 0.084 ;
    END
  END vr2q[149]
  PIN vr2q[14]
    DIRECTION OUTPUT ;
    USE SIGNAL ;
    PORT
      LAYER M3 ;
        RECT  1.836 0 1.854 0.038 ;
    END
  END vr2q[14]
  PIN vr2q[150]
    DIRECTION OUTPUT ;
    USE SIGNAL ;
    PORT
      LAYER M3 ;
        RECT  19.008 0 19.026 0.038 ;
    END
  END vr2q[150]
  PIN vr2q[151]
    DIRECTION OUTPUT ;
    USE SIGNAL ;
    PORT
      LAYER M5 ;
        RECT  19.104 0 19.128 0.084 ;
    END
  END vr2q[151]
  PIN vr2q[152]
    DIRECTION OUTPUT ;
    USE SIGNAL ;
    PORT
      LAYER M3 ;
        RECT  19.26 0 19.278 0.038 ;
    END
  END vr2q[152]
  PIN vr2q[153]
    DIRECTION OUTPUT ;
    USE SIGNAL ;
    PORT
      LAYER M5 ;
        RECT  19.392 0 19.416 0.084 ;
    END
  END vr2q[153]
  PIN vr2q[154]
    DIRECTION OUTPUT ;
    USE SIGNAL ;
    PORT
      LAYER M3 ;
        RECT  19.512 0 19.53 0.038 ;
    END
  END vr2q[154]
  PIN vr2q[155]
    DIRECTION OUTPUT ;
    USE SIGNAL ;
    PORT
      LAYER M5 ;
        RECT  19.632 0 19.656 0.084 ;
    END
  END vr2q[155]
  PIN vr2q[156]
    DIRECTION OUTPUT ;
    USE SIGNAL ;
    PORT
      LAYER M3 ;
        RECT  19.764 0 19.782 0.038 ;
    END
  END vr2q[156]
  PIN vr2q[157]
    DIRECTION OUTPUT ;
    USE SIGNAL ;
    PORT
      LAYER M5 ;
        RECT  19.872 0 19.896 0.084 ;
    END
  END vr2q[157]
  PIN vr2q[158]
    DIRECTION OUTPUT ;
    USE SIGNAL ;
    PORT
      LAYER M3 ;
        RECT  20.016 0 20.034 0.038 ;
    END
  END vr2q[158]
  PIN vr2q[159]
    DIRECTION OUTPUT ;
    USE SIGNAL ;
    PORT
      LAYER M5 ;
        RECT  20.112 0 20.136 0.084 ;
    END
  END vr2q[159]
  PIN vr2q[15]
    DIRECTION OUTPUT ;
    USE SIGNAL ;
    PORT
      LAYER M5 ;
        RECT  1.968 0 1.992 0.084 ;
    END
  END vr2q[15]
  PIN vr2q[160]
    DIRECTION OUTPUT ;
    USE SIGNAL ;
    PORT
      LAYER M3 ;
        RECT  20.268 0 20.286 0.038 ;
    END
  END vr2q[160]
  PIN vr2q[161]
    DIRECTION OUTPUT ;
    USE SIGNAL ;
    PORT
      LAYER M5 ;
        RECT  20.4 0 20.424 0.084 ;
    END
  END vr2q[161]
  PIN vr2q[162]
    DIRECTION OUTPUT ;
    USE SIGNAL ;
    PORT
      LAYER M3 ;
        RECT  20.52 0 20.538 0.038 ;
    END
  END vr2q[162]
  PIN vr2q[163]
    DIRECTION OUTPUT ;
    USE SIGNAL ;
    PORT
      LAYER M5 ;
        RECT  20.64 0 20.664 0.084 ;
    END
  END vr2q[163]
  PIN vr2q[164]
    DIRECTION OUTPUT ;
    USE SIGNAL ;
    PORT
      LAYER M3 ;
        RECT  20.772 0 20.79 0.038 ;
    END
  END vr2q[164]
  PIN vr2q[165]
    DIRECTION OUTPUT ;
    USE SIGNAL ;
    PORT
      LAYER M5 ;
        RECT  20.88 0 20.904 0.084 ;
    END
  END vr2q[165]
  PIN vr2q[166]
    DIRECTION OUTPUT ;
    USE SIGNAL ;
    PORT
      LAYER M3 ;
        RECT  21.024 0 21.042 0.038 ;
    END
  END vr2q[166]
  PIN vr2q[167]
    DIRECTION OUTPUT ;
    USE SIGNAL ;
    PORT
      LAYER M5 ;
        RECT  21.168 0 21.192 0.084 ;
    END
  END vr2q[167]
  PIN vr2q[168]
    DIRECTION OUTPUT ;
    USE SIGNAL ;
    PORT
      LAYER M3 ;
        RECT  21.276 0 21.294 0.038 ;
    END
  END vr2q[168]
  PIN vr2q[169]
    DIRECTION OUTPUT ;
    USE SIGNAL ;
    PORT
      LAYER M5 ;
        RECT  21.408 0 21.432 0.084 ;
    END
  END vr2q[169]
  PIN vr2q[16]
    DIRECTION OUTPUT ;
    USE SIGNAL ;
    PORT
      LAYER M3 ;
        RECT  2.088 0 2.106 0.038 ;
    END
  END vr2q[16]
  PIN vr2q[170]
    DIRECTION OUTPUT ;
    USE SIGNAL ;
    PORT
      LAYER M3 ;
        RECT  21.528 0 21.546 0.038 ;
    END
  END vr2q[170]
  PIN vr2q[171]
    DIRECTION OUTPUT ;
    USE SIGNAL ;
    PORT
      LAYER M5 ;
        RECT  21.648 0 21.672 0.084 ;
    END
  END vr2q[171]
  PIN vr2q[172]
    DIRECTION OUTPUT ;
    USE SIGNAL ;
    PORT
      LAYER M3 ;
        RECT  21.78 0 21.798 0.038 ;
    END
  END vr2q[172]
  PIN vr2q[173]
    DIRECTION OUTPUT ;
    USE SIGNAL ;
    PORT
      LAYER M5 ;
        RECT  21.888 0 21.912 0.084 ;
    END
  END vr2q[173]
  PIN vr2q[174]
    DIRECTION OUTPUT ;
    USE SIGNAL ;
    PORT
      LAYER M3 ;
        RECT  22.032 0 22.05 0.038 ;
    END
  END vr2q[174]
  PIN vr2q[175]
    DIRECTION OUTPUT ;
    USE SIGNAL ;
    PORT
      LAYER M5 ;
        RECT  22.176 0 22.2 0.084 ;
    END
  END vr2q[175]
  PIN vr2q[176]
    DIRECTION OUTPUT ;
    USE SIGNAL ;
    PORT
      LAYER M3 ;
        RECT  22.284 0 22.302 0.038 ;
    END
  END vr2q[176]
  PIN vr2q[177]
    DIRECTION OUTPUT ;
    USE SIGNAL ;
    PORT
      LAYER M5 ;
        RECT  22.416 0 22.44 0.084 ;
    END
  END vr2q[177]
  PIN vr2q[178]
    DIRECTION OUTPUT ;
    USE SIGNAL ;
    PORT
      LAYER M3 ;
        RECT  22.536 0 22.554 0.038 ;
    END
  END vr2q[178]
  PIN vr2q[179]
    DIRECTION OUTPUT ;
    USE SIGNAL ;
    PORT
      LAYER M5 ;
        RECT  22.656 0 22.68 0.084 ;
    END
  END vr2q[179]
  PIN vr2q[17]
    DIRECTION OUTPUT ;
    USE SIGNAL ;
    PORT
      LAYER M5 ;
        RECT  2.208 0 2.232 0.084 ;
    END
  END vr2q[17]
  PIN vr2q[180]
    DIRECTION OUTPUT ;
    USE SIGNAL ;
    PORT
      LAYER M3 ;
        RECT  22.788 0 22.806 0.038 ;
    END
  END vr2q[180]
  PIN vr2q[181]
    DIRECTION OUTPUT ;
    USE SIGNAL ;
    PORT
      LAYER M5 ;
        RECT  22.896 0 22.92 0.084 ;
    END
  END vr2q[181]
  PIN vr2q[182]
    DIRECTION OUTPUT ;
    USE SIGNAL ;
    PORT
      LAYER M3 ;
        RECT  23.04 0 23.058 0.038 ;
    END
  END vr2q[182]
  PIN vr2q[183]
    DIRECTION OUTPUT ;
    USE SIGNAL ;
    PORT
      LAYER M5 ;
        RECT  23.184 0 23.208 0.084 ;
    END
  END vr2q[183]
  PIN vr2q[184]
    DIRECTION OUTPUT ;
    USE SIGNAL ;
    PORT
      LAYER M3 ;
        RECT  23.292 0 23.31 0.038 ;
    END
  END vr2q[184]
  PIN vr2q[185]
    DIRECTION OUTPUT ;
    USE SIGNAL ;
    PORT
      LAYER M5 ;
        RECT  23.424 0 23.448 0.084 ;
    END
  END vr2q[185]
  PIN vr2q[186]
    DIRECTION OUTPUT ;
    USE SIGNAL ;
    PORT
      LAYER M3 ;
        RECT  23.544 0 23.562 0.038 ;
    END
  END vr2q[186]
  PIN vr2q[187]
    DIRECTION OUTPUT ;
    USE SIGNAL ;
    PORT
      LAYER M5 ;
        RECT  23.664 0 23.688 0.084 ;
    END
  END vr2q[187]
  PIN vr2q[188]
    DIRECTION OUTPUT ;
    USE SIGNAL ;
    PORT
      LAYER M3 ;
        RECT  23.796 0 23.814 0.038 ;
    END
  END vr2q[188]
  PIN vr2q[189]
    DIRECTION OUTPUT ;
    USE SIGNAL ;
    PORT
      LAYER M5 ;
        RECT  23.904 0 23.928 0.084 ;
    END
  END vr2q[189]
  PIN vr2q[18]
    DIRECTION OUTPUT ;
    USE SIGNAL ;
    PORT
      LAYER M3 ;
        RECT  2.34 0 2.358 0.038 ;
    END
  END vr2q[18]
  PIN vr2q[190]
    DIRECTION OUTPUT ;
    USE SIGNAL ;
    PORT
      LAYER M3 ;
        RECT  24.048 0 24.066 0.038 ;
    END
  END vr2q[190]
  PIN vr2q[191]
    DIRECTION OUTPUT ;
    USE SIGNAL ;
    PORT
      LAYER M5 ;
        RECT  24.192 0 24.216 0.084 ;
    END
  END vr2q[191]
  PIN vr2q[192]
    DIRECTION OUTPUT ;
    USE SIGNAL ;
    PORT
      LAYER M3 ;
        RECT  24.3 0 24.318 0.038 ;
    END
  END vr2q[192]
  PIN vr2q[193]
    DIRECTION OUTPUT ;
    USE SIGNAL ;
    PORT
      LAYER M5 ;
        RECT  24.432 0 24.456 0.084 ;
    END
  END vr2q[193]
  PIN vr2q[194]
    DIRECTION OUTPUT ;
    USE SIGNAL ;
    PORT
      LAYER M3 ;
        RECT  24.552 0 24.57 0.038 ;
    END
  END vr2q[194]
  PIN vr2q[195]
    DIRECTION OUTPUT ;
    USE SIGNAL ;
    PORT
      LAYER M5 ;
        RECT  24.672 0 24.696 0.084 ;
    END
  END vr2q[195]
  PIN vr2q[196]
    DIRECTION OUTPUT ;
    USE SIGNAL ;
    PORT
      LAYER M3 ;
        RECT  24.804 0 24.822 0.038 ;
    END
  END vr2q[196]
  PIN vr2q[197]
    DIRECTION OUTPUT ;
    USE SIGNAL ;
    PORT
      LAYER M5 ;
        RECT  24.912 0 24.936 0.084 ;
    END
  END vr2q[197]
  PIN vr2q[198]
    DIRECTION OUTPUT ;
    USE SIGNAL ;
    PORT
      LAYER M3 ;
        RECT  25.056 0 25.074 0.038 ;
    END
  END vr2q[198]
  PIN vr2q[199]
    DIRECTION OUTPUT ;
    USE SIGNAL ;
    PORT
      LAYER M5 ;
        RECT  25.2 0 25.224 0.084 ;
    END
  END vr2q[199]
  PIN vr2q[19]
    DIRECTION OUTPUT ;
    USE SIGNAL ;
    PORT
      LAYER M5 ;
        RECT  2.448 0 2.472 0.084 ;
    END
  END vr2q[19]
  PIN vr2q[1]
    DIRECTION OUTPUT ;
    USE SIGNAL ;
    PORT
      LAYER M5 ;
        RECT  0.192 0 0.216 0.084 ;
    END
  END vr2q[1]
  PIN vr2q[200]
    DIRECTION OUTPUT ;
    USE SIGNAL ;
    PORT
      LAYER M3 ;
        RECT  25.308 0 25.326 0.038 ;
    END
  END vr2q[200]
  PIN vr2q[201]
    DIRECTION OUTPUT ;
    USE SIGNAL ;
    PORT
      LAYER M5 ;
        RECT  25.44 0 25.464 0.084 ;
    END
  END vr2q[201]
  PIN vr2q[202]
    DIRECTION OUTPUT ;
    USE SIGNAL ;
    PORT
      LAYER M3 ;
        RECT  25.56 0 25.578 0.038 ;
    END
  END vr2q[202]
  PIN vr2q[203]
    DIRECTION OUTPUT ;
    USE SIGNAL ;
    PORT
      LAYER M5 ;
        RECT  25.68 0 25.704 0.084 ;
    END
  END vr2q[203]
  PIN vr2q[204]
    DIRECTION OUTPUT ;
    USE SIGNAL ;
    PORT
      LAYER M3 ;
        RECT  25.812 0 25.83 0.038 ;
    END
  END vr2q[204]
  PIN vr2q[205]
    DIRECTION OUTPUT ;
    USE SIGNAL ;
    PORT
      LAYER M5 ;
        RECT  25.968 0 25.992 0.084 ;
    END
  END vr2q[205]
  PIN vr2q[206]
    DIRECTION OUTPUT ;
    USE SIGNAL ;
    PORT
      LAYER M3 ;
        RECT  26.064 0 26.082 0.038 ;
    END
  END vr2q[206]
  PIN vr2q[207]
    DIRECTION OUTPUT ;
    USE SIGNAL ;
    PORT
      LAYER M5 ;
        RECT  26.208 0 26.232 0.084 ;
    END
  END vr2q[207]
  PIN vr2q[208]
    DIRECTION OUTPUT ;
    USE SIGNAL ;
    PORT
      LAYER M3 ;
        RECT  26.316 0 26.334 0.038 ;
    END
  END vr2q[208]
  PIN vr2q[209]
    DIRECTION OUTPUT ;
    USE SIGNAL ;
    PORT
      LAYER M5 ;
        RECT  26.448 0 26.472 0.084 ;
    END
  END vr2q[209]
  PIN vr2q[20]
    DIRECTION OUTPUT ;
    USE SIGNAL ;
    PORT
      LAYER M3 ;
        RECT  2.592 0 2.61 0.038 ;
    END
  END vr2q[20]
  PIN vr2q[210]
    DIRECTION OUTPUT ;
    USE SIGNAL ;
    PORT
      LAYER M3 ;
        RECT  26.568 0 26.586 0.038 ;
    END
  END vr2q[210]
  PIN vr2q[211]
    DIRECTION OUTPUT ;
    USE SIGNAL ;
    PORT
      LAYER M5 ;
        RECT  26.688 0 26.712 0.084 ;
    END
  END vr2q[211]
  PIN vr2q[212]
    DIRECTION OUTPUT ;
    USE SIGNAL ;
    PORT
      LAYER M3 ;
        RECT  26.82 0 26.838 0.038 ;
    END
  END vr2q[212]
  PIN vr2q[213]
    DIRECTION OUTPUT ;
    USE SIGNAL ;
    PORT
      LAYER M5 ;
        RECT  26.976 0 27 0.084 ;
    END
  END vr2q[213]
  PIN vr2q[214]
    DIRECTION OUTPUT ;
    USE SIGNAL ;
    PORT
      LAYER M3 ;
        RECT  27.072 0 27.09 0.038 ;
    END
  END vr2q[214]
  PIN vr2q[215]
    DIRECTION OUTPUT ;
    USE SIGNAL ;
    PORT
      LAYER M5 ;
        RECT  27.216 0 27.24 0.084 ;
    END
  END vr2q[215]
  PIN vr2q[216]
    DIRECTION OUTPUT ;
    USE SIGNAL ;
    PORT
      LAYER M3 ;
        RECT  27.324 0 27.342 0.038 ;
    END
  END vr2q[216]
  PIN vr2q[217]
    DIRECTION OUTPUT ;
    USE SIGNAL ;
    PORT
      LAYER M5 ;
        RECT  27.456 0 27.48 0.084 ;
    END
  END vr2q[217]
  PIN vr2q[218]
    DIRECTION OUTPUT ;
    USE SIGNAL ;
    PORT
      LAYER M3 ;
        RECT  27.576 0 27.594 0.038 ;
    END
  END vr2q[218]
  PIN vr2q[219]
    DIRECTION OUTPUT ;
    USE SIGNAL ;
    PORT
      LAYER M5 ;
        RECT  27.696 0 27.72 0.084 ;
    END
  END vr2q[219]
  PIN vr2q[21]
    DIRECTION OUTPUT ;
    USE SIGNAL ;
    PORT
      LAYER M5 ;
        RECT  2.688 0 2.712 0.084 ;
    END
  END vr2q[21]
  PIN vr2q[220]
    DIRECTION OUTPUT ;
    USE SIGNAL ;
    PORT
      LAYER M3 ;
        RECT  27.828 0 27.846 0.038 ;
    END
  END vr2q[220]
  PIN vr2q[221]
    DIRECTION OUTPUT ;
    USE SIGNAL ;
    PORT
      LAYER M5 ;
        RECT  27.984 0 28.008 0.084 ;
    END
  END vr2q[221]
  PIN vr2q[222]
    DIRECTION OUTPUT ;
    USE SIGNAL ;
    PORT
      LAYER M3 ;
        RECT  28.08 0 28.098 0.038 ;
    END
  END vr2q[222]
  PIN vr2q[223]
    DIRECTION OUTPUT ;
    USE SIGNAL ;
    PORT
      LAYER M5 ;
        RECT  28.224 0 28.248 0.084 ;
    END
  END vr2q[223]
  PIN vr2q[224]
    DIRECTION OUTPUT ;
    USE SIGNAL ;
    PORT
      LAYER M3 ;
        RECT  28.332 0 28.35 0.038 ;
    END
  END vr2q[224]
  PIN vr2q[225]
    DIRECTION OUTPUT ;
    USE SIGNAL ;
    PORT
      LAYER M5 ;
        RECT  28.464 0 28.488 0.084 ;
    END
  END vr2q[225]
  PIN vr2q[226]
    DIRECTION OUTPUT ;
    USE SIGNAL ;
    PORT
      LAYER M3 ;
        RECT  28.62 0 28.638 0.038 ;
    END
  END vr2q[226]
  PIN vr2q[227]
    DIRECTION OUTPUT ;
    USE SIGNAL ;
    PORT
      LAYER M5 ;
        RECT  28.704 0 28.728 0.084 ;
    END
  END vr2q[227]
  PIN vr2q[228]
    DIRECTION OUTPUT ;
    USE SIGNAL ;
    PORT
      LAYER M3 ;
        RECT  28.872 0 28.89 0.038 ;
    END
  END vr2q[228]
  PIN vr2q[229]
    DIRECTION OUTPUT ;
    USE SIGNAL ;
    PORT
      LAYER M5 ;
        RECT  28.992 0 29.016 0.084 ;
    END
  END vr2q[229]
  PIN vr2q[22]
    DIRECTION OUTPUT ;
    USE SIGNAL ;
    PORT
      LAYER M3 ;
        RECT  2.844 0 2.862 0.038 ;
    END
  END vr2q[22]
  PIN vr2q[230]
    DIRECTION OUTPUT ;
    USE SIGNAL ;
    PORT
      LAYER M3 ;
        RECT  29.124 0 29.142 0.038 ;
    END
  END vr2q[230]
  PIN vr2q[231]
    DIRECTION OUTPUT ;
    USE SIGNAL ;
    PORT
      LAYER M5 ;
        RECT  29.232 0 29.256 0.084 ;
    END
  END vr2q[231]
  PIN vr2q[232]
    DIRECTION OUTPUT ;
    USE SIGNAL ;
    PORT
      LAYER M3 ;
        RECT  29.376 0 29.394 0.038 ;
    END
  END vr2q[232]
  PIN vr2q[233]
    DIRECTION OUTPUT ;
    USE SIGNAL ;
    PORT
      LAYER M5 ;
        RECT  29.472 0 29.496 0.084 ;
    END
  END vr2q[233]
  PIN vr2q[234]
    DIRECTION OUTPUT ;
    USE SIGNAL ;
    PORT
      LAYER M3 ;
        RECT  29.628 0 29.646 0.038 ;
    END
  END vr2q[234]
  PIN vr2q[235]
    DIRECTION OUTPUT ;
    USE SIGNAL ;
    PORT
      LAYER M5 ;
        RECT  29.712 0 29.736 0.084 ;
    END
  END vr2q[235]
  PIN vr2q[236]
    DIRECTION OUTPUT ;
    USE SIGNAL ;
    PORT
      LAYER M3 ;
        RECT  29.88 0 29.898 0.038 ;
    END
  END vr2q[236]
  PIN vr2q[237]
    DIRECTION OUTPUT ;
    USE SIGNAL ;
    PORT
      LAYER M5 ;
        RECT  30 0 30.024 0.084 ;
    END
  END vr2q[237]
  PIN vr2q[238]
    DIRECTION OUTPUT ;
    USE SIGNAL ;
    PORT
      LAYER M3 ;
        RECT  30.132 0 30.15 0.038 ;
    END
  END vr2q[238]
  PIN vr2q[239]
    DIRECTION OUTPUT ;
    USE SIGNAL ;
    PORT
      LAYER M5 ;
        RECT  30.24 0 30.264 0.084 ;
    END
  END vr2q[239]
  PIN vr2q[23]
    DIRECTION OUTPUT ;
    USE SIGNAL ;
    PORT
      LAYER M5 ;
        RECT  2.976 0 3 0.084 ;
    END
  END vr2q[23]
  PIN vr2q[240]
    DIRECTION OUTPUT ;
    USE SIGNAL ;
    PORT
      LAYER M3 ;
        RECT  30.384 0 30.402 0.038 ;
    END
  END vr2q[240]
  PIN vr2q[241]
    DIRECTION OUTPUT ;
    USE SIGNAL ;
    PORT
      LAYER M5 ;
        RECT  30.48 0 30.504 0.084 ;
    END
  END vr2q[241]
  PIN vr2q[242]
    DIRECTION OUTPUT ;
    USE SIGNAL ;
    PORT
      LAYER M3 ;
        RECT  30.636 0 30.654 0.038 ;
    END
  END vr2q[242]
  PIN vr2q[243]
    DIRECTION OUTPUT ;
    USE SIGNAL ;
    PORT
      LAYER M5 ;
        RECT  30.768 0 30.792 0.084 ;
    END
  END vr2q[243]
  PIN vr2q[244]
    DIRECTION OUTPUT ;
    USE SIGNAL ;
    PORT
      LAYER M3 ;
        RECT  30.888 0 30.906 0.038 ;
    END
  END vr2q[244]
  PIN vr2q[245]
    DIRECTION OUTPUT ;
    USE SIGNAL ;
    PORT
      LAYER M5 ;
        RECT  31.008 0 31.032 0.084 ;
    END
  END vr2q[245]
  PIN vr2q[246]
    DIRECTION OUTPUT ;
    USE SIGNAL ;
    PORT
      LAYER M3 ;
        RECT  31.14 0 31.158 0.038 ;
    END
  END vr2q[246]
  PIN vr2q[247]
    DIRECTION OUTPUT ;
    USE SIGNAL ;
    PORT
      LAYER M5 ;
        RECT  31.248 0 31.272 0.084 ;
    END
  END vr2q[247]
  PIN vr2q[248]
    DIRECTION OUTPUT ;
    USE SIGNAL ;
    PORT
      LAYER M3 ;
        RECT  31.392 0 31.41 0.038 ;
    END
  END vr2q[248]
  PIN vr2q[249]
    DIRECTION OUTPUT ;
    USE SIGNAL ;
    PORT
      LAYER M5 ;
        RECT  31.488 0 31.512 0.084 ;
    END
  END vr2q[249]
  PIN vr2q[24]
    DIRECTION OUTPUT ;
    USE SIGNAL ;
    PORT
      LAYER M3 ;
        RECT  3.096 0 3.114 0.038 ;
    END
  END vr2q[24]
  PIN vr2q[250]
    DIRECTION OUTPUT ;
    USE SIGNAL ;
    PORT
      LAYER M3 ;
        RECT  31.644 0 31.662 0.038 ;
    END
  END vr2q[250]
  PIN vr2q[251]
    DIRECTION OUTPUT ;
    USE SIGNAL ;
    PORT
      LAYER M5 ;
        RECT  31.776 0 31.8 0.084 ;
    END
  END vr2q[251]
  PIN vr2q[252]
    DIRECTION OUTPUT ;
    USE SIGNAL ;
    PORT
      LAYER M3 ;
        RECT  31.896 0 31.914 0.038 ;
    END
  END vr2q[252]
  PIN vr2q[253]
    DIRECTION OUTPUT ;
    USE SIGNAL ;
    PORT
      LAYER M5 ;
        RECT  32.016 0 32.04 0.084 ;
    END
  END vr2q[253]
  PIN vr2q[254]
    DIRECTION OUTPUT ;
    USE SIGNAL ;
    PORT
      LAYER M3 ;
        RECT  32.148 0 32.166 0.038 ;
    END
  END vr2q[254]
  PIN vr2q[255]
    DIRECTION OUTPUT ;
    USE SIGNAL ;
    PORT
      LAYER M5 ;
        RECT  32.256 0 32.28 0.084 ;
    END
  END vr2q[255]
  PIN vr2q[256]
    DIRECTION OUTPUT ;
    USE SIGNAL ;
    PORT
      LAYER M3 ;
        RECT  32.4 0 32.418 0.038 ;
    END
  END vr2q[256]
  PIN vr2q[257]
    DIRECTION OUTPUT ;
    USE SIGNAL ;
    PORT
      LAYER M5 ;
        RECT  32.496 0 32.52 0.084 ;
    END
  END vr2q[257]
  PIN vr2q[258]
    DIRECTION OUTPUT ;
    USE SIGNAL ;
    PORT
      LAYER M3 ;
        RECT  32.652 0 32.67 0.038 ;
    END
  END vr2q[258]
  PIN vr2q[259]
    DIRECTION OUTPUT ;
    USE SIGNAL ;
    PORT
      LAYER M5 ;
        RECT  32.784 0 32.808 0.084 ;
    END
  END vr2q[259]
  PIN vr2q[25]
    DIRECTION OUTPUT ;
    USE SIGNAL ;
    PORT
      LAYER M5 ;
        RECT  3.216 0 3.24 0.084 ;
    END
  END vr2q[25]
  PIN vr2q[260]
    DIRECTION OUTPUT ;
    USE SIGNAL ;
    PORT
      LAYER M3 ;
        RECT  32.904 0 32.922 0.038 ;
    END
  END vr2q[260]
  PIN vr2q[261]
    DIRECTION OUTPUT ;
    USE SIGNAL ;
    PORT
      LAYER M5 ;
        RECT  33.024 0 33.048 0.084 ;
    END
  END vr2q[261]
  PIN vr2q[262]
    DIRECTION OUTPUT ;
    USE SIGNAL ;
    PORT
      LAYER M3 ;
        RECT  33.156 0 33.174 0.038 ;
    END
  END vr2q[262]
  PIN vr2q[263]
    DIRECTION OUTPUT ;
    USE SIGNAL ;
    PORT
      LAYER M5 ;
        RECT  33.264 0 33.288 0.084 ;
    END
  END vr2q[263]
  PIN vr2q[264]
    DIRECTION OUTPUT ;
    USE SIGNAL ;
    PORT
      LAYER M3 ;
        RECT  33.408 0 33.426 0.038 ;
    END
  END vr2q[264]
  PIN vr2q[265]
    DIRECTION OUTPUT ;
    USE SIGNAL ;
    PORT
      LAYER M5 ;
        RECT  33.504 0 33.528 0.084 ;
    END
  END vr2q[265]
  PIN vr2q[266]
    DIRECTION OUTPUT ;
    USE SIGNAL ;
    PORT
      LAYER M3 ;
        RECT  33.66 0 33.678 0.038 ;
    END
  END vr2q[266]
  PIN vr2q[267]
    DIRECTION OUTPUT ;
    USE SIGNAL ;
    PORT
      LAYER M5 ;
        RECT  33.792 0 33.816 0.084 ;
    END
  END vr2q[267]
  PIN vr2q[268]
    DIRECTION OUTPUT ;
    USE SIGNAL ;
    PORT
      LAYER M3 ;
        RECT  33.912 0 33.93 0.038 ;
    END
  END vr2q[268]
  PIN vr2q[269]
    DIRECTION OUTPUT ;
    USE SIGNAL ;
    PORT
      LAYER M5 ;
        RECT  34.032 0 34.056 0.084 ;
    END
  END vr2q[269]
  PIN vr2q[26]
    DIRECTION OUTPUT ;
    USE SIGNAL ;
    PORT
      LAYER M3 ;
        RECT  3.348 0 3.366 0.038 ;
    END
  END vr2q[26]
  PIN vr2q[270]
    DIRECTION OUTPUT ;
    USE SIGNAL ;
    PORT
      LAYER M3 ;
        RECT  34.164 0 34.182 0.038 ;
    END
  END vr2q[270]
  PIN vr2q[271]
    DIRECTION OUTPUT ;
    USE SIGNAL ;
    PORT
      LAYER M5 ;
        RECT  34.272 0 34.296 0.084 ;
    END
  END vr2q[271]
  PIN vr2q[272]
    DIRECTION OUTPUT ;
    USE SIGNAL ;
    PORT
      LAYER M3 ;
        RECT  34.416 0 34.434 0.038 ;
    END
  END vr2q[272]
  PIN vr2q[273]
    DIRECTION OUTPUT ;
    USE SIGNAL ;
    PORT
      LAYER M5 ;
        RECT  34.512 0 34.536 0.084 ;
    END
  END vr2q[273]
  PIN vr2q[274]
    DIRECTION OUTPUT ;
    USE SIGNAL ;
    PORT
      LAYER M3 ;
        RECT  34.668 0 34.686 0.038 ;
    END
  END vr2q[274]
  PIN vr2q[275]
    DIRECTION OUTPUT ;
    USE SIGNAL ;
    PORT
      LAYER M5 ;
        RECT  34.8 0 34.824 0.084 ;
    END
  END vr2q[275]
  PIN vr2q[276]
    DIRECTION OUTPUT ;
    USE SIGNAL ;
    PORT
      LAYER M3 ;
        RECT  34.92 0 34.938 0.038 ;
    END
  END vr2q[276]
  PIN vr2q[277]
    DIRECTION OUTPUT ;
    USE SIGNAL ;
    PORT
      LAYER M5 ;
        RECT  35.04 0 35.064 0.084 ;
    END
  END vr2q[277]
  PIN vr2q[278]
    DIRECTION OUTPUT ;
    USE SIGNAL ;
    PORT
      LAYER M3 ;
        RECT  35.172 0 35.19 0.038 ;
    END
  END vr2q[278]
  PIN vr2q[279]
    DIRECTION OUTPUT ;
    USE SIGNAL ;
    PORT
      LAYER M5 ;
        RECT  35.28 0 35.304 0.084 ;
    END
  END vr2q[279]
  PIN vr2q[27]
    DIRECTION OUTPUT ;
    USE SIGNAL ;
    PORT
      LAYER M5 ;
        RECT  3.456 0 3.48 0.084 ;
    END
  END vr2q[27]
  PIN vr2q[280]
    DIRECTION OUTPUT ;
    USE SIGNAL ;
    PORT
      LAYER M3 ;
        RECT  35.424 0 35.442 0.038 ;
    END
  END vr2q[280]
  PIN vr2q[281]
    DIRECTION OUTPUT ;
    USE SIGNAL ;
    PORT
      LAYER M5 ;
        RECT  35.568 0 35.592 0.084 ;
    END
  END vr2q[281]
  PIN vr2q[282]
    DIRECTION OUTPUT ;
    USE SIGNAL ;
    PORT
      LAYER M3 ;
        RECT  35.676 0 35.694 0.038 ;
    END
  END vr2q[282]
  PIN vr2q[283]
    DIRECTION OUTPUT ;
    USE SIGNAL ;
    PORT
      LAYER M5 ;
        RECT  35.808 0 35.832 0.084 ;
    END
  END vr2q[283]
  PIN vr2q[284]
    DIRECTION OUTPUT ;
    USE SIGNAL ;
    PORT
      LAYER M3 ;
        RECT  35.928 0 35.946 0.038 ;
    END
  END vr2q[284]
  PIN vr2q[285]
    DIRECTION OUTPUT ;
    USE SIGNAL ;
    PORT
      LAYER M5 ;
        RECT  36.048 0 36.072 0.084 ;
    END
  END vr2q[285]
  PIN vr2q[286]
    DIRECTION OUTPUT ;
    USE SIGNAL ;
    PORT
      LAYER M3 ;
        RECT  36.18 0 36.198 0.038 ;
    END
  END vr2q[286]
  PIN vr2q[287]
    DIRECTION OUTPUT ;
    USE SIGNAL ;
    PORT
      LAYER M5 ;
        RECT  36.288 0 36.312 0.084 ;
    END
  END vr2q[287]
  PIN vr2q[288]
    DIRECTION OUTPUT ;
    USE SIGNAL ;
    PORT
      LAYER M3 ;
        RECT  36.432 0 36.45 0.038 ;
    END
  END vr2q[288]
  PIN vr2q[289]
    DIRECTION OUTPUT ;
    USE SIGNAL ;
    PORT
      LAYER M5 ;
        RECT  36.576 0 36.6 0.084 ;
    END
  END vr2q[289]
  PIN vr2q[28]
    DIRECTION OUTPUT ;
    USE SIGNAL ;
    PORT
      LAYER M3 ;
        RECT  3.6 0 3.618 0.038 ;
    END
  END vr2q[28]
  PIN vr2q[290]
    DIRECTION OUTPUT ;
    USE SIGNAL ;
    PORT
      LAYER M3 ;
        RECT  36.684 0 36.702 0.038 ;
    END
  END vr2q[290]
  PIN vr2q[291]
    DIRECTION OUTPUT ;
    USE SIGNAL ;
    PORT
      LAYER M5 ;
        RECT  36.816 0 36.84 0.084 ;
    END
  END vr2q[291]
  PIN vr2q[292]
    DIRECTION OUTPUT ;
    USE SIGNAL ;
    PORT
      LAYER M3 ;
        RECT  36.936 0 36.954 0.038 ;
    END
  END vr2q[292]
  PIN vr2q[293]
    DIRECTION OUTPUT ;
    USE SIGNAL ;
    PORT
      LAYER M5 ;
        RECT  37.056 0 37.08 0.084 ;
    END
  END vr2q[293]
  PIN vr2q[294]
    DIRECTION OUTPUT ;
    USE SIGNAL ;
    PORT
      LAYER M3 ;
        RECT  37.188 0 37.206 0.038 ;
    END
  END vr2q[294]
  PIN vr2q[295]
    DIRECTION OUTPUT ;
    USE SIGNAL ;
    PORT
      LAYER M5 ;
        RECT  37.296 0 37.32 0.084 ;
    END
  END vr2q[295]
  PIN vr2q[296]
    DIRECTION OUTPUT ;
    USE SIGNAL ;
    PORT
      LAYER M3 ;
        RECT  37.44 0 37.458 0.038 ;
    END
  END vr2q[296]
  PIN vr2q[297]
    DIRECTION OUTPUT ;
    USE SIGNAL ;
    PORT
      LAYER M5 ;
        RECT  37.584 0 37.608 0.084 ;
    END
  END vr2q[297]
  PIN vr2q[298]
    DIRECTION OUTPUT ;
    USE SIGNAL ;
    PORT
      LAYER M3 ;
        RECT  37.692 0 37.71 0.038 ;
    END
  END vr2q[298]
  PIN vr2q[299]
    DIRECTION OUTPUT ;
    USE SIGNAL ;
    PORT
      LAYER M5 ;
        RECT  37.824 0 37.848 0.084 ;
    END
  END vr2q[299]
  PIN vr2q[29]
    DIRECTION OUTPUT ;
    USE SIGNAL ;
    PORT
      LAYER M5 ;
        RECT  3.696 0 3.72 0.084 ;
    END
  END vr2q[29]
  PIN vr2q[2]
    DIRECTION OUTPUT ;
    USE SIGNAL ;
    PORT
      LAYER M3 ;
        RECT  0.324 0 0.342 0.038 ;
    END
  END vr2q[2]
  PIN vr2q[300]
    DIRECTION OUTPUT ;
    USE SIGNAL ;
    PORT
      LAYER M3 ;
        RECT  37.944 0 37.962 0.038 ;
    END
  END vr2q[300]
  PIN vr2q[301]
    DIRECTION OUTPUT ;
    USE SIGNAL ;
    PORT
      LAYER M5 ;
        RECT  38.064 0 38.088 0.084 ;
    END
  END vr2q[301]
  PIN vr2q[302]
    DIRECTION OUTPUT ;
    USE SIGNAL ;
    PORT
      LAYER M3 ;
        RECT  38.196 0 38.214 0.038 ;
    END
  END vr2q[302]
  PIN vr2q[303]
    DIRECTION OUTPUT ;
    USE SIGNAL ;
    PORT
      LAYER M5 ;
        RECT  38.304 0 38.328 0.084 ;
    END
  END vr2q[303]
  PIN vr2q[304]
    DIRECTION OUTPUT ;
    USE SIGNAL ;
    PORT
      LAYER M3 ;
        RECT  38.448 0 38.466 0.038 ;
    END
  END vr2q[304]
  PIN vr2q[305]
    DIRECTION OUTPUT ;
    USE SIGNAL ;
    PORT
      LAYER M5 ;
        RECT  38.592 0 38.616 0.084 ;
    END
  END vr2q[305]
  PIN vr2q[306]
    DIRECTION OUTPUT ;
    USE SIGNAL ;
    PORT
      LAYER M3 ;
        RECT  38.7 0 38.718 0.038 ;
    END
  END vr2q[306]
  PIN vr2q[307]
    DIRECTION OUTPUT ;
    USE SIGNAL ;
    PORT
      LAYER M5 ;
        RECT  38.832 0 38.856 0.084 ;
    END
  END vr2q[307]
  PIN vr2q[308]
    DIRECTION OUTPUT ;
    USE SIGNAL ;
    PORT
      LAYER M3 ;
        RECT  38.952 0 38.97 0.038 ;
    END
  END vr2q[308]
  PIN vr2q[309]
    DIRECTION OUTPUT ;
    USE SIGNAL ;
    PORT
      LAYER M5 ;
        RECT  39.072 0 39.096 0.084 ;
    END
  END vr2q[309]
  PIN vr2q[30]
    DIRECTION OUTPUT ;
    USE SIGNAL ;
    PORT
      LAYER M3 ;
        RECT  3.852 0 3.87 0.038 ;
    END
  END vr2q[30]
  PIN vr2q[310]
    DIRECTION OUTPUT ;
    USE SIGNAL ;
    PORT
      LAYER M3 ;
        RECT  39.204 0 39.222 0.038 ;
    END
  END vr2q[310]
  PIN vr2q[311]
    DIRECTION OUTPUT ;
    USE SIGNAL ;
    PORT
      LAYER M5 ;
        RECT  39.312 0 39.336 0.084 ;
    END
  END vr2q[311]
  PIN vr2q[312]
    DIRECTION OUTPUT ;
    USE SIGNAL ;
    PORT
      LAYER M3 ;
        RECT  39.456 0 39.474 0.038 ;
    END
  END vr2q[312]
  PIN vr2q[313]
    DIRECTION OUTPUT ;
    USE SIGNAL ;
    PORT
      LAYER M5 ;
        RECT  39.6 0 39.624 0.084 ;
    END
  END vr2q[313]
  PIN vr2q[314]
    DIRECTION OUTPUT ;
    USE SIGNAL ;
    PORT
      LAYER M3 ;
        RECT  39.708 0 39.726 0.038 ;
    END
  END vr2q[314]
  PIN vr2q[315]
    DIRECTION OUTPUT ;
    USE SIGNAL ;
    PORT
      LAYER M5 ;
        RECT  39.84 0 39.864 0.084 ;
    END
  END vr2q[315]
  PIN vr2q[316]
    DIRECTION OUTPUT ;
    USE SIGNAL ;
    PORT
      LAYER M3 ;
        RECT  39.96 0 39.978 0.038 ;
    END
  END vr2q[316]
  PIN vr2q[317]
    DIRECTION OUTPUT ;
    USE SIGNAL ;
    PORT
      LAYER M5 ;
        RECT  40.08 0 40.104 0.084 ;
    END
  END vr2q[317]
  PIN vr2q[318]
    DIRECTION OUTPUT ;
    USE SIGNAL ;
    PORT
      LAYER M3 ;
        RECT  40.212 0 40.23 0.038 ;
    END
  END vr2q[318]
  PIN vr2q[319]
    DIRECTION OUTPUT ;
    USE SIGNAL ;
    PORT
      LAYER M5 ;
        RECT  40.368 0 40.392 0.084 ;
    END
  END vr2q[319]
  PIN vr2q[31]
    DIRECTION OUTPUT ;
    USE SIGNAL ;
    PORT
      LAYER M5 ;
        RECT  3.984 0 4.008 0.084 ;
    END
  END vr2q[31]
  PIN vr2q[320]
    DIRECTION OUTPUT ;
    USE SIGNAL ;
    PORT
      LAYER M3 ;
        RECT  40.464 0 40.482 0.038 ;
    END
  END vr2q[320]
  PIN vr2q[321]
    DIRECTION OUTPUT ;
    USE SIGNAL ;
    PORT
      LAYER M5 ;
        RECT  40.608 0 40.632 0.084 ;
    END
  END vr2q[321]
  PIN vr2q[322]
    DIRECTION OUTPUT ;
    USE SIGNAL ;
    PORT
      LAYER M3 ;
        RECT  40.716 0 40.734 0.038 ;
    END
  END vr2q[322]
  PIN vr2q[323]
    DIRECTION OUTPUT ;
    USE SIGNAL ;
    PORT
      LAYER M5 ;
        RECT  40.848 0 40.872 0.084 ;
    END
  END vr2q[323]
  PIN vr2q[324]
    DIRECTION OUTPUT ;
    USE SIGNAL ;
    PORT
      LAYER M3 ;
        RECT  40.968 0 40.986 0.038 ;
    END
  END vr2q[324]
  PIN vr2q[325]
    DIRECTION OUTPUT ;
    USE SIGNAL ;
    PORT
      LAYER M5 ;
        RECT  41.088 0 41.112 0.084 ;
    END
  END vr2q[325]
  PIN vr2q[326]
    DIRECTION OUTPUT ;
    USE SIGNAL ;
    PORT
      LAYER M3 ;
        RECT  41.22 0 41.238 0.038 ;
    END
  END vr2q[326]
  PIN vr2q[327]
    DIRECTION OUTPUT ;
    USE SIGNAL ;
    PORT
      LAYER M5 ;
        RECT  41.376 0 41.4 0.084 ;
    END
  END vr2q[327]
  PIN vr2q[328]
    DIRECTION OUTPUT ;
    USE SIGNAL ;
    PORT
      LAYER M3 ;
        RECT  41.472 0 41.49 0.038 ;
    END
  END vr2q[328]
  PIN vr2q[329]
    DIRECTION OUTPUT ;
    USE SIGNAL ;
    PORT
      LAYER M5 ;
        RECT  41.616 0 41.64 0.084 ;
    END
  END vr2q[329]
  PIN vr2q[32]
    DIRECTION OUTPUT ;
    USE SIGNAL ;
    PORT
      LAYER M3 ;
        RECT  4.104 0 4.122 0.038 ;
    END
  END vr2q[32]
  PIN vr2q[330]
    DIRECTION OUTPUT ;
    USE SIGNAL ;
    PORT
      LAYER M3 ;
        RECT  41.724 0 41.742 0.038 ;
    END
  END vr2q[330]
  PIN vr2q[331]
    DIRECTION OUTPUT ;
    USE SIGNAL ;
    PORT
      LAYER M5 ;
        RECT  41.856 0 41.88 0.084 ;
    END
  END vr2q[331]
  PIN vr2q[332]
    DIRECTION OUTPUT ;
    USE SIGNAL ;
    PORT
      LAYER M3 ;
        RECT  41.976 0 41.994 0.038 ;
    END
  END vr2q[332]
  PIN vr2q[333]
    DIRECTION OUTPUT ;
    USE SIGNAL ;
    PORT
      LAYER M5 ;
        RECT  42.096 0 42.12 0.084 ;
    END
  END vr2q[333]
  PIN vr2q[334]
    DIRECTION OUTPUT ;
    USE SIGNAL ;
    PORT
      LAYER M3 ;
        RECT  42.228 0 42.246 0.038 ;
    END
  END vr2q[334]
  PIN vr2q[335]
    DIRECTION OUTPUT ;
    USE SIGNAL ;
    PORT
      LAYER M5 ;
        RECT  42.384 0 42.408 0.084 ;
    END
  END vr2q[335]
  PIN vr2q[336]
    DIRECTION OUTPUT ;
    USE SIGNAL ;
    PORT
      LAYER M3 ;
        RECT  42.48 0 42.498 0.038 ;
    END
  END vr2q[336]
  PIN vr2q[337]
    DIRECTION OUTPUT ;
    USE SIGNAL ;
    PORT
      LAYER M5 ;
        RECT  42.624 0 42.648 0.084 ;
    END
  END vr2q[337]
  PIN vr2q[338]
    DIRECTION OUTPUT ;
    USE SIGNAL ;
    PORT
      LAYER M3 ;
        RECT  42.732 0 42.75 0.038 ;
    END
  END vr2q[338]
  PIN vr2q[339]
    DIRECTION OUTPUT ;
    USE SIGNAL ;
    PORT
      LAYER M5 ;
        RECT  42.864 0 42.888 0.084 ;
    END
  END vr2q[339]
  PIN vr2q[33]
    DIRECTION OUTPUT ;
    USE SIGNAL ;
    PORT
      LAYER M5 ;
        RECT  4.224 0 4.248 0.084 ;
    END
  END vr2q[33]
  PIN vr2q[340]
    DIRECTION OUTPUT ;
    USE SIGNAL ;
    PORT
      LAYER M3 ;
        RECT  43.02 0 43.038 0.038 ;
    END
  END vr2q[340]
  PIN vr2q[341]
    DIRECTION OUTPUT ;
    USE SIGNAL ;
    PORT
      LAYER M5 ;
        RECT  43.104 0 43.128 0.084 ;
    END
  END vr2q[341]
  PIN vr2q[342]
    DIRECTION OUTPUT ;
    USE SIGNAL ;
    PORT
      LAYER M3 ;
        RECT  43.272 0 43.29 0.038 ;
    END
  END vr2q[342]
  PIN vr2q[343]
    DIRECTION OUTPUT ;
    USE SIGNAL ;
    PORT
      LAYER M5 ;
        RECT  43.392 0 43.416 0.084 ;
    END
  END vr2q[343]
  PIN vr2q[344]
    DIRECTION OUTPUT ;
    USE SIGNAL ;
    PORT
      LAYER M3 ;
        RECT  43.524 0 43.542 0.038 ;
    END
  END vr2q[344]
  PIN vr2q[345]
    DIRECTION OUTPUT ;
    USE SIGNAL ;
    PORT
      LAYER M5 ;
        RECT  43.632 0 43.656 0.084 ;
    END
  END vr2q[345]
  PIN vr2q[346]
    DIRECTION OUTPUT ;
    USE SIGNAL ;
    PORT
      LAYER M3 ;
        RECT  43.776 0 43.794 0.038 ;
    END
  END vr2q[346]
  PIN vr2q[347]
    DIRECTION OUTPUT ;
    USE SIGNAL ;
    PORT
      LAYER M5 ;
        RECT  43.872 0 43.896 0.084 ;
    END
  END vr2q[347]
  PIN vr2q[348]
    DIRECTION OUTPUT ;
    USE SIGNAL ;
    PORT
      LAYER M3 ;
        RECT  44.028 0 44.046 0.038 ;
    END
  END vr2q[348]
  PIN vr2q[349]
    DIRECTION OUTPUT ;
    USE SIGNAL ;
    PORT
      LAYER M5 ;
        RECT  44.112 0 44.136 0.084 ;
    END
  END vr2q[349]
  PIN vr2q[34]
    DIRECTION OUTPUT ;
    USE SIGNAL ;
    PORT
      LAYER M3 ;
        RECT  4.356 0 4.374 0.038 ;
    END
  END vr2q[34]
  PIN vr2q[350]
    DIRECTION OUTPUT ;
    USE SIGNAL ;
    PORT
      LAYER M3 ;
        RECT  44.28 0 44.298 0.038 ;
    END
  END vr2q[350]
  PIN vr2q[351]
    DIRECTION OUTPUT ;
    USE SIGNAL ;
    PORT
      LAYER M5 ;
        RECT  44.4 0 44.424 0.084 ;
    END
  END vr2q[351]
  PIN vr2q[352]
    DIRECTION OUTPUT ;
    USE SIGNAL ;
    PORT
      LAYER M3 ;
        RECT  44.532 0 44.55 0.038 ;
    END
  END vr2q[352]
  PIN vr2q[353]
    DIRECTION OUTPUT ;
    USE SIGNAL ;
    PORT
      LAYER M5 ;
        RECT  44.64 0 44.664 0.084 ;
    END
  END vr2q[353]
  PIN vr2q[354]
    DIRECTION OUTPUT ;
    USE SIGNAL ;
    PORT
      LAYER M3 ;
        RECT  44.784 0 44.802 0.038 ;
    END
  END vr2q[354]
  PIN vr2q[355]
    DIRECTION OUTPUT ;
    USE SIGNAL ;
    PORT
      LAYER M5 ;
        RECT  44.88 0 44.904 0.084 ;
    END
  END vr2q[355]
  PIN vr2q[356]
    DIRECTION OUTPUT ;
    USE SIGNAL ;
    PORT
      LAYER M3 ;
        RECT  45.036 0 45.054 0.038 ;
    END
  END vr2q[356]
  PIN vr2q[357]
    DIRECTION OUTPUT ;
    USE SIGNAL ;
    PORT
      LAYER M5 ;
        RECT  45.168 0 45.192 0.084 ;
    END
  END vr2q[357]
  PIN vr2q[358]
    DIRECTION OUTPUT ;
    USE SIGNAL ;
    PORT
      LAYER M3 ;
        RECT  45.288 0 45.306 0.038 ;
    END
  END vr2q[358]
  PIN vr2q[359]
    DIRECTION OUTPUT ;
    USE SIGNAL ;
    PORT
      LAYER M5 ;
        RECT  45.408 0 45.432 0.084 ;
    END
  END vr2q[359]
  PIN vr2q[35]
    DIRECTION OUTPUT ;
    USE SIGNAL ;
    PORT
      LAYER M5 ;
        RECT  4.464 0 4.488 0.084 ;
    END
  END vr2q[35]
  PIN vr2q[360]
    DIRECTION OUTPUT ;
    USE SIGNAL ;
    PORT
      LAYER M3 ;
        RECT  45.54 0 45.558 0.038 ;
    END
  END vr2q[360]
  PIN vr2q[361]
    DIRECTION OUTPUT ;
    USE SIGNAL ;
    PORT
      LAYER M5 ;
        RECT  45.648 0 45.672 0.084 ;
    END
  END vr2q[361]
  PIN vr2q[362]
    DIRECTION OUTPUT ;
    USE SIGNAL ;
    PORT
      LAYER M3 ;
        RECT  45.792 0 45.81 0.038 ;
    END
  END vr2q[362]
  PIN vr2q[363]
    DIRECTION OUTPUT ;
    USE SIGNAL ;
    PORT
      LAYER M5 ;
        RECT  45.888 0 45.912 0.084 ;
    END
  END vr2q[363]
  PIN vr2q[364]
    DIRECTION OUTPUT ;
    USE SIGNAL ;
    PORT
      LAYER M3 ;
        RECT  46.044 0 46.062 0.038 ;
    END
  END vr2q[364]
  PIN vr2q[365]
    DIRECTION OUTPUT ;
    USE SIGNAL ;
    PORT
      LAYER M5 ;
        RECT  46.176 0 46.2 0.084 ;
    END
  END vr2q[365]
  PIN vr2q[366]
    DIRECTION OUTPUT ;
    USE SIGNAL ;
    PORT
      LAYER M3 ;
        RECT  46.296 0 46.314 0.038 ;
    END
  END vr2q[366]
  PIN vr2q[367]
    DIRECTION OUTPUT ;
    USE SIGNAL ;
    PORT
      LAYER M5 ;
        RECT  46.416 0 46.44 0.084 ;
    END
  END vr2q[367]
  PIN vr2q[368]
    DIRECTION OUTPUT ;
    USE SIGNAL ;
    PORT
      LAYER M3 ;
        RECT  46.548 0 46.566 0.038 ;
    END
  END vr2q[368]
  PIN vr2q[369]
    DIRECTION OUTPUT ;
    USE SIGNAL ;
    PORT
      LAYER M5 ;
        RECT  46.656 0 46.68 0.084 ;
    END
  END vr2q[369]
  PIN vr2q[36]
    DIRECTION OUTPUT ;
    USE SIGNAL ;
    PORT
      LAYER M3 ;
        RECT  4.608 0 4.626 0.038 ;
    END
  END vr2q[36]
  PIN vr2q[370]
    DIRECTION OUTPUT ;
    USE SIGNAL ;
    PORT
      LAYER M3 ;
        RECT  46.8 0 46.818 0.038 ;
    END
  END vr2q[370]
  PIN vr2q[371]
    DIRECTION OUTPUT ;
    USE SIGNAL ;
    PORT
      LAYER M5 ;
        RECT  46.896 0 46.92 0.084 ;
    END
  END vr2q[371]
  PIN vr2q[372]
    DIRECTION OUTPUT ;
    USE SIGNAL ;
    PORT
      LAYER M3 ;
        RECT  47.052 0 47.07 0.038 ;
    END
  END vr2q[372]
  PIN vr2q[373]
    DIRECTION OUTPUT ;
    USE SIGNAL ;
    PORT
      LAYER M5 ;
        RECT  47.184 0 47.208 0.084 ;
    END
  END vr2q[373]
  PIN vr2q[374]
    DIRECTION OUTPUT ;
    USE SIGNAL ;
    PORT
      LAYER M3 ;
        RECT  47.304 0 47.322 0.038 ;
    END
  END vr2q[374]
  PIN vr2q[375]
    DIRECTION OUTPUT ;
    USE SIGNAL ;
    PORT
      LAYER M5 ;
        RECT  47.424 0 47.448 0.084 ;
    END
  END vr2q[375]
  PIN vr2q[376]
    DIRECTION OUTPUT ;
    USE SIGNAL ;
    PORT
      LAYER M3 ;
        RECT  47.556 0 47.574 0.038 ;
    END
  END vr2q[376]
  PIN vr2q[377]
    DIRECTION OUTPUT ;
    USE SIGNAL ;
    PORT
      LAYER M5 ;
        RECT  47.664 0 47.688 0.084 ;
    END
  END vr2q[377]
  PIN vr2q[378]
    DIRECTION OUTPUT ;
    USE SIGNAL ;
    PORT
      LAYER M3 ;
        RECT  47.808 0 47.826 0.038 ;
    END
  END vr2q[378]
  PIN vr2q[379]
    DIRECTION OUTPUT ;
    USE SIGNAL ;
    PORT
      LAYER M5 ;
        RECT  47.904 0 47.928 0.084 ;
    END
  END vr2q[379]
  PIN vr2q[37]
    DIRECTION OUTPUT ;
    USE SIGNAL ;
    PORT
      LAYER M5 ;
        RECT  4.704 0 4.728 0.084 ;
    END
  END vr2q[37]
  PIN vr2q[380]
    DIRECTION OUTPUT ;
    USE SIGNAL ;
    PORT
      LAYER M3 ;
        RECT  48.06 0 48.078 0.038 ;
    END
  END vr2q[380]
  PIN vr2q[381]
    DIRECTION OUTPUT ;
    USE SIGNAL ;
    PORT
      LAYER M5 ;
        RECT  48.192 0 48.216 0.084 ;
    END
  END vr2q[381]
  PIN vr2q[382]
    DIRECTION OUTPUT ;
    USE SIGNAL ;
    PORT
      LAYER M3 ;
        RECT  48.312 0 48.33 0.038 ;
    END
  END vr2q[382]
  PIN vr2q[383]
    DIRECTION OUTPUT ;
    USE SIGNAL ;
    PORT
      LAYER M5 ;
        RECT  48.432 0 48.456 0.084 ;
    END
  END vr2q[383]
  PIN vr2q[384]
    DIRECTION OUTPUT ;
    USE SIGNAL ;
    PORT
      LAYER M3 ;
        RECT  48.564 0 48.582 0.038 ;
    END
  END vr2q[384]
  PIN vr2q[385]
    DIRECTION OUTPUT ;
    USE SIGNAL ;
    PORT
      LAYER M5 ;
        RECT  48.672 0 48.696 0.084 ;
    END
  END vr2q[385]
  PIN vr2q[386]
    DIRECTION OUTPUT ;
    USE SIGNAL ;
    PORT
      LAYER M3 ;
        RECT  48.816 0 48.834 0.038 ;
    END
  END vr2q[386]
  PIN vr2q[387]
    DIRECTION OUTPUT ;
    USE SIGNAL ;
    PORT
      LAYER M5 ;
        RECT  48.912 0 48.936 0.084 ;
    END
  END vr2q[387]
  PIN vr2q[388]
    DIRECTION OUTPUT ;
    USE SIGNAL ;
    PORT
      LAYER M3 ;
        RECT  49.068 0 49.086 0.038 ;
    END
  END vr2q[388]
  PIN vr2q[389]
    DIRECTION OUTPUT ;
    USE SIGNAL ;
    PORT
      LAYER M5 ;
        RECT  49.2 0 49.224 0.084 ;
    END
  END vr2q[389]
  PIN vr2q[38]
    DIRECTION OUTPUT ;
    USE SIGNAL ;
    PORT
      LAYER M3 ;
        RECT  4.86 0 4.878 0.038 ;
    END
  END vr2q[38]
  PIN vr2q[390]
    DIRECTION OUTPUT ;
    USE SIGNAL ;
    PORT
      LAYER M3 ;
        RECT  49.32 0 49.338 0.038 ;
    END
  END vr2q[390]
  PIN vr2q[391]
    DIRECTION OUTPUT ;
    USE SIGNAL ;
    PORT
      LAYER M5 ;
        RECT  49.44 0 49.464 0.084 ;
    END
  END vr2q[391]
  PIN vr2q[392]
    DIRECTION OUTPUT ;
    USE SIGNAL ;
    PORT
      LAYER M3 ;
        RECT  49.572 0 49.59 0.038 ;
    END
  END vr2q[392]
  PIN vr2q[393]
    DIRECTION OUTPUT ;
    USE SIGNAL ;
    PORT
      LAYER M5 ;
        RECT  49.68 0 49.704 0.084 ;
    END
  END vr2q[393]
  PIN vr2q[394]
    DIRECTION OUTPUT ;
    USE SIGNAL ;
    PORT
      LAYER M3 ;
        RECT  49.824 0 49.842 0.038 ;
    END
  END vr2q[394]
  PIN vr2q[395]
    DIRECTION OUTPUT ;
    USE SIGNAL ;
    PORT
      LAYER M5 ;
        RECT  49.968 0 49.992 0.084 ;
    END
  END vr2q[395]
  PIN vr2q[396]
    DIRECTION OUTPUT ;
    USE SIGNAL ;
    PORT
      LAYER M3 ;
        RECT  50.076 0 50.094 0.038 ;
    END
  END vr2q[396]
  PIN vr2q[397]
    DIRECTION OUTPUT ;
    USE SIGNAL ;
    PORT
      LAYER M5 ;
        RECT  50.208 0 50.232 0.084 ;
    END
  END vr2q[397]
  PIN vr2q[398]
    DIRECTION OUTPUT ;
    USE SIGNAL ;
    PORT
      LAYER M3 ;
        RECT  50.328 0 50.346 0.038 ;
    END
  END vr2q[398]
  PIN vr2q[399]
    DIRECTION OUTPUT ;
    USE SIGNAL ;
    PORT
      LAYER M5 ;
        RECT  50.448 0 50.472 0.084 ;
    END
  END vr2q[399]
  PIN vr2q[39]
    DIRECTION OUTPUT ;
    USE SIGNAL ;
    PORT
      LAYER M5 ;
        RECT  4.992 0 5.016 0.084 ;
    END
  END vr2q[39]
  PIN vr2q[3]
    DIRECTION OUTPUT ;
    USE SIGNAL ;
    PORT
      LAYER M5 ;
        RECT  0.432 0 0.456 0.084 ;
    END
  END vr2q[3]
  PIN vr2q[400]
    DIRECTION OUTPUT ;
    USE SIGNAL ;
    PORT
      LAYER M3 ;
        RECT  50.58 0 50.598 0.038 ;
    END
  END vr2q[400]
  PIN vr2q[401]
    DIRECTION OUTPUT ;
    USE SIGNAL ;
    PORT
      LAYER M5 ;
        RECT  50.688 0 50.712 0.084 ;
    END
  END vr2q[401]
  PIN vr2q[402]
    DIRECTION OUTPUT ;
    USE SIGNAL ;
    PORT
      LAYER M3 ;
        RECT  50.832 0 50.85 0.038 ;
    END
  END vr2q[402]
  PIN vr2q[403]
    DIRECTION OUTPUT ;
    USE SIGNAL ;
    PORT
      LAYER M5 ;
        RECT  50.976 0 51 0.084 ;
    END
  END vr2q[403]
  PIN vr2q[404]
    DIRECTION OUTPUT ;
    USE SIGNAL ;
    PORT
      LAYER M3 ;
        RECT  51.084 0 51.102 0.038 ;
    END
  END vr2q[404]
  PIN vr2q[405]
    DIRECTION OUTPUT ;
    USE SIGNAL ;
    PORT
      LAYER M5 ;
        RECT  51.216 0 51.24 0.084 ;
    END
  END vr2q[405]
  PIN vr2q[406]
    DIRECTION OUTPUT ;
    USE SIGNAL ;
    PORT
      LAYER M3 ;
        RECT  51.336 0 51.354 0.038 ;
    END
  END vr2q[406]
  PIN vr2q[407]
    DIRECTION OUTPUT ;
    USE SIGNAL ;
    PORT
      LAYER M5 ;
        RECT  51.456 0 51.48 0.084 ;
    END
  END vr2q[407]
  PIN vr2q[408]
    DIRECTION OUTPUT ;
    USE SIGNAL ;
    PORT
      LAYER M3 ;
        RECT  51.588 0 51.606 0.038 ;
    END
  END vr2q[408]
  PIN vr2q[409]
    DIRECTION OUTPUT ;
    USE SIGNAL ;
    PORT
      LAYER M5 ;
        RECT  51.696 0 51.72 0.084 ;
    END
  END vr2q[409]
  PIN vr2q[40]
    DIRECTION OUTPUT ;
    USE SIGNAL ;
    PORT
      LAYER M3 ;
        RECT  5.112 0 5.13 0.038 ;
    END
  END vr2q[40]
  PIN vr2q[410]
    DIRECTION OUTPUT ;
    USE SIGNAL ;
    PORT
      LAYER M3 ;
        RECT  51.84 0 51.858 0.038 ;
    END
  END vr2q[410]
  PIN vr2q[411]
    DIRECTION OUTPUT ;
    USE SIGNAL ;
    PORT
      LAYER M5 ;
        RECT  51.984 0 52.008 0.084 ;
    END
  END vr2q[411]
  PIN vr2q[412]
    DIRECTION OUTPUT ;
    USE SIGNAL ;
    PORT
      LAYER M3 ;
        RECT  52.092 0 52.11 0.038 ;
    END
  END vr2q[412]
  PIN vr2q[413]
    DIRECTION OUTPUT ;
    USE SIGNAL ;
    PORT
      LAYER M5 ;
        RECT  52.224 0 52.248 0.084 ;
    END
  END vr2q[413]
  PIN vr2q[414]
    DIRECTION OUTPUT ;
    USE SIGNAL ;
    PORT
      LAYER M3 ;
        RECT  52.344 0 52.362 0.038 ;
    END
  END vr2q[414]
  PIN vr2q[415]
    DIRECTION OUTPUT ;
    USE SIGNAL ;
    PORT
      LAYER M5 ;
        RECT  52.464 0 52.488 0.084 ;
    END
  END vr2q[415]
  PIN vr2q[416]
    DIRECTION OUTPUT ;
    USE SIGNAL ;
    PORT
      LAYER M3 ;
        RECT  52.596 0 52.614 0.038 ;
    END
  END vr2q[416]
  PIN vr2q[417]
    DIRECTION OUTPUT ;
    USE SIGNAL ;
    PORT
      LAYER M5 ;
        RECT  52.704 0 52.728 0.084 ;
    END
  END vr2q[417]
  PIN vr2q[418]
    DIRECTION OUTPUT ;
    USE SIGNAL ;
    PORT
      LAYER M3 ;
        RECT  52.848 0 52.866 0.038 ;
    END
  END vr2q[418]
  PIN vr2q[419]
    DIRECTION OUTPUT ;
    USE SIGNAL ;
    PORT
      LAYER M5 ;
        RECT  52.992 0 53.016 0.084 ;
    END
  END vr2q[419]
  PIN vr2q[41]
    DIRECTION OUTPUT ;
    USE SIGNAL ;
    PORT
      LAYER M5 ;
        RECT  5.232 0 5.256 0.084 ;
    END
  END vr2q[41]
  PIN vr2q[420]
    DIRECTION OUTPUT ;
    USE SIGNAL ;
    PORT
      LAYER M3 ;
        RECT  53.1 0 53.118 0.038 ;
    END
  END vr2q[420]
  PIN vr2q[421]
    DIRECTION OUTPUT ;
    USE SIGNAL ;
    PORT
      LAYER M5 ;
        RECT  53.232 0 53.256 0.084 ;
    END
  END vr2q[421]
  PIN vr2q[422]
    DIRECTION OUTPUT ;
    USE SIGNAL ;
    PORT
      LAYER M3 ;
        RECT  53.352 0 53.37 0.038 ;
    END
  END vr2q[422]
  PIN vr2q[423]
    DIRECTION OUTPUT ;
    USE SIGNAL ;
    PORT
      LAYER M5 ;
        RECT  53.472 0 53.496 0.084 ;
    END
  END vr2q[423]
  PIN vr2q[424]
    DIRECTION OUTPUT ;
    USE SIGNAL ;
    PORT
      LAYER M3 ;
        RECT  53.604 0 53.622 0.038 ;
    END
  END vr2q[424]
  PIN vr2q[425]
    DIRECTION OUTPUT ;
    USE SIGNAL ;
    PORT
      LAYER M5 ;
        RECT  53.712 0 53.736 0.084 ;
    END
  END vr2q[425]
  PIN vr2q[426]
    DIRECTION OUTPUT ;
    USE SIGNAL ;
    PORT
      LAYER M3 ;
        RECT  53.856 0 53.874 0.038 ;
    END
  END vr2q[426]
  PIN vr2q[427]
    DIRECTION OUTPUT ;
    USE SIGNAL ;
    PORT
      LAYER M5 ;
        RECT  54 0 54.024 0.084 ;
    END
  END vr2q[427]
  PIN vr2q[428]
    DIRECTION OUTPUT ;
    USE SIGNAL ;
    PORT
      LAYER M3 ;
        RECT  54.108 0 54.126 0.038 ;
    END
  END vr2q[428]
  PIN vr2q[429]
    DIRECTION OUTPUT ;
    USE SIGNAL ;
    PORT
      LAYER M5 ;
        RECT  54.24 0 54.264 0.084 ;
    END
  END vr2q[429]
  PIN vr2q[42]
    DIRECTION OUTPUT ;
    USE SIGNAL ;
    PORT
      LAYER M3 ;
        RECT  5.364 0 5.382 0.038 ;
    END
  END vr2q[42]
  PIN vr2q[430]
    DIRECTION OUTPUT ;
    USE SIGNAL ;
    PORT
      LAYER M3 ;
        RECT  54.36 0 54.378 0.038 ;
    END
  END vr2q[430]
  PIN vr2q[431]
    DIRECTION OUTPUT ;
    USE SIGNAL ;
    PORT
      LAYER M5 ;
        RECT  54.48 0 54.504 0.084 ;
    END
  END vr2q[431]
  PIN vr2q[432]
    DIRECTION OUTPUT ;
    USE SIGNAL ;
    PORT
      LAYER M3 ;
        RECT  54.612 0 54.63 0.038 ;
    END
  END vr2q[432]
  PIN vr2q[433]
    DIRECTION OUTPUT ;
    USE SIGNAL ;
    PORT
      LAYER M5 ;
        RECT  54.768 0 54.792 0.084 ;
    END
  END vr2q[433]
  PIN vr2q[434]
    DIRECTION OUTPUT ;
    USE SIGNAL ;
    PORT
      LAYER M3 ;
        RECT  54.864 0 54.882 0.038 ;
    END
  END vr2q[434]
  PIN vr2q[435]
    DIRECTION OUTPUT ;
    USE SIGNAL ;
    PORT
      LAYER M5 ;
        RECT  55.008 0 55.032 0.084 ;
    END
  END vr2q[435]
  PIN vr2q[436]
    DIRECTION OUTPUT ;
    USE SIGNAL ;
    PORT
      LAYER M3 ;
        RECT  55.116 0 55.134 0.038 ;
    END
  END vr2q[436]
  PIN vr2q[437]
    DIRECTION OUTPUT ;
    USE SIGNAL ;
    PORT
      LAYER M5 ;
        RECT  55.248 0 55.272 0.084 ;
    END
  END vr2q[437]
  PIN vr2q[438]
    DIRECTION OUTPUT ;
    USE SIGNAL ;
    PORT
      LAYER M3 ;
        RECT  55.368 0 55.386 0.038 ;
    END
  END vr2q[438]
  PIN vr2q[439]
    DIRECTION OUTPUT ;
    USE SIGNAL ;
    PORT
      LAYER M5 ;
        RECT  55.488 0 55.512 0.084 ;
    END
  END vr2q[439]
  PIN vr2q[43]
    DIRECTION OUTPUT ;
    USE SIGNAL ;
    PORT
      LAYER M5 ;
        RECT  5.472 0 5.496 0.084 ;
    END
  END vr2q[43]
  PIN vr2q[440]
    DIRECTION OUTPUT ;
    USE SIGNAL ;
    PORT
      LAYER M3 ;
        RECT  55.62 0 55.638 0.038 ;
    END
  END vr2q[440]
  PIN vr2q[441]
    DIRECTION OUTPUT ;
    USE SIGNAL ;
    PORT
      LAYER M5 ;
        RECT  55.776 0 55.8 0.084 ;
    END
  END vr2q[441]
  PIN vr2q[442]
    DIRECTION OUTPUT ;
    USE SIGNAL ;
    PORT
      LAYER M3 ;
        RECT  55.872 0 55.89 0.038 ;
    END
  END vr2q[442]
  PIN vr2q[443]
    DIRECTION OUTPUT ;
    USE SIGNAL ;
    PORT
      LAYER M5 ;
        RECT  56.016 0 56.04 0.084 ;
    END
  END vr2q[443]
  PIN vr2q[444]
    DIRECTION OUTPUT ;
    USE SIGNAL ;
    PORT
      LAYER M3 ;
        RECT  56.124 0 56.142 0.038 ;
    END
  END vr2q[444]
  PIN vr2q[445]
    DIRECTION OUTPUT ;
    USE SIGNAL ;
    PORT
      LAYER M5 ;
        RECT  56.256 0 56.28 0.084 ;
    END
  END vr2q[445]
  PIN vr2q[446]
    DIRECTION OUTPUT ;
    USE SIGNAL ;
    PORT
      LAYER M3 ;
        RECT  56.376 0 56.394 0.038 ;
    END
  END vr2q[446]
  PIN vr2q[447]
    DIRECTION OUTPUT ;
    USE SIGNAL ;
    PORT
      LAYER M5 ;
        RECT  56.496 0 56.52 0.084 ;
    END
  END vr2q[447]
  PIN vr2q[448]
    DIRECTION OUTPUT ;
    USE SIGNAL ;
    PORT
      LAYER M3 ;
        RECT  56.628 0 56.646 0.038 ;
    END
  END vr2q[448]
  PIN vr2q[449]
    DIRECTION OUTPUT ;
    USE SIGNAL ;
    PORT
      LAYER M5 ;
        RECT  56.784 0 56.808 0.084 ;
    END
  END vr2q[449]
  PIN vr2q[44]
    DIRECTION OUTPUT ;
    USE SIGNAL ;
    PORT
      LAYER M3 ;
        RECT  5.616 0 5.634 0.038 ;
    END
  END vr2q[44]
  PIN vr2q[450]
    DIRECTION OUTPUT ;
    USE SIGNAL ;
    PORT
      LAYER M3 ;
        RECT  56.88 0 56.898 0.038 ;
    END
  END vr2q[450]
  PIN vr2q[451]
    DIRECTION OUTPUT ;
    USE SIGNAL ;
    PORT
      LAYER M5 ;
        RECT  57.024 0 57.048 0.084 ;
    END
  END vr2q[451]
  PIN vr2q[452]
    DIRECTION OUTPUT ;
    USE SIGNAL ;
    PORT
      LAYER M3 ;
        RECT  57.132 0 57.15 0.038 ;
    END
  END vr2q[452]
  PIN vr2q[453]
    DIRECTION OUTPUT ;
    USE SIGNAL ;
    PORT
      LAYER M5 ;
        RECT  57.264 0 57.288 0.084 ;
    END
  END vr2q[453]
  PIN vr2q[454]
    DIRECTION OUTPUT ;
    USE SIGNAL ;
    PORT
      LAYER M3 ;
        RECT  57.42 0 57.438 0.038 ;
    END
  END vr2q[454]
  PIN vr2q[455]
    DIRECTION OUTPUT ;
    USE SIGNAL ;
    PORT
      LAYER M5 ;
        RECT  57.504 0 57.528 0.084 ;
    END
  END vr2q[455]
  PIN vr2q[456]
    DIRECTION OUTPUT ;
    USE SIGNAL ;
    PORT
      LAYER M3 ;
        RECT  57.672 0 57.69 0.038 ;
    END
  END vr2q[456]
  PIN vr2q[457]
    DIRECTION OUTPUT ;
    USE SIGNAL ;
    PORT
      LAYER M5 ;
        RECT  57.792 0 57.816 0.084 ;
    END
  END vr2q[457]
  PIN vr2q[458]
    DIRECTION OUTPUT ;
    USE SIGNAL ;
    PORT
      LAYER M3 ;
        RECT  57.924 0 57.942 0.038 ;
    END
  END vr2q[458]
  PIN vr2q[459]
    DIRECTION OUTPUT ;
    USE SIGNAL ;
    PORT
      LAYER M5 ;
        RECT  58.032 0 58.056 0.084 ;
    END
  END vr2q[459]
  PIN vr2q[45]
    DIRECTION OUTPUT ;
    USE SIGNAL ;
    PORT
      LAYER M5 ;
        RECT  5.712 0 5.736 0.084 ;
    END
  END vr2q[45]
  PIN vr2q[460]
    DIRECTION OUTPUT ;
    USE SIGNAL ;
    PORT
      LAYER M3 ;
        RECT  58.176 0 58.194 0.038 ;
    END
  END vr2q[460]
  PIN vr2q[461]
    DIRECTION OUTPUT ;
    USE SIGNAL ;
    PORT
      LAYER M5 ;
        RECT  58.272 0 58.296 0.084 ;
    END
  END vr2q[461]
  PIN vr2q[462]
    DIRECTION OUTPUT ;
    USE SIGNAL ;
    PORT
      LAYER M3 ;
        RECT  58.428 0 58.446 0.038 ;
    END
  END vr2q[462]
  PIN vr2q[463]
    DIRECTION OUTPUT ;
    USE SIGNAL ;
    PORT
      LAYER M5 ;
        RECT  58.512 0 58.536 0.084 ;
    END
  END vr2q[463]
  PIN vr2q[464]
    DIRECTION OUTPUT ;
    USE SIGNAL ;
    PORT
      LAYER M3 ;
        RECT  58.68 0 58.698 0.038 ;
    END
  END vr2q[464]
  PIN vr2q[465]
    DIRECTION OUTPUT ;
    USE SIGNAL ;
    PORT
      LAYER M5 ;
        RECT  58.8 0 58.824 0.084 ;
    END
  END vr2q[465]
  PIN vr2q[466]
    DIRECTION OUTPUT ;
    USE SIGNAL ;
    PORT
      LAYER M3 ;
        RECT  58.932 0 58.95 0.038 ;
    END
  END vr2q[466]
  PIN vr2q[467]
    DIRECTION OUTPUT ;
    USE SIGNAL ;
    PORT
      LAYER M5 ;
        RECT  59.04 0 59.064 0.084 ;
    END
  END vr2q[467]
  PIN vr2q[468]
    DIRECTION OUTPUT ;
    USE SIGNAL ;
    PORT
      LAYER M3 ;
        RECT  59.184 0 59.202 0.038 ;
    END
  END vr2q[468]
  PIN vr2q[469]
    DIRECTION OUTPUT ;
    USE SIGNAL ;
    PORT
      LAYER M5 ;
        RECT  59.28 0 59.304 0.084 ;
    END
  END vr2q[469]
  PIN vr2q[46]
    DIRECTION OUTPUT ;
    USE SIGNAL ;
    PORT
      LAYER M3 ;
        RECT  5.868 0 5.886 0.038 ;
    END
  END vr2q[46]
  PIN vr2q[470]
    DIRECTION OUTPUT ;
    USE SIGNAL ;
    PORT
      LAYER M3 ;
        RECT  59.436 0 59.454 0.038 ;
    END
  END vr2q[470]
  PIN vr2q[471]
    DIRECTION OUTPUT ;
    USE SIGNAL ;
    PORT
      LAYER M5 ;
        RECT  59.568 0 59.592 0.084 ;
    END
  END vr2q[471]
  PIN vr2q[472]
    DIRECTION OUTPUT ;
    USE SIGNAL ;
    PORT
      LAYER M3 ;
        RECT  59.688 0 59.706 0.038 ;
    END
  END vr2q[472]
  PIN vr2q[473]
    DIRECTION OUTPUT ;
    USE SIGNAL ;
    PORT
      LAYER M5 ;
        RECT  59.808 0 59.832 0.084 ;
    END
  END vr2q[473]
  PIN vr2q[474]
    DIRECTION OUTPUT ;
    USE SIGNAL ;
    PORT
      LAYER M3 ;
        RECT  59.94 0 59.958 0.038 ;
    END
  END vr2q[474]
  PIN vr2q[475]
    DIRECTION OUTPUT ;
    USE SIGNAL ;
    PORT
      LAYER M5 ;
        RECT  60.048 0 60.072 0.084 ;
    END
  END vr2q[475]
  PIN vr2q[476]
    DIRECTION OUTPUT ;
    USE SIGNAL ;
    PORT
      LAYER M3 ;
        RECT  60.192 0 60.21 0.038 ;
    END
  END vr2q[476]
  PIN vr2q[477]
    DIRECTION OUTPUT ;
    USE SIGNAL ;
    PORT
      LAYER M5 ;
        RECT  60.288 0 60.312 0.084 ;
    END
  END vr2q[477]
  PIN vr2q[478]
    DIRECTION OUTPUT ;
    USE SIGNAL ;
    PORT
      LAYER M3 ;
        RECT  60.444 0 60.462 0.038 ;
    END
  END vr2q[478]
  PIN vr2q[479]
    DIRECTION OUTPUT ;
    USE SIGNAL ;
    PORT
      LAYER M5 ;
        RECT  60.576 0 60.6 0.084 ;
    END
  END vr2q[479]
  PIN vr2q[47]
    DIRECTION OUTPUT ;
    USE SIGNAL ;
    PORT
      LAYER M5 ;
        RECT  6 0 6.024 0.084 ;
    END
  END vr2q[47]
  PIN vr2q[480]
    DIRECTION OUTPUT ;
    USE SIGNAL ;
    PORT
      LAYER M3 ;
        RECT  60.696 0 60.714 0.038 ;
    END
  END vr2q[480]
  PIN vr2q[481]
    DIRECTION OUTPUT ;
    USE SIGNAL ;
    PORT
      LAYER M5 ;
        RECT  60.816 0 60.84 0.084 ;
    END
  END vr2q[481]
  PIN vr2q[482]
    DIRECTION OUTPUT ;
    USE SIGNAL ;
    PORT
      LAYER M3 ;
        RECT  60.948 0 60.966 0.038 ;
    END
  END vr2q[482]
  PIN vr2q[483]
    DIRECTION OUTPUT ;
    USE SIGNAL ;
    PORT
      LAYER M5 ;
        RECT  61.056 0 61.08 0.084 ;
    END
  END vr2q[483]
  PIN vr2q[484]
    DIRECTION OUTPUT ;
    USE SIGNAL ;
    PORT
      LAYER M3 ;
        RECT  61.2 0 61.218 0.038 ;
    END
  END vr2q[484]
  PIN vr2q[485]
    DIRECTION OUTPUT ;
    USE SIGNAL ;
    PORT
      LAYER M5 ;
        RECT  61.296 0 61.32 0.084 ;
    END
  END vr2q[485]
  PIN vr2q[486]
    DIRECTION OUTPUT ;
    USE SIGNAL ;
    PORT
      LAYER M3 ;
        RECT  61.452 0 61.47 0.038 ;
    END
  END vr2q[486]
  PIN vr2q[487]
    DIRECTION OUTPUT ;
    USE SIGNAL ;
    PORT
      LAYER M5 ;
        RECT  61.584 0 61.608 0.084 ;
    END
  END vr2q[487]
  PIN vr2q[488]
    DIRECTION OUTPUT ;
    USE SIGNAL ;
    PORT
      LAYER M3 ;
        RECT  61.704 0 61.722 0.038 ;
    END
  END vr2q[488]
  PIN vr2q[489]
    DIRECTION OUTPUT ;
    USE SIGNAL ;
    PORT
      LAYER M5 ;
        RECT  61.824 0 61.848 0.084 ;
    END
  END vr2q[489]
  PIN vr2q[48]
    DIRECTION OUTPUT ;
    USE SIGNAL ;
    PORT
      LAYER M3 ;
        RECT  6.12 0 6.138 0.038 ;
    END
  END vr2q[48]
  PIN vr2q[490]
    DIRECTION OUTPUT ;
    USE SIGNAL ;
    PORT
      LAYER M3 ;
        RECT  61.956 0 61.974 0.038 ;
    END
  END vr2q[490]
  PIN vr2q[491]
    DIRECTION OUTPUT ;
    USE SIGNAL ;
    PORT
      LAYER M5 ;
        RECT  62.064 0 62.088 0.084 ;
    END
  END vr2q[491]
  PIN vr2q[492]
    DIRECTION OUTPUT ;
    USE SIGNAL ;
    PORT
      LAYER M3 ;
        RECT  62.208 0 62.226 0.038 ;
    END
  END vr2q[492]
  PIN vr2q[493]
    DIRECTION OUTPUT ;
    USE SIGNAL ;
    PORT
      LAYER M5 ;
        RECT  62.304 0 62.328 0.084 ;
    END
  END vr2q[493]
  PIN vr2q[494]
    DIRECTION OUTPUT ;
    USE SIGNAL ;
    PORT
      LAYER M3 ;
        RECT  62.46 0 62.478 0.038 ;
    END
  END vr2q[494]
  PIN vr2q[495]
    DIRECTION OUTPUT ;
    USE SIGNAL ;
    PORT
      LAYER M5 ;
        RECT  62.592 0 62.616 0.084 ;
    END
  END vr2q[495]
  PIN vr2q[496]
    DIRECTION OUTPUT ;
    USE SIGNAL ;
    PORT
      LAYER M3 ;
        RECT  62.712 0 62.73 0.038 ;
    END
  END vr2q[496]
  PIN vr2q[497]
    DIRECTION OUTPUT ;
    USE SIGNAL ;
    PORT
      LAYER M5 ;
        RECT  62.832 0 62.856 0.084 ;
    END
  END vr2q[497]
  PIN vr2q[498]
    DIRECTION OUTPUT ;
    USE SIGNAL ;
    PORT
      LAYER M3 ;
        RECT  62.964 0 62.982 0.038 ;
    END
  END vr2q[498]
  PIN vr2q[499]
    DIRECTION OUTPUT ;
    USE SIGNAL ;
    PORT
      LAYER M5 ;
        RECT  63.072 0 63.096 0.084 ;
    END
  END vr2q[499]
  PIN vr2q[49]
    DIRECTION OUTPUT ;
    USE SIGNAL ;
    PORT
      LAYER M5 ;
        RECT  6.24 0 6.264 0.084 ;
    END
  END vr2q[49]
  PIN vr2q[4]
    DIRECTION OUTPUT ;
    USE SIGNAL ;
    PORT
      LAYER M3 ;
        RECT  0.576 0 0.594 0.038 ;
    END
  END vr2q[4]
  PIN vr2q[500]
    DIRECTION OUTPUT ;
    USE SIGNAL ;
    PORT
      LAYER M3 ;
        RECT  63.216 0 63.234 0.038 ;
    END
  END vr2q[500]
  PIN vr2q[501]
    DIRECTION OUTPUT ;
    USE SIGNAL ;
    PORT
      LAYER M5 ;
        RECT  63.312 0 63.336 0.084 ;
    END
  END vr2q[501]
  PIN vr2q[502]
    DIRECTION OUTPUT ;
    USE SIGNAL ;
    PORT
      LAYER M3 ;
        RECT  63.468 0 63.486 0.038 ;
    END
  END vr2q[502]
  PIN vr2q[503]
    DIRECTION OUTPUT ;
    USE SIGNAL ;
    PORT
      LAYER M5 ;
        RECT  63.6 0 63.624 0.084 ;
    END
  END vr2q[503]
  PIN vr2q[504]
    DIRECTION OUTPUT ;
    USE SIGNAL ;
    PORT
      LAYER M3 ;
        RECT  63.72 0 63.738 0.038 ;
    END
  END vr2q[504]
  PIN vr2q[505]
    DIRECTION OUTPUT ;
    USE SIGNAL ;
    PORT
      LAYER M5 ;
        RECT  63.84 0 63.864 0.084 ;
    END
  END vr2q[505]
  PIN vr2q[506]
    DIRECTION OUTPUT ;
    USE SIGNAL ;
    PORT
      LAYER M3 ;
        RECT  63.972 0 63.99 0.038 ;
    END
  END vr2q[506]
  PIN vr2q[507]
    DIRECTION OUTPUT ;
    USE SIGNAL ;
    PORT
      LAYER M5 ;
        RECT  64.08 0 64.104 0.084 ;
    END
  END vr2q[507]
  PIN vr2q[508]
    DIRECTION OUTPUT ;
    USE SIGNAL ;
    PORT
      LAYER M3 ;
        RECT  64.224 0 64.242 0.038 ;
    END
  END vr2q[508]
  PIN vr2q[509]
    DIRECTION OUTPUT ;
    USE SIGNAL ;
    PORT
      LAYER M5 ;
        RECT  64.368 0 64.392 0.084 ;
    END
  END vr2q[509]
  PIN vr2q[50]
    DIRECTION OUTPUT ;
    USE SIGNAL ;
    PORT
      LAYER M3 ;
        RECT  6.372 0 6.39 0.038 ;
    END
  END vr2q[50]
  PIN vr2q[510]
    DIRECTION OUTPUT ;
    USE SIGNAL ;
    PORT
      LAYER M3 ;
        RECT  64.476 0 64.494 0.038 ;
    END
  END vr2q[510]
  PIN vr2q[511]
    DIRECTION OUTPUT ;
    USE SIGNAL ;
    PORT
      LAYER M5 ;
        RECT  64.608 0 64.632 0.084 ;
    END
  END vr2q[511]
  PIN vr2q[512]
    DIRECTION OUTPUT ;
    USE SIGNAL ;
    PORT
      LAYER M3 ;
        RECT  64.728 0 64.746 0.038 ;
    END
  END vr2q[512]
  PIN vr2q[51]
    DIRECTION OUTPUT ;
    USE SIGNAL ;
    PORT
      LAYER M5 ;
        RECT  6.48 0 6.504 0.084 ;
    END
  END vr2q[51]
  PIN vr2q[52]
    DIRECTION OUTPUT ;
    USE SIGNAL ;
    PORT
      LAYER M3 ;
        RECT  6.624 0 6.642 0.038 ;
    END
  END vr2q[52]
  PIN vr2q[53]
    DIRECTION OUTPUT ;
    USE SIGNAL ;
    PORT
      LAYER M5 ;
        RECT  6.768 0 6.792 0.084 ;
    END
  END vr2q[53]
  PIN vr2q[54]
    DIRECTION OUTPUT ;
    USE SIGNAL ;
    PORT
      LAYER M3 ;
        RECT  6.876 0 6.894 0.038 ;
    END
  END vr2q[54]
  PIN vr2q[55]
    DIRECTION OUTPUT ;
    USE SIGNAL ;
    PORT
      LAYER M5 ;
        RECT  7.008 0 7.032 0.084 ;
    END
  END vr2q[55]
  PIN vr2q[56]
    DIRECTION OUTPUT ;
    USE SIGNAL ;
    PORT
      LAYER M3 ;
        RECT  7.128 0 7.146 0.038 ;
    END
  END vr2q[56]
  PIN vr2q[57]
    DIRECTION OUTPUT ;
    USE SIGNAL ;
    PORT
      LAYER M5 ;
        RECT  7.248 0 7.272 0.084 ;
    END
  END vr2q[57]
  PIN vr2q[58]
    DIRECTION OUTPUT ;
    USE SIGNAL ;
    PORT
      LAYER M3 ;
        RECT  7.38 0 7.398 0.038 ;
    END
  END vr2q[58]
  PIN vr2q[59]
    DIRECTION OUTPUT ;
    USE SIGNAL ;
    PORT
      LAYER M5 ;
        RECT  7.488 0 7.512 0.084 ;
    END
  END vr2q[59]
  PIN vr2q[5]
    DIRECTION OUTPUT ;
    USE SIGNAL ;
    PORT
      LAYER M5 ;
        RECT  0.672 0 0.696 0.084 ;
    END
  END vr2q[5]
  PIN vr2q[60]
    DIRECTION OUTPUT ;
    USE SIGNAL ;
    PORT
      LAYER M3 ;
        RECT  7.632 0 7.65 0.038 ;
    END
  END vr2q[60]
  PIN vr2q[61]
    DIRECTION OUTPUT ;
    USE SIGNAL ;
    PORT
      LAYER M5 ;
        RECT  7.776 0 7.8 0.084 ;
    END
  END vr2q[61]
  PIN vr2q[62]
    DIRECTION OUTPUT ;
    USE SIGNAL ;
    PORT
      LAYER M3 ;
        RECT  7.884 0 7.902 0.038 ;
    END
  END vr2q[62]
  PIN vr2q[63]
    DIRECTION OUTPUT ;
    USE SIGNAL ;
    PORT
      LAYER M5 ;
        RECT  8.016 0 8.04 0.084 ;
    END
  END vr2q[63]
  PIN vr2q[64]
    DIRECTION OUTPUT ;
    USE SIGNAL ;
    PORT
      LAYER M3 ;
        RECT  8.136 0 8.154 0.038 ;
    END
  END vr2q[64]
  PIN vr2q[65]
    DIRECTION OUTPUT ;
    USE SIGNAL ;
    PORT
      LAYER M5 ;
        RECT  8.256 0 8.28 0.084 ;
    END
  END vr2q[65]
  PIN vr2q[66]
    DIRECTION OUTPUT ;
    USE SIGNAL ;
    PORT
      LAYER M3 ;
        RECT  8.388 0 8.406 0.038 ;
    END
  END vr2q[66]
  PIN vr2q[67]
    DIRECTION OUTPUT ;
    USE SIGNAL ;
    PORT
      LAYER M5 ;
        RECT  8.496 0 8.52 0.084 ;
    END
  END vr2q[67]
  PIN vr2q[68]
    DIRECTION OUTPUT ;
    USE SIGNAL ;
    PORT
      LAYER M3 ;
        RECT  8.64 0 8.658 0.038 ;
    END
  END vr2q[68]
  PIN vr2q[69]
    DIRECTION OUTPUT ;
    USE SIGNAL ;
    PORT
      LAYER M5 ;
        RECT  8.784 0 8.808 0.084 ;
    END
  END vr2q[69]
  PIN vr2q[6]
    DIRECTION OUTPUT ;
    USE SIGNAL ;
    PORT
      LAYER M3 ;
        RECT  0.828 0 0.846 0.038 ;
    END
  END vr2q[6]
  PIN vr2q[70]
    DIRECTION OUTPUT ;
    USE SIGNAL ;
    PORT
      LAYER M3 ;
        RECT  8.892 0 8.91 0.038 ;
    END
  END vr2q[70]
  PIN vr2q[71]
    DIRECTION OUTPUT ;
    USE SIGNAL ;
    PORT
      LAYER M5 ;
        RECT  9.024 0 9.048 0.084 ;
    END
  END vr2q[71]
  PIN vr2q[72]
    DIRECTION OUTPUT ;
    USE SIGNAL ;
    PORT
      LAYER M3 ;
        RECT  9.144 0 9.162 0.038 ;
    END
  END vr2q[72]
  PIN vr2q[73]
    DIRECTION OUTPUT ;
    USE SIGNAL ;
    PORT
      LAYER M5 ;
        RECT  9.264 0 9.288 0.084 ;
    END
  END vr2q[73]
  PIN vr2q[74]
    DIRECTION OUTPUT ;
    USE SIGNAL ;
    PORT
      LAYER M3 ;
        RECT  9.396 0 9.414 0.038 ;
    END
  END vr2q[74]
  PIN vr2q[75]
    DIRECTION OUTPUT ;
    USE SIGNAL ;
    PORT
      LAYER M5 ;
        RECT  9.504 0 9.528 0.084 ;
    END
  END vr2q[75]
  PIN vr2q[76]
    DIRECTION OUTPUT ;
    USE SIGNAL ;
    PORT
      LAYER M3 ;
        RECT  9.648 0 9.666 0.038 ;
    END
  END vr2q[76]
  PIN vr2q[77]
    DIRECTION OUTPUT ;
    USE SIGNAL ;
    PORT
      LAYER M5 ;
        RECT  9.792 0 9.816 0.084 ;
    END
  END vr2q[77]
  PIN vr2q[78]
    DIRECTION OUTPUT ;
    USE SIGNAL ;
    PORT
      LAYER M3 ;
        RECT  9.9 0 9.918 0.038 ;
    END
  END vr2q[78]
  PIN vr2q[79]
    DIRECTION OUTPUT ;
    USE SIGNAL ;
    PORT
      LAYER M5 ;
        RECT  10.032 0 10.056 0.084 ;
    END
  END vr2q[79]
  PIN vr2q[7]
    DIRECTION OUTPUT ;
    USE SIGNAL ;
    PORT
      LAYER M5 ;
        RECT  0.912 0 0.936 0.084 ;
    END
  END vr2q[7]
  PIN vr2q[80]
    DIRECTION OUTPUT ;
    USE SIGNAL ;
    PORT
      LAYER M3 ;
        RECT  10.152 0 10.17 0.038 ;
    END
  END vr2q[80]
  PIN vr2q[81]
    DIRECTION OUTPUT ;
    USE SIGNAL ;
    PORT
      LAYER M5 ;
        RECT  10.272 0 10.296 0.084 ;
    END
  END vr2q[81]
  PIN vr2q[82]
    DIRECTION OUTPUT ;
    USE SIGNAL ;
    PORT
      LAYER M3 ;
        RECT  10.404 0 10.422 0.038 ;
    END
  END vr2q[82]
  PIN vr2q[83]
    DIRECTION OUTPUT ;
    USE SIGNAL ;
    PORT
      LAYER M5 ;
        RECT  10.512 0 10.536 0.084 ;
    END
  END vr2q[83]
  PIN vr2q[84]
    DIRECTION OUTPUT ;
    USE SIGNAL ;
    PORT
      LAYER M3 ;
        RECT  10.656 0 10.674 0.038 ;
    END
  END vr2q[84]
  PIN vr2q[85]
    DIRECTION OUTPUT ;
    USE SIGNAL ;
    PORT
      LAYER M5 ;
        RECT  10.8 0 10.824 0.084 ;
    END
  END vr2q[85]
  PIN vr2q[86]
    DIRECTION OUTPUT ;
    USE SIGNAL ;
    PORT
      LAYER M3 ;
        RECT  10.908 0 10.926 0.038 ;
    END
  END vr2q[86]
  PIN vr2q[87]
    DIRECTION OUTPUT ;
    USE SIGNAL ;
    PORT
      LAYER M5 ;
        RECT  11.04 0 11.064 0.084 ;
    END
  END vr2q[87]
  PIN vr2q[88]
    DIRECTION OUTPUT ;
    USE SIGNAL ;
    PORT
      LAYER M3 ;
        RECT  11.16 0 11.178 0.038 ;
    END
  END vr2q[88]
  PIN vr2q[89]
    DIRECTION OUTPUT ;
    USE SIGNAL ;
    PORT
      LAYER M5 ;
        RECT  11.28 0 11.304 0.084 ;
    END
  END vr2q[89]
  PIN vr2q[8]
    DIRECTION OUTPUT ;
    USE SIGNAL ;
    PORT
      LAYER M3 ;
        RECT  1.08 0 1.098 0.038 ;
    END
  END vr2q[8]
  PIN vr2q[90]
    DIRECTION OUTPUT ;
    USE SIGNAL ;
    PORT
      LAYER M3 ;
        RECT  11.412 0 11.43 0.038 ;
    END
  END vr2q[90]
  PIN vr2q[91]
    DIRECTION OUTPUT ;
    USE SIGNAL ;
    PORT
      LAYER M5 ;
        RECT  11.568 0 11.592 0.084 ;
    END
  END vr2q[91]
  PIN vr2q[92]
    DIRECTION OUTPUT ;
    USE SIGNAL ;
    PORT
      LAYER M3 ;
        RECT  11.664 0 11.682 0.038 ;
    END
  END vr2q[92]
  PIN vr2q[93]
    DIRECTION OUTPUT ;
    USE SIGNAL ;
    PORT
      LAYER M5 ;
        RECT  11.808 0 11.832 0.084 ;
    END
  END vr2q[93]
  PIN vr2q[94]
    DIRECTION OUTPUT ;
    USE SIGNAL ;
    PORT
      LAYER M3 ;
        RECT  11.916 0 11.934 0.038 ;
    END
  END vr2q[94]
  PIN vr2q[95]
    DIRECTION OUTPUT ;
    USE SIGNAL ;
    PORT
      LAYER M5 ;
        RECT  12.048 0 12.072 0.084 ;
    END
  END vr2q[95]
  PIN vr2q[96]
    DIRECTION OUTPUT ;
    USE SIGNAL ;
    PORT
      LAYER M3 ;
        RECT  12.168 0 12.186 0.038 ;
    END
  END vr2q[96]
  PIN vr2q[97]
    DIRECTION OUTPUT ;
    USE SIGNAL ;
    PORT
      LAYER M5 ;
        RECT  12.288 0 12.312 0.084 ;
    END
  END vr2q[97]
  PIN vr2q[98]
    DIRECTION OUTPUT ;
    USE SIGNAL ;
    PORT
      LAYER M3 ;
        RECT  12.42 0 12.438 0.038 ;
    END
  END vr2q[98]
  PIN vr2q[99]
    DIRECTION OUTPUT ;
    USE SIGNAL ;
    PORT
      LAYER M5 ;
        RECT  12.576 0 12.6 0.084 ;
    END
  END vr2q[99]
  PIN vr2q[9]
    DIRECTION OUTPUT ;
    USE SIGNAL ;
    PORT
      LAYER M5 ;
        RECT  1.2 0 1.224 0.084 ;
    END
  END vr2q[9]
  PIN VDD
    DIRECTION INOUT ;
    USE POWER ;
    PORT
      LAYER M5 ;
        RECT  61.992 2.151 62.112 62.649 ;
        RECT  56.592 2.151 56.712 62.649 ;
        RECT  51.192 2.151 51.312 62.649 ;
        RECT  45.792 2.151 45.912 62.649 ;
        RECT  40.392 2.151 40.512 62.649 ;
        RECT  34.992 2.151 35.112 62.649 ;
        RECT  29.592 2.151 29.712 62.649 ;
        RECT  24.192 2.151 24.312 62.649 ;
        RECT  18.792 2.151 18.912 62.649 ;
        RECT  13.392 2.151 13.512 62.649 ;
        RECT  7.992 2.151 8.112 62.649 ;
        RECT  2.592 2.151 2.712 62.649 ;
    END
  END VDD
  PIN VSS
    DIRECTION INOUT ;
    USE GROUND ;
    PORT
      LAYER M5 ;
        RECT  61.8 2.137 61.92 62.663 ;
        RECT  56.4 2.137 56.52 62.663 ;
        RECT  51 2.137 51.12 62.663 ;
        RECT  45.6 2.137 45.72 62.663 ;
        RECT  40.2 2.137 40.32 62.663 ;
        RECT  34.8 2.137 34.92 62.663 ;
        RECT  29.4 2.137 29.52 62.663 ;
        RECT  24 2.137 24.12 62.663 ;
        RECT  18.6 2.137 18.72 62.663 ;
        RECT  13.2 2.137 13.32 62.663 ;
        RECT  7.8 2.137 7.92 62.663 ;
        RECT  2.4 2.137 2.52 62.663 ;
    END
  END VSS
  # OT_OBS_CLOSED layer=M5 d_um=1.536 added=186
  OBS
    LAYER RVTN ;
     RECT  2.16 2.16 62.64 2.295 ;
     RECT  2.16 2.565 62.64 2.835 ;
     RECT  2.16 3.105 62.64 3.375 ;
     RECT  2.16 3.645 62.64 3.915 ;
     RECT  2.16 4.185 62.64 4.455 ;
     RECT  2.16 4.725 62.64 4.995 ;
     RECT  2.16 5.265 62.64 5.535 ;
     RECT  2.16 5.805 62.64 6.075 ;
     RECT  2.16 6.345 62.64 6.615 ;
     RECT  2.16 6.885 62.64 7.155 ;
     RECT  2.16 7.425 62.64 7.695 ;
     RECT  2.16 7.965 62.64 8.235 ;
     RECT  2.16 8.505 62.64 8.775 ;
     RECT  2.16 9.045 62.64 9.315 ;
     RECT  2.16 9.585 62.64 9.855 ;
     RECT  2.16 10.125 62.64 10.395 ;
     RECT  2.16 10.665 62.64 10.935 ;
     RECT  2.16 11.205 62.64 11.475 ;
     RECT  2.16 11.745 62.64 12.015 ;
     RECT  2.16 12.285 62.64 12.555 ;
     RECT  2.16 12.825 62.64 13.095 ;
     RECT  2.16 13.365 62.64 13.635 ;
     RECT  2.16 13.905 62.64 14.175 ;
     RECT  2.16 14.445 62.64 14.715 ;
     RECT  2.16 14.985 62.64 15.255 ;
     RECT  2.16 15.525 62.64 15.795 ;
     RECT  2.16 16.065 62.64 16.335 ;
     RECT  2.16 16.605 62.64 16.875 ;
     RECT  2.16 17.145 62.64 17.415 ;
     RECT  2.16 17.685 62.64 17.955 ;
     RECT  2.16 18.225 62.64 18.495 ;
     RECT  2.16 18.765 62.64 19.035 ;
     RECT  2.16 19.305 62.64 19.575 ;
     RECT  2.16 19.845 62.64 20.115 ;
     RECT  2.16 20.385 62.64 20.655 ;
     RECT  2.16 20.925 62.64 21.195 ;
     RECT  2.16 21.465 62.64 21.735 ;
     RECT  2.16 22.005 62.64 22.275 ;
     RECT  2.16 22.545 62.64 22.815 ;
     RECT  2.16 23.085 62.64 23.355 ;
     RECT  2.16 23.625 62.64 23.895 ;
     RECT  2.16 24.165 62.64 24.435 ;
     RECT  2.16 24.705 62.64 24.975 ;
     RECT  2.16 25.245 62.64 25.515 ;
     RECT  2.16 25.785 62.64 26.055 ;
     RECT  2.16 26.325 62.64 26.595 ;
     RECT  2.16 26.865 62.64 27.135 ;
     RECT  2.16 27.405 62.64 27.675 ;
     RECT  2.16 27.945 62.64 28.215 ;
     RECT  2.16 28.485 62.64 28.755 ;
     RECT  2.16 29.025 62.64 29.295 ;
     RECT  2.16 29.565 62.64 29.835 ;
     RECT  2.16 30.105 62.64 30.375 ;
     RECT  2.16 30.645 62.64 30.915 ;
     RECT  2.16 31.185 62.64 31.455 ;
     RECT  2.16 31.725 62.64 31.995 ;
     RECT  2.16 32.265 62.64 32.535 ;
     RECT  2.16 32.805 62.64 33.075 ;
     RECT  2.16 33.345 62.64 33.615 ;
     RECT  2.16 33.885 62.64 34.155 ;
     RECT  2.16 34.425 62.64 34.695 ;
     RECT  2.16 34.965 62.64 35.235 ;
     RECT  2.16 35.505 62.64 35.775 ;
     RECT  2.16 36.045 62.64 36.315 ;
     RECT  2.16 36.585 62.64 36.855 ;
     RECT  2.16 37.125 62.64 37.395 ;
     RECT  2.16 37.665 62.64 37.935 ;
     RECT  2.16 38.205 62.64 38.475 ;
     RECT  2.16 38.745 62.64 39.015 ;
     RECT  2.16 39.285 62.64 39.555 ;
     RECT  2.16 39.825 62.64 40.095 ;
     RECT  2.16 40.365 62.64 40.635 ;
     RECT  2.16 40.905 62.64 41.175 ;
     RECT  2.16 41.445 62.64 41.715 ;
     RECT  2.16 41.985 62.64 42.255 ;
     RECT  2.16 42.525 62.64 42.795 ;
     RECT  2.16 43.065 62.64 43.335 ;
     RECT  2.16 43.605 62.64 43.875 ;
     RECT  2.16 44.145 62.64 44.415 ;
     RECT  2.16 44.685 62.64 44.955 ;
     RECT  2.16 45.225 62.64 45.495 ;
     RECT  2.16 45.765 62.64 46.035 ;
     RECT  2.16 46.305 62.64 46.575 ;
     RECT  2.16 46.845 62.64 47.115 ;
     RECT  2.16 47.385 62.64 47.655 ;
     RECT  2.16 47.925 62.64 48.195 ;
     RECT  2.16 48.465 62.64 48.735 ;
     RECT  2.16 49.005 62.64 49.275 ;
     RECT  2.16 49.545 62.64 49.815 ;
     RECT  2.16 50.085 62.64 50.355 ;
     RECT  2.16 50.625 62.64 50.895 ;
     RECT  2.16 51.165 62.64 51.435 ;
     RECT  2.16 51.705 62.64 51.975 ;
     RECT  2.16 52.245 62.64 52.515 ;
     RECT  2.16 52.785 62.64 53.055 ;
     RECT  2.16 53.325 62.64 53.595 ;
     RECT  2.16 53.865 62.64 54.135 ;
     RECT  2.16 54.405 62.64 54.675 ;
     RECT  2.16 54.945 62.64 55.215 ;
     RECT  2.16 55.485 62.64 55.755 ;
     RECT  2.16 56.025 62.64 56.295 ;
     RECT  2.16 56.565 62.64 56.835 ;
     RECT  2.16 57.105 62.64 57.375 ;
     RECT  2.16 57.645 62.64 57.915 ;
     RECT  2.16 58.185 62.64 58.455 ;
     RECT  2.16 58.725 62.64 58.995 ;
     RECT  2.16 59.265 62.64 59.535 ;
     RECT  2.16 59.805 62.64 60.075 ;
     RECT  2.16 60.345 62.64 60.615 ;
     RECT  2.16 60.885 62.64 61.155 ;
     RECT  2.16 61.425 62.64 61.695 ;
     RECT  2.16 61.965 62.64 62.235 ;
     RECT  2.16 62.505 62.64 62.64 ;
    LAYER RVTP ;
     RECT  2.16 2.295 62.64 2.565 ;
     RECT  2.16 2.835 62.64 3.105 ;
     RECT  2.16 3.375 62.64 3.645 ;
     RECT  2.16 3.915 62.64 4.185 ;
     RECT  2.16 4.455 62.64 4.725 ;
     RECT  2.16 4.995 62.64 5.265 ;
     RECT  2.16 5.535 62.64 5.805 ;
     RECT  2.16 6.075 62.64 6.345 ;
     RECT  2.16 6.615 62.64 6.885 ;
     RECT  2.16 7.155 62.64 7.425 ;
     RECT  2.16 7.695 62.64 7.965 ;
     RECT  2.16 8.235 62.64 8.505 ;
     RECT  2.16 8.775 62.64 9.045 ;
     RECT  2.16 9.315 62.64 9.585 ;
     RECT  2.16 9.855 62.64 10.125 ;
     RECT  2.16 10.395 62.64 10.665 ;
     RECT  2.16 10.935 62.64 11.205 ;
     RECT  2.16 11.475 62.64 11.745 ;
     RECT  2.16 12.015 62.64 12.285 ;
     RECT  2.16 12.555 62.64 12.825 ;
     RECT  2.16 13.095 62.64 13.365 ;
     RECT  2.16 13.635 62.64 13.905 ;
     RECT  2.16 14.175 62.64 14.445 ;
     RECT  2.16 14.715 62.64 14.985 ;
     RECT  2.16 15.255 62.64 15.525 ;
     RECT  2.16 15.795 62.64 16.065 ;
     RECT  2.16 16.335 62.64 16.605 ;
     RECT  2.16 16.875 62.64 17.145 ;
     RECT  2.16 17.415 62.64 17.685 ;
     RECT  2.16 17.955 62.64 18.225 ;
     RECT  2.16 18.495 62.64 18.765 ;
     RECT  2.16 19.035 62.64 19.305 ;
     RECT  2.16 19.575 62.64 19.845 ;
     RECT  2.16 20.115 62.64 20.385 ;
     RECT  2.16 20.655 62.64 20.925 ;
     RECT  2.16 21.195 62.64 21.465 ;
     RECT  2.16 21.735 62.64 22.005 ;
     RECT  2.16 22.275 62.64 22.545 ;
     RECT  2.16 22.815 62.64 23.085 ;
     RECT  2.16 23.355 62.64 23.625 ;
     RECT  2.16 23.895 62.64 24.165 ;
     RECT  2.16 24.435 62.64 24.705 ;
     RECT  2.16 24.975 62.64 25.245 ;
     RECT  2.16 25.515 62.64 25.785 ;
     RECT  2.16 26.055 62.64 26.325 ;
     RECT  2.16 26.595 62.64 26.865 ;
     RECT  2.16 27.135 62.64 27.405 ;
     RECT  2.16 27.675 62.64 27.945 ;
     RECT  2.16 28.215 62.64 28.485 ;
     RECT  2.16 28.755 62.64 29.025 ;
     RECT  2.16 29.295 62.64 29.565 ;
     RECT  2.16 29.835 62.64 30.105 ;
     RECT  2.16 30.375 62.64 30.645 ;
     RECT  2.16 30.915 62.64 31.185 ;
     RECT  2.16 31.455 62.64 31.725 ;
     RECT  2.16 31.995 62.64 32.265 ;
     RECT  2.16 32.535 62.64 32.805 ;
     RECT  2.16 33.075 62.64 33.345 ;
     RECT  2.16 33.615 62.64 33.885 ;
     RECT  2.16 34.155 62.64 34.425 ;
     RECT  2.16 34.695 62.64 34.965 ;
     RECT  2.16 35.235 62.64 35.505 ;
     RECT  2.16 35.775 62.64 36.045 ;
     RECT  2.16 36.315 62.64 36.585 ;
     RECT  2.16 36.855 62.64 37.125 ;
     RECT  2.16 37.395 62.64 37.665 ;
     RECT  2.16 37.935 62.64 38.205 ;
     RECT  2.16 38.475 62.64 38.745 ;
     RECT  2.16 39.015 62.64 39.285 ;
     RECT  2.16 39.555 62.64 39.825 ;
     RECT  2.16 40.095 62.64 40.365 ;
     RECT  2.16 40.635 62.64 40.905 ;
     RECT  2.16 41.175 62.64 41.445 ;
     RECT  2.16 41.715 62.64 41.985 ;
     RECT  2.16 42.255 62.64 42.525 ;
     RECT  2.16 42.795 62.64 43.065 ;
     RECT  2.16 43.335 62.64 43.605 ;
     RECT  2.16 43.875 62.64 44.145 ;
     RECT  2.16 44.415 62.64 44.685 ;
     RECT  2.16 44.955 62.64 45.225 ;
     RECT  2.16 45.495 62.64 45.765 ;
     RECT  2.16 46.035 62.64 46.305 ;
     RECT  2.16 46.575 62.64 46.845 ;
     RECT  2.16 47.115 62.64 47.385 ;
     RECT  2.16 47.655 62.64 47.925 ;
     RECT  2.16 48.195 62.64 48.465 ;
     RECT  2.16 48.735 62.64 49.005 ;
     RECT  2.16 49.275 62.64 49.545 ;
     RECT  2.16 49.815 62.64 50.085 ;
     RECT  2.16 50.355 62.64 50.625 ;
     RECT  2.16 50.895 62.64 51.165 ;
     RECT  2.16 51.435 62.64 51.705 ;
     RECT  2.16 51.975 62.64 52.245 ;
     RECT  2.16 52.515 62.64 52.785 ;
     RECT  2.16 53.055 62.64 53.325 ;
     RECT  2.16 53.595 62.64 53.865 ;
     RECT  2.16 54.135 62.64 54.405 ;
     RECT  2.16 54.675 62.64 54.945 ;
     RECT  2.16 55.215 62.64 55.485 ;
     RECT  2.16 55.755 62.64 56.025 ;
     RECT  2.16 56.295 62.64 56.565 ;
     RECT  2.16 56.835 62.64 57.105 ;
     RECT  2.16 57.375 62.64 57.645 ;
     RECT  2.16 57.915 62.64 58.185 ;
     RECT  2.16 58.455 62.64 58.725 ;
     RECT  2.16 58.995 62.64 59.265 ;
     RECT  2.16 59.535 62.64 59.805 ;
     RECT  2.16 60.075 62.64 60.345 ;
     RECT  2.16 60.615 62.64 60.885 ;
     RECT  2.16 61.155 62.64 61.425 ;
     RECT  2.16 61.695 62.64 61.965 ;
     RECT  2.16 62.235 62.64 62.505 ;
    LAYER M1 ;
     RECT  2.16 2.151 62.64 62.649 ;
    LAYER M2 ;
     RECT  0.319 2.736 0.571 2.754 ;
     RECT  0.535 37.332 0.787 37.35 ;
     RECT  0.067 4.356 0.823 4.374 ;
     RECT  0.319 63.864 0.851 63.882 ;
     RECT  0.823 4.356 1.075 5.094 ;
     RECT  1.075 4.356 1.327 5.724 ;
     RECT  0.787 37.332 1.399 37.998 ;
     RECT  1.579 6.516 1.759 6.534 ;
     RECT  1.723 7.362 1.759 7.38 ;
     RECT  0.571 2.736 1.795 3.024 ;
     RECT  1.327 3.816 1.795 5.724 ;
     RECT  1.759 6.516 1.795 7.38 ;
     RECT  1.543 42.3 1.795 42.318 ;
     RECT  1.795 2.106 1.939 3.024 ;
     RECT  1.795 3.816 1.939 7.38 ;
     RECT  1.975 39.024 2.011 39.042 ;
     RECT  2.011 9.396 2.047 9.414 ;
     RECT  1.939 10.746 2.047 10.764 ;
     RECT  2.011 39.024 2.047 39.654 ;
     RECT  1.867 8.316 2.083 8.334 ;
     RECT  2.011 13.95 2.083 13.968 ;
     RECT  2.047 9.396 2.155 10.764 ;
     RECT  1.975 13.14 2.155 13.158 ;
     RECT  2.083 13.914 2.155 13.968 ;
     RECT  1.939 2.106 2.16 7.38 ;
     RECT  2.083 8.136 2.16 8.334 ;
     RECT  2.155 9.36 2.16 10.764 ;
     RECT  2.155 13.14 2.16 13.968 ;
     RECT  2.047 24.714 2.16 24.732 ;
     RECT  1.039 28.26 2.16 28.278 ;
     RECT  0.823 35.28 2.16 35.298 ;
     RECT  1.399 36.9 2.16 37.998 ;
     RECT  2.047 38.952 2.16 39.654 ;
     RECT  1.795 42.3 2.16 42.48 ;
     RECT  1.291 45.27 2.16 45.288 ;
     RECT  2.16 2.106 2.371 62.649 ;
     RECT  2.371 2.034 2.759 62.649 ;
     RECT  3.091 0.036 3.271 0.054 ;
     RECT  2.759 2.151 3.811 62.649 ;
     RECT  3.271 0.036 3.875 0.126 ;
     RECT  4.063 64.746 4.163 64.764 ;
     RECT  3.875 0.036 4.739 0.054 ;
     RECT  3.811 2.106 5.351 62.649 ;
     RECT  5.351 2.151 7.771 62.649 ;
     RECT  7.771 2.151 7.871 62.73 ;
     RECT  7.871 2.151 7.879 62.649 ;
     RECT  5.539 0.036 8.131 0.054 ;
     RECT  7.879 1.728 8.159 62.649 ;
     RECT  8.131 0.036 8.411 0.126 ;
     RECT  8.347 63.864 8.851 63.882 ;
     RECT  8.851 63.864 8.951 63.954 ;
     RECT  8.411 0.036 9.239 0.054 ;
     RECT  9.211 1.152 9.311 1.17 ;
     RECT  8.159 2.151 9.319 62.649 ;
     RECT  8.951 63.936 9.355 63.954 ;
     RECT  9.355 63.936 9.383 64.044 ;
     RECT  9.383 64.026 9.491 64.044 ;
     RECT  9.319 2.106 10.283 62.649 ;
     RECT  10.075 1.152 10.499 1.17 ;
     RECT  11.155 0.036 11.507 0.054 ;
     RECT  10.283 2.151 11.911 62.649 ;
     RECT  12.163 1.152 12.263 1.17 ;
     RECT  11.911 2.106 12.335 62.649 ;
     RECT  12.415 0.036 12.515 0.054 ;
     RECT  13.675 0.036 14.611 0.054 ;
     RECT  14.611 0.036 14.647 1.278 ;
     RECT  14.647 0.036 14.783 1.359 ;
     RECT  14.783 0.036 15.251 0.054 ;
     RECT  15.907 64.638 16.043 64.656 ;
     RECT  15.655 1.152 16.079 1.17 ;
     RECT  12.335 2.151 17.239 62.649 ;
     RECT  17.239 2.106 18.383 62.649 ;
     RECT  17.239 0.036 18.599 0.054 ;
     RECT  18.383 2.151 18.679 62.649 ;
     RECT  18.679 2.151 18.779 62.73 ;
     RECT  20.011 0.036 20.363 0.054 ;
     RECT  18.779 2.151 21.667 62.649 ;
     RECT  21.667 2.106 21.703 62.649 ;
     RECT  21.703 1.692 21.839 62.649 ;
     RECT  21.839 2.106 23.171 62.649 ;
     RECT  21.523 0.036 24.503 0.054 ;
     RECT  24.727 64.674 24.863 64.692 ;
     RECT  23.171 2.151 25.663 62.649 ;
     RECT  25.447 0.036 26.015 0.054 ;
     RECT  25.663 2.106 26.195 62.649 ;
     RECT  26.707 64.674 26.843 64.692 ;
     RECT  27.067 0.036 27.167 0.054 ;
     RECT  28.075 0.036 28.175 0.054 ;
     RECT  26.195 2.151 28.327 62.649 ;
     RECT  28.327 2.106 29.003 62.649 ;
     RECT  29.299 0.036 29.371 0.054 ;
     RECT  29.003 2.151 29.371 62.649 ;
     RECT  29.371 0.036 29.399 0.198 ;
     RECT  29.371 2.151 29.507 62.73 ;
     RECT  29.399 0.18 29.651 0.198 ;
     RECT  29.731 63.864 29.831 63.882 ;
     RECT  30.739 64.521 30.875 64.539 ;
     RECT  31.135 0.036 31.487 0.054 ;
     RECT  29.507 2.151 31.891 62.649 ;
     RECT  32.503 64.674 32.639 64.692 ;
     RECT  31.891 1.728 33.971 62.649 ;
     RECT  33.979 1.152 34.115 1.17 ;
     RECT  33.403 0.036 34.187 0.054 ;
     RECT  34.915 1.152 35.267 1.17 ;
     RECT  35.275 63.864 35.375 63.882 ;
     RECT  35.167 0.036 36.715 0.054 ;
     RECT  33.971 2.151 36.751 62.649 ;
     RECT  36.715 0.036 36.959 0.126 ;
     RECT  36.751 2.106 37.183 62.649 ;
     RECT  36.959 0.036 37.463 0.054 ;
     RECT  37.183 1.728 37.607 62.649 ;
     RECT  37.795 64.674 37.931 64.692 ;
     RECT  37.607 2.151 39.379 62.649 ;
     RECT  39.379 2.106 39.911 62.649 ;
     RECT  39.911 2.151 40.315 62.649 ;
     RECT  40.315 2.151 40.451 62.73 ;
     RECT  40.451 2.151 40.927 62.649 ;
     RECT  40.927 2.106 40.963 62.649 ;
     RECT  40.963 1.728 41.063 62.649 ;
     RECT  40.063 0.036 41.243 0.054 ;
     RECT  41.827 64.674 41.963 64.692 ;
     RECT  42.475 0.036 42.575 0.054 ;
     RECT  41.063 2.106 42.863 62.649 ;
     RECT  42.863 2.151 44.275 62.649 ;
     RECT  44.275 1.728 44.519 62.649 ;
     RECT  44.023 0.036 44.879 0.054 ;
     RECT  44.519 2.151 45.607 62.649 ;
     RECT  45.607 2.151 45.779 62.73 ;
     RECT  45.779 2.151 46.039 62.649 ;
     RECT  46.111 64.638 46.247 64.656 ;
     RECT  46.255 0.108 46.291 0.126 ;
     RECT  46.291 0.036 46.499 0.126 ;
     RECT  46.499 0.108 46.571 0.126 ;
     RECT  46.039 2.106 46.795 62.649 ;
     RECT  47.299 0.108 47.551 0.126 ;
     RECT  47.551 0.036 47.579 0.126 ;
     RECT  46.795 1.728 48.119 62.649 ;
     RECT  47.579 0.036 48.443 0.054 ;
     RECT  48.119 2.106 48.551 62.649 ;
     RECT  49.459 0.036 49.595 0.054 ;
     RECT  50.791 0.108 50.827 0.126 ;
     RECT  50.827 0.036 51.107 0.126 ;
     RECT  51.107 0.036 52.367 0.054 ;
     RECT  53.095 0.036 53.195 0.054 ;
     RECT  48.551 2.151 53.959 62.649 ;
     RECT  53.959 2.106 54.103 62.649 ;
     RECT  54.103 1.728 54.455 62.649 ;
     RECT  54.455 1.8 54.491 62.649 ;
     RECT  54.491 2.106 55.067 62.649 ;
     RECT  55.067 2.151 55.399 62.649 ;
     RECT  55.399 2.151 55.535 62.73 ;
     RECT  55.535 2.151 56.119 62.649 ;
     RECT  56.119 1.728 56.255 62.649 ;
     RECT  55.867 0.036 56.867 0.054 ;
     RECT  56.255 2.151 57.127 62.649 ;
     RECT  57.127 2.106 57.919 62.649 ;
     RECT  57.919 1.728 58.055 62.649 ;
     RECT  59.935 64.746 60.971 64.764 ;
     RECT  58.055 2.151 61.159 62.649 ;
     RECT  61.159 2.151 61.555 62.694 ;
     RECT  57.667 0.036 61.979 0.054 ;
     RECT  61.663 1.152 62.519 1.17 ;
     RECT  61.555 2.106 62.64 62.694 ;
     RECT  62.64 2.106 62.699 21.69 ;
     RECT  62.64 46.314 62.699 62.694 ;
     RECT  62.699 21.402 62.735 21.42 ;
     RECT  62.707 0.036 62.843 0.054 ;
     RECT  62.64 38.718 62.987 39.51 ;
     RECT  62.699 2.106 63.095 20.106 ;
     RECT  63.095 2.196 63.275 20.106 ;
     RECT  62.64 22.59 63.275 37.926 ;
     RECT  62.64 40.716 63.275 43.056 ;
     RECT  62.64 43.956 63.275 45.45 ;
     RECT  62.699 46.314 63.275 48.15 ;
     RECT  63.275 16.002 63.311 20.106 ;
     RECT  63.275 22.59 63.311 22.77 ;
     RECT  63.275 42.966 63.311 42.984 ;
     RECT  62.699 49.212 63.347 62.694 ;
     RECT  63.275 2.376 63.491 15.21 ;
     RECT  63.491 2.376 63.527 5.634 ;
     RECT  63.499 1.152 63.599 1.17 ;
     RECT  63.527 5.238 63.743 5.634 ;
     RECT  63.311 16.002 63.851 17.982 ;
     RECT  63.275 23.706 63.851 37.926 ;
     RECT  63.275 40.716 63.851 41.814 ;
     RECT  63.347 49.212 63.851 61.524 ;
     RECT  63.491 6.39 63.887 15.21 ;
     RECT  63.851 16.92 63.887 17.982 ;
     RECT  63.851 23.706 63.887 23.724 ;
     RECT  63.851 24.75 63.887 29.016 ;
     RECT  63.851 29.808 63.887 29.934 ;
     RECT  63.851 30.96 63.887 36.612 ;
     RECT  63.851 37.476 63.887 37.926 ;
     RECT  63.275 44.622 63.887 45.45 ;
     RECT  63.851 52.956 63.887 55.818 ;
     RECT  63.851 56.61 63.887 57.906 ;
     RECT  63.887 30.96 63.923 32.526 ;
     RECT  63.887 16.92 63.959 17.208 ;
     RECT  63.851 59.121 63.959 59.139 ;
     RECT  63.851 61.011 63.959 61.524 ;
     RECT  63.527 2.376 63.995 4.248 ;
     RECT  63.347 62.676 63.995 62.694 ;
     RECT  63.959 61.011 64.031 61.218 ;
     RECT  63.995 3.276 64.247 4.248 ;
     RECT  63.275 46.314 64.399 46.332 ;
     RECT  63.887 45.162 64.471 45.45 ;
     RECT  64.399 46.242 64.471 46.332 ;
     RECT  63.995 2.376 64.499 2.484 ;
     RECT  63.887 6.39 64.535 8.064 ;
     RECT  63.743 5.508 64.543 5.634 ;
     RECT  64.471 45.162 64.543 46.332 ;
     RECT  63.275 47.088 64.543 47.106 ;
     RECT  64.247 3.456 64.571 4.248 ;
     RECT  64.543 45.162 64.571 47.106 ;
     RECT  64.571 46.242 64.607 47.106 ;
     RECT  63.887 9.09 64.615 15.012 ;
     RECT  64.607 46.548 64.615 47.106 ;
     RECT  63.851 50.436 64.615 52.038 ;
     RECT  64.543 5.508 64.643 5.679 ;
     RECT  64.535 6.426 64.643 8.064 ;
     RECT  63.311 18.846 64.643 20.106 ;
     RECT  64.615 50.058 64.643 52.038 ;
     RECT  64.643 5.508 64.651 5.634 ;
     RECT  64.571 3.69 64.679 4.014 ;
     RECT  64.643 6.624 64.679 8.064 ;
     RECT  64.615 8.856 64.679 15.012 ;
     RECT  63.887 24.786 64.679 27.936 ;
     RECT  63.923 30.96 64.679 32.292 ;
     RECT  63.887 34.938 64.679 36.612 ;
     RECT  64.543 44.388 64.679 44.406 ;
     RECT  64.615 46.548 64.679 47.844 ;
     RECT  64.031 61.092 64.679 61.218 ;
     RECT  64.651 5.166 64.715 5.634 ;
     RECT  64.679 7.128 64.715 7.794 ;
     RECT  64.679 8.856 64.715 13.464 ;
     RECT  64.679 14.22 64.715 14.94 ;
     RECT  63.959 16.92 64.715 17.1 ;
     RECT  63.887 17.964 64.715 17.982 ;
     RECT  64.643 19.242 64.715 20.106 ;
     RECT  63.311 22.59 64.715 22.608 ;
     RECT  64.679 24.786 64.715 27.774 ;
     RECT  63.887 28.764 64.715 29.016 ;
     RECT  63.887 29.808 64.715 29.826 ;
     RECT  64.679 30.96 64.715 30.978 ;
     RECT  64.679 31.734 64.715 32.292 ;
     RECT  64.679 34.938 64.715 34.956 ;
     RECT  64.679 35.748 64.715 36.612 ;
     RECT  63.887 37.908 64.715 37.926 ;
     RECT  62.987 38.952 64.715 39.51 ;
     RECT  63.851 40.716 64.715 41.4 ;
     RECT  64.571 45.162 64.715 45.45 ;
     RECT  64.679 47.088 64.715 47.844 ;
     RECT  64.643 50.058 64.715 50.076 ;
     RECT  64.643 51.138 64.715 52.038 ;
     RECT  63.887 53.676 64.715 55.818 ;
     RECT  63.887 56.61 64.715 57.789 ;
     RECT  64.679 61.092 64.715 61.11 ;
     RECT  64.679 3.996 64.751 4.014 ;
     RECT  64.715 5.166 64.751 5.184 ;
     RECT  64.715 11.79 64.751 11.808 ;
     RECT  64.615 64.332 64.751 64.35 ;
     RECT  64.499 2.466 64.787 2.484 ;
     RECT  64.715 9.171 64.787 9.189 ;
     RECT  64.715 57.771 64.787 57.789 ;
     RECT  64.687 62.28 64.787 62.298 ;
    LAYER M3 ;
     RECT  0.072 0.012 64.746 2.461 ;
     RECT  0.072 2.461 64.782 3.029 ;
     RECT  0.828 3.029 64.782 3.299 ;
     RECT  64.548 3.299 64.782 4.219 ;
     RECT  0.072 3.029 0.09 4.379 ;
     RECT  64.512 4.219 64.782 4.843 ;
     RECT  64.476 4.843 64.782 5.021 ;
     RECT  0.828 3.299 63.738 5.099 ;
     RECT  1.08 5.099 63.738 5.261 ;
     RECT  1.08 5.261 63.558 5.729 ;
     RECT  1.584 5.729 63.558 6.539 ;
     RECT  64.512 5.021 64.782 6.859 ;
     RECT  1.728 6.539 63.558 7.385 ;
     RECT  1.872 7.385 63.558 7.501 ;
     RECT  64.476 6.859 64.782 7.501 ;
     RECT  1.872 7.501 64.782 7.709 ;
     RECT  64.62 7.709 64.782 7.799 ;
     RECT  64.656 7.799 64.782 8.069 ;
     RECT  1.872 7.709 63.882 8.339 ;
     RECT  1.944 8.339 63.882 8.609 ;
     RECT  64.728 8.069 64.782 8.827 ;
     RECT  44.46 8.609 63.882 9.077 ;
     RECT  46.98 9.077 63.882 9.113 ;
     RECT  47.088 9.113 63.882 9.194 ;
     RECT  64.62 8.827 64.782 9.194 ;
     RECT  1.944 8.609 43.542 9.391 ;
     RECT  44.46 9.077 46.17 9.391 ;
     RECT  1.944 9.391 46.17 9.509 ;
     RECT  44.532 9.509 46.17 9.617 ;
     RECT  44.604 9.617 46.17 9.653 ;
     RECT  64.62 9.194 64.746 9.787 ;
     RECT  44.928 9.653 46.17 9.931 ;
     RECT  64.44 9.787 64.746 10.027 ;
     RECT  47.088 9.194 63.558 10.049 ;
     RECT  64.404 10.027 64.746 10.205 ;
     RECT  1.944 9.509 43.758 10.411 ;
     RECT  44.928 9.931 46.314 10.589 ;
     RECT  1.944 10.411 43.866 10.633 ;
     RECT  44.928 10.589 46.026 10.633 ;
     RECT  64.476 10.205 64.746 10.685 ;
     RECT  1.944 10.633 46.026 10.769 ;
     RECT  52.812 10.049 63.558 10.769 ;
     RECT  64.512 10.685 64.746 10.829 ;
     RECT  47.088 10.049 51.822 10.859 ;
     RECT  47.088 10.859 51.75 10.967 ;
     RECT  2.052 10.769 46.026 11.399 ;
     RECT  44.424 11.399 46.026 11.471 ;
     RECT  53.028 10.769 63.558 11.551 ;
     RECT  64.548 10.829 64.746 11.551 ;
     RECT  53.028 11.551 64.746 11.813 ;
     RECT  53.028 11.813 64.71 11.933 ;
     RECT  50.688 10.967 51.75 11.995 ;
     RECT  53.028 11.933 63.882 12.317 ;
     RECT  63.864 12.317 63.882 12.667 ;
     RECT  64.62 11.933 64.71 12.667 ;
     RECT  47.088 10.967 49.806 13.063 ;
     RECT  2.052 11.399 43.434 13.135 ;
     RECT  63.864 12.667 64.71 13.163 ;
     RECT  64.62 13.163 64.71 13.325 ;
     RECT  53.028 12.317 63.126 13.435 ;
     RECT  63.864 13.163 63.882 13.435 ;
     RECT  53.028 13.435 63.882 13.559 ;
     RECT  63.252 13.559 63.882 13.613 ;
     RECT  63.252 13.613 63.846 13.865 ;
     RECT  64.692 13.325 64.71 14.059 ;
     RECT  64.656 14.059 64.71 14.171 ;
     RECT  63.828 13.865 63.846 14.405 ;
     RECT  64.692 14.171 64.71 14.945 ;
     RECT  64.656 14.971 64.674 15.017 ;
     RECT  63.288 14.647 63.306 15.067 ;
     RECT  1.98 13.135 43.434 15.101 ;
     RECT  63.252 15.067 63.306 15.187 ;
     RECT  63.252 15.187 63.882 15.245 ;
     RECT  53.028 13.559 62.514 15.448 ;
     RECT  63.252 15.245 63.27 15.448 ;
     RECT  53.028 15.448 63.27 15.755 ;
     RECT  50.652 11.995 51.75 15.965 ;
     RECT  63.252 15.755 63.27 15.979 ;
     RECT  63.252 15.979 63.846 16.259 ;
     RECT  63.252 16.259 63.81 16.295 ;
     RECT  53.028 15.755 62.514 16.603 ;
     RECT  63.252 16.295 63.27 16.603 ;
     RECT  53.028 16.603 63.27 17.069 ;
     RECT  64.692 16.843 64.71 17.128 ;
     RECT  63.828 17.077 63.846 17.149 ;
     RECT  63.828 17.149 63.882 17.185 ;
     RECT  53.028 17.069 62.694 17.411 ;
     RECT  63.828 17.185 63.954 17.645 ;
     RECT  64.692 17.851 64.71 17.987 ;
     RECT  63.828 17.645 63.882 18.193 ;
     RECT  63.288 18.193 63.882 18.413 ;
     RECT  63.864 18.413 63.882 18.619 ;
     RECT  63.864 18.619 64.494 18.763 ;
     RECT  12.6 15.101 43.434 18.805 ;
     RECT  50.724 15.965 51.75 18.833 ;
     RECT  63.864 18.763 64.71 19.037 ;
     RECT  12.6 18.805 43.506 19.111 ;
     RECT  12.6 19.111 43.542 19.201 ;
     RECT  64.512 19.037 64.71 19.277 ;
     RECT  12.6 19.201 43.758 19.373 ;
     RECT  44.928 11.471 46.026 19.507 ;
     RECT  46.98 13.063 49.806 19.507 ;
     RECT  64.548 19.277 64.71 19.613 ;
     RECT  64.692 19.613 64.71 20.111 ;
     RECT  53.028 17.411 62.514 20.395 ;
     RECT  12.6 19.373 43.506 20.695 ;
     RECT  64.62 20.779 64.638 20.957 ;
     RECT  12.6 20.695 43.902 21.127 ;
     RECT  53.028 20.395 62.694 21.397 ;
     RECT  64.512 21.259 64.53 21.437 ;
     RECT  12.6 21.127 44.046 21.631 ;
     RECT  44.928 19.507 49.806 21.631 ;
     RECT  53.028 21.397 62.73 21.695 ;
     RECT  12.6 21.631 49.806 21.839 ;
     RECT  44.316 21.839 49.806 22.073 ;
     RECT  64.62 21.979 64.638 22.205 ;
     RECT  46.764 22.073 49.806 22.613 ;
     RECT  64.692 22.507 64.71 22.613 ;
     RECT  63.252 22.267 63.27 22.747 ;
     RECT  63.252 22.747 63.306 22.829 ;
     RECT  63.252 22.829 63.27 23.045 ;
     RECT  12.6 21.839 43.434 23.161 ;
     RECT  44.316 22.073 46.026 23.161 ;
     RECT  46.8 22.613 49.806 23.791 ;
     RECT  63.864 23.701 63.882 23.837 ;
     RECT  46.764 23.791 49.806 23.891 ;
     RECT  63.828 23.899 63.846 24.125 ;
     RECT  53.028 21.695 62.514 24.283 ;
     RECT  64.692 24.427 64.71 24.667 ;
     RECT  63.864 24.745 63.882 24.845 ;
     RECT  12.6 23.161 46.026 24.899 ;
     RECT  53.028 24.283 62.694 25.007 ;
     RECT  46.8 23.891 49.806 25.249 ;
     RECT  63.828 25.051 63.846 25.291 ;
     RECT  63.252 25.291 63.846 25.439 ;
     RECT  44.928 24.899 46.026 25.672 ;
     RECT  46.764 25.249 49.806 25.672 ;
     RECT  12.6 24.899 43.974 25.675 ;
     RECT  12.6 25.675 44.19 25.723 ;
     RECT  44.928 25.672 49.806 25.723 ;
     RECT  64.656 24.667 64.71 25.781 ;
     RECT  53.028 25.007 62.514 26.023 ;
     RECT  53.028 26.023 62.73 26.093 ;
     RECT  63.828 25.439 63.846 26.203 ;
     RECT  63.252 26.203 63.846 26.293 ;
     RECT  12.6 25.723 49.806 26.429 ;
     RECT  63.252 26.293 63.882 26.477 ;
     RECT  44.46 26.429 49.806 26.519 ;
     RECT  64.692 25.781 64.71 26.587 ;
     RECT  64.548 26.587 64.71 26.699 ;
     RECT  50.796 18.833 51.75 26.761 ;
     RECT  44.532 26.519 49.806 26.765 ;
     RECT  64.62 26.699 64.71 26.789 ;
     RECT  44.748 26.765 49.806 26.797 ;
     RECT  63.252 26.477 63.306 26.897 ;
     RECT  12.6 26.429 43.434 27.059 ;
     RECT  63.288 26.897 63.306 27.211 ;
     RECT  63.288 27.211 63.342 27.245 ;
     RECT  12.6 27.059 43.362 27.329 ;
     RECT  44.748 26.797 49.95 27.341 ;
     RECT  44.856 27.341 49.95 27.365 ;
     RECT  63.324 27.245 63.342 27.595 ;
     RECT  64.692 26.789 64.71 27.691 ;
     RECT  63.324 27.595 63.846 27.715 ;
     RECT  64.656 27.691 64.71 27.779 ;
     RECT  63.324 27.715 63.882 27.979 ;
     RECT  50.724 26.761 51.75 28.267 ;
     RECT  64.656 27.779 64.674 28.267 ;
     RECT  63.252 27.979 63.882 28.283 ;
     RECT  46.764 27.365 49.95 28.319 ;
     RECT  50.688 28.267 51.75 28.397 ;
     RECT  64.62 28.267 64.674 28.397 ;
     RECT  53.028 26.093 62.514 28.453 ;
     RECT  53.028 28.453 62.766 28.493 ;
     RECT  12.6 27.329 43.29 28.525 ;
     RECT  64.656 28.397 64.674 28.603 ;
     RECT  50.724 28.397 51.75 28.679 ;
     RECT  12.6 28.525 43.506 28.751 ;
     RECT  64.656 28.603 64.71 28.823 ;
     RECT  44.856 27.365 46.026 28.859 ;
     RECT  12.6 28.751 43.434 28.949 ;
     RECT  63.864 28.283 63.882 29.021 ;
     RECT  47.052 28.319 49.95 29.065 ;
     RECT  12.6 28.949 43.362 29.093 ;
     RECT  46.8 29.065 49.95 29.101 ;
     RECT  63.828 29.083 63.846 29.227 ;
     RECT  63.792 29.227 63.846 29.327 ;
     RECT  46.764 29.101 49.95 29.641 ;
     RECT  50.832 28.679 51.75 29.641 ;
     RECT  64.692 28.823 64.71 29.831 ;
     RECT  46.764 29.641 51.75 29.875 ;
     RECT  63.828 29.327 63.846 29.911 ;
     RECT  63.828 29.911 63.882 30.029 ;
     RECT  12.6 29.093 43.29 30.109 ;
     RECT  46.764 29.875 51.966 30.235 ;
     RECT  53.028 28.493 62.586 30.235 ;
     RECT  44.856 28.859 45.954 30.343 ;
     RECT  63.828 30.029 63.846 30.379 ;
     RECT  12.6 30.109 43.362 30.613 ;
     RECT  44.46 30.343 45.954 30.613 ;
     RECT  46.764 30.235 62.586 30.613 ;
     RECT  46.764 30.613 62.73 30.749 ;
     RECT  63.792 30.379 63.846 30.763 ;
     RECT  12.6 30.613 45.954 30.839 ;
     RECT  50.616 30.749 62.73 30.893 ;
     RECT  63.756 30.763 63.846 30.911 ;
     RECT  50.616 30.893 62.586 30.941 ;
     RECT  63.792 30.911 63.846 30.947 ;
     RECT  64.692 30.619 64.71 31.003 ;
     RECT  44.46 30.839 45.954 31.019 ;
     RECT  64.656 31.003 64.71 31.217 ;
     RECT  50.724 30.941 62.586 31.277 ;
     RECT  52.74 31.277 62.586 31.325 ;
     RECT  63.828 30.947 63.846 31.559 ;
     RECT  52.776 31.325 62.586 31.565 ;
     RECT  52.884 31.565 62.586 31.771 ;
     RECT  52.884 31.771 63.27 31.805 ;
     RECT  53.028 31.805 63.27 31.919 ;
     RECT  46.8 30.749 49.842 31.927 ;
     RECT  64.692 31.217 64.71 32.107 ;
     RECT  53.136 31.919 63.27 32.189 ;
     RECT  64.62 32.107 64.71 32.297 ;
     RECT  53.172 32.189 63.27 32.341 ;
     RECT  46.764 31.927 49.842 32.459 ;
     RECT  53.172 32.341 63.882 32.503 ;
     RECT  64.62 32.297 64.638 32.503 ;
     RECT  53.172 32.503 64.638 32.669 ;
     RECT  46.8 32.459 49.842 32.809 ;
     RECT  50.724 31.277 51.966 32.809 ;
     RECT  63.864 32.669 64.638 32.813 ;
     RECT  46.8 32.809 51.966 32.873 ;
     RECT  46.836 32.873 51.966 32.909 ;
     RECT  53.172 32.669 62.766 32.909 ;
     RECT  47.124 32.909 51.966 33.035 ;
     RECT  47.124 33.035 50.166 33.853 ;
     RECT  46.8 33.853 50.166 34.079 ;
     RECT  63.864 32.813 63.882 34.171 ;
     RECT  63.828 34.171 63.882 34.223 ;
     RECT  47.124 34.079 50.166 34.231 ;
     RECT  51.015 33.035 51.966 34.231 ;
     RECT  53.172 32.909 62.586 34.231 ;
     RECT  64.62 32.813 64.638 34.411 ;
     RECT  47.124 34.231 51.966 34.997 ;
     RECT  47.124 34.997 49.878 35.069 ;
     RECT  1.044 28.255 1.062 35.275 ;
     RECT  63.864 34.223 63.882 35.303 ;
     RECT  53.172 34.231 62.73 35.693 ;
     RECT  47.124 35.069 49.842 35.707 ;
     RECT  46.764 35.707 49.842 35.879 ;
     RECT  64.62 34.411 64.71 35.899 ;
     RECT  64.512 35.899 64.71 36.077 ;
     RECT  46.8 35.879 49.842 36.085 ;
     RECT  50.688 34.997 51.966 36.085 ;
     RECT  63.864 36.121 63.882 36.221 ;
     RECT  46.8 36.085 51.966 36.275 ;
     RECT  64.692 36.077 64.71 36.617 ;
     RECT  0.828 35.275 1.062 36.895 ;
     RECT  1.98 15.101 11.682 36.895 ;
     RECT  63.828 36.667 63.846 36.907 ;
     RECT  53.172 35.693 62.586 37.049 ;
     RECT  51.015 36.275 51.966 37.129 ;
     RECT  46.8 36.275 50.202 37.319 ;
     RECT  63.792 36.907 63.846 37.319 ;
     RECT  0.828 36.895 11.682 37.327 ;
     RECT  51.015 37.129 52.326 37.363 ;
     RECT  46.8 37.319 49.842 37.426 ;
     RECT  50.796 37.363 52.326 37.561 ;
     RECT  63.864 37.471 63.882 37.613 ;
     RECT  46.764 37.426 49.842 38.129 ;
     RECT  0.54 37.327 11.682 38.209 ;
     RECT  12.6 30.839 43.29 38.209 ;
     RECT  50.796 37.561 52.398 38.551 ;
     RECT  53.172 37.049 62.55 38.551 ;
     RECT  50.796 38.551 62.55 38.713 ;
     RECT  64.692 37.819 64.71 38.827 ;
     RECT  50.796 38.713 62.982 39.055 ;
     RECT  50.724 39.055 62.982 39.119 ;
     RECT  52.956 39.119 62.982 39.317 ;
     RECT  53.1 39.317 62.982 39.353 ;
     RECT  64.656 38.827 64.71 39.451 ;
     RECT  64.62 39.451 64.71 39.515 ;
     RECT  50.724 39.119 51.966 39.901 ;
     RECT  50.724 39.901 52.362 40.171 ;
     RECT  53.172 39.353 62.982 40.171 ;
     RECT  50.724 40.171 62.982 40.325 ;
     RECT  64.62 39.515 64.638 40.363 ;
     RECT  64.62 40.363 64.71 40.925 ;
     RECT  0.54 38.209 43.29 41.071 ;
     RECT  47.124 38.129 49.842 41.251 ;
     RECT  44.856 31.019 45.954 41.377 ;
     RECT  46.692 41.251 49.842 41.377 ;
     RECT  64.692 40.925 64.71 41.405 ;
     RECT  50.724 40.325 51.966 41.413 ;
     RECT  53.172 40.325 62.982 41.413 ;
     RECT  50.724 41.413 62.982 41.711 ;
     RECT  0.54 41.071 43.542 41.791 ;
     RECT  63.828 41.707 63.846 41.819 ;
     RECT  0.54 41.791 43.578 41.881 ;
     RECT  64.62 41.851 64.638 41.981 ;
     RECT  53.172 41.711 62.982 42.091 ;
     RECT  0.54 41.881 43.758 42.223 ;
     RECT  44.856 41.377 49.842 42.223 ;
     RECT  64.512 42.379 64.53 42.509 ;
     RECT  0.54 42.223 49.842 42.557 ;
     RECT  53.172 42.091 63.27 42.961 ;
     RECT  50.724 41.711 51.966 43.025 ;
     RECT  53.172 42.961 63.306 43.037 ;
     RECT  53.172 43.037 63.27 43.061 ;
     RECT  46.764 42.557 49.842 43.097 ;
     RECT  50.796 43.025 51.966 43.097 ;
     RECT  46.836 43.097 49.842 43.169 ;
     RECT  64.62 43.387 64.638 43.483 ;
     RECT  53.172 43.061 62.982 43.867 ;
     RECT  53.172 43.867 63.27 43.979 ;
     RECT  47.124 43.169 49.842 44.113 ;
     RECT  64.548 43.483 64.638 44.251 ;
     RECT  64.476 44.251 64.638 44.383 ;
     RECT  64.476 44.383 64.674 44.429 ;
     RECT  46.764 44.113 49.842 44.447 ;
     RECT  63.864 44.617 63.882 44.669 ;
     RECT  63.828 44.779 63.846 44.875 ;
     RECT  51.015 43.097 51.966 44.887 ;
     RECT  63.792 44.875 63.846 44.951 ;
     RECT  64.692 45.019 64.71 45.455 ;
     RECT  0.54 42.557 45.954 45.571 ;
     RECT  46.8 44.447 49.842 45.571 ;
     RECT  63.828 44.951 63.846 45.643 ;
     RECT  50.796 44.887 51.966 45.661 ;
     RECT  50.724 45.661 51.966 45.761 ;
     RECT  63.828 45.643 64.638 46.337 ;
     RECT  64.476 46.337 64.638 46.507 ;
     RECT  64.476 46.507 64.674 46.541 ;
     RECT  64.548 46.541 64.674 46.589 ;
     RECT  53.172 43.979 62.982 46.651 ;
     RECT  53.172 46.651 63.27 46.841 ;
     RECT  51.015 45.761 51.966 47.047 ;
     RECT  50.724 47.047 51.966 47.551 ;
     RECT  64.692 46.795 64.71 47.563 ;
     RECT  64.512 47.563 64.71 47.693 ;
     RECT  50.688 47.551 51.966 47.707 ;
     RECT  53.172 46.841 62.982 47.731 ;
     RECT  64.62 47.693 64.71 47.849 ;
     RECT  50.58 47.707 51.966 47.885 ;
     RECT  64.62 47.849 64.638 47.885 ;
     RECT  53.172 47.731 63.27 48.155 ;
     RECT  0.54 45.571 49.842 49.009 ;
     RECT  50.724 47.885 51.966 49.009 ;
     RECT  53.172 48.155 62.982 49.051 ;
     RECT  53.172 49.051 63.27 49.195 ;
     RECT  53.172 49.195 63.846 49.379 ;
     RECT  63.828 49.379 63.846 49.675 ;
     RECT  0.54 49.009 51.966 49.747 ;
     RECT  0.54 49.747 52.002 49.805 ;
     RECT  63.828 49.675 64.53 49.819 ;
     RECT  63.828 49.819 64.638 50.053 ;
     RECT  63.828 50.053 64.71 50.093 ;
     RECT  0.54 49.805 51.966 50.153 ;
     RECT  53.172 49.379 62.982 50.431 ;
     RECT  63.828 50.093 64.638 50.459 ;
     RECT  63.828 50.459 63.846 50.855 ;
     RECT  64.62 50.459 64.638 50.971 ;
     RECT  47.664 50.153 51.966 51.061 ;
     RECT  47.664 51.061 52.182 51.115 ;
     RECT  47.664 51.115 52.254 51.169 ;
     RECT  53.064 50.431 62.982 51.169 ;
     RECT  64.62 50.971 64.71 51.592 ;
     RECT  64.548 51.592 64.71 51.601 ;
     RECT  64.476 51.601 64.71 52.043 ;
     RECT  64.476 52.043 64.638 52.219 ;
     RECT  63.828 52.219 64.638 52.637 ;
     RECT  64.62 52.637 64.638 52.781 ;
     RECT  63.828 52.637 63.882 53.021 ;
     RECT  47.664 51.169 62.982 53.083 ;
     RECT  47.664 53.083 63.306 53.663 ;
     RECT  64.692 53.467 64.71 53.707 ;
     RECT  64.62 53.707 64.71 54.139 ;
     RECT  64.584 54.139 64.71 54.269 ;
     RECT  63.828 53.851 63.846 54.472 ;
     RECT  63.792 54.472 63.846 55.183 ;
     RECT  64.656 54.269 64.71 55.183 ;
     RECT  47.664 53.663 62.982 55.243 ;
     RECT  63.792 55.183 64.71 55.243 ;
     RECT  0.54 50.153 46.71 55.867 ;
     RECT  47.664 55.243 64.71 56.093 ;
     RECT  0.54 55.867 46.782 56.443 ;
     RECT  47.664 56.093 63.306 56.443 ;
     RECT  64.476 56.093 64.71 56.911 ;
     RECT  0.54 56.443 63.306 57.293 ;
     RECT  64.224 56.911 64.71 57.643 ;
     RECT  0.54 57.293 62.982 57.725 ;
     RECT  63.792 57.643 64.71 57.766 ;
     RECT  47.628 57.725 62.982 58.801 ;
     RECT  63.792 57.766 64.782 58.801 ;
     RECT  47.628 58.801 64.782 61.079 ;
     RECT  52.164 61.079 64.782 62.303 ;
     RECT  52.164 62.303 64.71 62.333 ;
     RECT  52.164 62.333 64.638 62.621 ;
     RECT  52.164 62.621 64.494 62.717 ;
     RECT  52.164 62.717 55.926 63.835 ;
     RECT  56.664 62.717 61.974 63.835 ;
     RECT  0.54 57.725 46.818 63.859 ;
     RECT  52.164 63.835 62.226 63.883 ;
     RECT  62.964 62.717 64.494 63.883 ;
     RECT  52.164 63.883 64.494 64.315 ;
     RECT  52.164 64.315 64.638 64.327 ;
     RECT  0.324 63.859 46.818 64.603 ;
     RECT  47.628 61.079 51.426 64.603 ;
     RECT  52.164 64.327 64.746 64.603 ;
     RECT  0.324 64.603 64.746 64.699 ;
     RECT  0.072 64.699 64.746 64.781 ;
    LAYER M4 ;
     RECT  0.044 64.704 0.131 64.728 ;
     RECT  0.181 3.408 0.421 3.432 ;
     RECT  0.421 3.408 0.661 3.48 ;
     RECT  0.421 35.52 0.661 35.544 ;
     RECT  0.661 3.36 0.901 3.48 ;
     RECT  0.901 45.648 1.189 45.672 ;
     RECT  1.189 4.656 1.429 4.68 ;
     RECT  0.181 64.656 1.433 64.68 ;
     RECT  1.429 43.872 1.669 43.896 ;
     RECT  2.101 5.856 2.149 5.88 ;
     RECT  2.101 14.4 2.149 14.424 ;
     RECT  1.429 4.656 2.197 4.728 ;
     RECT  2.149 5.856 2.197 6.12 ;
     RECT  0.661 35.52 2.197 36.12 ;
     RECT  1.909 39.264 2.197 39.288 ;
     RECT  1.925 1.728 2.26 1.752 ;
     RECT  0.901 2.88 2.293 3.48 ;
     RECT  2.197 4.656 2.293 6.12 ;
     RECT  1.189 45.648 2.293 45.864 ;
     RECT  0.085 10.656 2.329 10.68 ;
     RECT  2.149 14.4 2.329 14.52 ;
     RECT  2.185 12.336 2.365 12.36 ;
     RECT  2.26 1.728 2.408 1.8 ;
     RECT  2.293 2.88 2.408 3.624 ;
     RECT  2.293 4.656 2.408 6.888 ;
     RECT  2.365 9.264 2.408 9.288 ;
     RECT  2.329 10.416 2.408 10.68 ;
     RECT  2.365 11.952 2.408 12.36 ;
     RECT  2.329 13.68 2.408 14.52 ;
     RECT  2.293 26.544 2.408 26.568 ;
     RECT  2.197 35.184 2.408 36.12 ;
     RECT  2.197 39.264 2.408 39.624 ;
     RECT  1.669 43.344 2.408 43.896 ;
     RECT  2.293 45.6 2.408 45.864 ;
     RECT  2.408 1.728 2.512 62.652 ;
     RECT  1.669 0.576 2.677 0.6 ;
     RECT  2.437 64.656 2.677 64.68 ;
     RECT  2.512 1.728 2.704 62.382 ;
     RECT  2.677 64.608 2.78 64.68 ;
     RECT  2.677 0.096 2.819 0.6 ;
     RECT  2.704 39.072 2.819 39.096 ;
     RECT  2.819 0.576 2.837 0.6 ;
     RECT  2.704 26.544 2.981 26.568 ;
     RECT  2.704 1.728 3.089 14.808 ;
     RECT  2.78 64.56 3.205 64.68 ;
     RECT  3.089 1.728 3.305 14.52 ;
     RECT  2.704 35.856 3.349 35.88 ;
     RECT  3.305 1.728 3.413 14.424 ;
     RECT  3.692 25.296 3.779 25.32 ;
     RECT  3.413 1.728 3.781 13.704 ;
     RECT  3.205 64.464 3.877 64.68 ;
     RECT  3.877 42.336 3.964 42.36 ;
     RECT  2.704 34.752 3.989 34.776 ;
     RECT  3.925 26.64 4.012 26.664 ;
     RECT  3.877 64.416 4.097 64.68 ;
     RECT  4.165 34.224 4.249 34.248 ;
     RECT  4.097 64.464 4.307 64.68 ;
     RECT  4.237 42.144 4.321 42.168 ;
     RECT  4.307 64.56 4.499 64.68 ;
     RECT  3.781 1.728 4.844 13.32 ;
     RECT  4.844 1.728 4.931 13.8 ;
     RECT  4.268 38.736 5.077 38.76 ;
     RECT  4.931 1.728 5.219 13.704 ;
     RECT  5.219 2.736 5.357 13.704 ;
     RECT  5.324 34.512 5.411 34.536 ;
     RECT  5.557 35.568 5.644 35.592 ;
     RECT  5.357 2.736 5.645 4.488 ;
     RECT  5.653 35.328 5.753 35.352 ;
     RECT  5.701 0.096 5.789 0.12 ;
     RECT  5.357 5.472 5.869 13.704 ;
     RECT  5.852 25.056 5.939 25.08 ;
     RECT  5.645 3.408 6.083 4.488 ;
     RECT  5.893 44.448 6.113 44.472 ;
     RECT  6.073 20.496 6.157 20.52 ;
     RECT  5.219 1.728 6.188 1.752 ;
     RECT  5.869 5.472 6.22 13.32 ;
     RECT  5.701 40.176 6.289 40.2 ;
     RECT  6.22 13.104 6.323 13.32 ;
     RECT  6.085 42.192 6.329 42.216 ;
     RECT  6.188 1.728 6.545 2.328 ;
     RECT  6.289 40.176 6.653 41.016 ;
     RECT  6.545 1.728 6.685 1.752 ;
     RECT  6.083 3.936 6.721 4.488 ;
     RECT  6.22 5.472 6.721 11.928 ;
     RECT  6.653 40.992 6.761 41.016 ;
     RECT  6.685 1.68 6.803 1.752 ;
     RECT  6.716 39.888 6.803 39.912 ;
     RECT  6.829 2.832 7.153 2.952 ;
     RECT  6.721 3.936 7.153 11.928 ;
     RECT  6.803 1.728 7.657 1.752 ;
     RECT  4.499 64.656 7.669 64.68 ;
     RECT  7.669 64.56 7.769 64.68 ;
     RECT  7.657 1.728 7.808 1.8 ;
     RECT  7.153 2.832 7.808 11.928 ;
     RECT  6.323 13.296 7.808 13.32 ;
     RECT  6.757 15.312 7.808 15.336 ;
     RECT  7.669 36.624 7.808 36.648 ;
     RECT  7.148 38.976 7.808 39.336 ;
     RECT  7.808 1.728 7.912 62.652 ;
     RECT  7.912 1.728 8.104 62.382 ;
     RECT  8.005 0.576 8.309 0.6 ;
     RECT  8.104 37.056 8.353 37.08 ;
     RECT  8.104 41.616 8.531 41.784 ;
     RECT  8.104 18.768 8.561 18.792 ;
     RECT  8.104 16.512 8.641 16.536 ;
     RECT  8.531 41.616 8.669 41.64 ;
     RECT  8.104 39.888 8.813 40.488 ;
     RECT  8.104 1.728 8.857 11.976 ;
     RECT  7.769 64.608 8.945 64.68 ;
     RECT  8.104 15.072 8.963 15.096 ;
     RECT  8.945 63.888 8.972 64.68 ;
     RECT  8.857 1.776 9.029 11.976 ;
     RECT  8.972 63.744 9.059 64.68 ;
     RECT  8.813 39.888 9.073 40.44 ;
     RECT  9.073 39.888 9.137 39.912 ;
     RECT  9.059 63.84 9.137 64.68 ;
     RECT  8.104 38.208 9.205 38.568 ;
     RECT  9.205 38.208 9.245 38.808 ;
     RECT  9.137 64.656 9.281 64.68 ;
     RECT  9.205 13.632 9.289 13.656 ;
     RECT  9.245 38.544 9.452 38.808 ;
     RECT  9.452 38.544 9.779 39.096 ;
     RECT  9.029 1.776 10.001 2.28 ;
     RECT  9.779 38.736 10.045 39.096 ;
     RECT  9.029 3.552 10.253 11.976 ;
     RECT  10.253 3.552 10.261 11.784 ;
     RECT  10.045 39.072 10.549 39.096 ;
     RECT  9.493 0.096 10.577 0.12 ;
     RECT  10.261 2.88 10.577 11.784 ;
     RECT  10.508 14.208 10.595 14.232 ;
     RECT  10.94 13.968 11.027 13.992 ;
     RECT  10.549 39.072 11.041 39.384 ;
     RECT  10.577 4.752 11.437 11.784 ;
     RECT  10.493 64.656 11.617 64.68 ;
     RECT  10.577 2.88 11.621 3.624 ;
     RECT  11.617 64.608 11.651 64.68 ;
     RECT  11.437 4.752 11.689 11.88 ;
     RECT  11.041 39.072 11.708 39.912 ;
     RECT  11.708 38.736 11.795 39.912 ;
     RECT  11.689 4.752 11.869 11.976 ;
     RECT  11.797 0.096 11.881 0.12 ;
     RECT  11.689 14.208 11.9 14.232 ;
     RECT  11.621 3.504 11.977 3.624 ;
     RECT  11.869 4.752 11.977 12.024 ;
     RECT  11.651 64.608 11.989 64.632 ;
     RECT  11.9 14.208 12.044 14.52 ;
     RECT  12.044 14.208 12.121 15.096 ;
     RECT  12.121 13.632 12.131 15.096 ;
     RECT  11.977 3.504 12.229 12.024 ;
     RECT  10.021 1.728 12.277 1.752 ;
     RECT  11.989 64.512 12.305 64.632 ;
     RECT  12.131 13.632 12.332 14.232 ;
     RECT  12.305 64.608 12.515 64.632 ;
     RECT  12.229 3.504 12.697 12.072 ;
     RECT  12.565 0.576 12.737 0.6 ;
     RECT  12.697 3.504 12.841 12.216 ;
     RECT  12.332 13.44 12.841 14.232 ;
     RECT  11.795 38.784 12.985 39.912 ;
     RECT  12.841 3.504 13.093 14.232 ;
     RECT  12.277 1.728 13.208 1.8 ;
     RECT  13.093 3.408 13.208 14.232 ;
     RECT  12.985 38.784 13.208 40.44 ;
     RECT  13.208 1.728 13.312 62.652 ;
     RECT  13.093 0.144 13.331 0.168 ;
     RECT  13.312 1.728 13.504 62.382 ;
     RECT  13.504 1.728 13.709 2.328 ;
     RECT  13.805 0.096 13.889 0.12 ;
     RECT  13.504 15.072 14.051 16.44 ;
     RECT  12.725 64.656 14.098 64.68 ;
     RECT  14.051 15.312 14.147 16.44 ;
     RECT  13.504 39.36 14.213 40.488 ;
     RECT  14.098 64.608 14.245 64.68 ;
     RECT  14.213 39.888 14.321 40.488 ;
     RECT  14.245 64.512 14.357 64.68 ;
     RECT  13.709 2.304 14.429 2.328 ;
     RECT  13.504 3.552 14.561 6.168 ;
     RECT  14.147 15.936 14.581 16.44 ;
     RECT  14.561 2.88 14.645 6.168 ;
     RECT  14.605 0.576 14.908 0.6 ;
     RECT  14.965 16.656 15.059 16.68 ;
     RECT  14.645 3.552 15.073 6.168 ;
     RECT  13.504 7.152 15.073 13.272 ;
     RECT  15.029 0.096 15.113 0.12 ;
     RECT  15.073 3.552 15.289 13.272 ;
     RECT  14.321 40.464 15.437 40.488 ;
     RECT  15.289 3.552 15.545 13.368 ;
     RECT  15.577 40.992 15.661 41.016 ;
     RECT  15.301 1.728 15.829 1.752 ;
     RECT  14.357 64.656 15.829 64.68 ;
     RECT  15.829 64.56 15.971 64.68 ;
     RECT  15.829 1.728 15.977 1.8 ;
     RECT  15.649 15.456 16.085 15.48 ;
     RECT  16.009 18.192 16.093 18.216 ;
     RECT  15.253 17.088 16.309 17.112 ;
     RECT  16.501 18.576 16.589 18.6 ;
     RECT  15.545 3.552 16.597 11.736 ;
     RECT  16.405 0.672 16.829 0.696 ;
     RECT  15.971 64.608 16.841 64.632 ;
     RECT  16.597 3.408 16.877 11.736 ;
     RECT  16.829 0.096 16.913 0.696 ;
     RECT  16.913 0.528 17.053 0.696 ;
     RECT  15.977 1.728 17.053 1.752 ;
     RECT  16.988 19.104 17.075 19.128 ;
     RECT  16.877 3.552 17.089 11.736 ;
     RECT  15.545 13.344 17.161 13.368 ;
     RECT  17.228 41.76 17.315 41.784 ;
     RECT  17.053 0.528 17.891 1.752 ;
     RECT  17.891 0.672 18.025 1.752 ;
     RECT  17.089 3.552 18.313 12.024 ;
     RECT  17.161 13.056 18.313 13.368 ;
     RECT  18.38 20.592 18.469 20.616 ;
     RECT  17.477 64.656 18.469 64.68 ;
     RECT  18.469 64.56 18.604 64.68 ;
     RECT  18.025 0.672 18.608 2.28 ;
     RECT  18.313 3.552 18.608 13.368 ;
     RECT  18.469 19.632 18.608 20.616 ;
     RECT  17.756 41.952 18.608 41.976 ;
     RECT  18.017 45.552 18.608 45.576 ;
     RECT  18.608 0.672 18.712 62.652 ;
     RECT  18.712 0.672 18.821 62.382 ;
     RECT  18.821 2.016 18.904 62.382 ;
     RECT  18.904 2.016 18.965 11.736 ;
     RECT  18.604 64.56 19.025 64.632 ;
     RECT  18.904 20.496 19.043 21.096 ;
     RECT  18.821 0.672 19.061 0.936 ;
     RECT  19.025 64.512 19.109 64.632 ;
     RECT  18.965 2.88 19.187 11.736 ;
     RECT  19.187 3.36 19.361 11.736 ;
     RECT  19.043 20.496 19.369 20.52 ;
     RECT  19.061 0.096 19.501 0.936 ;
     RECT  18.904 45.024 19.613 45.048 ;
     RECT  19.361 3.408 19.685 11.736 ;
     RECT  19.501 0.048 19.853 0.936 ;
     RECT  19.853 0.048 19.973 1.752 ;
     RECT  18.904 14.448 20.009 14.472 ;
     RECT  19.973 0.672 20.101 1.752 ;
     RECT  20.101 0.672 20.261 2.328 ;
     RECT  18.904 18.144 20.333 18.168 ;
     RECT  20.261 0.672 20.513 2.184 ;
     RECT  20.108 21.792 20.653 21.816 ;
     RECT  20.653 21.648 20.737 21.816 ;
     RECT  20.78 22.08 20.867 22.104 ;
     RECT  20.513 0.672 21.157 0.936 ;
     RECT  20.513 2.16 21.197 2.184 ;
     RECT  21.061 22.176 21.233 22.776 ;
     RECT  19.685 3.552 21.265 11.736 ;
     RECT  18.904 15.6 21.301 15.624 ;
     RECT  21.233 22.176 21.377 22.2 ;
     RECT  21.265 2.832 21.443 11.736 ;
     RECT  21.301 14.64 21.485 15.624 ;
     RECT  21.157 0.096 21.637 0.936 ;
     RECT  21.829 23.328 21.917 23.352 ;
     RECT  21.485 15.6 21.985 15.624 ;
     RECT  22.093 20.4 22.273 20.424 ;
     RECT  22.273 20.4 22.385 21.384 ;
     RECT  21.985 15.6 22.489 15.816 ;
     RECT  22.489 15.6 22.529 16.68 ;
     RECT  22.268 23.904 22.597 23.928 ;
     RECT  22.529 16.656 22.633 16.68 ;
     RECT  22.597 44.448 22.745 44.472 ;
     RECT  22.597 23.904 22.897 24.504 ;
     RECT  22.849 22.8 22.957 22.824 ;
     RECT  22.633 16.656 22.961 16.92 ;
     RECT  21.443 3.552 22.993 11.736 ;
     RECT  21.637 0.096 23.033 1.752 ;
     RECT  22.961 16.656 23.033 16.824 ;
     RECT  23.033 0.576 23.641 1.752 ;
     RECT  22.993 2.88 23.641 11.736 ;
     RECT  22.897 24.48 23.785 24.504 ;
     RECT  23.641 0.576 23.977 11.736 ;
     RECT  23.977 2.148 24.008 11.736 ;
     RECT  18.904 13.344 24.008 13.368 ;
     RECT  22.529 15.6 24.008 15.624 ;
     RECT  23.033 16.8 24.008 16.824 ;
     RECT  20.473 18.24 24.008 18.264 ;
     RECT  22.385 20.4 24.008 20.424 ;
     RECT  22.957 22.704 24.008 22.824 ;
     RECT  23.785 24.48 24.008 25.32 ;
     RECT  24.008 2.148 24.112 62.652 ;
     RECT  24.112 2.256 24.304 62.652 ;
     RECT  24.325 62.736 24.437 62.76 ;
     RECT  24.304 2.256 24.467 2.328 ;
     RECT  24.304 25.008 24.467 25.896 ;
     RECT  24.304 22.752 24.473 22.776 ;
     RECT  24.304 27.312 24.733 27.336 ;
     RECT  24.467 25.872 24.851 25.896 ;
     RECT  19.781 64.656 24.869 64.68 ;
     RECT  23.977 0.576 24.901 1.176 ;
     RECT  24.304 16.896 24.977 16.92 ;
     RECT  24.901 0.528 25.049 1.176 ;
     RECT  24.304 45.552 25.379 45.576 ;
     RECT  25.532 48.48 25.619 48.504 ;
     RECT  25.049 0.576 25.669 1.176 ;
     RECT  24.467 2.304 25.669 2.328 ;
     RECT  24.304 3.552 25.769 11.736 ;
     RECT  25.772 27.216 25.859 27.24 ;
     RECT  26.053 28.32 26.147 28.344 ;
     RECT  25.669 0.576 26.437 2.328 ;
     RECT  26.305 16.848 26.561 16.872 ;
     RECT  26.437 0.576 26.633 2.568 ;
     RECT  25.769 3.552 26.881 6.168 ;
     RECT  25.769 7.152 26.881 11.736 ;
     RECT  26.821 48.48 26.908 48.504 ;
     RECT  26.809 19.296 26.921 19.32 ;
     RECT  26.881 3.552 27.097 11.736 ;
     RECT  27.061 28.56 27.155 28.584 ;
     RECT  24.304 18.24 27.277 18.264 ;
     RECT  27.241 26.304 27.385 26.856 ;
     RECT  27.169 24.96 27.497 24.984 ;
     RECT  27.457 29.616 27.565 29.64 ;
     RECT  27.565 29.04 27.649 29.64 ;
     RECT  26.633 0.576 27.685 1.752 ;
     RECT  27.097 3.072 27.685 11.736 ;
     RECT  27.649 29.616 27.875 29.64 ;
     RECT  27.277 18.24 27.929 18.84 ;
     RECT  27.385 26.256 27.965 26.856 ;
     RECT  24.304 15.6 28.177 15.624 ;
     RECT  27.965 26.784 28.181 26.856 ;
     RECT  27.685 0.576 28.213 11.736 ;
     RECT  28.177 14.784 28.325 15.624 ;
     RECT  28.316 30.72 28.403 30.744 ;
     RECT  28.213 0.096 28.505 11.736 ;
     RECT  28.505 0.144 28.691 11.736 ;
     RECT  28.181 26.784 29.029 26.808 ;
     RECT  26.333 64.656 29.269 64.68 ;
     RECT  28.691 0.576 29.408 11.736 ;
     RECT  24.304 13.344 29.408 13.368 ;
     RECT  28.325 14.832 29.408 15.624 ;
     RECT  27.929 18.24 29.408 18.264 ;
     RECT  24.304 20.4 29.408 20.424 ;
     RECT  29.029 26.256 29.408 26.808 ;
     RECT  29.269 30.432 29.408 30.456 ;
     RECT  29.18 31.536 29.408 31.56 ;
     RECT  28.556 48.48 29.408 48.504 ;
     RECT  29.408 0.576 29.512 62.652 ;
     RECT  29.269 64.56 29.605 64.68 ;
     RECT  29.512 0.576 29.701 62.382 ;
     RECT  29.701 0.096 29.704 62.382 ;
     RECT  29.605 63.792 29.765 64.68 ;
     RECT  29.704 0.096 29.909 11.736 ;
     RECT  29.704 49.008 29.917 49.032 ;
     RECT  29.909 0.096 30.341 2.328 ;
     RECT  30.341 0.096 30.515 1.704 ;
     RECT  29.704 20.4 30.737 20.712 ;
     RECT  29.704 18.24 30.773 18.312 ;
     RECT  30.689 32.88 30.773 32.904 ;
     RECT  30.812 48.48 30.899 48.504 ;
     RECT  30.515 0.096 30.953 0.936 ;
     RECT  30.769 21.744 30.953 21.768 ;
     RECT  30.953 0.144 31.061 0.936 ;
     RECT  29.704 28.656 31.129 28.68 ;
     RECT  29.765 64.656 31.205 64.68 ;
     RECT  31.34 48.816 31.427 48.84 ;
     RECT  29.909 3.552 31.453 11.736 ;
     RECT  31.58 48.96 31.667 49.032 ;
     RECT  31.061 0.432 31.733 0.936 ;
     RECT  31.667 48.96 31.948 48.984 ;
     RECT  31.453 2.88 31.957 11.736 ;
     RECT  31.309 30.912 31.997 30.936 ;
     RECT  31.957 2.832 32.069 11.736 ;
     RECT  32.108 33.936 32.195 33.96 ;
     RECT  31.733 0.432 32.485 1.752 ;
     RECT  32.381 64.608 32.533 64.632 ;
     RECT  32.533 64.608 32.597 64.68 ;
     RECT  32.597 64.56 32.681 64.68 ;
     RECT  32.681 64.608 32.933 64.68 ;
     RECT  32.485 0.096 33.001 1.752 ;
     RECT  33.068 52.464 33.155 52.488 ;
     RECT  33.001 0.096 33.404 2.472 ;
     RECT  32.069 3.552 33.404 11.736 ;
     RECT  33.404 0.096 33.923 11.736 ;
     RECT  30.737 20.4 33.973 20.424 ;
     RECT  33.505 35.856 34.117 35.88 ;
     RECT  33.937 37.008 34.117 37.032 ;
     RECT  32.933 64.656 34.597 64.68 ;
     RECT  34.597 64.56 34.697 64.68 ;
     RECT  33.923 0.288 34.808 11.736 ;
     RECT  29.704 13.344 34.808 13.368 ;
     RECT  29.704 15.6 34.808 15.624 ;
     RECT  30.773 18.24 34.808 18.264 ;
     RECT  33.973 20.4 34.808 21.192 ;
     RECT  29.704 26.256 34.808 26.28 ;
     RECT  31.129 28.656 34.808 29.64 ;
     RECT  33.685 33.264 34.808 33.288 ;
     RECT  34.765 34.464 34.808 34.488 ;
     RECT  34.117 35.856 34.808 37.032 ;
     RECT  34.808 0.288 34.912 62.652 ;
     RECT  34.912 0.288 35.104 62.382 ;
     RECT  34.697 64.608 35.209 64.68 ;
     RECT  35.104 37.536 35.267 37.608 ;
     RECT  35.104 0.288 35.381 11.736 ;
     RECT  35.381 0.288 35.557 11.64 ;
     RECT  35.557 0.096 35.705 11.64 ;
     RECT  35.267 37.536 35.705 37.56 ;
     RECT  35.209 64.656 36.323 64.68 ;
     RECT  35.104 21.648 36.421 21.672 ;
     RECT  36.229 22.8 36.421 22.824 ;
     RECT  36.421 21.648 36.461 22.824 ;
     RECT  36.236 37.584 36.505 38.04 ;
     RECT  36.461 22.224 36.565 22.824 ;
     RECT  36.565 22.224 36.677 23.64 ;
     RECT  36.629 64.608 36.713 64.632 ;
     RECT  35.705 0.288 36.757 11.64 ;
     RECT  36.86 38.544 36.947 38.568 ;
     RECT  36.817 36.48 37.181 36.504 ;
     RECT  36.677 22.704 37.217 23.64 ;
     RECT  37.141 52.464 37.228 52.488 ;
     RECT  37.388 39.312 37.475 39.336 ;
     RECT  37.217 23.616 37.685 23.64 ;
     RECT  37.909 39.888 37.996 39.912 ;
     RECT  37.825 37.824 38.041 37.848 ;
     RECT  38.077 40.704 38.195 40.728 ;
     RECT  38.041 37.68 38.225 37.848 ;
     RECT  38.225 37.68 38.261 37.704 ;
     RECT  38.396 52.56 38.485 52.584 ;
     RECT  38.485 52.464 38.492 52.584 ;
     RECT  37.669 64.656 38.501 64.68 ;
     RECT  38.473 40.992 38.557 41.016 ;
     RECT  38.501 63.84 38.585 64.68 ;
     RECT  38.545 22.8 38.693 22.824 ;
     RECT  38.492 52.464 38.693 52.872 ;
     RECT  36.757 0.192 38.833 11.64 ;
     RECT  38.585 64.656 38.981 64.68 ;
     RECT  38.693 52.848 39.203 52.872 ;
     RECT  35.104 13.344 39.697 13.368 ;
     RECT  39.337 39.216 39.949 39.24 ;
     RECT  39.445 40.416 39.949 40.44 ;
     RECT  39.697 13.152 40.021 13.368 ;
     RECT  38.833 0.192 40.049 11.736 ;
     RECT  40.049 0.096 40.133 11.736 ;
     RECT  40.133 0.192 40.208 11.736 ;
     RECT  40.021 13.056 40.208 13.368 ;
     RECT  35.104 15.6 40.208 15.624 ;
     RECT  35.104 18.24 40.208 18.264 ;
     RECT  35.104 20.4 40.208 20.424 ;
     RECT  35.104 26.256 40.208 26.28 ;
     RECT  35.104 28.656 40.208 29.64 ;
     RECT  39.949 39.216 40.208 40.44 ;
     RECT  39.653 45.552 40.208 45.576 ;
     RECT  39.884 52.992 40.208 53.016 ;
     RECT  40.208 0.192 40.312 62.652 ;
     RECT  40.312 0.192 40.504 62.382 ;
     RECT  40.504 57.6 40.643 57.624 ;
     RECT  40.069 64.656 40.7 64.68 ;
     RECT  40.504 40.464 40.825 43.176 ;
     RECT  40.825 40.464 40.835 41.784 ;
     RECT  40.7 64.56 40.933 64.68 ;
     RECT  40.504 53.04 40.997 54.12 ;
     RECT  40.835 40.464 41.005 41.064 ;
     RECT  40.825 43.152 41.02 43.176 ;
     RECT  40.933 64.512 41.033 64.68 ;
     RECT  40.504 23.376 41.105 24.504 ;
     RECT  40.997 53.52 41.249 54.12 ;
     RECT  41.005 41.04 41.393 41.064 ;
     RECT  41.105 23.952 41.429 24.504 ;
     RECT  41.249 53.568 41.509 54.12 ;
     RECT  40.504 0.192 41.605 11.736 ;
     RECT  41.516 43.296 41.699 43.704 ;
     RECT  41.509 53.568 41.861 54.504 ;
     RECT  41.941 24.528 41.948 25.128 ;
     RECT  40.504 26.256 41.948 26.28 ;
     RECT  41.033 64.656 41.969 64.68 ;
     RECT  41.948 24.528 42.035 26.28 ;
     RECT  41.948 43.872 42.035 43.896 ;
     RECT  41.965 41.616 42.049 41.64 ;
     RECT  41.605 0.096 42.077 11.736 ;
     RECT  41.861 54.144 42.085 54.504 ;
     RECT  42.085 54.144 42.101 54.744 ;
     RECT  42.073 64.608 42.179 64.632 ;
     RECT  42.101 54.144 42.185 55.272 ;
     RECT  42.035 24.528 42.221 25.128 ;
     RECT  42.185 54.144 42.293 54.744 ;
     RECT  42.044 44.736 42.421 44.76 ;
     RECT  42.397 40.32 42.505 40.344 ;
     RECT  42.035 26.256 42.541 26.28 ;
     RECT  42.421 44.736 42.652 45.096 ;
     RECT  42.541 26.256 42.757 26.664 ;
     RECT  42.652 44.736 42.761 45.144 ;
     RECT  40.504 28.656 42.797 29.64 ;
     RECT  42.761 44.736 43.009 45.048 ;
     RECT  42.757 26.256 43.013 26.904 ;
     RECT  43.013 26.256 43.049 26.808 ;
     RECT  42.853 42.816 43.361 42.84 ;
     RECT  42.949 64.656 43.541 64.68 ;
     RECT  42.293 54.144 43.573 54.168 ;
     RECT  42.221 24.528 43.621 25.08 ;
     RECT  43.541 63.84 43.625 64.68 ;
     RECT  43.621 24.528 43.669 25.272 ;
     RECT  43.049 26.256 43.669 26.28 ;
     RECT  43.361 42.768 43.685 42.84 ;
     RECT  43.685 42.768 43.765 43.368 ;
     RECT  43.573 54.144 43.769 54.696 ;
     RECT  43.765 42.768 43.801 43.464 ;
     RECT  43.009 44.448 43.801 45.048 ;
     RECT  43.669 24.528 43.841 26.28 ;
     RECT  43.801 42.72 43.859 45.048 ;
     RECT  43.841 25.104 43.913 26.28 ;
     RECT  43.913 25.68 44.012 26.28 ;
     RECT  43.625 64.656 44.057 64.68 ;
     RECT  44.012 25.68 44.201 26.424 ;
     RECT  44.201 25.728 44.453 26.424 ;
     RECT  44.453 26.016 44.521 26.424 ;
     RECT  44.197 49.008 44.597 49.032 ;
     RECT  43.772 54.72 44.629 55.032 ;
     RECT  44.588 64.704 44.675 64.728 ;
     RECT  44.521 26.016 44.693 26.76 ;
     RECT  43.859 42.72 45.205 44.472 ;
     RECT  43.981 45.552 45.205 45.576 ;
     RECT  44.629 54.72 45.445 55.272 ;
     RECT  45.205 42.72 45.493 45.576 ;
     RECT  42.077 0.192 45.608 11.736 ;
     RECT  40.504 13.056 45.608 13.176 ;
     RECT  40.504 15.6 45.608 16.536 ;
     RECT  40.504 18.24 45.608 18.264 ;
     RECT  40.504 20.4 45.608 20.424 ;
     RECT  44.125 23.184 45.608 23.208 ;
     RECT  44.693 26.016 45.608 27.336 ;
     RECT  42.797 28.752 45.608 29.64 ;
     RECT  42.505 40.32 45.608 40.632 ;
     RECT  45.493 42.72 45.608 45.624 ;
     RECT  45.404 46.896 45.608 46.92 ;
     RECT  44.725 48.48 45.608 48.504 ;
     RECT  45.445 54.72 45.608 55.896 ;
     RECT  45.608 0.192 45.637 62.652 ;
     RECT  45.637 0.096 45.712 62.652 ;
     RECT  45.445 64.656 45.733 64.68 ;
     RECT  45.733 64.608 45.853 64.68 ;
     RECT  45.712 0.096 45.904 62.382 ;
     RECT  45.904 0.096 46.019 11.736 ;
     RECT  45.904 52.416 46.145 52.44 ;
     RECT  45.904 25.68 46.289 27.336 ;
     RECT  45.904 43.104 46.577 47.88 ;
     RECT  46.289 26.208 46.685 27.336 ;
     RECT  46.577 46.176 46.78 47.88 ;
     RECT  45.904 28.752 46.793 29.64 ;
     RECT  45.904 55.872 46.793 57 ;
     RECT  46.685 26.256 46.901 27.336 ;
     RECT  45.904 37.44 46.901 37.464 ;
     RECT  45.853 64.608 46.931 64.728 ;
     RECT  46.897 48.432 46.94 48.456 ;
     RECT  46.94 48.432 46.981 48.552 ;
     RECT  46.981 48.528 47.027 48.552 ;
     RECT  46.901 26.448 47.045 27.336 ;
     RECT  47.045 26.784 47.125 27.336 ;
     RECT  46.793 28.752 47.125 29.544 ;
     RECT  46.793 56.448 47.221 57 ;
     RECT  47.317 48.816 47.324 48.84 ;
     RECT  47.125 26.784 47.333 29.544 ;
     RECT  46.931 64.608 47.461 64.632 ;
     RECT  47.324 48.816 47.545 49.032 ;
     RECT  47.221 50.112 47.545 50.136 ;
     RECT  46.78 46.176 47.581 47.352 ;
     RECT  47.461 64.512 47.605 64.632 ;
     RECT  47.333 28.368 47.747 29.544 ;
     RECT  47.581 45.744 47.761 47.352 ;
     RECT  47.605 64.416 47.842 64.632 ;
     RECT  47.747 28.368 47.945 28.536 ;
     RECT  47.842 64.368 47.969 64.632 ;
     RECT  47.969 64.368 47.987 64.68 ;
     RECT  47.545 48.816 48.092 50.136 ;
     RECT  47.761 45.744 48.133 47.448 ;
     RECT  48.092 48.816 48.133 50.712 ;
     RECT  47.221 56.448 48.149 57.72 ;
     RECT  48.133 45.744 48.179 50.712 ;
     RECT  48.149 56.448 48.197 58.152 ;
     RECT  47.333 26.784 48.233 27.336 ;
     RECT  48.179 45.744 48.275 50.136 ;
     RECT  47.987 64.512 48.371 64.68 ;
     RECT  48.275 45.744 48.413 49.032 ;
     RECT  48.371 64.608 48.61 64.68 ;
     RECT  48.61 64.608 48.707 64.728 ;
     RECT  48.197 57.024 48.737 58.152 ;
     RECT  48.275 50.112 48.745 50.136 ;
     RECT  48.233 27.072 48.805 27.336 ;
     RECT  47.945 28.368 48.805 28.488 ;
     RECT  48.737 57.072 48.845 58.152 ;
     RECT  48.413 48.48 48.899 49.032 ;
     RECT  48.805 27.072 48.925 28.488 ;
     RECT  48.899 48.48 49.061 48.504 ;
     RECT  48.845 57.6 49.139 58.152 ;
     RECT  48.925 27.072 49.169 28.392 ;
     RECT  48.757 51.504 49.189 51.528 ;
     RECT  49.189 50.976 49.196 51.528 ;
     RECT  49.445 62.688 49.529 62.712 ;
     RECT  46.019 0.192 49.669 11.736 ;
     RECT  49.196 50.976 49.811 52.488 ;
     RECT  47.747 29.52 49.949 29.544 ;
     RECT  49.139 57.6 49.961 58.008 ;
     RECT  49.949 29.52 50.005 29.688 ;
     RECT  49.993 50.16 50.053 50.76 ;
     RECT  48.707 64.608 50.093 64.68 ;
     RECT  50.093 63.84 50.177 64.68 ;
     RECT  50.005 29.52 50.293 30.216 ;
     RECT  50.293 29.52 50.348 30.312 ;
     RECT  50.348 29.52 50.492 30.456 ;
     RECT  49.169 28.368 50.533 28.392 ;
     RECT  48.413 45.744 50.569 47.112 ;
     RECT  50.101 58.128 50.569 58.536 ;
     RECT  50.492 29.52 50.581 30.744 ;
     RECT  50.581 29.52 50.588 30.84 ;
     RECT  49.669 0.096 50.641 11.736 ;
     RECT  50.588 29.52 50.725 30.936 ;
     RECT  50.533 28.176 50.773 28.392 ;
     RECT  50.773 28.176 50.813 28.536 ;
     RECT  50.725 29.52 50.813 31.272 ;
     RECT  50.177 64.464 50.819 64.68 ;
     RECT  50.053 49.584 50.821 50.76 ;
     RECT  49.811 51.792 50.821 52.488 ;
     RECT  50.641 0.096 51.008 12.024 ;
     RECT  45.904 13.056 51.008 13.176 ;
     RECT  45.904 15.6 51.008 16.536 ;
     RECT  45.904 18.24 51.008 18.264 ;
     RECT  45.904 20.4 51.008 20.424 ;
     RECT  49.169 27.072 51.008 27.096 ;
     RECT  50.813 28.176 51.008 31.272 ;
     RECT  50.713 34.944 51.008 34.968 ;
     RECT  45.904 40.32 51.008 40.632 ;
     RECT  46.577 43.104 51.008 44.664 ;
     RECT  50.569 45.744 51.008 47.736 ;
     RECT  50.821 49.584 51.008 52.584 ;
     RECT  50.569 58.128 51.008 58.68 ;
     RECT  50.819 64.56 51.059 64.68 ;
     RECT  51.008 0.096 51.112 62.652 ;
     RECT  51.112 0.096 51.304 62.382 ;
     RECT  51.304 28.272 51.545 30.744 ;
     RECT  51.545 29.52 51.581 30.744 ;
     RECT  51.304 52.992 51.733 54.408 ;
     RECT  51.304 58.704 51.905 59.832 ;
     RECT  51.733 53.568 51.971 54.408 ;
     RECT  51.059 64.56 52.019 64.632 ;
     RECT  51.971 54.096 52.067 54.408 ;
     RECT  51.905 58.752 52.121 59.832 ;
     RECT  52.021 64.512 52.163 64.536 ;
     RECT  52.121 59.28 52.165 59.832 ;
     RECT  51.304 49.776 52.325 51.912 ;
     RECT  51.581 29.616 52.405 30.744 ;
     RECT  52.325 49.776 52.405 52.008 ;
     RECT  52.405 29.616 52.433 30.984 ;
     RECT  51.304 0.096 52.517 11.736 ;
     RECT  52.433 29.616 52.597 31.08 ;
     RECT  52.597 29.616 52.625 31.272 ;
     RECT  52.625 30.864 52.645 31.272 ;
     RECT  52.645 30.864 52.748 31.368 ;
     RECT  52.405 49.776 52.757 52.104 ;
     RECT  52.757 49.776 52.84 52.488 ;
     RECT  52.748 30.864 52.844 31.56 ;
     RECT  52.844 30.864 52.931 31.8 ;
     RECT  52.84 49.776 52.933 52.536 ;
     RECT  52.931 30.864 53.093 31.416 ;
     RECT  53.029 64.56 53.122 64.584 ;
     RECT  53.122 64.56 53.129 64.728 ;
     RECT  52.469 54.672 53.161 54.696 ;
     RECT  52.165 59.28 53.161 59.304 ;
     RECT  53.129 64.608 53.219 64.728 ;
     RECT  53.161 54.576 53.245 54.696 ;
     RECT  53.161 59.28 53.273 59.832 ;
     RECT  51.304 55.872 53.276 55.896 ;
     RECT  53.273 59.376 53.309 59.832 ;
     RECT  53.276 55.008 53.363 55.896 ;
     RECT  53.219 64.608 53.363 64.68 ;
     RECT  53.317 59.856 53.461 59.88 ;
     RECT  53.461 59.856 53.489 60.696 ;
     RECT  53.363 55.872 53.509 55.896 ;
     RECT  53.477 62.688 53.561 62.712 ;
     RECT  52.625 29.616 53.605 29.64 ;
     RECT  52.933 49.776 53.621 52.728 ;
     RECT  51.304 40.32 53.629 40.632 ;
     RECT  53.605 29.616 53.699 30.456 ;
     RECT  53.621 49.776 53.705 53.592 ;
     RECT  53.629 40.32 53.741 40.92 ;
     RECT  53.699 29.616 53.813 30.264 ;
     RECT  53.509 55.872 54.025 56.136 ;
     RECT  53.489 60.432 54.035 60.696 ;
     RECT  53.363 64.608 54.035 64.632 ;
     RECT  54.025 55.872 54.131 56.424 ;
     RECT  54.131 55.872 54.173 56.136 ;
     RECT  54.035 60.432 54.173 60.456 ;
     RECT  51.304 43.104 54.389 44.664 ;
     RECT  52.517 0.192 54.469 11.736 ;
     RECT  54.173 56.112 54.659 56.136 ;
     RECT  54.517 64.656 54.659 64.68 ;
     RECT  54.389 43.248 54.997 44.664 ;
     RECT  54.757 62.688 55.004 62.712 ;
     RECT  54.469 0.096 55.109 11.736 ;
     RECT  55.141 31.344 55.537 31.368 ;
     RECT  55.004 62.16 55.669 62.712 ;
     RECT  55.465 54.144 55.753 54.168 ;
     RECT  53.705 49.776 55.813 52.824 ;
     RECT  55.753 53.808 55.813 54.168 ;
     RECT  51.304 13.056 55.861 13.176 ;
     RECT  55.537 31.344 55.861 31.896 ;
     RECT  55.573 55.92 55.861 55.944 ;
     RECT  55.861 55.872 56.005 55.944 ;
     RECT  55.645 57.552 56.108 57.576 ;
     RECT  55.628 64.704 56.195 64.728 ;
     RECT  55.109 0.192 56.365 11.736 ;
     RECT  54.997 43.248 56.365 44.712 ;
     RECT  51.304 45.744 56.365 47.736 ;
     RECT  56.365 0.144 56.408 11.736 ;
     RECT  55.861 13.008 56.408 13.176 ;
     RECT  51.304 15.6 56.408 16.536 ;
     RECT  51.304 18.24 56.408 18.264 ;
     RECT  51.304 20.4 56.408 20.424 ;
     RECT  51.304 27.072 56.408 27.096 ;
     RECT  51.545 28.272 56.408 28.296 ;
     RECT  53.813 29.616 56.408 29.64 ;
     RECT  55.861 30.816 56.408 31.896 ;
     RECT  53.741 40.56 56.408 40.92 ;
     RECT  56.365 43.248 56.408 47.736 ;
     RECT  55.813 49.776 56.408 54.168 ;
     RECT  56.005 55.296 56.408 55.944 ;
     RECT  56.108 57.168 56.408 57.576 ;
     RECT  55.669 61.008 56.408 62.712 ;
     RECT  56.245 63.84 56.441 63.864 ;
     RECT  56.408 0.144 56.533 62.712 ;
     RECT  56.533 0.144 56.704 62.808 ;
     RECT  56.704 62.16 56.765 62.808 ;
     RECT  56.704 61.008 56.819 61.032 ;
     RECT  56.704 55.92 56.845 57.576 ;
     RECT  56.704 31.344 56.915 32.568 ;
     RECT  56.845 55.92 56.953 56.664 ;
     RECT  56.915 31.392 56.981 32.568 ;
     RECT  56.704 0.144 57.013 11.736 ;
     RECT  56.981 31.92 57.089 32.568 ;
     RECT  57.013 0.096 57.233 11.736 ;
     RECT  56.704 43.248 57.697 47.736 ;
     RECT  57.089 32.544 57.973 32.568 ;
     RECT  56.704 33.648 57.973 33.672 ;
     RECT  56.704 13.056 58.021 13.176 ;
     RECT  57.973 32.544 58.057 33.672 ;
     RECT  58.057 32.256 58.093 33.672 ;
     RECT  57.697 43.248 58.093 47.88 ;
     RECT  58.093 31.632 58.129 33.672 ;
     RECT  58.117 58.176 58.309 58.2 ;
     RECT  58.309 58.176 58.316 58.728 ;
     RECT  58.316 58.176 58.405 59.64 ;
     RECT  58.405 57.648 58.481 59.64 ;
     RECT  56.704 49.776 58.565 53.832 ;
     RECT  58.481 57.6 58.565 59.64 ;
     RECT  58.093 43.248 58.633 48.216 ;
     RECT  58.129 31.632 58.669 33.816 ;
     RECT  58.669 31.632 58.741 33.96 ;
     RECT  56.704 37.2 58.741 39 ;
     RECT  58.565 57.648 58.885 59.64 ;
     RECT  57.233 0.192 58.933 11.736 ;
     RECT  58.741 31.632 58.993 34.824 ;
     RECT  58.885 57.648 59.029 59.832 ;
     RECT  56.704 18.24 59.245 18.264 ;
     RECT  56.704 40.56 59.245 40.92 ;
     RECT  59.245 17.712 59.281 18.264 ;
     RECT  58.993 31.632 59.317 35.352 ;
     RECT  58.741 37.056 59.317 39 ;
     RECT  58.633 43.248 59.317 48.552 ;
     RECT  59.317 31.632 59.677 35.448 ;
     RECT  59.317 36.816 59.677 39 ;
     RECT  56.765 62.16 59.701 62.712 ;
     RECT  56.953 55.92 59.713 56.616 ;
     RECT  59.029 57.648 59.713 59.88 ;
     RECT  59.66 64.704 59.747 64.728 ;
     RECT  59.281 17.712 59.749 18.504 ;
     RECT  59.749 17.712 59.821 18.792 ;
     RECT  56.704 20.4 59.821 20.424 ;
     RECT  58.565 50.016 59.821 53.832 ;
     RECT  58.933 0.192 59.857 11.832 ;
     RECT  59.821 17.712 59.857 20.424 ;
     RECT  59.857 0.192 59.929 11.928 ;
     RECT  58.021 13.056 59.929 13.704 ;
     RECT  59.701 62.112 59.965 62.712 ;
     RECT  59.713 55.92 59.996 59.88 ;
     RECT  59.965 61.344 59.996 62.712 ;
     RECT  59.821 49.824 60.133 53.832 ;
     RECT  59.929 0.192 60.149 13.704 ;
     RECT  60.133 49.824 60.293 54.168 ;
     RECT  56.704 29.472 60.397 29.64 ;
     RECT  59.857 17.712 60.433 20.664 ;
     RECT  60.373 63.984 60.517 64.008 ;
     RECT  60.517 63.936 60.721 64.008 ;
     RECT  60.433 17.712 60.865 21.192 ;
     RECT  59.677 31.632 60.865 39 ;
     RECT  59.245 40.08 60.865 40.92 ;
     RECT  60.721 63.84 60.949 64.008 ;
     RECT  60.949 63.84 61.045 64.2 ;
     RECT  59.996 55.92 61.081 62.712 ;
     RECT  61.081 55.92 61.189 62.76 ;
     RECT  61.189 55.776 61.237 62.76 ;
     RECT  61.045 63.84 61.237 64.296 ;
     RECT  60.149 0.192 61.285 13.176 ;
     RECT  61.285 0.096 61.297 13.176 ;
     RECT  61.237 55.488 61.333 62.76 ;
     RECT  60.293 53.808 61.381 54.168 ;
     RECT  61.333 55.488 61.381 62.856 ;
     RECT  60.865 17.712 61.513 22.008 ;
     RECT  59.317 43.248 61.513 48.696 ;
     RECT  61.381 53.808 61.513 62.856 ;
     RECT  61.237 63.84 61.513 64.68 ;
     RECT  61.297 0.048 61.525 13.176 ;
     RECT  61.513 41.952 61.621 48.696 ;
     RECT  60.293 49.824 61.621 52.776 ;
     RECT  61.525 0.048 61.808 13.512 ;
     RECT  56.704 15.6 61.808 16.536 ;
     RECT  61.513 17.712 61.808 22.056 ;
     RECT  56.704 27.072 61.808 27.096 ;
     RECT  56.704 28.272 61.808 28.296 ;
     RECT  60.397 29.472 61.808 30.12 ;
     RECT  60.865 31.632 61.808 40.92 ;
     RECT  61.621 41.952 61.808 52.776 ;
     RECT  61.513 53.808 61.808 64.68 ;
     RECT  61.808 0.048 62.104 64.68 ;
     RECT  62.104 0.048 62.165 14.616 ;
     RECT  62.165 0.048 62.561 11.784 ;
     RECT  62.165 12.864 63.205 14.616 ;
     RECT  62.104 15.6 63.205 24.936 ;
     RECT  62.104 29.472 63.205 52.776 ;
     RECT  62.104 53.808 63.205 64.68 ;
     RECT  63.205 12.864 63.241 24.936 ;
     RECT  62.104 26.064 63.241 27.096 ;
     RECT  62.104 28.224 63.241 28.488 ;
     RECT  63.241 12.864 63.781 28.488 ;
     RECT  63.205 29.472 63.781 64.728 ;
     RECT  63.781 12.864 63.853 64.728 ;
     RECT  62.561 0.048 63.889 11.736 ;
     RECT  63.853 12.816 63.889 64.728 ;
     RECT  63.889 0.048 64.764 64.728 ;
    LAYER M5 ;
     RECT  0.192 0.016 64.632 0.131 ;
     RECT  0.192 0.131 54.264 0.179 ;
     RECT  0.192 0.179 51.24 1.139 ;
     RECT  55.248 0.131 64.632 1.187 ;
     RECT  55.248 1.187 63.624 1.283 ;
     RECT  22.656 1.139 51.24 1.715 ;
     RECT  0.192 1.139 21.672 1.763 ;
     RECT  22.656 1.715 30.264 1.763 ;
     RECT  31.248 1.715 51.24 1.763 ;
     RECT  52.224 0.179 54.264 1.763 ;
     RECT  55.248 1.283 62.616 1.763 ;
     RECT  7.776 1.763 14.616 1.811 ;
     RECT  15.84 1.763 16.632 1.811 ;
     RECT  42.096 1.763 51.24 1.811 ;
     RECT  42.096 1.811 47.208 1.859 ;
     RECT  55.248 1.763 59.016 1.859 ;
     RECT  48.192 1.811 51.24 2.151 ;
     RECT  27.456 1.763 30.264 2.195 ;
     RECT  7.8 1.811 11.592 2.291 ;
     RECT  28.464 2.195 30.264 2.291 ;
     RECT  42.864 1.859 46.68 2.291 ;
     RECT  55.248 1.859 55.272 2.291 ;
     RECT  0.192 1.763 6.504 2.339 ;
     RECT  12.816 1.811 14.616 2.339 ;
     RECT  17.616 1.763 21.432 2.339 ;
     RECT  23.664 1.763 26.472 2.339 ;
     RECT  28.656 2.291 30.264 2.339 ;
     RECT  0.192 2.339 5.592 2.387 ;
     RECT  33.024 1.763 40.632 2.387 ;
     RECT  42.864 2.291 44.424 2.387 ;
     RECT  48.192 2.151 51.312 2.387 ;
     RECT  44.4 2.387 44.424 2.435 ;
     RECT  33.024 2.387 35.352 2.483 ;
     RECT  39.312 2.387 40.632 2.483 ;
     RECT  26.448 2.339 26.472 2.579 ;
     RECT  7.8 2.291 9.048 2.821 ;
     RECT  31.248 1.763 31.512 2.861 ;
     RECT  20.64 2.339 21.432 2.867 ;
     RECT  10.272 2.291 11.592 2.915 ;
     RECT  14.592 2.339 14.616 2.915 ;
     RECT  38.064 2.387 38.088 2.963 ;
     RECT  40.2 2.483 40.632 2.963 ;
     RECT  49.2 2.387 51.312 2.963 ;
     RECT  52.704 1.763 54.264 2.963 ;
     RECT  63.6 1.283 63.624 2.963 ;
     RECT  4.656 2.387 5.592 3.397 ;
     RECT  56.4 1.859 59.016 3.397 ;
     RECT  60.576 1.763 62.52 3.397 ;
     RECT  0.192 2.387 3.672 3.443 ;
     RECT  16.608 1.811 16.632 3.443 ;
     RECT  17.616 2.339 19.416 3.443 ;
     RECT  36.432 2.387 36.792 3.443 ;
     RECT  45.408 2.291 46.68 3.443 ;
     RECT  64.608 1.187 64.632 3.443 ;
     RECT  0.432 3.443 3.672 3.491 ;
     RECT  17.616 3.443 19.176 3.683 ;
     RECT  27.456 2.195 27.48 3.683 ;
     RECT  7.632 2.821 9.048 3.733 ;
     RECT  56.4 3.397 59.544 3.781 ;
     RECT  60.528 3.397 62.52 3.781 ;
     RECT  1.2 3.491 3.672 3.877 ;
     RECT  4.656 3.397 6.072 3.877 ;
     RECT  12.816 2.339 13.512 3.877 ;
     RECT  33.456 2.483 35.352 3.877 ;
     RECT  1.2 3.877 6.072 3.925 ;
     RECT  20.64 2.867 20.664 4.019 ;
     RECT  25.44 2.339 25.464 4.019 ;
     RECT  43.104 2.387 43.416 4.019 ;
     RECT  52.704 2.963 52.728 4.019 ;
     RECT  56.4 3.781 62.52 4.019 ;
     RECT  50.448 2.963 51.312 4.115 ;
     RECT  12.816 3.877 13.608 4.163 ;
     RECT  33.456 3.877 35.4 4.165 ;
     RECT  10.032 3.877 10.056 4.259 ;
     RECT  1.2 3.925 6.216 4.501 ;
     RECT  7.488 3.733 9.048 4.501 ;
     RECT  31.248 2.861 31.56 4.547 ;
     RECT  31.536 4.547 31.56 4.595 ;
     RECT  33.456 4.165 35.736 4.595 ;
     RECT  36.768 3.443 36.792 4.595 ;
     RECT  49.2 2.963 49.224 4.595 ;
     RECT  13.104 4.163 13.608 4.643 ;
     RECT  1.2 4.501 9.048 4.691 ;
     RECT  1.44 4.691 9.048 4.739 ;
     RECT  45.6 3.443 46.68 4.739 ;
     RECT  33.792 4.595 35.736 4.741 ;
     RECT  64.608 4.645 64.632 5.027 ;
     RECT  12.048 4.933 12.072 5.075 ;
     RECT  28.656 2.339 29.712 5.171 ;
     RECT  18.6 3.683 19.176 5.555 ;
     RECT  33.792 4.741 35.832 5.701 ;
     RECT  51 4.115 51.312 5.701 ;
     RECT  58.992 4.019 62.52 5.701 ;
     RECT  33.792 5.701 36.504 5.749 ;
     RECT  56.4 4.019 57.528 5.749 ;
     RECT  58.992 5.701 63.144 5.749 ;
     RECT  2.208 4.739 9.048 5.845 ;
     RECT  16.656 5.317 16.68 5.891 ;
     RECT  44.496 5.701 44.52 5.893 ;
     RECT  45.6 4.739 46.344 5.893 ;
     RECT  56.4 5.749 63.144 6.037 ;
     RECT  54.288 5.461 54.312 6.083 ;
     RECT  43.104 4.019 43.128 6.181 ;
     RECT  40.2 2.963 40.512 6.229 ;
     RECT  43.104 6.181 43.368 6.229 ;
     RECT  55.968 6.037 63.144 6.229 ;
     RECT  44.496 5.893 46.344 6.275 ;
     RECT  2.112 5.845 9.048 6.323 ;
     RECT  55.824 6.229 63.144 6.323 ;
     RECT  63.12 6.323 63.144 6.419 ;
     RECT  40.2 6.229 41.016 6.517 ;
     RECT  42.288 6.229 43.464 6.709 ;
     RECT  44.496 6.275 46.152 6.709 ;
     RECT  55.824 6.323 62.112 6.709 ;
     RECT  39.312 6.517 41.016 6.805 ;
     RECT  47.904 6.229 47.928 6.805 ;
     RECT  49.488 6.661 49.512 6.805 ;
     RECT  33.792 5.749 36.744 6.853 ;
     RECT  33.792 6.853 37.512 6.901 ;
     RECT  13.2 4.643 13.608 7.093 ;
     RECT  24 2.339 24.312 7.189 ;
     RECT  13.104 7.093 13.608 7.235 ;
     RECT  42.288 6.709 46.152 7.237 ;
     RECT  42.288 7.237 46.44 7.381 ;
     RECT  50.544 5.701 51.312 7.429 ;
     RECT  18.6 5.555 19.128 7.477 ;
     RECT  33.792 6.901 37.608 7.523 ;
     RECT  38.88 6.805 41.208 7.619 ;
     RECT  29.28 5.171 29.712 7.621 ;
     RECT  33.792 7.523 35.352 7.621 ;
     RECT  42.288 7.381 46.584 7.621 ;
     RECT  47.904 6.805 49.512 7.621 ;
     RECT  50.544 7.429 51.48 7.621 ;
     RECT  18.6 7.477 19.848 7.667 ;
     RECT  39.312 7.619 41.208 7.667 ;
     RECT  21.12 7.093 21.144 7.669 ;
     RECT  29.28 7.621 29.976 7.669 ;
     RECT  33.072 7.621 35.352 7.811 ;
     RECT  42.288 7.621 46.632 7.861 ;
     RECT  13.104 7.235 13.512 7.907 ;
     RECT  18.6 7.667 18.912 7.909 ;
     RECT  20.304 7.669 21.144 7.955 ;
     RECT  29.088 7.669 29.976 7.955 ;
     RECT  33.792 7.811 35.352 8.003 ;
     RECT  18.384 7.909 18.912 8.051 ;
     RECT  2.112 6.323 9 8.341 ;
     RECT  47.904 7.621 51.48 8.341 ;
     RECT  47.904 8.341 51.96 8.437 ;
     RECT  18.48 8.051 18.912 8.483 ;
     RECT  40.2 7.667 41.208 8.485 ;
     RECT  42.288 7.861 46.68 8.485 ;
     RECT  24 7.189 25.128 8.771 ;
     RECT  40.2 8.485 46.92 8.917 ;
     RECT  47.904 8.437 52.392 8.917 ;
     RECT  13.2 7.907 13.512 8.965 ;
     RECT  34.272 8.003 35.352 9.013 ;
     RECT  40.2 8.917 52.392 9.013 ;
     RECT  40.2 9.013 52.44 9.061 ;
     RECT  53.616 6.229 53.64 9.061 ;
     RECT  34.176 9.013 35.352 9.107 ;
     RECT  34.176 9.107 35.304 9.155 ;
     RECT  36.336 7.523 37.608 9.251 ;
     RECT  13.056 8.965 13.512 9.253 ;
     RECT  14.88 7.381 14.904 9.253 ;
     RECT  20.304 7.955 20.328 9.253 ;
     RECT  29.088 7.955 29.712 9.253 ;
     RECT  29.088 9.253 30.072 9.301 ;
     RECT  37.584 9.251 37.608 9.347 ;
     RECT  20.304 9.253 21.144 9.443 ;
     RECT  18.6 8.483 18.912 9.493 ;
     RECT  20.304 9.443 20.52 9.493 ;
     RECT  2.112 8.341 9.624 9.541 ;
     RECT  13.056 9.253 13.608 9.587 ;
     RECT  14.832 9.253 14.904 9.587 ;
     RECT  18.6 9.493 20.52 9.587 ;
     RECT  29.088 9.301 30.888 9.587 ;
     RECT  29.088 9.587 29.976 9.635 ;
     RECT  18.6 9.587 20.424 9.683 ;
     RECT  14.88 9.587 14.904 9.875 ;
     RECT  34.8 9.155 35.304 9.875 ;
     RECT  10.8 9.109 10.824 10.069 ;
     RECT  40.2 9.061 53.64 10.163 ;
     RECT  13.056 9.587 13.512 10.211 ;
     RECT  36.432 9.251 36.504 10.213 ;
     RECT  18.6 9.683 20.04 10.451 ;
     RECT  24 8.771 24.312 10.549 ;
     RECT  64.608 10.357 64.632 10.691 ;
     RECT  29.088 9.635 29.712 10.741 ;
     RECT  24 10.549 25.128 10.787 ;
     RECT  2.112 9.541 9.672 10.883 ;
     RECT  10.8 10.069 10.872 10.883 ;
     RECT  22.8 7.189 22.824 10.883 ;
     RECT  29.088 10.741 29.832 10.883 ;
     RECT  2.112 10.883 6.312 10.931 ;
     RECT  20.016 10.451 20.04 10.931 ;
     RECT  31.296 9.733 31.32 10.931 ;
     RECT  29.4 10.883 29.832 10.979 ;
     RECT  40.2 10.163 48.936 10.979 ;
     RECT  26.544 11.125 26.568 11.267 ;
     RECT  37.728 10.933 37.752 11.411 ;
     RECT  7.392 10.883 9.672 11.459 ;
     RECT  10.848 10.883 10.872 11.459 ;
     RECT  7.44 11.459 9.048 11.555 ;
     RECT  2.112 10.931 4.392 12.323 ;
     RECT  5.376 10.931 6.312 13.139 ;
     RECT  3.744 12.323 4.392 13.141 ;
     RECT  5.376 13.139 5.832 13.141 ;
     RECT  13.2 10.211 13.512 13.429 ;
     RECT  7.8 11.555 9.048 13.621 ;
     RECT  12.384 13.429 13.512 13.621 ;
     RECT  3.744 13.141 5.832 13.715 ;
     RECT  4.176 13.715 5.688 13.811 ;
     RECT  10.992 13.957 11.016 14.197 ;
     RECT  12.144 13.621 13.512 14.197 ;
     RECT  2.112 12.323 2.712 14.435 ;
     RECT  2.16 14.435 2.712 14.531 ;
     RECT  10.56 14.197 13.512 15.061 ;
     RECT  10.56 15.061 14.04 15.301 ;
     RECT  10.56 15.301 14.136 15.925 ;
     RECT  10.56 15.925 14.568 16.645 ;
     RECT  10.56 16.645 15.048 17.077 ;
     RECT  10.56 17.077 16.296 18.565 ;
     RECT  10.56 18.565 16.536 19.093 ;
     RECT  64.608 19.237 64.632 19.379 ;
     RECT  18.6 10.451 18.912 19.621 ;
     RECT  5.664 13.811 5.688 20.485 ;
     RECT  6.768 15.301 6.792 20.485 ;
     RECT  18.48 19.621 18.912 20.485 ;
     RECT  18.48 20.485 19.32 20.581 ;
     RECT  64.608 21.205 64.632 21.443 ;
     RECT  18.432 20.581 19.32 21.781 ;
     RECT  20.688 21.637 20.712 21.781 ;
     RECT  18.432 21.781 20.712 22.069 ;
     RECT  18.432 22.069 20.856 22.165 ;
     RECT  36.24 10.213 36.6 22.835 ;
     RECT  18.432 22.165 21.336 23.317 ;
     RECT  36.576 22.835 36.6 23.651 ;
     RECT  18.432 23.317 21.864 23.893 ;
     RECT  18.432 23.893 22.872 24.469 ;
     RECT  24 10.787 24.312 24.469 ;
     RECT  18.432 24.469 24.312 24.997 ;
     RECT  40.2 10.979 42.312 25.045 ;
     RECT  43.344 10.979 48.936 25.045 ;
     RECT  4.176 13.811 4.2 25.285 ;
     RECT  18.432 24.997 24.456 25.861 ;
     RECT  29.4 10.979 29.712 26.245 ;
     RECT  29.04 26.245 29.712 26.819 ;
     RECT  40.2 25.045 48.936 28.261 ;
     RECT  25.824 27.205 25.848 28.309 ;
     RECT  27.12 28.549 27.144 29.029 ;
     RECT  27.12 29.029 27.624 29.605 ;
     RECT  49.968 10.163 53.64 29.699 ;
     RECT  29.4 26.819 29.712 30.421 ;
     RECT  50.016 29.699 53.64 30.421 ;
     RECT  27.12 29.605 27.864 30.709 ;
     RECT  29.28 30.421 29.712 30.709 ;
     RECT  55.152 6.709 62.112 31.379 ;
     RECT  55.584 31.379 62.112 32.579 ;
     RECT  57.984 32.579 62.112 33.157 ;
     RECT  57.984 33.157 62.232 33.203 ;
     RECT  58.128 33.203 62.232 33.299 ;
     RECT  3.744 25.285 4.2 34.259 ;
     RECT  5.664 20.485 6.792 34.501 ;
     RECT  2.208 14.531 2.712 34.741 ;
     RECT  3.744 34.259 3.96 34.741 ;
     RECT  2.208 34.741 3.96 35.219 ;
     RECT  2.256 35.219 3.96 35.363 ;
     RECT  0.096 10.645 0.12 35.509 ;
     RECT  34.8 9.875 35.112 35.845 ;
     RECT  0.096 35.509 0.456 36.085 ;
     RECT  64.608 36.037 64.632 36.275 ;
     RECT  5.376 34.501 6.792 36.613 ;
     RECT  7.8 13.621 9.24 36.613 ;
     RECT  33.552 35.845 35.112 37.525 ;
     RECT  33.552 37.525 35.688 37.573 ;
     RECT  5.376 36.613 9.24 38.533 ;
     RECT  10.56 19.093 17.064 38.533 ;
     RECT  33.552 37.573 36.456 38.533 ;
     RECT  2.304 35.363 3.96 38.725 ;
     RECT  5.376 38.533 17.064 38.725 ;
     RECT  2.304 38.725 17.064 39.253 ;
     RECT  33.552 38.533 36.936 39.301 ;
     RECT  33.552 39.301 37.464 39.877 ;
     RECT  1.92 39.253 17.064 39.923 ;
     RECT  40.2 28.261 48.984 40.405 ;
     RECT  33.552 39.877 37.944 40.693 ;
     RECT  1.92 39.923 6.12 40.981 ;
     RECT  7.2 39.923 17.064 40.981 ;
     RECT  33.552 40.693 38.184 40.981 ;
     RECT  39.456 40.405 48.984 40.981 ;
     RECT  33.552 40.981 48.984 41.075 ;
     RECT  42 41.075 48.984 41.651 ;
     RECT  1.92 40.981 17.064 41.749 ;
     RECT  1.92 41.749 17.304 41.941 ;
     RECT  18.432 25.861 24.84 41.941 ;
     RECT  64.608 42.469 64.632 42.611 ;
     RECT  42.864 41.651 48.984 42.851 ;
     RECT  33.552 41.075 40.824 43.141 ;
     RECT  33.552 43.141 40.968 43.285 ;
     RECT  1.92 41.941 24.84 43.333 ;
     RECT  43.728 42.851 48.984 43.379 ;
     RECT  43.776 43.379 48.984 43.475 ;
     RECT  0.096 36.085 0.696 43.861 ;
     RECT  1.68 43.333 24.84 43.861 ;
     RECT  33.552 43.285 41.688 43.861 ;
     RECT  43.872 43.475 48.984 44.437 ;
     RECT  43.056 44.437 48.984 44.483 ;
     RECT  33.552 43.861 42.024 44.725 ;
     RECT  43.056 44.483 43.848 44.725 ;
     RECT  0.096 43.861 24.84 45.541 ;
     RECT  25.824 28.309 26.136 45.541 ;
     RECT  33.552 44.725 43.848 45.541 ;
     RECT  45.504 44.483 48.984 45.541 ;
     RECT  33.552 45.541 48.984 45.635 ;
     RECT  33.552 45.635 44.616 46.885 ;
     RECT  45.6 45.635 48.984 46.885 ;
     RECT  33.552 46.885 48.984 47.363 ;
     RECT  64.608 47.653 64.632 47.795 ;
     RECT  33.552 47.363 46.728 48.421 ;
     RECT  0.096 45.541 26.136 48.469 ;
     RECT  27.12 30.709 29.712 48.469 ;
     RECT  30.72 32.869 30.744 48.469 ;
     RECT  48.144 47.363 48.984 48.515 ;
     RECT  33.552 48.421 46.968 48.517 ;
     RECT  30.72 48.469 30.888 48.805 ;
     RECT  32.16 33.925 32.184 48.805 ;
     RECT  33.552 48.517 47.016 48.805 ;
     RECT  48.144 48.515 48.888 48.805 ;
     RECT  0.096 48.469 29.712 48.997 ;
     RECT  30.72 48.805 32.184 48.997 ;
     RECT  33.552 48.805 48.888 49.043 ;
     RECT  33.552 49.043 48.264 50.101 ;
     RECT  50.016 30.421 53.688 50.771 ;
     RECT  33.552 50.101 48.696 50.965 ;
     RECT  33.552 50.965 49.8 51.781 ;
     RECT  50.832 50.771 53.688 51.781 ;
     RECT  33.552 51.781 53.688 51.923 ;
     RECT  52.368 51.923 53.688 52.019 ;
     RECT  52.416 52.019 53.688 52.115 ;
     RECT  0.096 48.997 32.184 52.453 ;
     RECT  33.552 51.923 51.312 52.453 ;
     RECT  52.8 52.115 53.688 52.499 ;
     RECT  52.896 52.499 53.688 52.547 ;
     RECT  52.944 52.547 53.688 52.739 ;
     RECT  0.096 52.453 51.312 52.981 ;
     RECT  0.096 52.981 51.72 53.557 ;
     RECT  53.664 52.739 53.688 53.603 ;
     RECT  0.096 53.557 51.96 54.085 ;
     RECT  0.096 54.085 52.056 54.661 ;
     RECT  53.184 54.565 53.208 54.661 ;
     RECT  0.096 54.661 53.208 54.997 ;
     RECT  58.128 33.299 62.112 55.237 ;
     RECT  0.096 54.997 53.352 55.861 ;
     RECT  55.584 32.579 57 55.955 ;
     RECT  0.096 55.861 54.072 56.101 ;
     RECT  64.608 56.245 64.632 56.387 ;
     RECT  56.4 55.955 57 56.627 ;
     RECT  56.4 56.627 56.904 56.675 ;
     RECT  56.4 56.675 56.808 57.157 ;
     RECT  56.16 57.157 56.808 57.541 ;
     RECT  58.128 55.237 62.52 57.589 ;
     RECT  58.128 57.589 62.616 57.925 ;
     RECT  58.128 57.925 62.952 58.211 ;
     RECT  58.32 58.211 62.952 58.739 ;
     RECT  64.608 58.741 64.632 58.931 ;
     RECT  58.368 58.739 62.952 59.363 ;
     RECT  60.096 59.363 62.952 59.555 ;
     RECT  58.368 59.363 59.064 59.891 ;
     RECT  60.192 59.555 62.952 60.325 ;
     RECT  60.192 60.325 63.048 60.661 ;
     RECT  55.68 57.541 56.808 61.043 ;
     RECT  60.048 60.661 63.24 61.381 ;
     RECT  60.048 61.381 63.384 62.101 ;
     RECT  0.096 56.101 54.648 62.149 ;
     RECT  55.68 61.043 56.712 62.149 ;
     RECT  58.368 59.891 58.392 62.149 ;
     RECT  59.712 62.101 63.384 62.149 ;
     RECT  0.096 62.149 63.624 62.245 ;
     RECT  0.096 62.245 64.104 63.253 ;
     RECT  0.096 63.253 64.392 63.877 ;
     RECT  0.096 63.877 64.632 64.739 ;
     RECT  0.192 64.739 64.632 64.784 ;
     RECT  54.312 0.131 54.432 0.132 ;
     RECT  54.552 0.131 54.72 0.132 ;
     RECT  54.84 0.131 54.96 0.132 ;
     RECT  55.08 0.131 55.2 0.132 ;
     RECT  54.264 0.132 55.248 2.291 ;
     RECT  51.24 0.179 52.224 1.763 ;
     RECT  21.672 1.139 22.656 1.763 ;
     RECT  63.624 1.187 64.608 2.963 ;
     RECT  62.616 1.283 63.6 1.763 ;
     RECT  30.264 1.715 31.248 2.339 ;
     RECT  6.504 1.763 7.776 1.811 ;
     RECT  14.616 1.763 15.84 1.811 ;
     RECT  16.632 1.763 17.616 3.443 ;
     RECT  26.472 1.763 27.456 2.579 ;
     RECT  31.512 1.763 33.024 2.483 ;
     RECT  40.632 1.763 42.096 1.859 ;
     RECT  51.24 1.763 52.704 2.151 ;
     RECT  62.52 1.763 63.6 2.963 ;
     RECT  6.504 1.811 7.8 2.339 ;
     RECT  11.592 1.811 12.816 2.915 ;
     RECT  47.208 1.811 48.192 1.859 ;
     RECT  46.68 1.859 48.192 2.387 ;
     RECT  55.272 1.859 56.4 2.291 ;
     RECT  51.312 2.151 52.704 4.019 ;
     RECT  27.48 2.195 28.464 2.291 ;
     RECT  9.048 2.291 10.272 2.915 ;
     RECT  27.48 2.291 28.656 3.683 ;
     RECT  44.424 2.291 45.408 2.435 ;
     RECT  5.592 2.339 7.8 2.821 ;
     RECT  13.512 2.339 14.592 2.915 ;
     RECT  19.416 2.339 20.64 3.443 ;
     RECT  24.312 2.339 25.44 4.019 ;
     RECT  25.464 2.339 26.448 2.579 ;
     RECT  3.672 2.387 4.656 3.877 ;
     RECT  35.352 2.387 36.432 3.443 ;
     RECT  36.792 2.387 38.064 2.963 ;
     RECT  38.088 2.387 39.312 2.483 ;
     RECT  43.416 2.387 44.4 2.435 ;
     RECT  31.512 2.483 31.56 2.861 ;
     RECT  5.592 2.821 7.632 3.397 ;
     RECT  9.048 2.915 10.056 3.877 ;
     RECT  13.512 2.915 13.608 3.877 ;
     RECT  49.224 2.963 50.448 4.115 ;
     RECT  6.072 3.397 7.632 3.733 ;
     RECT  59.544 3.397 60.528 3.781 ;
     RECT  19.176 3.443 20.64 4.019 ;
     RECT  35.352 3.443 36.768 3.877 ;
     RECT  64.608 3.443 64.632 4.645 ;
     RECT  6.072 3.733 7.488 3.925 ;
     RECT  9.048 3.877 10.032 4.259 ;
     RECT  35.4 3.877 36.768 4.165 ;
     RECT  6.216 3.925 7.488 4.501 ;
     RECT  57.528 4.019 58.992 5.749 ;
     RECT  12.816 4.163 13.104 4.643 ;
     RECT  35.736 4.165 36.768 4.595 ;
     RECT  35.736 4.595 36.744 4.741 ;
     RECT  12.816 4.643 13.2 4.933 ;
     RECT  2.112 4.739 2.208 5.845 ;
     RECT  35.832 4.741 36.744 5.701 ;
     RECT  12.072 4.933 13.2 5.075 ;
     RECT  36.504 5.701 36.744 5.749 ;
     RECT  43.128 5.701 44.496 6.181 ;
     RECT  44.52 5.701 45.6 5.893 ;
     RECT  54.288 6.083 54.312 6.229 ;
     RECT  43.368 6.181 44.496 6.229 ;
     RECT  41.016 6.229 42.288 6.805 ;
     RECT  43.464 6.229 44.496 6.709 ;
     RECT  53.64 6.229 55.824 6.709 ;
     RECT  46.152 6.275 46.344 7.237 ;
     RECT  62.112 6.323 63.12 6.419 ;
     RECT  49.512 6.661 50.544 7.621 ;
     RECT  53.64 6.709 55.152 30.421 ;
     RECT  41.208 6.805 42.288 8.485 ;
     RECT  37.512 6.853 38.88 6.901 ;
     RECT  37.608 6.901 38.88 7.619 ;
     RECT  22.824 7.189 24 10.883 ;
     RECT  13.512 7.235 13.608 7.381 ;
     RECT  46.44 7.237 47.904 7.381 ;
     RECT  13.512 7.381 14.88 9.253 ;
     RECT  46.584 7.381 47.904 7.621 ;
     RECT  19.848 7.477 21.12 7.667 ;
     RECT  35.352 7.523 36.336 9.107 ;
     RECT  46.632 7.621 47.904 7.861 ;
     RECT  18.912 7.667 21.12 7.669 ;
     RECT  18.912 7.669 20.304 9.493 ;
     RECT  46.68 7.861 47.904 8.485 ;
     RECT  13.104 7.907 13.2 8.965 ;
     RECT  20.328 7.955 21.144 9.253 ;
     RECT  29.712 7.955 29.976 9.253 ;
     RECT  34.176 8.003 34.272 9.013 ;
     RECT  52.392 8.437 53.616 9.013 ;
     RECT  46.92 8.485 47.904 8.917 ;
     RECT  52.44 9.013 53.616 9.061 ;
     RECT  35.304 9.107 36.336 9.251 ;
     RECT  9.624 9.109 10.8 9.541 ;
     RECT  35.304 9.251 36.432 9.875 ;
     RECT  36.504 9.251 37.584 9.347 ;
     RECT  13.608 9.253 14.832 9.587 ;
     RECT  36.504 9.347 36.6 10.213 ;
     RECT  9.672 9.541 10.8 10.883 ;
     RECT  13.512 9.587 14.88 9.875 ;
     RECT  29.976 9.587 30.888 9.635 ;
     RECT  29.712 9.635 30.888 9.733 ;
     RECT  29.712 9.733 31.296 10.741 ;
     RECT  35.112 9.875 36.432 10.213 ;
     RECT  48.936 10.163 49.968 28.261 ;
     RECT  35.112 10.213 36.24 22.835 ;
     RECT  18.912 10.451 20.016 10.931 ;
     RECT  29.832 10.741 31.296 10.931 ;
     RECT  6.312 10.883 7.392 11.459 ;
     RECT  9.672 10.883 10.848 11.459 ;
     RECT  4.392 10.931 5.376 13.141 ;
     RECT  36.6 10.933 37.728 11.411 ;
     RECT  42.312 10.979 43.344 25.045 ;
     RECT  6.312 11.459 7.44 11.555 ;
     RECT  6.312 11.555 7.8 13.139 ;
     RECT  2.712 12.323 3.744 13.715 ;
     RECT  2.712 13.715 4.176 25.285 ;
     RECT  4.2 13.811 5.664 34.259 ;
     RECT  11.016 13.957 12.144 14.197 ;
     RECT  9.24 14.197 10.56 38.533 ;
     RECT  5.688 15.301 6.768 20.485 ;
     RECT  6.792 15.301 7.8 36.613 ;
     RECT  17.064 19.621 18.48 20.581 ;
     RECT  17.064 20.581 18.432 41.749 ;
     RECT  19.32 21.637 20.688 21.781 ;
     RECT  35.112 22.835 36.576 23.651 ;
     RECT  22.872 23.893 24 24.469 ;
     RECT  2.712 25.285 3.744 34.741 ;
     RECT  24.84 27.205 25.824 45.541 ;
     RECT  48.984 28.261 49.968 29.699 ;
     RECT  26.136 28.549 27.12 48.469 ;
     RECT  48.984 29.699 50.016 48.515 ;
     RECT  27.864 30.421 29.28 30.709 ;
     RECT  53.688 30.421 55.152 31.379 ;
     RECT  57 32.579 57.984 33.203 ;
     RECT  29.712 32.869 30.72 48.997 ;
     RECT  57 33.203 58.128 56.627 ;
     RECT  30.744 33.925 32.16 48.469 ;
     RECT  3.96 34.259 5.664 34.501 ;
     RECT  3.96 34.501 5.376 38.725 ;
     RECT  32.184 35.845 33.552 52.453 ;
     RECT  0.696 39.253 1.92 43.333 ;
     RECT  6.12 39.923 7.2 40.981 ;
     RECT  37.944 40.405 39.456 40.693 ;
     RECT  38.184 40.693 39.456 40.981 ;
     RECT  40.824 41.075 42 41.651 ;
     RECT  40.824 41.651 40.968 43.141 ;
     RECT  17.304 41.749 18.432 41.941 ;
     RECT  0.696 43.333 1.68 43.861 ;
     RECT  43.728 43.379 43.776 43.475 ;
     RECT  43.728 43.475 43.872 44.437 ;
     RECT  42.024 44.437 43.056 44.725 ;
     RECT  43.848 44.483 45.504 45.541 ;
     RECT  44.616 45.635 45.6 46.885 ;
     RECT  46.728 47.363 48.144 48.421 ;
     RECT  46.968 48.421 48.144 48.517 ;
     RECT  30.888 48.469 32.16 48.805 ;
     RECT  48.888 48.515 50.016 49.043 ;
     RECT  47.016 48.517 48.144 48.805 ;
     RECT  48.264 49.043 50.016 50.101 ;
     RECT  48.696 50.101 50.016 50.771 ;
     RECT  48.696 50.771 50.832 50.965 ;
     RECT  49.8 50.965 50.832 51.781 ;
     RECT  51.312 51.923 52.368 52.019 ;
     RECT  51.312 52.019 52.416 52.115 ;
     RECT  51.312 52.115 52.8 52.499 ;
     RECT  51.312 52.499 52.896 52.547 ;
     RECT  51.312 52.547 52.944 52.739 ;
     RECT  51.312 52.739 52.056 52.981 ;
     RECT  51.72 52.981 52.056 53.557 ;
     RECT  51.96 53.557 52.056 54.085 ;
     RECT  52.056 54.565 53.184 54.661 ;
     RECT  54.072 55.861 55.584 55.955 ;
     RECT  54.072 55.955 56.4 56.101 ;
     RECT  54.648 56.101 56.4 57.157 ;
     RECT  56.904 56.627 58.128 56.675 ;
     RECT  56.808 56.675 58.128 58.211 ;
     RECT  54.648 57.157 56.16 57.541 ;
     RECT  54.648 57.541 55.68 62.149 ;
     RECT  56.808 58.211 58.32 58.739 ;
     RECT  59.064 59.363 60.096 59.555 ;
     RECT  59.064 59.555 60.192 59.891 ;
     RECT  60.048 59.891 60.192 60.661 ;
     RECT  56.712 61.043 56.808 62.149 ;
     RECT  58.392 62.101 59.712 62.149 ;
  END
END ot_hgi_b2_dma_groupface_owned
END LIBRARY
